VERSION 5.8 ;
BUSBITCHARS "[]" ;
DIVIDERCHAR "/" ;
UNITS
    DATABASE MICRONS 1000 ;
END UNITS

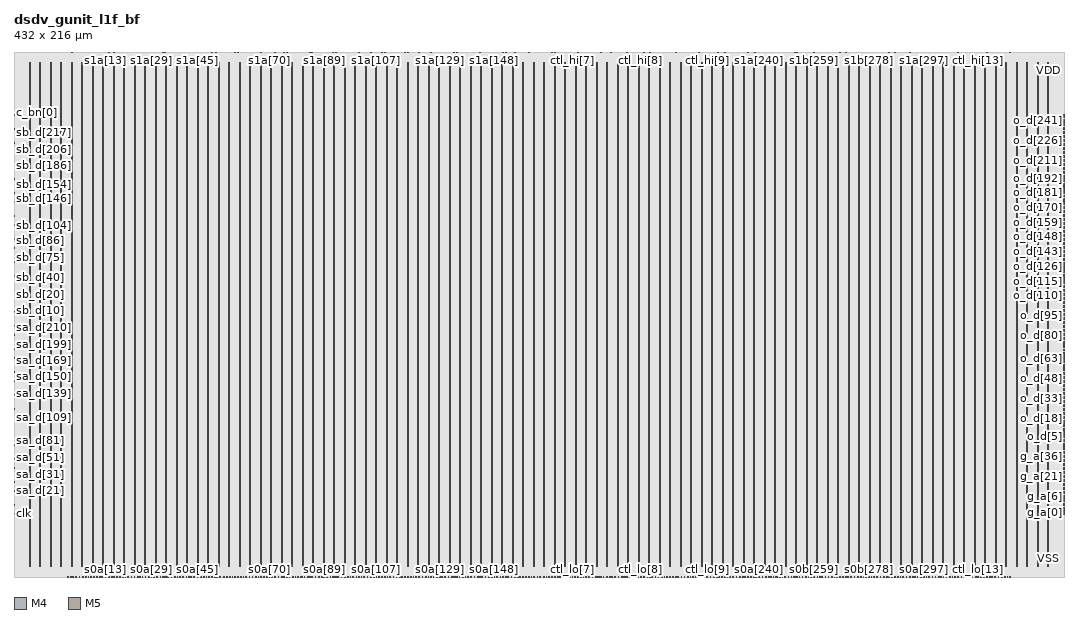
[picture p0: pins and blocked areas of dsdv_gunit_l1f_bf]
MACRO dsdv_gunit_l1f_bf
  FOREIGN dsdv_gunit_l1f_bf 0 0 ;
  CLASS BLOCK ;
  SIZE 432 BY 216 ;
  PIN c_bn[0]
    DIRECTION INPUT ;
    USE SIGNAL ;
    PORT
      LAYER M4 ;
        RECT  0 187.68 0.084 187.704 ;
    END
  END c_bn[0]
  PIN c_bn[1]
    DIRECTION INPUT ;
    USE SIGNAL ;
    PORT
      LAYER M4 ;
        RECT  0 188.064 0.084 188.088 ;
    END
  END c_bn[1]
  PIN c_bn[2]
    DIRECTION INPUT ;
    USE SIGNAL ;
    PORT
      LAYER M4 ;
        RECT  0 188.4 0.084 188.424 ;
    END
  END c_bn[2]
  PIN c_fw
    DIRECTION INPUT ;
    USE SIGNAL ;
    PORT
      LAYER M4 ;
        RECT  0 187.008 0.084 187.032 ;
    END
  END c_fw
  PIN c_go
    DIRECTION INPUT ;
    USE SIGNAL ;
    PORT
      LAYER M4 ;
        RECT  0 186.672 0.084 186.696 ;
    END
  END c_go
  PIN c_l
    DIRECTION INPUT ;
    USE SIGNAL ;
    PORT
      LAYER M4 ;
        RECT  0 187.344 0.084 187.368 ;
    END
  END c_l
  PIN c_lvn[0]
    DIRECTION INPUT ;
    USE SIGNAL ;
    PORT
      LAYER M4 ;
        RECT  0 188.736 0.084 188.76 ;
    END
  END c_lvn[0]
  PIN c_lvn[1]
    DIRECTION INPUT ;
    USE SIGNAL ;
    PORT
      LAYER M4 ;
        RECT  0 189.072 0.084 189.096 ;
    END
  END c_lvn[1]
  PIN c_lvn[2]
    DIRECTION INPUT ;
    USE SIGNAL ;
    PORT
      LAYER M4 ;
        RECT  0 189.408 0.084 189.432 ;
    END
  END c_lvn[2]
  PIN c_lvn[3]
    DIRECTION INPUT ;
    USE SIGNAL ;
    PORT
      LAYER M4 ;
        RECT  0 189.744 0.084 189.768 ;
    END
  END c_lvn[3]
  PIN c_lvn[4]
    DIRECTION INPUT ;
    USE SIGNAL ;
    PORT
      LAYER M4 ;
        RECT  0 190.08 0.084 190.104 ;
    END
  END c_lvn[4]
  PIN clk
    DIRECTION INPUT ;
    USE SIGNAL ;
    PORT
      LAYER M4 ;
        RECT  0 25.92 0.084 25.944 ;
    END
  END clk
  PIN ctl_hi[0]
    DIRECTION OUTPUT ;
    USE SIGNAL ;
    PORT
      LAYER M5 ;
        RECT  35.472 215.916 35.496 216 ;
    END
  END ctl_hi[0]
  PIN ctl_hi[10]
    DIRECTION OUTPUT ;
    USE SIGNAL ;
    PORT
      LAYER M5 ;
        RECT  313.2 215.916 313.224 216 ;
    END
  END ctl_hi[10]
  PIN ctl_hi[11]
    DIRECTION OUTPUT ;
    USE SIGNAL ;
    PORT
      LAYER M5 ;
        RECT  340.944 215.916 340.968 216 ;
    END
  END ctl_hi[11]
  PIN ctl_hi[12]
    DIRECTION OUTPUT ;
    USE SIGNAL ;
    PORT
      LAYER M5 ;
        RECT  368.736 215.916 368.76 216 ;
    END
  END ctl_hi[12]
  PIN ctl_hi[13]
    DIRECTION OUTPUT ;
    USE SIGNAL ;
    PORT
      LAYER M5 ;
        RECT  396.48 215.916 396.504 216 ;
    END
  END ctl_hi[13]
  PIN ctl_hi[1]
    DIRECTION OUTPUT ;
    USE SIGNAL ;
    PORT
      LAYER M5 ;
        RECT  63.264 215.916 63.288 216 ;
    END
  END ctl_hi[1]
  PIN ctl_hi[2]
    DIRECTION OUTPUT ;
    USE SIGNAL ;
    PORT
      LAYER M5 ;
        RECT  91.008 215.916 91.032 216 ;
    END
  END ctl_hi[2]
  PIN ctl_hi[3]
    DIRECTION OUTPUT ;
    USE SIGNAL ;
    PORT
      LAYER M5 ;
        RECT  118.8 215.916 118.824 216 ;
    END
  END ctl_hi[3]
  PIN ctl_hi[4]
    DIRECTION OUTPUT ;
    USE SIGNAL ;
    PORT
      LAYER M5 ;
        RECT  146.544 215.916 146.568 216 ;
    END
  END ctl_hi[4]
  PIN ctl_hi[5]
    DIRECTION OUTPUT ;
    USE SIGNAL ;
    PORT
      LAYER M5 ;
        RECT  174.336 215.916 174.36 216 ;
    END
  END ctl_hi[5]
  PIN ctl_hi[6]
    DIRECTION OUTPUT ;
    USE SIGNAL ;
    PORT
      LAYER M5 ;
        RECT  202.08 215.916 202.104 216 ;
    END
  END ctl_hi[6]
  PIN ctl_hi[7]
    DIRECTION OUTPUT ;
    USE SIGNAL ;
    PORT
      LAYER M5 ;
        RECT  229.872 215.916 229.896 216 ;
    END
  END ctl_hi[7]
  PIN ctl_hi[8]
    DIRECTION OUTPUT ;
    USE SIGNAL ;
    PORT
      LAYER M5 ;
        RECT  257.664 215.916 257.688 216 ;
    END
  END ctl_hi[8]
  PIN ctl_hi[9]
    DIRECTION OUTPUT ;
    USE SIGNAL ;
    PORT
      LAYER M5 ;
        RECT  285.408 215.916 285.432 216 ;
    END
  END ctl_hi[9]
  PIN ctl_lo[0]
    DIRECTION OUTPUT ;
    USE SIGNAL ;
    PORT
      LAYER M5 ;
        RECT  35.472 0 35.496 0.084 ;
    END
  END ctl_lo[0]
  PIN ctl_lo[10]
    DIRECTION OUTPUT ;
    USE SIGNAL ;
    PORT
      LAYER M5 ;
        RECT  313.2 0 313.224 0.084 ;
    END
  END ctl_lo[10]
  PIN ctl_lo[11]
    DIRECTION OUTPUT ;
    USE SIGNAL ;
    PORT
      LAYER M5 ;
        RECT  340.944 0 340.968 0.084 ;
    END
  END ctl_lo[11]
  PIN ctl_lo[12]
    DIRECTION OUTPUT ;
    USE SIGNAL ;
    PORT
      LAYER M5 ;
        RECT  368.736 0 368.76 0.084 ;
    END
  END ctl_lo[12]
  PIN ctl_lo[13]
    DIRECTION OUTPUT ;
    USE SIGNAL ;
    PORT
      LAYER M5 ;
        RECT  396.48 0 396.504 0.084 ;
    END
  END ctl_lo[13]
  PIN ctl_lo[1]
    DIRECTION OUTPUT ;
    USE SIGNAL ;
    PORT
      LAYER M5 ;
        RECT  63.264 0 63.288 0.084 ;
    END
  END ctl_lo[1]
  PIN ctl_lo[2]
    DIRECTION OUTPUT ;
    USE SIGNAL ;
    PORT
      LAYER M5 ;
        RECT  91.008 0 91.032 0.084 ;
    END
  END ctl_lo[2]
  PIN ctl_lo[3]
    DIRECTION OUTPUT ;
    USE SIGNAL ;
    PORT
      LAYER M5 ;
        RECT  118.8 0 118.824 0.084 ;
    END
  END ctl_lo[3]
  PIN ctl_lo[4]
    DIRECTION OUTPUT ;
    USE SIGNAL ;
    PORT
      LAYER M5 ;
        RECT  146.544 0 146.568 0.084 ;
    END
  END ctl_lo[4]
  PIN ctl_lo[5]
    DIRECTION OUTPUT ;
    USE SIGNAL ;
    PORT
      LAYER M5 ;
        RECT  174.336 0 174.36 0.084 ;
    END
  END ctl_lo[5]
  PIN ctl_lo[6]
    DIRECTION OUTPUT ;
    USE SIGNAL ;
    PORT
      LAYER M5 ;
        RECT  202.08 0 202.104 0.084 ;
    END
  END ctl_lo[6]
  PIN ctl_lo[7]
    DIRECTION OUTPUT ;
    USE SIGNAL ;
    PORT
      LAYER M5 ;
        RECT  229.872 0 229.896 0.084 ;
    END
  END ctl_lo[7]
  PIN ctl_lo[8]
    DIRECTION OUTPUT ;
    USE SIGNAL ;
    PORT
      LAYER M5 ;
        RECT  257.664 0 257.688 0.084 ;
    END
  END ctl_lo[8]
  PIN ctl_lo[9]
    DIRECTION OUTPUT ;
    USE SIGNAL ;
    PORT
      LAYER M5 ;
        RECT  285.408 0 285.432 0.084 ;
    END
  END ctl_lo[9]
  PIN g_a[0]
    DIRECTION INPUT ;
    USE SIGNAL ;
    PORT
      LAYER M4 ;
        RECT  431.916 29.76 432 29.784 ;
    END
  END g_a[0]
  PIN g_a[10]
    DIRECTION INPUT ;
    USE SIGNAL ;
    PORT
      LAYER M4 ;
        RECT  431.916 35.28 432 35.304 ;
    END
  END g_a[10]
  PIN g_a[11]
    DIRECTION INPUT ;
    USE SIGNAL ;
    PORT
      LAYER M4 ;
        RECT  431.916 35.808 432 35.832 ;
    END
  END g_a[11]
  PIN g_a[12]
    DIRECTION INPUT ;
    USE SIGNAL ;
    PORT
      LAYER M4 ;
        RECT  431.916 36.384 432 36.408 ;
    END
  END g_a[12]
  PIN g_a[13]
    DIRECTION INPUT ;
    USE SIGNAL ;
    PORT
      LAYER M4 ;
        RECT  431.916 36.912 432 36.936 ;
    END
  END g_a[13]
  PIN g_a[14]
    DIRECTION INPUT ;
    USE SIGNAL ;
    PORT
      LAYER M4 ;
        RECT  431.916 37.488 432 37.512 ;
    END
  END g_a[14]
  PIN g_a[15]
    DIRECTION INPUT ;
    USE SIGNAL ;
    PORT
      LAYER M4 ;
        RECT  431.916 38.016 432 38.04 ;
    END
  END g_a[15]
  PIN g_a[16]
    DIRECTION INPUT ;
    USE SIGNAL ;
    PORT
      LAYER M4 ;
        RECT  431.916 38.592 432 38.616 ;
    END
  END g_a[16]
  PIN g_a[17]
    DIRECTION INPUT ;
    USE SIGNAL ;
    PORT
      LAYER M4 ;
        RECT  431.916 39.12 432 39.144 ;
    END
  END g_a[17]
  PIN g_a[18]
    DIRECTION INPUT ;
    USE SIGNAL ;
    PORT
      LAYER M4 ;
        RECT  431.916 39.696 432 39.72 ;
    END
  END g_a[18]
  PIN g_a[19]
    DIRECTION INPUT ;
    USE SIGNAL ;
    PORT
      LAYER M4 ;
        RECT  431.916 40.224 432 40.248 ;
    END
  END g_a[19]
  PIN g_a[1]
    DIRECTION INPUT ;
    USE SIGNAL ;
    PORT
      LAYER M4 ;
        RECT  431.916 30.336 432 30.36 ;
    END
  END g_a[1]
  PIN g_a[20]
    DIRECTION INPUT ;
    USE SIGNAL ;
    PORT
      LAYER M4 ;
        RECT  431.916 40.8 432 40.824 ;
    END
  END g_a[20]
  PIN g_a[21]
    DIRECTION INPUT ;
    USE SIGNAL ;
    PORT
      LAYER M4 ;
        RECT  431.916 41.328 432 41.352 ;
    END
  END g_a[21]
  PIN g_a[22]
    DIRECTION INPUT ;
    USE SIGNAL ;
    PORT
      LAYER M4 ;
        RECT  431.916 41.904 432 41.928 ;
    END
  END g_a[22]
  PIN g_a[23]
    DIRECTION INPUT ;
    USE SIGNAL ;
    PORT
      LAYER M4 ;
        RECT  431.916 42.432 432 42.456 ;
    END
  END g_a[23]
  PIN g_a[24]
    DIRECTION INPUT ;
    USE SIGNAL ;
    PORT
      LAYER M4 ;
        RECT  431.916 43.008 432 43.032 ;
    END
  END g_a[24]
  PIN g_a[25]
    DIRECTION INPUT ;
    USE SIGNAL ;
    PORT
      LAYER M4 ;
        RECT  431.916 43.536 432 43.56 ;
    END
  END g_a[25]
  PIN g_a[26]
    DIRECTION INPUT ;
    USE SIGNAL ;
    PORT
      LAYER M4 ;
        RECT  431.916 44.064 432 44.088 ;
    END
  END g_a[26]
  PIN g_a[27]
    DIRECTION INPUT ;
    USE SIGNAL ;
    PORT
      LAYER M4 ;
        RECT  431.916 44.64 432 44.664 ;
    END
  END g_a[27]
  PIN g_a[28]
    DIRECTION INPUT ;
    USE SIGNAL ;
    PORT
      LAYER M4 ;
        RECT  431.916 45.168 432 45.192 ;
    END
  END g_a[28]
  PIN g_a[29]
    DIRECTION INPUT ;
    USE SIGNAL ;
    PORT
      LAYER M4 ;
        RECT  431.916 45.744 432 45.768 ;
    END
  END g_a[29]
  PIN g_a[2]
    DIRECTION INPUT ;
    USE SIGNAL ;
    PORT
      LAYER M4 ;
        RECT  431.916 30.864 432 30.888 ;
    END
  END g_a[2]
  PIN g_a[30]
    DIRECTION INPUT ;
    USE SIGNAL ;
    PORT
      LAYER M4 ;
        RECT  431.916 46.272 432 46.296 ;
    END
  END g_a[30]
  PIN g_a[31]
    DIRECTION INPUT ;
    USE SIGNAL ;
    PORT
      LAYER M4 ;
        RECT  431.916 46.848 432 46.872 ;
    END
  END g_a[31]
  PIN g_a[32]
    DIRECTION INPUT ;
    USE SIGNAL ;
    PORT
      LAYER M4 ;
        RECT  431.916 47.376 432 47.4 ;
    END
  END g_a[32]
  PIN g_a[33]
    DIRECTION INPUT ;
    USE SIGNAL ;
    PORT
      LAYER M4 ;
        RECT  431.916 47.952 432 47.976 ;
    END
  END g_a[33]
  PIN g_a[34]
    DIRECTION INPUT ;
    USE SIGNAL ;
    PORT
      LAYER M4 ;
        RECT  431.916 48.48 432 48.504 ;
    END
  END g_a[34]
  PIN g_a[35]
    DIRECTION INPUT ;
    USE SIGNAL ;
    PORT
      LAYER M4 ;
        RECT  431.916 49.056 432 49.08 ;
    END
  END g_a[35]
  PIN g_a[36]
    DIRECTION INPUT ;
    USE SIGNAL ;
    PORT
      LAYER M4 ;
        RECT  431.916 49.584 432 49.608 ;
    END
  END g_a[36]
  PIN g_a[37]
    DIRECTION INPUT ;
    USE SIGNAL ;
    PORT
      LAYER M4 ;
        RECT  431.916 50.16 432 50.184 ;
    END
  END g_a[37]
  PIN g_a[38]
    DIRECTION INPUT ;
    USE SIGNAL ;
    PORT
      LAYER M4 ;
        RECT  431.916 50.688 432 50.712 ;
    END
  END g_a[38]
  PIN g_a[39]
    DIRECTION INPUT ;
    USE SIGNAL ;
    PORT
      LAYER M4 ;
        RECT  431.916 51.264 432 51.288 ;
    END
  END g_a[39]
  PIN g_a[3]
    DIRECTION INPUT ;
    USE SIGNAL ;
    PORT
      LAYER M4 ;
        RECT  431.916 31.44 432 31.464 ;
    END
  END g_a[3]
  PIN g_a[40]
    DIRECTION INPUT ;
    USE SIGNAL ;
    PORT
      LAYER M4 ;
        RECT  431.916 51.792 432 51.816 ;
    END
  END g_a[40]
  PIN g_a[41]
    DIRECTION INPUT ;
    USE SIGNAL ;
    PORT
      LAYER M4 ;
        RECT  431.916 52.368 432 52.392 ;
    END
  END g_a[41]
  PIN g_a[4]
    DIRECTION INPUT ;
    USE SIGNAL ;
    PORT
      LAYER M4 ;
        RECT  431.916 31.968 432 31.992 ;
    END
  END g_a[4]
  PIN g_a[5]
    DIRECTION INPUT ;
    USE SIGNAL ;
    PORT
      LAYER M4 ;
        RECT  431.916 32.496 432 32.52 ;
    END
  END g_a[5]
  PIN g_a[6]
    DIRECTION INPUT ;
    USE SIGNAL ;
    PORT
      LAYER M4 ;
        RECT  431.916 33.072 432 33.096 ;
    END
  END g_a[6]
  PIN g_a[7]
    DIRECTION INPUT ;
    USE SIGNAL ;
    PORT
      LAYER M4 ;
        RECT  431.916 33.6 432 33.624 ;
    END
  END g_a[7]
  PIN g_a[8]
    DIRECTION INPUT ;
    USE SIGNAL ;
    PORT
      LAYER M4 ;
        RECT  431.916 34.176 432 34.2 ;
    END
  END g_a[8]
  PIN g_a[9]
    DIRECTION INPUT ;
    USE SIGNAL ;
    PORT
      LAYER M4 ;
        RECT  431.916 34.704 432 34.728 ;
    END
  END g_a[9]
  PIN g_go
    DIRECTION INPUT ;
    USE SIGNAL ;
    PORT
      LAYER M4 ;
        RECT  431.916 25.92 432 25.944 ;
    END
  END g_go
  PIN g_hit[0]
    DIRECTION INPUT ;
    USE SIGNAL ;
    PORT
      LAYER M4 ;
        RECT  431.916 26.448 432 26.472 ;
    END
  END g_hit[0]
  PIN g_hit[1]
    DIRECTION INPUT ;
    USE SIGNAL ;
    PORT
      LAYER M4 ;
        RECT  431.916 27.024 432 27.048 ;
    END
  END g_hit[1]
  PIN g_hit[2]
    DIRECTION INPUT ;
    USE SIGNAL ;
    PORT
      LAYER M4 ;
        RECT  431.916 27.552 432 27.576 ;
    END
  END g_hit[2]
  PIN g_hit[3]
    DIRECTION INPUT ;
    USE SIGNAL ;
    PORT
      LAYER M4 ;
        RECT  431.916 28.128 432 28.152 ;
    END
  END g_hit[3]
  PIN g_hit[4]
    DIRECTION INPUT ;
    USE SIGNAL ;
    PORT
      LAYER M4 ;
        RECT  431.916 28.656 432 28.68 ;
    END
  END g_hit[4]
  PIN g_hit[5]
    DIRECTION INPUT ;
    USE SIGNAL ;
    PORT
      LAYER M4 ;
        RECT  431.916 29.232 432 29.256 ;
    END
  END g_hit[5]
  PIN o_d[0]
    DIRECTION OUTPUT ;
    USE SIGNAL ;
    PORT
      LAYER M4 ;
        RECT  431.916 55.104 432 55.128 ;
    END
  END o_d[0]
  PIN o_d[100]
    DIRECTION OUTPUT ;
    USE SIGNAL ;
    PORT
      LAYER M4 ;
        RECT  431.916 110.208 432 110.232 ;
    END
  END o_d[100]
  PIN o_d[101]
    DIRECTION OUTPUT ;
    USE SIGNAL ;
    PORT
      LAYER M4 ;
        RECT  431.916 110.736 432 110.76 ;
    END
  END o_d[101]
  PIN o_d[102]
    DIRECTION OUTPUT ;
    USE SIGNAL ;
    PORT
      LAYER M4 ;
        RECT  431.916 111.312 432 111.336 ;
    END
  END o_d[102]
  PIN o_d[103]
    DIRECTION OUTPUT ;
    USE SIGNAL ;
    PORT
      LAYER M4 ;
        RECT  431.916 111.84 432 111.864 ;
    END
  END o_d[103]
  PIN o_d[104]
    DIRECTION OUTPUT ;
    USE SIGNAL ;
    PORT
      LAYER M4 ;
        RECT  431.916 112.416 432 112.44 ;
    END
  END o_d[104]
  PIN o_d[105]
    DIRECTION OUTPUT ;
    USE SIGNAL ;
    PORT
      LAYER M4 ;
        RECT  431.916 112.944 432 112.968 ;
    END
  END o_d[105]
  PIN o_d[106]
    DIRECTION OUTPUT ;
    USE SIGNAL ;
    PORT
      LAYER M4 ;
        RECT  431.916 113.52 432 113.544 ;
    END
  END o_d[106]
  PIN o_d[107]
    DIRECTION OUTPUT ;
    USE SIGNAL ;
    PORT
      LAYER M4 ;
        RECT  431.916 114.048 432 114.072 ;
    END
  END o_d[107]
  PIN o_d[108]
    DIRECTION OUTPUT ;
    USE SIGNAL ;
    PORT
      LAYER M4 ;
        RECT  431.916 114.576 432 114.6 ;
    END
  END o_d[108]
  PIN o_d[109]
    DIRECTION OUTPUT ;
    USE SIGNAL ;
    PORT
      LAYER M4 ;
        RECT  431.916 115.152 432 115.176 ;
    END
  END o_d[109]
  PIN o_d[10]
    DIRECTION OUTPUT ;
    USE SIGNAL ;
    PORT
      LAYER M4 ;
        RECT  431.916 60.624 432 60.648 ;
    END
  END o_d[10]
  PIN o_d[110]
    DIRECTION OUTPUT ;
    USE SIGNAL ;
    PORT
      LAYER M4 ;
        RECT  431.916 115.68 432 115.704 ;
    END
  END o_d[110]
  PIN o_d[111]
    DIRECTION OUTPUT ;
    USE SIGNAL ;
    PORT
      LAYER M4 ;
        RECT  431.916 116.256 432 116.28 ;
    END
  END o_d[111]
  PIN o_d[112]
    DIRECTION OUTPUT ;
    USE SIGNAL ;
    PORT
      LAYER M4 ;
        RECT  431.916 116.784 432 116.808 ;
    END
  END o_d[112]
  PIN o_d[113]
    DIRECTION OUTPUT ;
    USE SIGNAL ;
    PORT
      LAYER M4 ;
        RECT  431.916 117.36 432 117.384 ;
    END
  END o_d[113]
  PIN o_d[114]
    DIRECTION OUTPUT ;
    USE SIGNAL ;
    PORT
      LAYER M4 ;
        RECT  431.916 117.888 432 117.912 ;
    END
  END o_d[114]
  PIN o_d[115]
    DIRECTION OUTPUT ;
    USE SIGNAL ;
    PORT
      LAYER M4 ;
        RECT  431.916 118.464 432 118.488 ;
    END
  END o_d[115]
  PIN o_d[116]
    DIRECTION OUTPUT ;
    USE SIGNAL ;
    PORT
      LAYER M4 ;
        RECT  431.916 118.992 432 119.016 ;
    END
  END o_d[116]
  PIN o_d[117]
    DIRECTION OUTPUT ;
    USE SIGNAL ;
    PORT
      LAYER M4 ;
        RECT  431.916 119.568 432 119.592 ;
    END
  END o_d[117]
  PIN o_d[118]
    DIRECTION OUTPUT ;
    USE SIGNAL ;
    PORT
      LAYER M4 ;
        RECT  431.916 120.096 432 120.12 ;
    END
  END o_d[118]
  PIN o_d[119]
    DIRECTION OUTPUT ;
    USE SIGNAL ;
    PORT
      LAYER M4 ;
        RECT  431.916 120.672 432 120.696 ;
    END
  END o_d[119]
  PIN o_d[11]
    DIRECTION OUTPUT ;
    USE SIGNAL ;
    PORT
      LAYER M4 ;
        RECT  431.916 61.152 432 61.176 ;
    END
  END o_d[11]
  PIN o_d[120]
    DIRECTION OUTPUT ;
    USE SIGNAL ;
    PORT
      LAYER M4 ;
        RECT  431.916 121.2 432 121.224 ;
    END
  END o_d[120]
  PIN o_d[121]
    DIRECTION OUTPUT ;
    USE SIGNAL ;
    PORT
      LAYER M4 ;
        RECT  431.916 121.776 432 121.8 ;
    END
  END o_d[121]
  PIN o_d[122]
    DIRECTION OUTPUT ;
    USE SIGNAL ;
    PORT
      LAYER M4 ;
        RECT  431.916 122.304 432 122.328 ;
    END
  END o_d[122]
  PIN o_d[123]
    DIRECTION OUTPUT ;
    USE SIGNAL ;
    PORT
      LAYER M4 ;
        RECT  431.916 122.88 432 122.904 ;
    END
  END o_d[123]
  PIN o_d[124]
    DIRECTION OUTPUT ;
    USE SIGNAL ;
    PORT
      LAYER M4 ;
        RECT  431.916 123.408 432 123.432 ;
    END
  END o_d[124]
  PIN o_d[125]
    DIRECTION OUTPUT ;
    USE SIGNAL ;
    PORT
      LAYER M4 ;
        RECT  431.916 123.984 432 124.008 ;
    END
  END o_d[125]
  PIN o_d[126]
    DIRECTION OUTPUT ;
    USE SIGNAL ;
    PORT
      LAYER M4 ;
        RECT  431.916 124.512 432 124.536 ;
    END
  END o_d[126]
  PIN o_d[127]
    DIRECTION OUTPUT ;
    USE SIGNAL ;
    PORT
      LAYER M4 ;
        RECT  431.916 125.088 432 125.112 ;
    END
  END o_d[127]
  PIN o_d[128]
    DIRECTION OUTPUT ;
    USE SIGNAL ;
    PORT
      LAYER M4 ;
        RECT  431.916 125.616 432 125.64 ;
    END
  END o_d[128]
  PIN o_d[129]
    DIRECTION OUTPUT ;
    USE SIGNAL ;
    PORT
      LAYER M4 ;
        RECT  431.916 126.144 432 126.168 ;
    END
  END o_d[129]
  PIN o_d[12]
    DIRECTION OUTPUT ;
    USE SIGNAL ;
    PORT
      LAYER M4 ;
        RECT  431.916 61.728 432 61.752 ;
    END
  END o_d[12]
  PIN o_d[130]
    DIRECTION OUTPUT ;
    USE SIGNAL ;
    PORT
      LAYER M4 ;
        RECT  431.916 126.72 432 126.744 ;
    END
  END o_d[130]
  PIN o_d[131]
    DIRECTION OUTPUT ;
    USE SIGNAL ;
    PORT
      LAYER M4 ;
        RECT  431.916 127.248 432 127.272 ;
    END
  END o_d[131]
  PIN o_d[132]
    DIRECTION OUTPUT ;
    USE SIGNAL ;
    PORT
      LAYER M4 ;
        RECT  431.916 127.824 432 127.848 ;
    END
  END o_d[132]
  PIN o_d[133]
    DIRECTION OUTPUT ;
    USE SIGNAL ;
    PORT
      LAYER M4 ;
        RECT  431.916 128.352 432 128.376 ;
    END
  END o_d[133]
  PIN o_d[134]
    DIRECTION OUTPUT ;
    USE SIGNAL ;
    PORT
      LAYER M4 ;
        RECT  431.916 128.928 432 128.952 ;
    END
  END o_d[134]
  PIN o_d[135]
    DIRECTION OUTPUT ;
    USE SIGNAL ;
    PORT
      LAYER M4 ;
        RECT  431.916 129.456 432 129.48 ;
    END
  END o_d[135]
  PIN o_d[136]
    DIRECTION OUTPUT ;
    USE SIGNAL ;
    PORT
      LAYER M4 ;
        RECT  431.916 130.032 432 130.056 ;
    END
  END o_d[136]
  PIN o_d[137]
    DIRECTION OUTPUT ;
    USE SIGNAL ;
    PORT
      LAYER M4 ;
        RECT  431.916 130.56 432 130.584 ;
    END
  END o_d[137]
  PIN o_d[138]
    DIRECTION OUTPUT ;
    USE SIGNAL ;
    PORT
      LAYER M4 ;
        RECT  431.916 131.136 432 131.16 ;
    END
  END o_d[138]
  PIN o_d[139]
    DIRECTION OUTPUT ;
    USE SIGNAL ;
    PORT
      LAYER M4 ;
        RECT  431.916 131.664 432 131.688 ;
    END
  END o_d[139]
  PIN o_d[13]
    DIRECTION OUTPUT ;
    USE SIGNAL ;
    PORT
      LAYER M4 ;
        RECT  431.916 62.256 432 62.28 ;
    END
  END o_d[13]
  PIN o_d[140]
    DIRECTION OUTPUT ;
    USE SIGNAL ;
    PORT
      LAYER M4 ;
        RECT  431.916 132.24 432 132.264 ;
    END
  END o_d[140]
  PIN o_d[141]
    DIRECTION OUTPUT ;
    USE SIGNAL ;
    PORT
      LAYER M4 ;
        RECT  431.916 132.768 432 132.792 ;
    END
  END o_d[141]
  PIN o_d[142]
    DIRECTION OUTPUT ;
    USE SIGNAL ;
    PORT
      LAYER M4 ;
        RECT  431.916 133.344 432 133.368 ;
    END
  END o_d[142]
  PIN o_d[143]
    DIRECTION OUTPUT ;
    USE SIGNAL ;
    PORT
      LAYER M4 ;
        RECT  431.916 133.872 432 133.896 ;
    END
  END o_d[143]
  PIN o_d[144]
    DIRECTION OUTPUT ;
    USE SIGNAL ;
    PORT
      LAYER M4 ;
        RECT  431.916 134.448 432 134.472 ;
    END
  END o_d[144]
  PIN o_d[145]
    DIRECTION OUTPUT ;
    USE SIGNAL ;
    PORT
      LAYER M4 ;
        RECT  431.916 134.976 432 135 ;
    END
  END o_d[145]
  PIN o_d[146]
    DIRECTION OUTPUT ;
    USE SIGNAL ;
    PORT
      LAYER M4 ;
        RECT  431.916 135.552 432 135.576 ;
    END
  END o_d[146]
  PIN o_d[147]
    DIRECTION OUTPUT ;
    USE SIGNAL ;
    PORT
      LAYER M4 ;
        RECT  431.916 136.08 432 136.104 ;
    END
  END o_d[147]
  PIN o_d[148]
    DIRECTION OUTPUT ;
    USE SIGNAL ;
    PORT
      LAYER M4 ;
        RECT  431.916 136.656 432 136.68 ;
    END
  END o_d[148]
  PIN o_d[149]
    DIRECTION OUTPUT ;
    USE SIGNAL ;
    PORT
      LAYER M4 ;
        RECT  431.916 137.184 432 137.208 ;
    END
  END o_d[149]
  PIN o_d[14]
    DIRECTION OUTPUT ;
    USE SIGNAL ;
    PORT
      LAYER M4 ;
        RECT  431.916 62.832 432 62.856 ;
    END
  END o_d[14]
  PIN o_d[150]
    DIRECTION OUTPUT ;
    USE SIGNAL ;
    PORT
      LAYER M4 ;
        RECT  431.916 137.712 432 137.736 ;
    END
  END o_d[150]
  PIN o_d[151]
    DIRECTION OUTPUT ;
    USE SIGNAL ;
    PORT
      LAYER M4 ;
        RECT  431.916 138.288 432 138.312 ;
    END
  END o_d[151]
  PIN o_d[152]
    DIRECTION OUTPUT ;
    USE SIGNAL ;
    PORT
      LAYER M4 ;
        RECT  431.916 138.816 432 138.84 ;
    END
  END o_d[152]
  PIN o_d[153]
    DIRECTION OUTPUT ;
    USE SIGNAL ;
    PORT
      LAYER M4 ;
        RECT  431.916 139.392 432 139.416 ;
    END
  END o_d[153]
  PIN o_d[154]
    DIRECTION OUTPUT ;
    USE SIGNAL ;
    PORT
      LAYER M4 ;
        RECT  431.916 139.92 432 139.944 ;
    END
  END o_d[154]
  PIN o_d[155]
    DIRECTION OUTPUT ;
    USE SIGNAL ;
    PORT
      LAYER M4 ;
        RECT  431.916 140.496 432 140.52 ;
    END
  END o_d[155]
  PIN o_d[156]
    DIRECTION OUTPUT ;
    USE SIGNAL ;
    PORT
      LAYER M4 ;
        RECT  431.916 141.024 432 141.048 ;
    END
  END o_d[156]
  PIN o_d[157]
    DIRECTION OUTPUT ;
    USE SIGNAL ;
    PORT
      LAYER M4 ;
        RECT  431.916 141.6 432 141.624 ;
    END
  END o_d[157]
  PIN o_d[158]
    DIRECTION OUTPUT ;
    USE SIGNAL ;
    PORT
      LAYER M4 ;
        RECT  431.916 142.128 432 142.152 ;
    END
  END o_d[158]
  PIN o_d[159]
    DIRECTION OUTPUT ;
    USE SIGNAL ;
    PORT
      LAYER M4 ;
        RECT  431.916 142.704 432 142.728 ;
    END
  END o_d[159]
  PIN o_d[15]
    DIRECTION OUTPUT ;
    USE SIGNAL ;
    PORT
      LAYER M4 ;
        RECT  431.916 63.36 432 63.384 ;
    END
  END o_d[15]
  PIN o_d[160]
    DIRECTION OUTPUT ;
    USE SIGNAL ;
    PORT
      LAYER M4 ;
        RECT  431.916 143.232 432 143.256 ;
    END
  END o_d[160]
  PIN o_d[161]
    DIRECTION OUTPUT ;
    USE SIGNAL ;
    PORT
      LAYER M4 ;
        RECT  431.916 143.808 432 143.832 ;
    END
  END o_d[161]
  PIN o_d[162]
    DIRECTION OUTPUT ;
    USE SIGNAL ;
    PORT
      LAYER M4 ;
        RECT  431.916 144.336 432 144.36 ;
    END
  END o_d[162]
  PIN o_d[163]
    DIRECTION OUTPUT ;
    USE SIGNAL ;
    PORT
      LAYER M4 ;
        RECT  431.916 144.912 432 144.936 ;
    END
  END o_d[163]
  PIN o_d[164]
    DIRECTION OUTPUT ;
    USE SIGNAL ;
    PORT
      LAYER M4 ;
        RECT  431.916 145.44 432 145.464 ;
    END
  END o_d[164]
  PIN o_d[165]
    DIRECTION OUTPUT ;
    USE SIGNAL ;
    PORT
      LAYER M4 ;
        RECT  431.916 146.016 432 146.04 ;
    END
  END o_d[165]
  PIN o_d[166]
    DIRECTION OUTPUT ;
    USE SIGNAL ;
    PORT
      LAYER M4 ;
        RECT  431.916 146.544 432 146.568 ;
    END
  END o_d[166]
  PIN o_d[167]
    DIRECTION OUTPUT ;
    USE SIGNAL ;
    PORT
      LAYER M4 ;
        RECT  431.916 147.12 432 147.144 ;
    END
  END o_d[167]
  PIN o_d[168]
    DIRECTION OUTPUT ;
    USE SIGNAL ;
    PORT
      LAYER M4 ;
        RECT  431.916 147.648 432 147.672 ;
    END
  END o_d[168]
  PIN o_d[169]
    DIRECTION OUTPUT ;
    USE SIGNAL ;
    PORT
      LAYER M4 ;
        RECT  431.916 148.224 432 148.248 ;
    END
  END o_d[169]
  PIN o_d[16]
    DIRECTION OUTPUT ;
    USE SIGNAL ;
    PORT
      LAYER M4 ;
        RECT  431.916 63.936 432 63.96 ;
    END
  END o_d[16]
  PIN o_d[170]
    DIRECTION OUTPUT ;
    USE SIGNAL ;
    PORT
      LAYER M4 ;
        RECT  431.916 148.752 432 148.776 ;
    END
  END o_d[170]
  PIN o_d[171]
    DIRECTION OUTPUT ;
    USE SIGNAL ;
    PORT
      LAYER M4 ;
        RECT  431.916 149.28 432 149.304 ;
    END
  END o_d[171]
  PIN o_d[172]
    DIRECTION OUTPUT ;
    USE SIGNAL ;
    PORT
      LAYER M4 ;
        RECT  431.916 149.856 432 149.88 ;
    END
  END o_d[172]
  PIN o_d[173]
    DIRECTION OUTPUT ;
    USE SIGNAL ;
    PORT
      LAYER M4 ;
        RECT  431.916 150.384 432 150.408 ;
    END
  END o_d[173]
  PIN o_d[174]
    DIRECTION OUTPUT ;
    USE SIGNAL ;
    PORT
      LAYER M4 ;
        RECT  431.916 150.96 432 150.984 ;
    END
  END o_d[174]
  PIN o_d[175]
    DIRECTION OUTPUT ;
    USE SIGNAL ;
    PORT
      LAYER M4 ;
        RECT  431.916 151.488 432 151.512 ;
    END
  END o_d[175]
  PIN o_d[176]
    DIRECTION OUTPUT ;
    USE SIGNAL ;
    PORT
      LAYER M4 ;
        RECT  431.916 152.064 432 152.088 ;
    END
  END o_d[176]
  PIN o_d[177]
    DIRECTION OUTPUT ;
    USE SIGNAL ;
    PORT
      LAYER M4 ;
        RECT  431.916 152.592 432 152.616 ;
    END
  END o_d[177]
  PIN o_d[178]
    DIRECTION OUTPUT ;
    USE SIGNAL ;
    PORT
      LAYER M4 ;
        RECT  431.916 153.168 432 153.192 ;
    END
  END o_d[178]
  PIN o_d[179]
    DIRECTION OUTPUT ;
    USE SIGNAL ;
    PORT
      LAYER M4 ;
        RECT  431.916 153.696 432 153.72 ;
    END
  END o_d[179]
  PIN o_d[17]
    DIRECTION OUTPUT ;
    USE SIGNAL ;
    PORT
      LAYER M4 ;
        RECT  431.916 64.464 432 64.488 ;
    END
  END o_d[17]
  PIN o_d[180]
    DIRECTION OUTPUT ;
    USE SIGNAL ;
    PORT
      LAYER M4 ;
        RECT  431.916 154.272 432 154.296 ;
    END
  END o_d[180]
  PIN o_d[181]
    DIRECTION OUTPUT ;
    USE SIGNAL ;
    PORT
      LAYER M4 ;
        RECT  431.916 154.8 432 154.824 ;
    END
  END o_d[181]
  PIN o_d[182]
    DIRECTION OUTPUT ;
    USE SIGNAL ;
    PORT
      LAYER M4 ;
        RECT  431.916 155.376 432 155.4 ;
    END
  END o_d[182]
  PIN o_d[183]
    DIRECTION OUTPUT ;
    USE SIGNAL ;
    PORT
      LAYER M4 ;
        RECT  431.916 155.904 432 155.928 ;
    END
  END o_d[183]
  PIN o_d[184]
    DIRECTION OUTPUT ;
    USE SIGNAL ;
    PORT
      LAYER M4 ;
        RECT  431.916 156.48 432 156.504 ;
    END
  END o_d[184]
  PIN o_d[185]
    DIRECTION OUTPUT ;
    USE SIGNAL ;
    PORT
      LAYER M4 ;
        RECT  431.916 157.008 432 157.032 ;
    END
  END o_d[185]
  PIN o_d[186]
    DIRECTION OUTPUT ;
    USE SIGNAL ;
    PORT
      LAYER M4 ;
        RECT  431.916 157.584 432 157.608 ;
    END
  END o_d[186]
  PIN o_d[187]
    DIRECTION OUTPUT ;
    USE SIGNAL ;
    PORT
      LAYER M4 ;
        RECT  431.916 158.112 432 158.136 ;
    END
  END o_d[187]
  PIN o_d[188]
    DIRECTION OUTPUT ;
    USE SIGNAL ;
    PORT
      LAYER M4 ;
        RECT  431.916 158.688 432 158.712 ;
    END
  END o_d[188]
  PIN o_d[189]
    DIRECTION OUTPUT ;
    USE SIGNAL ;
    PORT
      LAYER M4 ;
        RECT  431.916 159.216 432 159.24 ;
    END
  END o_d[189]
  PIN o_d[18]
    DIRECTION OUTPUT ;
    USE SIGNAL ;
    PORT
      LAYER M4 ;
        RECT  431.916 65.04 432 65.064 ;
    END
  END o_d[18]
  PIN o_d[190]
    DIRECTION OUTPUT ;
    USE SIGNAL ;
    PORT
      LAYER M4 ;
        RECT  431.916 159.792 432 159.816 ;
    END
  END o_d[190]
  PIN o_d[191]
    DIRECTION OUTPUT ;
    USE SIGNAL ;
    PORT
      LAYER M4 ;
        RECT  431.916 160.32 432 160.344 ;
    END
  END o_d[191]
  PIN o_d[192]
    DIRECTION OUTPUT ;
    USE SIGNAL ;
    PORT
      LAYER M4 ;
        RECT  431.916 160.848 432 160.872 ;
    END
  END o_d[192]
  PIN o_d[193]
    DIRECTION OUTPUT ;
    USE SIGNAL ;
    PORT
      LAYER M4 ;
        RECT  431.916 161.424 432 161.448 ;
    END
  END o_d[193]
  PIN o_d[194]
    DIRECTION OUTPUT ;
    USE SIGNAL ;
    PORT
      LAYER M4 ;
        RECT  431.916 161.952 432 161.976 ;
    END
  END o_d[194]
  PIN o_d[195]
    DIRECTION OUTPUT ;
    USE SIGNAL ;
    PORT
      LAYER M4 ;
        RECT  431.916 162.528 432 162.552 ;
    END
  END o_d[195]
  PIN o_d[196]
    DIRECTION OUTPUT ;
    USE SIGNAL ;
    PORT
      LAYER M4 ;
        RECT  431.916 163.056 432 163.08 ;
    END
  END o_d[196]
  PIN o_d[197]
    DIRECTION OUTPUT ;
    USE SIGNAL ;
    PORT
      LAYER M4 ;
        RECT  431.916 163.632 432 163.656 ;
    END
  END o_d[197]
  PIN o_d[198]
    DIRECTION OUTPUT ;
    USE SIGNAL ;
    PORT
      LAYER M4 ;
        RECT  431.916 164.16 432 164.184 ;
    END
  END o_d[198]
  PIN o_d[199]
    DIRECTION OUTPUT ;
    USE SIGNAL ;
    PORT
      LAYER M4 ;
        RECT  431.916 164.736 432 164.76 ;
    END
  END o_d[199]
  PIN o_d[19]
    DIRECTION OUTPUT ;
    USE SIGNAL ;
    PORT
      LAYER M4 ;
        RECT  431.916 65.568 432 65.592 ;
    END
  END o_d[19]
  PIN o_d[1]
    DIRECTION OUTPUT ;
    USE SIGNAL ;
    PORT
      LAYER M4 ;
        RECT  431.916 55.632 432 55.656 ;
    END
  END o_d[1]
  PIN o_d[200]
    DIRECTION OUTPUT ;
    USE SIGNAL ;
    PORT
      LAYER M4 ;
        RECT  431.916 165.264 432 165.288 ;
    END
  END o_d[200]
  PIN o_d[201]
    DIRECTION OUTPUT ;
    USE SIGNAL ;
    PORT
      LAYER M4 ;
        RECT  431.916 165.84 432 165.864 ;
    END
  END o_d[201]
  PIN o_d[202]
    DIRECTION OUTPUT ;
    USE SIGNAL ;
    PORT
      LAYER M4 ;
        RECT  431.916 166.368 432 166.392 ;
    END
  END o_d[202]
  PIN o_d[203]
    DIRECTION OUTPUT ;
    USE SIGNAL ;
    PORT
      LAYER M4 ;
        RECT  431.916 166.944 432 166.968 ;
    END
  END o_d[203]
  PIN o_d[204]
    DIRECTION OUTPUT ;
    USE SIGNAL ;
    PORT
      LAYER M4 ;
        RECT  431.916 167.472 432 167.496 ;
    END
  END o_d[204]
  PIN o_d[205]
    DIRECTION OUTPUT ;
    USE SIGNAL ;
    PORT
      LAYER M4 ;
        RECT  431.916 168.048 432 168.072 ;
    END
  END o_d[205]
  PIN o_d[206]
    DIRECTION OUTPUT ;
    USE SIGNAL ;
    PORT
      LAYER M4 ;
        RECT  431.916 168.576 432 168.6 ;
    END
  END o_d[206]
  PIN o_d[207]
    DIRECTION OUTPUT ;
    USE SIGNAL ;
    PORT
      LAYER M4 ;
        RECT  431.916 169.152 432 169.176 ;
    END
  END o_d[207]
  PIN o_d[208]
    DIRECTION OUTPUT ;
    USE SIGNAL ;
    PORT
      LAYER M4 ;
        RECT  431.916 169.68 432 169.704 ;
    END
  END o_d[208]
  PIN o_d[209]
    DIRECTION OUTPUT ;
    USE SIGNAL ;
    PORT
      LAYER M4 ;
        RECT  431.916 170.256 432 170.28 ;
    END
  END o_d[209]
  PIN o_d[20]
    DIRECTION OUTPUT ;
    USE SIGNAL ;
    PORT
      LAYER M4 ;
        RECT  431.916 66.144 432 66.168 ;
    END
  END o_d[20]
  PIN o_d[210]
    DIRECTION OUTPUT ;
    USE SIGNAL ;
    PORT
      LAYER M4 ;
        RECT  431.916 170.784 432 170.808 ;
    END
  END o_d[210]
  PIN o_d[211]
    DIRECTION OUTPUT ;
    USE SIGNAL ;
    PORT
      LAYER M4 ;
        RECT  431.916 171.36 432 171.384 ;
    END
  END o_d[211]
  PIN o_d[212]
    DIRECTION OUTPUT ;
    USE SIGNAL ;
    PORT
      LAYER M4 ;
        RECT  431.916 171.888 432 171.912 ;
    END
  END o_d[212]
  PIN o_d[213]
    DIRECTION OUTPUT ;
    USE SIGNAL ;
    PORT
      LAYER M4 ;
        RECT  431.916 172.464 432 172.488 ;
    END
  END o_d[213]
  PIN o_d[214]
    DIRECTION OUTPUT ;
    USE SIGNAL ;
    PORT
      LAYER M4 ;
        RECT  431.916 172.992 432 173.016 ;
    END
  END o_d[214]
  PIN o_d[215]
    DIRECTION OUTPUT ;
    USE SIGNAL ;
    PORT
      LAYER M4 ;
        RECT  431.916 173.52 432 173.544 ;
    END
  END o_d[215]
  PIN o_d[216]
    DIRECTION OUTPUT ;
    USE SIGNAL ;
    PORT
      LAYER M4 ;
        RECT  431.916 174.096 432 174.12 ;
    END
  END o_d[216]
  PIN o_d[217]
    DIRECTION OUTPUT ;
    USE SIGNAL ;
    PORT
      LAYER M4 ;
        RECT  431.916 174.624 432 174.648 ;
    END
  END o_d[217]
  PIN o_d[218]
    DIRECTION OUTPUT ;
    USE SIGNAL ;
    PORT
      LAYER M4 ;
        RECT  431.916 175.2 432 175.224 ;
    END
  END o_d[218]
  PIN o_d[219]
    DIRECTION OUTPUT ;
    USE SIGNAL ;
    PORT
      LAYER M4 ;
        RECT  431.916 175.728 432 175.752 ;
    END
  END o_d[219]
  PIN o_d[21]
    DIRECTION OUTPUT ;
    USE SIGNAL ;
    PORT
      LAYER M4 ;
        RECT  431.916 66.672 432 66.696 ;
    END
  END o_d[21]
  PIN o_d[220]
    DIRECTION OUTPUT ;
    USE SIGNAL ;
    PORT
      LAYER M4 ;
        RECT  431.916 176.304 432 176.328 ;
    END
  END o_d[220]
  PIN o_d[221]
    DIRECTION OUTPUT ;
    USE SIGNAL ;
    PORT
      LAYER M4 ;
        RECT  431.916 176.832 432 176.856 ;
    END
  END o_d[221]
  PIN o_d[222]
    DIRECTION OUTPUT ;
    USE SIGNAL ;
    PORT
      LAYER M4 ;
        RECT  431.916 177.408 432 177.432 ;
    END
  END o_d[222]
  PIN o_d[223]
    DIRECTION OUTPUT ;
    USE SIGNAL ;
    PORT
      LAYER M4 ;
        RECT  431.916 177.936 432 177.96 ;
    END
  END o_d[223]
  PIN o_d[224]
    DIRECTION OUTPUT ;
    USE SIGNAL ;
    PORT
      LAYER M4 ;
        RECT  431.916 178.512 432 178.536 ;
    END
  END o_d[224]
  PIN o_d[225]
    DIRECTION OUTPUT ;
    USE SIGNAL ;
    PORT
      LAYER M4 ;
        RECT  431.916 179.04 432 179.064 ;
    END
  END o_d[225]
  PIN o_d[226]
    DIRECTION OUTPUT ;
    USE SIGNAL ;
    PORT
      LAYER M4 ;
        RECT  431.916 179.616 432 179.64 ;
    END
  END o_d[226]
  PIN o_d[227]
    DIRECTION OUTPUT ;
    USE SIGNAL ;
    PORT
      LAYER M4 ;
        RECT  431.916 180.144 432 180.168 ;
    END
  END o_d[227]
  PIN o_d[228]
    DIRECTION OUTPUT ;
    USE SIGNAL ;
    PORT
      LAYER M4 ;
        RECT  431.916 180.72 432 180.744 ;
    END
  END o_d[228]
  PIN o_d[229]
    DIRECTION OUTPUT ;
    USE SIGNAL ;
    PORT
      LAYER M4 ;
        RECT  431.916 181.248 432 181.272 ;
    END
  END o_d[229]
  PIN o_d[22]
    DIRECTION OUTPUT ;
    USE SIGNAL ;
    PORT
      LAYER M4 ;
        RECT  431.916 67.2 432 67.224 ;
    END
  END o_d[22]
  PIN o_d[230]
    DIRECTION OUTPUT ;
    USE SIGNAL ;
    PORT
      LAYER M4 ;
        RECT  431.916 181.824 432 181.848 ;
    END
  END o_d[230]
  PIN o_d[231]
    DIRECTION OUTPUT ;
    USE SIGNAL ;
    PORT
      LAYER M4 ;
        RECT  431.916 182.352 432 182.376 ;
    END
  END o_d[231]
  PIN o_d[232]
    DIRECTION OUTPUT ;
    USE SIGNAL ;
    PORT
      LAYER M4 ;
        RECT  431.916 182.928 432 182.952 ;
    END
  END o_d[232]
  PIN o_d[233]
    DIRECTION OUTPUT ;
    USE SIGNAL ;
    PORT
      LAYER M4 ;
        RECT  431.916 183.456 432 183.48 ;
    END
  END o_d[233]
  PIN o_d[234]
    DIRECTION OUTPUT ;
    USE SIGNAL ;
    PORT
      LAYER M4 ;
        RECT  431.916 184.032 432 184.056 ;
    END
  END o_d[234]
  PIN o_d[235]
    DIRECTION OUTPUT ;
    USE SIGNAL ;
    PORT
      LAYER M4 ;
        RECT  431.916 184.56 432 184.584 ;
    END
  END o_d[235]
  PIN o_d[236]
    DIRECTION OUTPUT ;
    USE SIGNAL ;
    PORT
      LAYER M4 ;
        RECT  431.916 185.088 432 185.112 ;
    END
  END o_d[236]
  PIN o_d[237]
    DIRECTION OUTPUT ;
    USE SIGNAL ;
    PORT
      LAYER M4 ;
        RECT  431.916 185.664 432 185.688 ;
    END
  END o_d[237]
  PIN o_d[238]
    DIRECTION OUTPUT ;
    USE SIGNAL ;
    PORT
      LAYER M4 ;
        RECT  431.916 186.192 432 186.216 ;
    END
  END o_d[238]
  PIN o_d[239]
    DIRECTION OUTPUT ;
    USE SIGNAL ;
    PORT
      LAYER M4 ;
        RECT  431.916 186.768 432 186.792 ;
    END
  END o_d[239]
  PIN o_d[23]
    DIRECTION OUTPUT ;
    USE SIGNAL ;
    PORT
      LAYER M4 ;
        RECT  431.916 67.776 432 67.8 ;
    END
  END o_d[23]
  PIN o_d[240]
    DIRECTION OUTPUT ;
    USE SIGNAL ;
    PORT
      LAYER M4 ;
        RECT  431.916 187.296 432 187.32 ;
    END
  END o_d[240]
  PIN o_d[241]
    DIRECTION OUTPUT ;
    USE SIGNAL ;
    PORT
      LAYER M4 ;
        RECT  431.916 187.872 432 187.896 ;
    END
  END o_d[241]
  PIN o_d[242]
    DIRECTION OUTPUT ;
    USE SIGNAL ;
    PORT
      LAYER M4 ;
        RECT  431.916 188.4 432 188.424 ;
    END
  END o_d[242]
  PIN o_d[243]
    DIRECTION OUTPUT ;
    USE SIGNAL ;
    PORT
      LAYER M4 ;
        RECT  431.916 188.976 432 189 ;
    END
  END o_d[243]
  PIN o_d[244]
    DIRECTION OUTPUT ;
    USE SIGNAL ;
    PORT
      LAYER M4 ;
        RECT  431.916 189.504 432 189.528 ;
    END
  END o_d[244]
  PIN o_d[24]
    DIRECTION OUTPUT ;
    USE SIGNAL ;
    PORT
      LAYER M4 ;
        RECT  431.916 68.304 432 68.328 ;
    END
  END o_d[24]
  PIN o_d[25]
    DIRECTION OUTPUT ;
    USE SIGNAL ;
    PORT
      LAYER M4 ;
        RECT  431.916 68.88 432 68.904 ;
    END
  END o_d[25]
  PIN o_d[26]
    DIRECTION OUTPUT ;
    USE SIGNAL ;
    PORT
      LAYER M4 ;
        RECT  431.916 69.408 432 69.432 ;
    END
  END o_d[26]
  PIN o_d[27]
    DIRECTION OUTPUT ;
    USE SIGNAL ;
    PORT
      LAYER M4 ;
        RECT  431.916 69.984 432 70.008 ;
    END
  END o_d[27]
  PIN o_d[28]
    DIRECTION OUTPUT ;
    USE SIGNAL ;
    PORT
      LAYER M4 ;
        RECT  431.916 70.512 432 70.536 ;
    END
  END o_d[28]
  PIN o_d[29]
    DIRECTION OUTPUT ;
    USE SIGNAL ;
    PORT
      LAYER M4 ;
        RECT  431.916 71.088 432 71.112 ;
    END
  END o_d[29]
  PIN o_d[2]
    DIRECTION OUTPUT ;
    USE SIGNAL ;
    PORT
      LAYER M4 ;
        RECT  431.916 56.208 432 56.232 ;
    END
  END o_d[2]
  PIN o_d[30]
    DIRECTION OUTPUT ;
    USE SIGNAL ;
    PORT
      LAYER M4 ;
        RECT  431.916 71.616 432 71.64 ;
    END
  END o_d[30]
  PIN o_d[31]
    DIRECTION OUTPUT ;
    USE SIGNAL ;
    PORT
      LAYER M4 ;
        RECT  431.916 72.192 432 72.216 ;
    END
  END o_d[31]
  PIN o_d[32]
    DIRECTION OUTPUT ;
    USE SIGNAL ;
    PORT
      LAYER M4 ;
        RECT  431.916 72.72 432 72.744 ;
    END
  END o_d[32]
  PIN o_d[33]
    DIRECTION OUTPUT ;
    USE SIGNAL ;
    PORT
      LAYER M4 ;
        RECT  431.916 73.296 432 73.32 ;
    END
  END o_d[33]
  PIN o_d[34]
    DIRECTION OUTPUT ;
    USE SIGNAL ;
    PORT
      LAYER M4 ;
        RECT  431.916 73.824 432 73.848 ;
    END
  END o_d[34]
  PIN o_d[35]
    DIRECTION OUTPUT ;
    USE SIGNAL ;
    PORT
      LAYER M4 ;
        RECT  431.916 74.4 432 74.424 ;
    END
  END o_d[35]
  PIN o_d[36]
    DIRECTION OUTPUT ;
    USE SIGNAL ;
    PORT
      LAYER M4 ;
        RECT  431.916 74.928 432 74.952 ;
    END
  END o_d[36]
  PIN o_d[37]
    DIRECTION OUTPUT ;
    USE SIGNAL ;
    PORT
      LAYER M4 ;
        RECT  431.916 75.504 432 75.528 ;
    END
  END o_d[37]
  PIN o_d[38]
    DIRECTION OUTPUT ;
    USE SIGNAL ;
    PORT
      LAYER M4 ;
        RECT  431.916 76.032 432 76.056 ;
    END
  END o_d[38]
  PIN o_d[39]
    DIRECTION OUTPUT ;
    USE SIGNAL ;
    PORT
      LAYER M4 ;
        RECT  431.916 76.608 432 76.632 ;
    END
  END o_d[39]
  PIN o_d[3]
    DIRECTION OUTPUT ;
    USE SIGNAL ;
    PORT
      LAYER M4 ;
        RECT  431.916 56.736 432 56.76 ;
    END
  END o_d[3]
  PIN o_d[40]
    DIRECTION OUTPUT ;
    USE SIGNAL ;
    PORT
      LAYER M4 ;
        RECT  431.916 77.136 432 77.16 ;
    END
  END o_d[40]
  PIN o_d[41]
    DIRECTION OUTPUT ;
    USE SIGNAL ;
    PORT
      LAYER M4 ;
        RECT  431.916 77.712 432 77.736 ;
    END
  END o_d[41]
  PIN o_d[42]
    DIRECTION OUTPUT ;
    USE SIGNAL ;
    PORT
      LAYER M4 ;
        RECT  431.916 78.24 432 78.264 ;
    END
  END o_d[42]
  PIN o_d[43]
    DIRECTION OUTPUT ;
    USE SIGNAL ;
    PORT
      LAYER M4 ;
        RECT  431.916 78.768 432 78.792 ;
    END
  END o_d[43]
  PIN o_d[44]
    DIRECTION OUTPUT ;
    USE SIGNAL ;
    PORT
      LAYER M4 ;
        RECT  431.916 79.344 432 79.368 ;
    END
  END o_d[44]
  PIN o_d[45]
    DIRECTION OUTPUT ;
    USE SIGNAL ;
    PORT
      LAYER M4 ;
        RECT  431.916 79.872 432 79.896 ;
    END
  END o_d[45]
  PIN o_d[46]
    DIRECTION OUTPUT ;
    USE SIGNAL ;
    PORT
      LAYER M4 ;
        RECT  431.916 80.448 432 80.472 ;
    END
  END o_d[46]
  PIN o_d[47]
    DIRECTION OUTPUT ;
    USE SIGNAL ;
    PORT
      LAYER M4 ;
        RECT  431.916 80.976 432 81 ;
    END
  END o_d[47]
  PIN o_d[48]
    DIRECTION OUTPUT ;
    USE SIGNAL ;
    PORT
      LAYER M4 ;
        RECT  431.916 81.552 432 81.576 ;
    END
  END o_d[48]
  PIN o_d[49]
    DIRECTION OUTPUT ;
    USE SIGNAL ;
    PORT
      LAYER M4 ;
        RECT  431.916 82.08 432 82.104 ;
    END
  END o_d[49]
  PIN o_d[4]
    DIRECTION OUTPUT ;
    USE SIGNAL ;
    PORT
      LAYER M4 ;
        RECT  431.916 57.312 432 57.336 ;
    END
  END o_d[4]
  PIN o_d[50]
    DIRECTION OUTPUT ;
    USE SIGNAL ;
    PORT
      LAYER M4 ;
        RECT  431.916 82.656 432 82.68 ;
    END
  END o_d[50]
  PIN o_d[51]
    DIRECTION OUTPUT ;
    USE SIGNAL ;
    PORT
      LAYER M4 ;
        RECT  431.916 83.184 432 83.208 ;
    END
  END o_d[51]
  PIN o_d[52]
    DIRECTION OUTPUT ;
    USE SIGNAL ;
    PORT
      LAYER M4 ;
        RECT  431.916 83.76 432 83.784 ;
    END
  END o_d[52]
  PIN o_d[53]
    DIRECTION OUTPUT ;
    USE SIGNAL ;
    PORT
      LAYER M4 ;
        RECT  431.916 84.288 432 84.312 ;
    END
  END o_d[53]
  PIN o_d[54]
    DIRECTION OUTPUT ;
    USE SIGNAL ;
    PORT
      LAYER M4 ;
        RECT  431.916 84.864 432 84.888 ;
    END
  END o_d[54]
  PIN o_d[55]
    DIRECTION OUTPUT ;
    USE SIGNAL ;
    PORT
      LAYER M4 ;
        RECT  431.916 85.392 432 85.416 ;
    END
  END o_d[55]
  PIN o_d[56]
    DIRECTION OUTPUT ;
    USE SIGNAL ;
    PORT
      LAYER M4 ;
        RECT  431.916 85.968 432 85.992 ;
    END
  END o_d[56]
  PIN o_d[57]
    DIRECTION OUTPUT ;
    USE SIGNAL ;
    PORT
      LAYER M4 ;
        RECT  431.916 86.496 432 86.52 ;
    END
  END o_d[57]
  PIN o_d[58]
    DIRECTION OUTPUT ;
    USE SIGNAL ;
    PORT
      LAYER M4 ;
        RECT  431.916 87.072 432 87.096 ;
    END
  END o_d[58]
  PIN o_d[59]
    DIRECTION OUTPUT ;
    USE SIGNAL ;
    PORT
      LAYER M4 ;
        RECT  431.916 87.6 432 87.624 ;
    END
  END o_d[59]
  PIN o_d[5]
    DIRECTION OUTPUT ;
    USE SIGNAL ;
    PORT
      LAYER M4 ;
        RECT  431.916 57.84 432 57.864 ;
    END
  END o_d[5]
  PIN o_d[60]
    DIRECTION OUTPUT ;
    USE SIGNAL ;
    PORT
      LAYER M4 ;
        RECT  431.916 88.176 432 88.2 ;
    END
  END o_d[60]
  PIN o_d[61]
    DIRECTION OUTPUT ;
    USE SIGNAL ;
    PORT
      LAYER M4 ;
        RECT  431.916 88.704 432 88.728 ;
    END
  END o_d[61]
  PIN o_d[62]
    DIRECTION OUTPUT ;
    USE SIGNAL ;
    PORT
      LAYER M4 ;
        RECT  431.916 89.28 432 89.304 ;
    END
  END o_d[62]
  PIN o_d[63]
    DIRECTION OUTPUT ;
    USE SIGNAL ;
    PORT
      LAYER M4 ;
        RECT  431.916 89.808 432 89.832 ;
    END
  END o_d[63]
  PIN o_d[64]
    DIRECTION OUTPUT ;
    USE SIGNAL ;
    PORT
      LAYER M4 ;
        RECT  431.916 90.384 432 90.408 ;
    END
  END o_d[64]
  PIN o_d[65]
    DIRECTION OUTPUT ;
    USE SIGNAL ;
    PORT
      LAYER M4 ;
        RECT  431.916 90.912 432 90.936 ;
    END
  END o_d[65]
  PIN o_d[66]
    DIRECTION OUTPUT ;
    USE SIGNAL ;
    PORT
      LAYER M4 ;
        RECT  431.916 91.44 432 91.464 ;
    END
  END o_d[66]
  PIN o_d[67]
    DIRECTION OUTPUT ;
    USE SIGNAL ;
    PORT
      LAYER M4 ;
        RECT  431.916 92.016 432 92.04 ;
    END
  END o_d[67]
  PIN o_d[68]
    DIRECTION OUTPUT ;
    USE SIGNAL ;
    PORT
      LAYER M4 ;
        RECT  431.916 92.544 432 92.568 ;
    END
  END o_d[68]
  PIN o_d[69]
    DIRECTION OUTPUT ;
    USE SIGNAL ;
    PORT
      LAYER M4 ;
        RECT  431.916 93.12 432 93.144 ;
    END
  END o_d[69]
  PIN o_d[6]
    DIRECTION OUTPUT ;
    USE SIGNAL ;
    PORT
      LAYER M4 ;
        RECT  431.916 58.416 432 58.44 ;
    END
  END o_d[6]
  PIN o_d[70]
    DIRECTION OUTPUT ;
    USE SIGNAL ;
    PORT
      LAYER M4 ;
        RECT  431.916 93.648 432 93.672 ;
    END
  END o_d[70]
  PIN o_d[71]
    DIRECTION OUTPUT ;
    USE SIGNAL ;
    PORT
      LAYER M4 ;
        RECT  431.916 94.224 432 94.248 ;
    END
  END o_d[71]
  PIN o_d[72]
    DIRECTION OUTPUT ;
    USE SIGNAL ;
    PORT
      LAYER M4 ;
        RECT  431.916 94.752 432 94.776 ;
    END
  END o_d[72]
  PIN o_d[73]
    DIRECTION OUTPUT ;
    USE SIGNAL ;
    PORT
      LAYER M4 ;
        RECT  431.916 95.328 432 95.352 ;
    END
  END o_d[73]
  PIN o_d[74]
    DIRECTION OUTPUT ;
    USE SIGNAL ;
    PORT
      LAYER M4 ;
        RECT  431.916 95.856 432 95.88 ;
    END
  END o_d[74]
  PIN o_d[75]
    DIRECTION OUTPUT ;
    USE SIGNAL ;
    PORT
      LAYER M4 ;
        RECT  431.916 96.432 432 96.456 ;
    END
  END o_d[75]
  PIN o_d[76]
    DIRECTION OUTPUT ;
    USE SIGNAL ;
    PORT
      LAYER M4 ;
        RECT  431.916 96.96 432 96.984 ;
    END
  END o_d[76]
  PIN o_d[77]
    DIRECTION OUTPUT ;
    USE SIGNAL ;
    PORT
      LAYER M4 ;
        RECT  431.916 97.536 432 97.56 ;
    END
  END o_d[77]
  PIN o_d[78]
    DIRECTION OUTPUT ;
    USE SIGNAL ;
    PORT
      LAYER M4 ;
        RECT  431.916 98.064 432 98.088 ;
    END
  END o_d[78]
  PIN o_d[79]
    DIRECTION OUTPUT ;
    USE SIGNAL ;
    PORT
      LAYER M4 ;
        RECT  431.916 98.64 432 98.664 ;
    END
  END o_d[79]
  PIN o_d[7]
    DIRECTION OUTPUT ;
    USE SIGNAL ;
    PORT
      LAYER M4 ;
        RECT  431.916 58.944 432 58.968 ;
    END
  END o_d[7]
  PIN o_d[80]
    DIRECTION OUTPUT ;
    USE SIGNAL ;
    PORT
      LAYER M4 ;
        RECT  431.916 99.168 432 99.192 ;
    END
  END o_d[80]
  PIN o_d[81]
    DIRECTION OUTPUT ;
    USE SIGNAL ;
    PORT
      LAYER M4 ;
        RECT  431.916 99.744 432 99.768 ;
    END
  END o_d[81]
  PIN o_d[82]
    DIRECTION OUTPUT ;
    USE SIGNAL ;
    PORT
      LAYER M4 ;
        RECT  431.916 100.272 432 100.296 ;
    END
  END o_d[82]
  PIN o_d[83]
    DIRECTION OUTPUT ;
    USE SIGNAL ;
    PORT
      LAYER M4 ;
        RECT  431.916 100.848 432 100.872 ;
    END
  END o_d[83]
  PIN o_d[84]
    DIRECTION OUTPUT ;
    USE SIGNAL ;
    PORT
      LAYER M4 ;
        RECT  431.916 101.376 432 101.4 ;
    END
  END o_d[84]
  PIN o_d[85]
    DIRECTION OUTPUT ;
    USE SIGNAL ;
    PORT
      LAYER M4 ;
        RECT  431.916 101.952 432 101.976 ;
    END
  END o_d[85]
  PIN o_d[86]
    DIRECTION OUTPUT ;
    USE SIGNAL ;
    PORT
      LAYER M4 ;
        RECT  431.916 102.48 432 102.504 ;
    END
  END o_d[86]
  PIN o_d[87]
    DIRECTION OUTPUT ;
    USE SIGNAL ;
    PORT
      LAYER M4 ;
        RECT  431.916 103.008 432 103.032 ;
    END
  END o_d[87]
  PIN o_d[88]
    DIRECTION OUTPUT ;
    USE SIGNAL ;
    PORT
      LAYER M4 ;
        RECT  431.916 103.584 432 103.608 ;
    END
  END o_d[88]
  PIN o_d[89]
    DIRECTION OUTPUT ;
    USE SIGNAL ;
    PORT
      LAYER M4 ;
        RECT  431.916 104.112 432 104.136 ;
    END
  END o_d[89]
  PIN o_d[8]
    DIRECTION OUTPUT ;
    USE SIGNAL ;
    PORT
      LAYER M4 ;
        RECT  431.916 59.52 432 59.544 ;
    END
  END o_d[8]
  PIN o_d[90]
    DIRECTION OUTPUT ;
    USE SIGNAL ;
    PORT
      LAYER M4 ;
        RECT  431.916 104.688 432 104.712 ;
    END
  END o_d[90]
  PIN o_d[91]
    DIRECTION OUTPUT ;
    USE SIGNAL ;
    PORT
      LAYER M4 ;
        RECT  431.916 105.216 432 105.24 ;
    END
  END o_d[91]
  PIN o_d[92]
    DIRECTION OUTPUT ;
    USE SIGNAL ;
    PORT
      LAYER M4 ;
        RECT  431.916 105.792 432 105.816 ;
    END
  END o_d[92]
  PIN o_d[93]
    DIRECTION OUTPUT ;
    USE SIGNAL ;
    PORT
      LAYER M4 ;
        RECT  431.916 106.32 432 106.344 ;
    END
  END o_d[93]
  PIN o_d[94]
    DIRECTION OUTPUT ;
    USE SIGNAL ;
    PORT
      LAYER M4 ;
        RECT  431.916 106.896 432 106.92 ;
    END
  END o_d[94]
  PIN o_d[95]
    DIRECTION OUTPUT ;
    USE SIGNAL ;
    PORT
      LAYER M4 ;
        RECT  431.916 107.424 432 107.448 ;
    END
  END o_d[95]
  PIN o_d[96]
    DIRECTION OUTPUT ;
    USE SIGNAL ;
    PORT
      LAYER M4 ;
        RECT  431.916 108 432 108.024 ;
    END
  END o_d[96]
  PIN o_d[97]
    DIRECTION OUTPUT ;
    USE SIGNAL ;
    PORT
      LAYER M4 ;
        RECT  431.916 108.528 432 108.552 ;
    END
  END o_d[97]
  PIN o_d[98]
    DIRECTION OUTPUT ;
    USE SIGNAL ;
    PORT
      LAYER M4 ;
        RECT  431.916 109.104 432 109.128 ;
    END
  END o_d[98]
  PIN o_d[99]
    DIRECTION OUTPUT ;
    USE SIGNAL ;
    PORT
      LAYER M4 ;
        RECT  431.916 109.632 432 109.656 ;
    END
  END o_d[99]
  PIN o_d[9]
    DIRECTION OUTPUT ;
    USE SIGNAL ;
    PORT
      LAYER M4 ;
        RECT  431.916 60.048 432 60.072 ;
    END
  END o_d[9]
  PIN o_f
    DIRECTION OUTPUT ;
    USE SIGNAL ;
    PORT
      LAYER M4 ;
        RECT  431.916 53.472 432 53.496 ;
    END
  END o_f
  PIN o_flt
    DIRECTION OUTPUT ;
    USE SIGNAL ;
    PORT
      LAYER M4 ;
        RECT  431.916 190.08 432 190.104 ;
    END
  END o_flt
  PIN o_g
    DIRECTION OUTPUT ;
    USE SIGNAL ;
    PORT
      LAYER M4 ;
        RECT  431.916 54.576 432 54.6 ;
    END
  END o_g
  PIN o_l
    DIRECTION OUTPUT ;
    USE SIGNAL ;
    PORT
      LAYER M4 ;
        RECT  431.916 54 432 54.024 ;
    END
  END o_l
  PIN o_v
    DIRECTION OUTPUT ;
    USE SIGNAL ;
    PORT
      LAYER M4 ;
        RECT  431.916 52.896 432 52.92 ;
    END
  END o_v
  PIN rst_n
    DIRECTION INPUT ;
    USE SIGNAL ;
    PORT
      LAYER M4 ;
        RECT  0 26.256 0.084 26.28 ;
    END
  END rst_n
  PIN s0a[0]
    DIRECTION INPUT ;
    USE SIGNAL ;
    PORT
      LAYER M5 ;
        RECT  22.176 0 22.2 0.084 ;
    END
  END s0a[0]
  PIN s0a[100]
    DIRECTION INPUT ;
    USE SIGNAL ;
    PORT
      LAYER M5 ;
        RECT  140.736 0 140.76 0.084 ;
    END
  END s0a[100]
  PIN s0a[101]
    DIRECTION INPUT ;
    USE SIGNAL ;
    PORT
      LAYER M5 ;
        RECT  141.888 0 141.912 0.084 ;
    END
  END s0a[101]
  PIN s0a[102]
    DIRECTION INPUT ;
    USE SIGNAL ;
    PORT
      LAYER M5 ;
        RECT  143.088 0 143.112 0.084 ;
    END
  END s0a[102]
  PIN s0a[103]
    DIRECTION INPUT ;
    USE SIGNAL ;
    PORT
      LAYER M5 ;
        RECT  144.288 0 144.312 0.084 ;
    END
  END s0a[103]
  PIN s0a[104]
    DIRECTION INPUT ;
    USE SIGNAL ;
    PORT
      LAYER M5 ;
        RECT  145.44 0 145.464 0.084 ;
    END
  END s0a[104]
  PIN s0a[105]
    DIRECTION INPUT ;
    USE SIGNAL ;
    PORT
      LAYER M5 ;
        RECT  146.64 0 146.664 0.084 ;
    END
  END s0a[105]
  PIN s0a[106]
    DIRECTION INPUT ;
    USE SIGNAL ;
    PORT
      LAYER M5 ;
        RECT  147.84 0 147.864 0.084 ;
    END
  END s0a[106]
  PIN s0a[107]
    DIRECTION INPUT ;
    USE SIGNAL ;
    PORT
      LAYER M5 ;
        RECT  148.992 0 149.016 0.084 ;
    END
  END s0a[107]
  PIN s0a[108]
    DIRECTION INPUT ;
    USE SIGNAL ;
    PORT
      LAYER M5 ;
        RECT  150.192 0 150.216 0.084 ;
    END
  END s0a[108]
  PIN s0a[109]
    DIRECTION INPUT ;
    USE SIGNAL ;
    PORT
      LAYER M5 ;
        RECT  151.392 0 151.416 0.084 ;
    END
  END s0a[109]
  PIN s0a[10]
    DIRECTION INPUT ;
    USE SIGNAL ;
    PORT
      LAYER M5 ;
        RECT  34.032 0 34.056 0.084 ;
    END
  END s0a[10]
  PIN s0a[110]
    DIRECTION INPUT ;
    USE SIGNAL ;
    PORT
      LAYER M5 ;
        RECT  152.592 0 152.616 0.084 ;
    END
  END s0a[110]
  PIN s0a[111]
    DIRECTION INPUT ;
    USE SIGNAL ;
    PORT
      LAYER M5 ;
        RECT  153.744 0 153.768 0.084 ;
    END
  END s0a[111]
  PIN s0a[112]
    DIRECTION INPUT ;
    USE SIGNAL ;
    PORT
      LAYER M5 ;
        RECT  154.944 0 154.968 0.084 ;
    END
  END s0a[112]
  PIN s0a[113]
    DIRECTION INPUT ;
    USE SIGNAL ;
    PORT
      LAYER M5 ;
        RECT  156.144 0 156.168 0.084 ;
    END
  END s0a[113]
  PIN s0a[114]
    DIRECTION INPUT ;
    USE SIGNAL ;
    PORT
      LAYER M5 ;
        RECT  157.296 0 157.32 0.084 ;
    END
  END s0a[114]
  PIN s0a[115]
    DIRECTION INPUT ;
    USE SIGNAL ;
    PORT
      LAYER M5 ;
        RECT  158.496 0 158.52 0.084 ;
    END
  END s0a[115]
  PIN s0a[116]
    DIRECTION INPUT ;
    USE SIGNAL ;
    PORT
      LAYER M5 ;
        RECT  159.696 0 159.72 0.084 ;
    END
  END s0a[116]
  PIN s0a[117]
    DIRECTION INPUT ;
    USE SIGNAL ;
    PORT
      LAYER M5 ;
        RECT  160.848 0 160.872 0.084 ;
    END
  END s0a[117]
  PIN s0a[118]
    DIRECTION INPUT ;
    USE SIGNAL ;
    PORT
      LAYER M5 ;
        RECT  162.048 0 162.072 0.084 ;
    END
  END s0a[118]
  PIN s0a[119]
    DIRECTION INPUT ;
    USE SIGNAL ;
    PORT
      LAYER M5 ;
        RECT  163.248 0 163.272 0.084 ;
    END
  END s0a[119]
  PIN s0a[11]
    DIRECTION INPUT ;
    USE SIGNAL ;
    PORT
      LAYER M5 ;
        RECT  35.232 0 35.256 0.084 ;
    END
  END s0a[11]
  PIN s0a[120]
    DIRECTION INPUT ;
    USE SIGNAL ;
    PORT
      LAYER M5 ;
        RECT  164.448 0 164.472 0.084 ;
    END
  END s0a[120]
  PIN s0a[121]
    DIRECTION INPUT ;
    USE SIGNAL ;
    PORT
      LAYER M5 ;
        RECT  165.6 0 165.624 0.084 ;
    END
  END s0a[121]
  PIN s0a[122]
    DIRECTION INPUT ;
    USE SIGNAL ;
    PORT
      LAYER M5 ;
        RECT  166.8 0 166.824 0.084 ;
    END
  END s0a[122]
  PIN s0a[123]
    DIRECTION INPUT ;
    USE SIGNAL ;
    PORT
      LAYER M5 ;
        RECT  168 0 168.024 0.084 ;
    END
  END s0a[123]
  PIN s0a[124]
    DIRECTION INPUT ;
    USE SIGNAL ;
    PORT
      LAYER M5 ;
        RECT  169.152 0 169.176 0.084 ;
    END
  END s0a[124]
  PIN s0a[125]
    DIRECTION INPUT ;
    USE SIGNAL ;
    PORT
      LAYER M5 ;
        RECT  170.352 0 170.376 0.084 ;
    END
  END s0a[125]
  PIN s0a[126]
    DIRECTION INPUT ;
    USE SIGNAL ;
    PORT
      LAYER M5 ;
        RECT  171.552 0 171.576 0.084 ;
    END
  END s0a[126]
  PIN s0a[127]
    DIRECTION INPUT ;
    USE SIGNAL ;
    PORT
      LAYER M5 ;
        RECT  172.752 0 172.776 0.084 ;
    END
  END s0a[127]
  PIN s0a[128]
    DIRECTION INPUT ;
    USE SIGNAL ;
    PORT
      LAYER M5 ;
        RECT  173.904 0 173.928 0.084 ;
    END
  END s0a[128]
  PIN s0a[129]
    DIRECTION INPUT ;
    USE SIGNAL ;
    PORT
      LAYER M5 ;
        RECT  175.104 0 175.128 0.084 ;
    END
  END s0a[129]
  PIN s0a[12]
    DIRECTION INPUT ;
    USE SIGNAL ;
    PORT
      LAYER M5 ;
        RECT  36.384 0 36.408 0.084 ;
    END
  END s0a[12]
  PIN s0a[130]
    DIRECTION INPUT ;
    USE SIGNAL ;
    PORT
      LAYER M5 ;
        RECT  176.256 0 176.28 0.084 ;
    END
  END s0a[130]
  PIN s0a[131]
    DIRECTION INPUT ;
    USE SIGNAL ;
    PORT
      LAYER M5 ;
        RECT  177.456 0 177.48 0.084 ;
    END
  END s0a[131]
  PIN s0a[132]
    DIRECTION INPUT ;
    USE SIGNAL ;
    PORT
      LAYER M5 ;
        RECT  178.656 0 178.68 0.084 ;
    END
  END s0a[132]
  PIN s0a[133]
    DIRECTION INPUT ;
    USE SIGNAL ;
    PORT
      LAYER M5 ;
        RECT  179.856 0 179.88 0.084 ;
    END
  END s0a[133]
  PIN s0a[134]
    DIRECTION INPUT ;
    USE SIGNAL ;
    PORT
      LAYER M5 ;
        RECT  181.008 0 181.032 0.084 ;
    END
  END s0a[134]
  PIN s0a[135]
    DIRECTION INPUT ;
    USE SIGNAL ;
    PORT
      LAYER M5 ;
        RECT  182.208 0 182.232 0.084 ;
    END
  END s0a[135]
  PIN s0a[136]
    DIRECTION INPUT ;
    USE SIGNAL ;
    PORT
      LAYER M5 ;
        RECT  183.408 0 183.432 0.084 ;
    END
  END s0a[136]
  PIN s0a[137]
    DIRECTION INPUT ;
    USE SIGNAL ;
    PORT
      LAYER M5 ;
        RECT  184.56 0 184.584 0.084 ;
    END
  END s0a[137]
  PIN s0a[138]
    DIRECTION INPUT ;
    USE SIGNAL ;
    PORT
      LAYER M5 ;
        RECT  185.76 0 185.784 0.084 ;
    END
  END s0a[138]
  PIN s0a[139]
    DIRECTION INPUT ;
    USE SIGNAL ;
    PORT
      LAYER M5 ;
        RECT  186.96 0 186.984 0.084 ;
    END
  END s0a[139]
  PIN s0a[13]
    DIRECTION INPUT ;
    USE SIGNAL ;
    PORT
      LAYER M5 ;
        RECT  37.584 0 37.608 0.084 ;
    END
  END s0a[13]
  PIN s0a[140]
    DIRECTION INPUT ;
    USE SIGNAL ;
    PORT
      LAYER M5 ;
        RECT  188.112 0 188.136 0.084 ;
    END
  END s0a[140]
  PIN s0a[141]
    DIRECTION INPUT ;
    USE SIGNAL ;
    PORT
      LAYER M5 ;
        RECT  189.312 0 189.336 0.084 ;
    END
  END s0a[141]
  PIN s0a[142]
    DIRECTION INPUT ;
    USE SIGNAL ;
    PORT
      LAYER M5 ;
        RECT  190.512 0 190.536 0.084 ;
    END
  END s0a[142]
  PIN s0a[143]
    DIRECTION INPUT ;
    USE SIGNAL ;
    PORT
      LAYER M5 ;
        RECT  191.712 0 191.736 0.084 ;
    END
  END s0a[143]
  PIN s0a[144]
    DIRECTION INPUT ;
    USE SIGNAL ;
    PORT
      LAYER M5 ;
        RECT  192.864 0 192.888 0.084 ;
    END
  END s0a[144]
  PIN s0a[145]
    DIRECTION INPUT ;
    USE SIGNAL ;
    PORT
      LAYER M5 ;
        RECT  194.064 0 194.088 0.084 ;
    END
  END s0a[145]
  PIN s0a[146]
    DIRECTION INPUT ;
    USE SIGNAL ;
    PORT
      LAYER M5 ;
        RECT  195.264 0 195.288 0.084 ;
    END
  END s0a[146]
  PIN s0a[147]
    DIRECTION INPUT ;
    USE SIGNAL ;
    PORT
      LAYER M5 ;
        RECT  196.416 0 196.44 0.084 ;
    END
  END s0a[147]
  PIN s0a[148]
    DIRECTION INPUT ;
    USE SIGNAL ;
    PORT
      LAYER M5 ;
        RECT  197.616 0 197.64 0.084 ;
    END
  END s0a[148]
  PIN s0a[149]
    DIRECTION INPUT ;
    USE SIGNAL ;
    PORT
      LAYER M5 ;
        RECT  198.816 0 198.84 0.084 ;
    END
  END s0a[149]
  PIN s0a[14]
    DIRECTION INPUT ;
    USE SIGNAL ;
    PORT
      LAYER M5 ;
        RECT  38.784 0 38.808 0.084 ;
    END
  END s0a[14]
  PIN s0a[150]
    DIRECTION INPUT ;
    USE SIGNAL ;
    PORT
      LAYER M5 ;
        RECT  199.968 0 199.992 0.084 ;
    END
  END s0a[150]
  PIN s0a[151]
    DIRECTION INPUT ;
    USE SIGNAL ;
    PORT
      LAYER M5 ;
        RECT  201.168 0 201.192 0.084 ;
    END
  END s0a[151]
  PIN s0a[152]
    DIRECTION INPUT ;
    USE SIGNAL ;
    PORT
      LAYER M5 ;
        RECT  202.368 0 202.392 0.084 ;
    END
  END s0a[152]
  PIN s0a[153]
    DIRECTION INPUT ;
    USE SIGNAL ;
    PORT
      LAYER M5 ;
        RECT  203.52 0 203.544 0.084 ;
    END
  END s0a[153]
  PIN s0a[154]
    DIRECTION INPUT ;
    USE SIGNAL ;
    PORT
      LAYER M5 ;
        RECT  204.72 0 204.744 0.084 ;
    END
  END s0a[154]
  PIN s0a[155]
    DIRECTION INPUT ;
    USE SIGNAL ;
    PORT
      LAYER M5 ;
        RECT  205.92 0 205.944 0.084 ;
    END
  END s0a[155]
  PIN s0a[156]
    DIRECTION INPUT ;
    USE SIGNAL ;
    PORT
      LAYER M5 ;
        RECT  207.12 0 207.144 0.084 ;
    END
  END s0a[156]
  PIN s0a[157]
    DIRECTION INPUT ;
    USE SIGNAL ;
    PORT
      LAYER M5 ;
        RECT  208.272 0 208.296 0.084 ;
    END
  END s0a[157]
  PIN s0a[158]
    DIRECTION INPUT ;
    USE SIGNAL ;
    PORT
      LAYER M5 ;
        RECT  209.472 0 209.496 0.084 ;
    END
  END s0a[158]
  PIN s0a[159]
    DIRECTION INPUT ;
    USE SIGNAL ;
    PORT
      LAYER M5 ;
        RECT  210.72 0 210.744 0.084 ;
    END
  END s0a[159]
  PIN s0a[15]
    DIRECTION INPUT ;
    USE SIGNAL ;
    PORT
      LAYER M5 ;
        RECT  39.984 0 40.008 0.084 ;
    END
  END s0a[15]
  PIN s0a[160]
    DIRECTION INPUT ;
    USE SIGNAL ;
    PORT
      LAYER M5 ;
        RECT  211.824 0 211.848 0.084 ;
    END
  END s0a[160]
  PIN s0a[161]
    DIRECTION INPUT ;
    USE SIGNAL ;
    PORT
      LAYER M5 ;
        RECT  213.024 0 213.048 0.084 ;
    END
  END s0a[161]
  PIN s0a[162]
    DIRECTION INPUT ;
    USE SIGNAL ;
    PORT
      LAYER M5 ;
        RECT  214.224 0 214.248 0.084 ;
    END
  END s0a[162]
  PIN s0a[163]
    DIRECTION INPUT ;
    USE SIGNAL ;
    PORT
      LAYER M5 ;
        RECT  215.376 0 215.4 0.084 ;
    END
  END s0a[163]
  PIN s0a[164]
    DIRECTION INPUT ;
    USE SIGNAL ;
    PORT
      LAYER M5 ;
        RECT  216.576 0 216.6 0.084 ;
    END
  END s0a[164]
  PIN s0a[165]
    DIRECTION INPUT ;
    USE SIGNAL ;
    PORT
      LAYER M5 ;
        RECT  217.776 0 217.8 0.084 ;
    END
  END s0a[165]
  PIN s0a[166]
    DIRECTION INPUT ;
    USE SIGNAL ;
    PORT
      LAYER M5 ;
        RECT  218.928 0 218.952 0.084 ;
    END
  END s0a[166]
  PIN s0a[167]
    DIRECTION INPUT ;
    USE SIGNAL ;
    PORT
      LAYER M5 ;
        RECT  220.128 0 220.152 0.084 ;
    END
  END s0a[167]
  PIN s0a[168]
    DIRECTION INPUT ;
    USE SIGNAL ;
    PORT
      LAYER M5 ;
        RECT  221.376 0 221.4 0.084 ;
    END
  END s0a[168]
  PIN s0a[169]
    DIRECTION INPUT ;
    USE SIGNAL ;
    PORT
      LAYER M5 ;
        RECT  222.528 0 222.552 0.084 ;
    END
  END s0a[169]
  PIN s0a[16]
    DIRECTION INPUT ;
    USE SIGNAL ;
    PORT
      LAYER M5 ;
        RECT  41.136 0 41.16 0.084 ;
    END
  END s0a[16]
  PIN s0a[170]
    DIRECTION INPUT ;
    USE SIGNAL ;
    PORT
      LAYER M5 ;
        RECT  223.68 0 223.704 0.084 ;
    END
  END s0a[170]
  PIN s0a[171]
    DIRECTION INPUT ;
    USE SIGNAL ;
    PORT
      LAYER M5 ;
        RECT  224.88 0 224.904 0.084 ;
    END
  END s0a[171]
  PIN s0a[172]
    DIRECTION INPUT ;
    USE SIGNAL ;
    PORT
      LAYER M5 ;
        RECT  226.08 0 226.104 0.084 ;
    END
  END s0a[172]
  PIN s0a[173]
    DIRECTION INPUT ;
    USE SIGNAL ;
    PORT
      LAYER M5 ;
        RECT  227.232 0 227.256 0.084 ;
    END
  END s0a[173]
  PIN s0a[174]
    DIRECTION INPUT ;
    USE SIGNAL ;
    PORT
      LAYER M5 ;
        RECT  228.432 0 228.456 0.084 ;
    END
  END s0a[174]
  PIN s0a[175]
    DIRECTION INPUT ;
    USE SIGNAL ;
    PORT
      LAYER M5 ;
        RECT  229.632 0 229.656 0.084 ;
    END
  END s0a[175]
  PIN s0a[176]
    DIRECTION INPUT ;
    USE SIGNAL ;
    PORT
      LAYER M5 ;
        RECT  230.784 0 230.808 0.084 ;
    END
  END s0a[176]
  PIN s0a[177]
    DIRECTION INPUT ;
    USE SIGNAL ;
    PORT
      LAYER M5 ;
        RECT  231.984 0 232.008 0.084 ;
    END
  END s0a[177]
  PIN s0a[178]
    DIRECTION INPUT ;
    USE SIGNAL ;
    PORT
      LAYER M5 ;
        RECT  233.184 0 233.208 0.084 ;
    END
  END s0a[178]
  PIN s0a[179]
    DIRECTION INPUT ;
    USE SIGNAL ;
    PORT
      LAYER M5 ;
        RECT  234.384 0 234.408 0.084 ;
    END
  END s0a[179]
  PIN s0a[17]
    DIRECTION INPUT ;
    USE SIGNAL ;
    PORT
      LAYER M5 ;
        RECT  42.336 0 42.36 0.084 ;
    END
  END s0a[17]
  PIN s0a[180]
    DIRECTION INPUT ;
    USE SIGNAL ;
    PORT
      LAYER M5 ;
        RECT  235.536 0 235.56 0.084 ;
    END
  END s0a[180]
  PIN s0a[181]
    DIRECTION INPUT ;
    USE SIGNAL ;
    PORT
      LAYER M5 ;
        RECT  236.736 0 236.76 0.084 ;
    END
  END s0a[181]
  PIN s0a[182]
    DIRECTION INPUT ;
    USE SIGNAL ;
    PORT
      LAYER M5 ;
        RECT  237.936 0 237.96 0.084 ;
    END
  END s0a[182]
  PIN s0a[183]
    DIRECTION INPUT ;
    USE SIGNAL ;
    PORT
      LAYER M5 ;
        RECT  239.088 0 239.112 0.084 ;
    END
  END s0a[183]
  PIN s0a[184]
    DIRECTION INPUT ;
    USE SIGNAL ;
    PORT
      LAYER M5 ;
        RECT  240.288 0 240.312 0.084 ;
    END
  END s0a[184]
  PIN s0a[185]
    DIRECTION INPUT ;
    USE SIGNAL ;
    PORT
      LAYER M5 ;
        RECT  241.488 0 241.512 0.084 ;
    END
  END s0a[185]
  PIN s0a[186]
    DIRECTION INPUT ;
    USE SIGNAL ;
    PORT
      LAYER M5 ;
        RECT  242.64 0 242.664 0.084 ;
    END
  END s0a[186]
  PIN s0a[187]
    DIRECTION INPUT ;
    USE SIGNAL ;
    PORT
      LAYER M5 ;
        RECT  243.84 0 243.864 0.084 ;
    END
  END s0a[187]
  PIN s0a[188]
    DIRECTION INPUT ;
    USE SIGNAL ;
    PORT
      LAYER M5 ;
        RECT  245.04 0 245.064 0.084 ;
    END
  END s0a[188]
  PIN s0a[189]
    DIRECTION INPUT ;
    USE SIGNAL ;
    PORT
      LAYER M5 ;
        RECT  246.192 0 246.216 0.084 ;
    END
  END s0a[189]
  PIN s0a[18]
    DIRECTION INPUT ;
    USE SIGNAL ;
    PORT
      LAYER M5 ;
        RECT  43.536 0 43.56 0.084 ;
    END
  END s0a[18]
  PIN s0a[190]
    DIRECTION INPUT ;
    USE SIGNAL ;
    PORT
      LAYER M5 ;
        RECT  247.392 0 247.416 0.084 ;
    END
  END s0a[190]
  PIN s0a[191]
    DIRECTION INPUT ;
    USE SIGNAL ;
    PORT
      LAYER M5 ;
        RECT  248.592 0 248.616 0.084 ;
    END
  END s0a[191]
  PIN s0a[192]
    DIRECTION INPUT ;
    USE SIGNAL ;
    PORT
      LAYER M5 ;
        RECT  249.792 0 249.816 0.084 ;
    END
  END s0a[192]
  PIN s0a[193]
    DIRECTION INPUT ;
    USE SIGNAL ;
    PORT
      LAYER M5 ;
        RECT  250.944 0 250.968 0.084 ;
    END
  END s0a[193]
  PIN s0a[194]
    DIRECTION INPUT ;
    USE SIGNAL ;
    PORT
      LAYER M5 ;
        RECT  252.144 0 252.168 0.084 ;
    END
  END s0a[194]
  PIN s0a[195]
    DIRECTION INPUT ;
    USE SIGNAL ;
    PORT
      LAYER M5 ;
        RECT  253.344 0 253.368 0.084 ;
    END
  END s0a[195]
  PIN s0a[196]
    DIRECTION INPUT ;
    USE SIGNAL ;
    PORT
      LAYER M5 ;
        RECT  254.496 0 254.52 0.084 ;
    END
  END s0a[196]
  PIN s0a[197]
    DIRECTION INPUT ;
    USE SIGNAL ;
    PORT
      LAYER M5 ;
        RECT  255.696 0 255.72 0.084 ;
    END
  END s0a[197]
  PIN s0a[198]
    DIRECTION INPUT ;
    USE SIGNAL ;
    PORT
      LAYER M5 ;
        RECT  256.896 0 256.92 0.084 ;
    END
  END s0a[198]
  PIN s0a[199]
    DIRECTION INPUT ;
    USE SIGNAL ;
    PORT
      LAYER M5 ;
        RECT  258.048 0 258.072 0.084 ;
    END
  END s0a[199]
  PIN s0a[19]
    DIRECTION INPUT ;
    USE SIGNAL ;
    PORT
      LAYER M5 ;
        RECT  44.688 0 44.712 0.084 ;
    END
  END s0a[19]
  PIN s0a[1]
    DIRECTION INPUT ;
    USE SIGNAL ;
    PORT
      LAYER M5 ;
        RECT  23.376 0 23.4 0.084 ;
    END
  END s0a[1]
  PIN s0a[200]
    DIRECTION INPUT ;
    USE SIGNAL ;
    PORT
      LAYER M5 ;
        RECT  259.248 0 259.272 0.084 ;
    END
  END s0a[200]
  PIN s0a[201]
    DIRECTION INPUT ;
    USE SIGNAL ;
    PORT
      LAYER M5 ;
        RECT  260.448 0 260.472 0.084 ;
    END
  END s0a[201]
  PIN s0a[202]
    DIRECTION INPUT ;
    USE SIGNAL ;
    PORT
      LAYER M5 ;
        RECT  261.648 0 261.672 0.084 ;
    END
  END s0a[202]
  PIN s0a[203]
    DIRECTION INPUT ;
    USE SIGNAL ;
    PORT
      LAYER M5 ;
        RECT  262.8 0 262.824 0.084 ;
    END
  END s0a[203]
  PIN s0a[204]
    DIRECTION INPUT ;
    USE SIGNAL ;
    PORT
      LAYER M5 ;
        RECT  264 0 264.024 0.084 ;
    END
  END s0a[204]
  PIN s0a[205]
    DIRECTION INPUT ;
    USE SIGNAL ;
    PORT
      LAYER M5 ;
        RECT  265.2 0 265.224 0.084 ;
    END
  END s0a[205]
  PIN s0a[206]
    DIRECTION INPUT ;
    USE SIGNAL ;
    PORT
      LAYER M5 ;
        RECT  266.352 0 266.376 0.084 ;
    END
  END s0a[206]
  PIN s0a[207]
    DIRECTION INPUT ;
    USE SIGNAL ;
    PORT
      LAYER M5 ;
        RECT  267.552 0 267.576 0.084 ;
    END
  END s0a[207]
  PIN s0a[208]
    DIRECTION INPUT ;
    USE SIGNAL ;
    PORT
      LAYER M5 ;
        RECT  268.752 0 268.776 0.084 ;
    END
  END s0a[208]
  PIN s0a[209]
    DIRECTION INPUT ;
    USE SIGNAL ;
    PORT
      LAYER M5 ;
        RECT  269.952 0 269.976 0.084 ;
    END
  END s0a[209]
  PIN s0a[20]
    DIRECTION INPUT ;
    USE SIGNAL ;
    PORT
      LAYER M5 ;
        RECT  45.888 0 45.912 0.084 ;
    END
  END s0a[20]
  PIN s0a[210]
    DIRECTION INPUT ;
    USE SIGNAL ;
    PORT
      LAYER M5 ;
        RECT  271.104 0 271.128 0.084 ;
    END
  END s0a[210]
  PIN s0a[211]
    DIRECTION INPUT ;
    USE SIGNAL ;
    PORT
      LAYER M5 ;
        RECT  272.304 0 272.328 0.084 ;
    END
  END s0a[211]
  PIN s0a[212]
    DIRECTION INPUT ;
    USE SIGNAL ;
    PORT
      LAYER M5 ;
        RECT  273.456 0 273.48 0.084 ;
    END
  END s0a[212]
  PIN s0a[213]
    DIRECTION INPUT ;
    USE SIGNAL ;
    PORT
      LAYER M5 ;
        RECT  274.656 0 274.68 0.084 ;
    END
  END s0a[213]
  PIN s0a[214]
    DIRECTION INPUT ;
    USE SIGNAL ;
    PORT
      LAYER M5 ;
        RECT  275.856 0 275.88 0.084 ;
    END
  END s0a[214]
  PIN s0a[215]
    DIRECTION INPUT ;
    USE SIGNAL ;
    PORT
      LAYER M5 ;
        RECT  277.056 0 277.08 0.084 ;
    END
  END s0a[215]
  PIN s0a[216]
    DIRECTION INPUT ;
    USE SIGNAL ;
    PORT
      LAYER M5 ;
        RECT  278.208 0 278.232 0.084 ;
    END
  END s0a[216]
  PIN s0a[217]
    DIRECTION INPUT ;
    USE SIGNAL ;
    PORT
      LAYER M5 ;
        RECT  279.408 0 279.432 0.084 ;
    END
  END s0a[217]
  PIN s0a[218]
    DIRECTION INPUT ;
    USE SIGNAL ;
    PORT
      LAYER M5 ;
        RECT  280.608 0 280.632 0.084 ;
    END
  END s0a[218]
  PIN s0a[219]
    DIRECTION INPUT ;
    USE SIGNAL ;
    PORT
      LAYER M5 ;
        RECT  281.76 0 281.784 0.084 ;
    END
  END s0a[219]
  PIN s0a[21]
    DIRECTION INPUT ;
    USE SIGNAL ;
    PORT
      LAYER M5 ;
        RECT  47.088 0 47.112 0.084 ;
    END
  END s0a[21]
  PIN s0a[220]
    DIRECTION INPUT ;
    USE SIGNAL ;
    PORT
      LAYER M5 ;
        RECT  282.96 0 282.984 0.084 ;
    END
  END s0a[220]
  PIN s0a[221]
    DIRECTION INPUT ;
    USE SIGNAL ;
    PORT
      LAYER M5 ;
        RECT  284.16 0 284.184 0.084 ;
    END
  END s0a[221]
  PIN s0a[222]
    DIRECTION INPUT ;
    USE SIGNAL ;
    PORT
      LAYER M5 ;
        RECT  285.312 0 285.336 0.084 ;
    END
  END s0a[222]
  PIN s0a[223]
    DIRECTION INPUT ;
    USE SIGNAL ;
    PORT
      LAYER M5 ;
        RECT  286.512 0 286.536 0.084 ;
    END
  END s0a[223]
  PIN s0a[224]
    DIRECTION INPUT ;
    USE SIGNAL ;
    PORT
      LAYER M5 ;
        RECT  287.712 0 287.736 0.084 ;
    END
  END s0a[224]
  PIN s0a[225]
    DIRECTION INPUT ;
    USE SIGNAL ;
    PORT
      LAYER M5 ;
        RECT  288.912 0 288.936 0.084 ;
    END
  END s0a[225]
  PIN s0a[226]
    DIRECTION INPUT ;
    USE SIGNAL ;
    PORT
      LAYER M5 ;
        RECT  290.064 0 290.088 0.084 ;
    END
  END s0a[226]
  PIN s0a[227]
    DIRECTION INPUT ;
    USE SIGNAL ;
    PORT
      LAYER M5 ;
        RECT  291.264 0 291.288 0.084 ;
    END
  END s0a[227]
  PIN s0a[228]
    DIRECTION INPUT ;
    USE SIGNAL ;
    PORT
      LAYER M5 ;
        RECT  292.464 0 292.488 0.084 ;
    END
  END s0a[228]
  PIN s0a[229]
    DIRECTION INPUT ;
    USE SIGNAL ;
    PORT
      LAYER M5 ;
        RECT  293.616 0 293.64 0.084 ;
    END
  END s0a[229]
  PIN s0a[22]
    DIRECTION INPUT ;
    USE SIGNAL ;
    PORT
      LAYER M5 ;
        RECT  48.24 0 48.264 0.084 ;
    END
  END s0a[22]
  PIN s0a[230]
    DIRECTION INPUT ;
    USE SIGNAL ;
    PORT
      LAYER M5 ;
        RECT  294.816 0 294.84 0.084 ;
    END
  END s0a[230]
  PIN s0a[231]
    DIRECTION INPUT ;
    USE SIGNAL ;
    PORT
      LAYER M5 ;
        RECT  296.016 0 296.04 0.084 ;
    END
  END s0a[231]
  PIN s0a[232]
    DIRECTION INPUT ;
    USE SIGNAL ;
    PORT
      LAYER M5 ;
        RECT  297.168 0 297.192 0.084 ;
    END
  END s0a[232]
  PIN s0a[233]
    DIRECTION INPUT ;
    USE SIGNAL ;
    PORT
      LAYER M5 ;
        RECT  298.368 0 298.392 0.084 ;
    END
  END s0a[233]
  PIN s0a[234]
    DIRECTION INPUT ;
    USE SIGNAL ;
    PORT
      LAYER M5 ;
        RECT  299.568 0 299.592 0.084 ;
    END
  END s0a[234]
  PIN s0a[235]
    DIRECTION INPUT ;
    USE SIGNAL ;
    PORT
      LAYER M5 ;
        RECT  300.72 0 300.744 0.084 ;
    END
  END s0a[235]
  PIN s0a[236]
    DIRECTION INPUT ;
    USE SIGNAL ;
    PORT
      LAYER M5 ;
        RECT  301.92 0 301.944 0.084 ;
    END
  END s0a[236]
  PIN s0a[237]
    DIRECTION INPUT ;
    USE SIGNAL ;
    PORT
      LAYER M5 ;
        RECT  303.12 0 303.144 0.084 ;
    END
  END s0a[237]
  PIN s0a[238]
    DIRECTION INPUT ;
    USE SIGNAL ;
    PORT
      LAYER M5 ;
        RECT  304.32 0 304.344 0.084 ;
    END
  END s0a[238]
  PIN s0a[239]
    DIRECTION INPUT ;
    USE SIGNAL ;
    PORT
      LAYER M5 ;
        RECT  305.472 0 305.496 0.084 ;
    END
  END s0a[239]
  PIN s0a[23]
    DIRECTION INPUT ;
    USE SIGNAL ;
    PORT
      LAYER M5 ;
        RECT  49.44 0 49.464 0.084 ;
    END
  END s0a[23]
  PIN s0a[240]
    DIRECTION INPUT ;
    USE SIGNAL ;
    PORT
      LAYER M5 ;
        RECT  306.672 0 306.696 0.084 ;
    END
  END s0a[240]
  PIN s0a[241]
    DIRECTION INPUT ;
    USE SIGNAL ;
    PORT
      LAYER M5 ;
        RECT  307.92 0 307.944 0.084 ;
    END
  END s0a[241]
  PIN s0a[242]
    DIRECTION INPUT ;
    USE SIGNAL ;
    PORT
      LAYER M5 ;
        RECT  309.024 0 309.048 0.084 ;
    END
  END s0a[242]
  PIN s0a[243]
    DIRECTION INPUT ;
    USE SIGNAL ;
    PORT
      LAYER M5 ;
        RECT  310.224 0 310.248 0.084 ;
    END
  END s0a[243]
  PIN s0a[244]
    DIRECTION INPUT ;
    USE SIGNAL ;
    PORT
      LAYER M5 ;
        RECT  311.424 0 311.448 0.084 ;
    END
  END s0a[244]
  PIN s0a[245]
    DIRECTION INPUT ;
    USE SIGNAL ;
    PORT
      LAYER M5 ;
        RECT  312.576 0 312.6 0.084 ;
    END
  END s0a[245]
  PIN s0a[246]
    DIRECTION INPUT ;
    USE SIGNAL ;
    PORT
      LAYER M5 ;
        RECT  313.776 0 313.8 0.084 ;
    END
  END s0a[246]
  PIN s0a[247]
    DIRECTION INPUT ;
    USE SIGNAL ;
    PORT
      LAYER M5 ;
        RECT  314.976 0 315 0.084 ;
    END
  END s0a[247]
  PIN s0a[248]
    DIRECTION INPUT ;
    USE SIGNAL ;
    PORT
      LAYER M5 ;
        RECT  316.128 0 316.152 0.084 ;
    END
  END s0a[248]
  PIN s0a[249]
    DIRECTION INPUT ;
    USE SIGNAL ;
    PORT
      LAYER M5 ;
        RECT  317.328 0 317.352 0.084 ;
    END
  END s0a[249]
  PIN s0a[24]
    DIRECTION INPUT ;
    USE SIGNAL ;
    PORT
      LAYER M5 ;
        RECT  50.64 0 50.664 0.084 ;
    END
  END s0a[24]
  PIN s0a[250]
    DIRECTION INPUT ;
    USE SIGNAL ;
    PORT
      LAYER M5 ;
        RECT  318.576 0 318.6 0.084 ;
    END
  END s0a[250]
  PIN s0a[251]
    DIRECTION INPUT ;
    USE SIGNAL ;
    PORT
      LAYER M5 ;
        RECT  319.728 0 319.752 0.084 ;
    END
  END s0a[251]
  PIN s0a[252]
    DIRECTION INPUT ;
    USE SIGNAL ;
    PORT
      LAYER M5 ;
        RECT  320.88 0 320.904 0.084 ;
    END
  END s0a[252]
  PIN s0a[253]
    DIRECTION INPUT ;
    USE SIGNAL ;
    PORT
      LAYER M5 ;
        RECT  322.08 0 322.104 0.084 ;
    END
  END s0a[253]
  PIN s0a[254]
    DIRECTION INPUT ;
    USE SIGNAL ;
    PORT
      LAYER M5 ;
        RECT  323.28 0 323.304 0.084 ;
    END
  END s0a[254]
  PIN s0a[255]
    DIRECTION INPUT ;
    USE SIGNAL ;
    PORT
      LAYER M5 ;
        RECT  324.432 0 324.456 0.084 ;
    END
  END s0a[255]
  PIN s0a[256]
    DIRECTION INPUT ;
    USE SIGNAL ;
    PORT
      LAYER M5 ;
        RECT  325.632 0 325.656 0.084 ;
    END
  END s0a[256]
  PIN s0a[257]
    DIRECTION INPUT ;
    USE SIGNAL ;
    PORT
      LAYER M5 ;
        RECT  326.832 0 326.856 0.084 ;
    END
  END s0a[257]
  PIN s0a[258]
    DIRECTION INPUT ;
    USE SIGNAL ;
    PORT
      LAYER M5 ;
        RECT  327.984 0 328.008 0.084 ;
    END
  END s0a[258]
  PIN s0a[259]
    DIRECTION INPUT ;
    USE SIGNAL ;
    PORT
      LAYER M5 ;
        RECT  329.184 0 329.208 0.084 ;
    END
  END s0a[259]
  PIN s0a[25]
    DIRECTION INPUT ;
    USE SIGNAL ;
    PORT
      LAYER M5 ;
        RECT  51.792 0 51.816 0.084 ;
    END
  END s0a[25]
  PIN s0a[260]
    DIRECTION INPUT ;
    USE SIGNAL ;
    PORT
      LAYER M5 ;
        RECT  330.384 0 330.408 0.084 ;
    END
  END s0a[260]
  PIN s0a[261]
    DIRECTION INPUT ;
    USE SIGNAL ;
    PORT
      LAYER M5 ;
        RECT  331.584 0 331.608 0.084 ;
    END
  END s0a[261]
  PIN s0a[262]
    DIRECTION INPUT ;
    USE SIGNAL ;
    PORT
      LAYER M5 ;
        RECT  332.736 0 332.76 0.084 ;
    END
  END s0a[262]
  PIN s0a[263]
    DIRECTION INPUT ;
    USE SIGNAL ;
    PORT
      LAYER M5 ;
        RECT  333.936 0 333.96 0.084 ;
    END
  END s0a[263]
  PIN s0a[264]
    DIRECTION INPUT ;
    USE SIGNAL ;
    PORT
      LAYER M5 ;
        RECT  335.136 0 335.16 0.084 ;
    END
  END s0a[264]
  PIN s0a[265]
    DIRECTION INPUT ;
    USE SIGNAL ;
    PORT
      LAYER M5 ;
        RECT  336.288 0 336.312 0.084 ;
    END
  END s0a[265]
  PIN s0a[266]
    DIRECTION INPUT ;
    USE SIGNAL ;
    PORT
      LAYER M5 ;
        RECT  337.488 0 337.512 0.084 ;
    END
  END s0a[266]
  PIN s0a[267]
    DIRECTION INPUT ;
    USE SIGNAL ;
    PORT
      LAYER M5 ;
        RECT  338.688 0 338.712 0.084 ;
    END
  END s0a[267]
  PIN s0a[268]
    DIRECTION INPUT ;
    USE SIGNAL ;
    PORT
      LAYER M5 ;
        RECT  339.84 0 339.864 0.084 ;
    END
  END s0a[268]
  PIN s0a[269]
    DIRECTION INPUT ;
    USE SIGNAL ;
    PORT
      LAYER M5 ;
        RECT  341.04 0 341.064 0.084 ;
    END
  END s0a[269]
  PIN s0a[26]
    DIRECTION INPUT ;
    USE SIGNAL ;
    PORT
      LAYER M5 ;
        RECT  52.992 0 53.016 0.084 ;
    END
  END s0a[26]
  PIN s0a[270]
    DIRECTION INPUT ;
    USE SIGNAL ;
    PORT
      LAYER M5 ;
        RECT  342.24 0 342.264 0.084 ;
    END
  END s0a[270]
  PIN s0a[271]
    DIRECTION INPUT ;
    USE SIGNAL ;
    PORT
      LAYER M5 ;
        RECT  343.392 0 343.416 0.084 ;
    END
  END s0a[271]
  PIN s0a[272]
    DIRECTION INPUT ;
    USE SIGNAL ;
    PORT
      LAYER M5 ;
        RECT  344.592 0 344.616 0.084 ;
    END
  END s0a[272]
  PIN s0a[273]
    DIRECTION INPUT ;
    USE SIGNAL ;
    PORT
      LAYER M5 ;
        RECT  345.792 0 345.816 0.084 ;
    END
  END s0a[273]
  PIN s0a[274]
    DIRECTION INPUT ;
    USE SIGNAL ;
    PORT
      LAYER M5 ;
        RECT  346.992 0 347.016 0.084 ;
    END
  END s0a[274]
  PIN s0a[275]
    DIRECTION INPUT ;
    USE SIGNAL ;
    PORT
      LAYER M5 ;
        RECT  348.144 0 348.168 0.084 ;
    END
  END s0a[275]
  PIN s0a[276]
    DIRECTION INPUT ;
    USE SIGNAL ;
    PORT
      LAYER M5 ;
        RECT  349.344 0 349.368 0.084 ;
    END
  END s0a[276]
  PIN s0a[277]
    DIRECTION INPUT ;
    USE SIGNAL ;
    PORT
      LAYER M5 ;
        RECT  350.544 0 350.568 0.084 ;
    END
  END s0a[277]
  PIN s0a[278]
    DIRECTION INPUT ;
    USE SIGNAL ;
    PORT
      LAYER M5 ;
        RECT  351.696 0 351.72 0.084 ;
    END
  END s0a[278]
  PIN s0a[279]
    DIRECTION INPUT ;
    USE SIGNAL ;
    PORT
      LAYER M5 ;
        RECT  352.896 0 352.92 0.084 ;
    END
  END s0a[279]
  PIN s0a[27]
    DIRECTION INPUT ;
    USE SIGNAL ;
    PORT
      LAYER M5 ;
        RECT  54.192 0 54.216 0.084 ;
    END
  END s0a[27]
  PIN s0a[280]
    DIRECTION INPUT ;
    USE SIGNAL ;
    PORT
      LAYER M5 ;
        RECT  354.096 0 354.12 0.084 ;
    END
  END s0a[280]
  PIN s0a[281]
    DIRECTION INPUT ;
    USE SIGNAL ;
    PORT
      LAYER M5 ;
        RECT  355.248 0 355.272 0.084 ;
    END
  END s0a[281]
  PIN s0a[282]
    DIRECTION INPUT ;
    USE SIGNAL ;
    PORT
      LAYER M5 ;
        RECT  356.448 0 356.472 0.084 ;
    END
  END s0a[282]
  PIN s0a[283]
    DIRECTION INPUT ;
    USE SIGNAL ;
    PORT
      LAYER M5 ;
        RECT  357.648 0 357.672 0.084 ;
    END
  END s0a[283]
  PIN s0a[284]
    DIRECTION INPUT ;
    USE SIGNAL ;
    PORT
      LAYER M5 ;
        RECT  358.848 0 358.872 0.084 ;
    END
  END s0a[284]
  PIN s0a[285]
    DIRECTION INPUT ;
    USE SIGNAL ;
    PORT
      LAYER M5 ;
        RECT  360 0 360.024 0.084 ;
    END
  END s0a[285]
  PIN s0a[286]
    DIRECTION INPUT ;
    USE SIGNAL ;
    PORT
      LAYER M5 ;
        RECT  361.2 0 361.224 0.084 ;
    END
  END s0a[286]
  PIN s0a[287]
    DIRECTION INPUT ;
    USE SIGNAL ;
    PORT
      LAYER M5 ;
        RECT  362.4 0 362.424 0.084 ;
    END
  END s0a[287]
  PIN s0a[288]
    DIRECTION INPUT ;
    USE SIGNAL ;
    PORT
      LAYER M5 ;
        RECT  363.552 0 363.576 0.084 ;
    END
  END s0a[288]
  PIN s0a[289]
    DIRECTION INPUT ;
    USE SIGNAL ;
    PORT
      LAYER M5 ;
        RECT  364.752 0 364.776 0.084 ;
    END
  END s0a[289]
  PIN s0a[28]
    DIRECTION INPUT ;
    USE SIGNAL ;
    PORT
      LAYER M5 ;
        RECT  55.392 0 55.416 0.084 ;
    END
  END s0a[28]
  PIN s0a[290]
    DIRECTION INPUT ;
    USE SIGNAL ;
    PORT
      LAYER M5 ;
        RECT  365.952 0 365.976 0.084 ;
    END
  END s0a[290]
  PIN s0a[291]
    DIRECTION INPUT ;
    USE SIGNAL ;
    PORT
      LAYER M5 ;
        RECT  367.152 0 367.176 0.084 ;
    END
  END s0a[291]
  PIN s0a[292]
    DIRECTION INPUT ;
    USE SIGNAL ;
    PORT
      LAYER M5 ;
        RECT  368.304 0 368.328 0.084 ;
    END
  END s0a[292]
  PIN s0a[293]
    DIRECTION INPUT ;
    USE SIGNAL ;
    PORT
      LAYER M5 ;
        RECT  369.504 0 369.528 0.084 ;
    END
  END s0a[293]
  PIN s0a[294]
    DIRECTION INPUT ;
    USE SIGNAL ;
    PORT
      LAYER M5 ;
        RECT  370.656 0 370.68 0.084 ;
    END
  END s0a[294]
  PIN s0a[295]
    DIRECTION INPUT ;
    USE SIGNAL ;
    PORT
      LAYER M5 ;
        RECT  371.856 0 371.88 0.084 ;
    END
  END s0a[295]
  PIN s0a[296]
    DIRECTION INPUT ;
    USE SIGNAL ;
    PORT
      LAYER M5 ;
        RECT  373.056 0 373.08 0.084 ;
    END
  END s0a[296]
  PIN s0a[297]
    DIRECTION INPUT ;
    USE SIGNAL ;
    PORT
      LAYER M5 ;
        RECT  374.256 0 374.28 0.084 ;
    END
  END s0a[297]
  PIN s0a[298]
    DIRECTION INPUT ;
    USE SIGNAL ;
    PORT
      LAYER M5 ;
        RECT  375.408 0 375.432 0.084 ;
    END
  END s0a[298]
  PIN s0a[299]
    DIRECTION INPUT ;
    USE SIGNAL ;
    PORT
      LAYER M5 ;
        RECT  376.608 0 376.632 0.084 ;
    END
  END s0a[299]
  PIN s0a[29]
    DIRECTION INPUT ;
    USE SIGNAL ;
    PORT
      LAYER M5 ;
        RECT  56.544 0 56.568 0.084 ;
    END
  END s0a[29]
  PIN s0a[2]
    DIRECTION INPUT ;
    USE SIGNAL ;
    PORT
      LAYER M5 ;
        RECT  24.528 0 24.552 0.084 ;
    END
  END s0a[2]
  PIN s0a[300]
    DIRECTION INPUT ;
    USE SIGNAL ;
    PORT
      LAYER M5 ;
        RECT  377.808 0 377.832 0.084 ;
    END
  END s0a[300]
  PIN s0a[301]
    DIRECTION INPUT ;
    USE SIGNAL ;
    PORT
      LAYER M5 ;
        RECT  378.96 0 378.984 0.084 ;
    END
  END s0a[301]
  PIN s0a[302]
    DIRECTION INPUT ;
    USE SIGNAL ;
    PORT
      LAYER M5 ;
        RECT  380.16 0 380.184 0.084 ;
    END
  END s0a[302]
  PIN s0a[303]
    DIRECTION INPUT ;
    USE SIGNAL ;
    PORT
      LAYER M5 ;
        RECT  381.36 0 381.384 0.084 ;
    END
  END s0a[303]
  PIN s0a[304]
    DIRECTION INPUT ;
    USE SIGNAL ;
    PORT
      LAYER M5 ;
        RECT  382.512 0 382.536 0.084 ;
    END
  END s0a[304]
  PIN s0a[305]
    DIRECTION INPUT ;
    USE SIGNAL ;
    PORT
      LAYER M5 ;
        RECT  383.712 0 383.736 0.084 ;
    END
  END s0a[305]
  PIN s0a[306]
    DIRECTION INPUT ;
    USE SIGNAL ;
    PORT
      LAYER M5 ;
        RECT  384.912 0 384.936 0.084 ;
    END
  END s0a[306]
  PIN s0a[307]
    DIRECTION INPUT ;
    USE SIGNAL ;
    PORT
      LAYER M5 ;
        RECT  386.112 0 386.136 0.084 ;
    END
  END s0a[307]
  PIN s0a[308]
    DIRECTION INPUT ;
    USE SIGNAL ;
    PORT
      LAYER M5 ;
        RECT  387.264 0 387.288 0.084 ;
    END
  END s0a[308]
  PIN s0a[309]
    DIRECTION INPUT ;
    USE SIGNAL ;
    PORT
      LAYER M5 ;
        RECT  388.464 0 388.488 0.084 ;
    END
  END s0a[309]
  PIN s0a[30]
    DIRECTION INPUT ;
    USE SIGNAL ;
    PORT
      LAYER M5 ;
        RECT  57.744 0 57.768 0.084 ;
    END
  END s0a[30]
  PIN s0a[310]
    DIRECTION INPUT ;
    USE SIGNAL ;
    PORT
      LAYER M5 ;
        RECT  389.664 0 389.688 0.084 ;
    END
  END s0a[310]
  PIN s0a[311]
    DIRECTION INPUT ;
    USE SIGNAL ;
    PORT
      LAYER M5 ;
        RECT  390.816 0 390.84 0.084 ;
    END
  END s0a[311]
  PIN s0a[312]
    DIRECTION INPUT ;
    USE SIGNAL ;
    PORT
      LAYER M5 ;
        RECT  392.016 0 392.04 0.084 ;
    END
  END s0a[312]
  PIN s0a[313]
    DIRECTION INPUT ;
    USE SIGNAL ;
    PORT
      LAYER M5 ;
        RECT  393.216 0 393.24 0.084 ;
    END
  END s0a[313]
  PIN s0a[314]
    DIRECTION INPUT ;
    USE SIGNAL ;
    PORT
      LAYER M5 ;
        RECT  394.368 0 394.392 0.084 ;
    END
  END s0a[314]
  PIN s0a[315]
    DIRECTION INPUT ;
    USE SIGNAL ;
    PORT
      LAYER M5 ;
        RECT  395.568 0 395.592 0.084 ;
    END
  END s0a[315]
  PIN s0a[316]
    DIRECTION INPUT ;
    USE SIGNAL ;
    PORT
      LAYER M5 ;
        RECT  396.768 0 396.792 0.084 ;
    END
  END s0a[316]
  PIN s0a[317]
    DIRECTION INPUT ;
    USE SIGNAL ;
    PORT
      LAYER M5 ;
        RECT  397.92 0 397.944 0.084 ;
    END
  END s0a[317]
  PIN s0a[318]
    DIRECTION INPUT ;
    USE SIGNAL ;
    PORT
      LAYER M5 ;
        RECT  399.12 0 399.144 0.084 ;
    END
  END s0a[318]
  PIN s0a[319]
    DIRECTION INPUT ;
    USE SIGNAL ;
    PORT
      LAYER M5 ;
        RECT  400.32 0 400.344 0.084 ;
    END
  END s0a[319]
  PIN s0a[31]
    DIRECTION INPUT ;
    USE SIGNAL ;
    PORT
      LAYER M5 ;
        RECT  58.944 0 58.968 0.084 ;
    END
  END s0a[31]
  PIN s0a[320]
    DIRECTION INPUT ;
    USE SIGNAL ;
    PORT
      LAYER M5 ;
        RECT  401.52 0 401.544 0.084 ;
    END
  END s0a[320]
  PIN s0a[321]
    DIRECTION INPUT ;
    USE SIGNAL ;
    PORT
      LAYER M5 ;
        RECT  402.672 0 402.696 0.084 ;
    END
  END s0a[321]
  PIN s0a[322]
    DIRECTION INPUT ;
    USE SIGNAL ;
    PORT
      LAYER M5 ;
        RECT  403.872 0 403.896 0.084 ;
    END
  END s0a[322]
  PIN s0a[323]
    DIRECTION INPUT ;
    USE SIGNAL ;
    PORT
      LAYER M5 ;
        RECT  405.12 0 405.144 0.084 ;
    END
  END s0a[323]
  PIN s0a[324]
    DIRECTION INPUT ;
    USE SIGNAL ;
    PORT
      LAYER M5 ;
        RECT  406.224 0 406.248 0.084 ;
    END
  END s0a[324]
  PIN s0a[325]
    DIRECTION INPUT ;
    USE SIGNAL ;
    PORT
      LAYER M5 ;
        RECT  407.424 0 407.448 0.084 ;
    END
  END s0a[325]
  PIN s0a[326]
    DIRECTION INPUT ;
    USE SIGNAL ;
    PORT
      LAYER M5 ;
        RECT  408.624 0 408.648 0.084 ;
    END
  END s0a[326]
  PIN s0a[327]
    DIRECTION INPUT ;
    USE SIGNAL ;
    PORT
      LAYER M5 ;
        RECT  409.776 0 409.8 0.084 ;
    END
  END s0a[327]
  PIN s0a[32]
    DIRECTION INPUT ;
    USE SIGNAL ;
    PORT
      LAYER M5 ;
        RECT  60.096 0 60.12 0.084 ;
    END
  END s0a[32]
  PIN s0a[33]
    DIRECTION INPUT ;
    USE SIGNAL ;
    PORT
      LAYER M5 ;
        RECT  61.296 0 61.32 0.084 ;
    END
  END s0a[33]
  PIN s0a[34]
    DIRECTION INPUT ;
    USE SIGNAL ;
    PORT
      LAYER M5 ;
        RECT  62.496 0 62.52 0.084 ;
    END
  END s0a[34]
  PIN s0a[35]
    DIRECTION INPUT ;
    USE SIGNAL ;
    PORT
      LAYER M5 ;
        RECT  63.648 0 63.672 0.084 ;
    END
  END s0a[35]
  PIN s0a[36]
    DIRECTION INPUT ;
    USE SIGNAL ;
    PORT
      LAYER M5 ;
        RECT  64.848 0 64.872 0.084 ;
    END
  END s0a[36]
  PIN s0a[37]
    DIRECTION INPUT ;
    USE SIGNAL ;
    PORT
      LAYER M5 ;
        RECT  66.048 0 66.072 0.084 ;
    END
  END s0a[37]
  PIN s0a[38]
    DIRECTION INPUT ;
    USE SIGNAL ;
    PORT
      LAYER M5 ;
        RECT  67.248 0 67.272 0.084 ;
    END
  END s0a[38]
  PIN s0a[39]
    DIRECTION INPUT ;
    USE SIGNAL ;
    PORT
      LAYER M5 ;
        RECT  68.4 0 68.424 0.084 ;
    END
  END s0a[39]
  PIN s0a[3]
    DIRECTION INPUT ;
    USE SIGNAL ;
    PORT
      LAYER M5 ;
        RECT  25.728 0 25.752 0.084 ;
    END
  END s0a[3]
  PIN s0a[40]
    DIRECTION INPUT ;
    USE SIGNAL ;
    PORT
      LAYER M5 ;
        RECT  69.6 0 69.624 0.084 ;
    END
  END s0a[40]
  PIN s0a[41]
    DIRECTION INPUT ;
    USE SIGNAL ;
    PORT
      LAYER M5 ;
        RECT  70.8 0 70.824 0.084 ;
    END
  END s0a[41]
  PIN s0a[42]
    DIRECTION INPUT ;
    USE SIGNAL ;
    PORT
      LAYER M5 ;
        RECT  71.952 0 71.976 0.084 ;
    END
  END s0a[42]
  PIN s0a[43]
    DIRECTION INPUT ;
    USE SIGNAL ;
    PORT
      LAYER M5 ;
        RECT  73.152 0 73.176 0.084 ;
    END
  END s0a[43]
  PIN s0a[44]
    DIRECTION INPUT ;
    USE SIGNAL ;
    PORT
      LAYER M5 ;
        RECT  74.352 0 74.376 0.084 ;
    END
  END s0a[44]
  PIN s0a[45]
    DIRECTION INPUT ;
    USE SIGNAL ;
    PORT
      LAYER M5 ;
        RECT  75.552 0 75.576 0.084 ;
    END
  END s0a[45]
  PIN s0a[46]
    DIRECTION INPUT ;
    USE SIGNAL ;
    PORT
      LAYER M5 ;
        RECT  76.704 0 76.728 0.084 ;
    END
  END s0a[46]
  PIN s0a[47]
    DIRECTION INPUT ;
    USE SIGNAL ;
    PORT
      LAYER M5 ;
        RECT  77.904 0 77.928 0.084 ;
    END
  END s0a[47]
  PIN s0a[48]
    DIRECTION INPUT ;
    USE SIGNAL ;
    PORT
      LAYER M5 ;
        RECT  79.056 0 79.08 0.084 ;
    END
  END s0a[48]
  PIN s0a[49]
    DIRECTION INPUT ;
    USE SIGNAL ;
    PORT
      LAYER M5 ;
        RECT  80.256 0 80.28 0.084 ;
    END
  END s0a[49]
  PIN s0a[4]
    DIRECTION INPUT ;
    USE SIGNAL ;
    PORT
      LAYER M5 ;
        RECT  26.976 0 27 0.084 ;
    END
  END s0a[4]
  PIN s0a[50]
    DIRECTION INPUT ;
    USE SIGNAL ;
    PORT
      LAYER M5 ;
        RECT  81.456 0 81.48 0.084 ;
    END
  END s0a[50]
  PIN s0a[51]
    DIRECTION INPUT ;
    USE SIGNAL ;
    PORT
      LAYER M5 ;
        RECT  82.656 0 82.68 0.084 ;
    END
  END s0a[51]
  PIN s0a[52]
    DIRECTION INPUT ;
    USE SIGNAL ;
    PORT
      LAYER M5 ;
        RECT  83.808 0 83.832 0.084 ;
    END
  END s0a[52]
  PIN s0a[53]
    DIRECTION INPUT ;
    USE SIGNAL ;
    PORT
      LAYER M5 ;
        RECT  85.008 0 85.032 0.084 ;
    END
  END s0a[53]
  PIN s0a[54]
    DIRECTION INPUT ;
    USE SIGNAL ;
    PORT
      LAYER M5 ;
        RECT  86.208 0 86.232 0.084 ;
    END
  END s0a[54]
  PIN s0a[55]
    DIRECTION INPUT ;
    USE SIGNAL ;
    PORT
      LAYER M5 ;
        RECT  87.36 0 87.384 0.084 ;
    END
  END s0a[55]
  PIN s0a[56]
    DIRECTION INPUT ;
    USE SIGNAL ;
    PORT
      LAYER M5 ;
        RECT  88.56 0 88.584 0.084 ;
    END
  END s0a[56]
  PIN s0a[57]
    DIRECTION INPUT ;
    USE SIGNAL ;
    PORT
      LAYER M5 ;
        RECT  89.76 0 89.784 0.084 ;
    END
  END s0a[57]
  PIN s0a[58]
    DIRECTION INPUT ;
    USE SIGNAL ;
    PORT
      LAYER M5 ;
        RECT  90.912 0 90.936 0.084 ;
    END
  END s0a[58]
  PIN s0a[59]
    DIRECTION INPUT ;
    USE SIGNAL ;
    PORT
      LAYER M5 ;
        RECT  92.112 0 92.136 0.084 ;
    END
  END s0a[59]
  PIN s0a[5]
    DIRECTION INPUT ;
    USE SIGNAL ;
    PORT
      LAYER M5 ;
        RECT  28.128 0 28.152 0.084 ;
    END
  END s0a[5]
  PIN s0a[60]
    DIRECTION INPUT ;
    USE SIGNAL ;
    PORT
      LAYER M5 ;
        RECT  93.312 0 93.336 0.084 ;
    END
  END s0a[60]
  PIN s0a[61]
    DIRECTION INPUT ;
    USE SIGNAL ;
    PORT
      LAYER M5 ;
        RECT  94.512 0 94.536 0.084 ;
    END
  END s0a[61]
  PIN s0a[62]
    DIRECTION INPUT ;
    USE SIGNAL ;
    PORT
      LAYER M5 ;
        RECT  95.664 0 95.688 0.084 ;
    END
  END s0a[62]
  PIN s0a[63]
    DIRECTION INPUT ;
    USE SIGNAL ;
    PORT
      LAYER M5 ;
        RECT  96.864 0 96.888 0.084 ;
    END
  END s0a[63]
  PIN s0a[64]
    DIRECTION INPUT ;
    USE SIGNAL ;
    PORT
      LAYER M5 ;
        RECT  98.064 0 98.088 0.084 ;
    END
  END s0a[64]
  PIN s0a[65]
    DIRECTION INPUT ;
    USE SIGNAL ;
    PORT
      LAYER M5 ;
        RECT  99.216 0 99.24 0.084 ;
    END
  END s0a[65]
  PIN s0a[66]
    DIRECTION INPUT ;
    USE SIGNAL ;
    PORT
      LAYER M5 ;
        RECT  100.416 0 100.44 0.084 ;
    END
  END s0a[66]
  PIN s0a[67]
    DIRECTION INPUT ;
    USE SIGNAL ;
    PORT
      LAYER M5 ;
        RECT  101.616 0 101.64 0.084 ;
    END
  END s0a[67]
  PIN s0a[68]
    DIRECTION INPUT ;
    USE SIGNAL ;
    PORT
      LAYER M5 ;
        RECT  102.768 0 102.792 0.084 ;
    END
  END s0a[68]
  PIN s0a[69]
    DIRECTION INPUT ;
    USE SIGNAL ;
    PORT
      LAYER M5 ;
        RECT  103.968 0 103.992 0.084 ;
    END
  END s0a[69]
  PIN s0a[6]
    DIRECTION INPUT ;
    USE SIGNAL ;
    PORT
      LAYER M5 ;
        RECT  29.28 0 29.304 0.084 ;
    END
  END s0a[6]
  PIN s0a[70]
    DIRECTION INPUT ;
    USE SIGNAL ;
    PORT
      LAYER M5 ;
        RECT  105.168 0 105.192 0.084 ;
    END
  END s0a[70]
  PIN s0a[71]
    DIRECTION INPUT ;
    USE SIGNAL ;
    PORT
      LAYER M5 ;
        RECT  106.32 0 106.344 0.084 ;
    END
  END s0a[71]
  PIN s0a[72]
    DIRECTION INPUT ;
    USE SIGNAL ;
    PORT
      LAYER M5 ;
        RECT  107.52 0 107.544 0.084 ;
    END
  END s0a[72]
  PIN s0a[73]
    DIRECTION INPUT ;
    USE SIGNAL ;
    PORT
      LAYER M5 ;
        RECT  108.72 0 108.744 0.084 ;
    END
  END s0a[73]
  PIN s0a[74]
    DIRECTION INPUT ;
    USE SIGNAL ;
    PORT
      LAYER M5 ;
        RECT  109.92 0 109.944 0.084 ;
    END
  END s0a[74]
  PIN s0a[75]
    DIRECTION INPUT ;
    USE SIGNAL ;
    PORT
      LAYER M5 ;
        RECT  111.072 0 111.096 0.084 ;
    END
  END s0a[75]
  PIN s0a[76]
    DIRECTION INPUT ;
    USE SIGNAL ;
    PORT
      LAYER M5 ;
        RECT  112.272 0 112.296 0.084 ;
    END
  END s0a[76]
  PIN s0a[77]
    DIRECTION INPUT ;
    USE SIGNAL ;
    PORT
      LAYER M5 ;
        RECT  113.52 0 113.544 0.084 ;
    END
  END s0a[77]
  PIN s0a[78]
    DIRECTION INPUT ;
    USE SIGNAL ;
    PORT
      LAYER M5 ;
        RECT  114.624 0 114.648 0.084 ;
    END
  END s0a[78]
  PIN s0a[79]
    DIRECTION INPUT ;
    USE SIGNAL ;
    PORT
      LAYER M5 ;
        RECT  115.824 0 115.848 0.084 ;
    END
  END s0a[79]
  PIN s0a[7]
    DIRECTION INPUT ;
    USE SIGNAL ;
    PORT
      LAYER M5 ;
        RECT  30.48 0 30.504 0.084 ;
    END
  END s0a[7]
  PIN s0a[80]
    DIRECTION INPUT ;
    USE SIGNAL ;
    PORT
      LAYER M5 ;
        RECT  117.024 0 117.048 0.084 ;
    END
  END s0a[80]
  PIN s0a[81]
    DIRECTION INPUT ;
    USE SIGNAL ;
    PORT
      LAYER M5 ;
        RECT  118.176 0 118.2 0.084 ;
    END
  END s0a[81]
  PIN s0a[82]
    DIRECTION INPUT ;
    USE SIGNAL ;
    PORT
      LAYER M5 ;
        RECT  119.376 0 119.4 0.084 ;
    END
  END s0a[82]
  PIN s0a[83]
    DIRECTION INPUT ;
    USE SIGNAL ;
    PORT
      LAYER M5 ;
        RECT  120.576 0 120.6 0.084 ;
    END
  END s0a[83]
  PIN s0a[84]
    DIRECTION INPUT ;
    USE SIGNAL ;
    PORT
      LAYER M5 ;
        RECT  121.728 0 121.752 0.084 ;
    END
  END s0a[84]
  PIN s0a[85]
    DIRECTION INPUT ;
    USE SIGNAL ;
    PORT
      LAYER M5 ;
        RECT  122.928 0 122.952 0.084 ;
    END
  END s0a[85]
  PIN s0a[86]
    DIRECTION INPUT ;
    USE SIGNAL ;
    PORT
      LAYER M5 ;
        RECT  124.176 0 124.2 0.084 ;
    END
  END s0a[86]
  PIN s0a[87]
    DIRECTION INPUT ;
    USE SIGNAL ;
    PORT
      LAYER M5 ;
        RECT  125.328 0 125.352 0.084 ;
    END
  END s0a[87]
  PIN s0a[88]
    DIRECTION INPUT ;
    USE SIGNAL ;
    PORT
      LAYER M5 ;
        RECT  126.48 0 126.504 0.084 ;
    END
  END s0a[88]
  PIN s0a[89]
    DIRECTION INPUT ;
    USE SIGNAL ;
    PORT
      LAYER M5 ;
        RECT  127.68 0 127.704 0.084 ;
    END
  END s0a[89]
  PIN s0a[8]
    DIRECTION INPUT ;
    USE SIGNAL ;
    PORT
      LAYER M5 ;
        RECT  31.68 0 31.704 0.084 ;
    END
  END s0a[8]
  PIN s0a[90]
    DIRECTION INPUT ;
    USE SIGNAL ;
    PORT
      LAYER M5 ;
        RECT  128.88 0 128.904 0.084 ;
    END
  END s0a[90]
  PIN s0a[91]
    DIRECTION INPUT ;
    USE SIGNAL ;
    PORT
      LAYER M5 ;
        RECT  130.032 0 130.056 0.084 ;
    END
  END s0a[91]
  PIN s0a[92]
    DIRECTION INPUT ;
    USE SIGNAL ;
    PORT
      LAYER M5 ;
        RECT  131.232 0 131.256 0.084 ;
    END
  END s0a[92]
  PIN s0a[93]
    DIRECTION INPUT ;
    USE SIGNAL ;
    PORT
      LAYER M5 ;
        RECT  132.432 0 132.456 0.084 ;
    END
  END s0a[93]
  PIN s0a[94]
    DIRECTION INPUT ;
    USE SIGNAL ;
    PORT
      LAYER M5 ;
        RECT  133.584 0 133.608 0.084 ;
    END
  END s0a[94]
  PIN s0a[95]
    DIRECTION INPUT ;
    USE SIGNAL ;
    PORT
      LAYER M5 ;
        RECT  134.784 0 134.808 0.084 ;
    END
  END s0a[95]
  PIN s0a[96]
    DIRECTION INPUT ;
    USE SIGNAL ;
    PORT
      LAYER M5 ;
        RECT  135.984 0 136.008 0.084 ;
    END
  END s0a[96]
  PIN s0a[97]
    DIRECTION INPUT ;
    USE SIGNAL ;
    PORT
      LAYER M5 ;
        RECT  137.184 0 137.208 0.084 ;
    END
  END s0a[97]
  PIN s0a[98]
    DIRECTION INPUT ;
    USE SIGNAL ;
    PORT
      LAYER M5 ;
        RECT  138.336 0 138.36 0.084 ;
    END
  END s0a[98]
  PIN s0a[99]
    DIRECTION INPUT ;
    USE SIGNAL ;
    PORT
      LAYER M5 ;
        RECT  139.536 0 139.56 0.084 ;
    END
  END s0a[99]
  PIN s0a[9]
    DIRECTION INPUT ;
    USE SIGNAL ;
    PORT
      LAYER M5 ;
        RECT  32.832 0 32.856 0.084 ;
    END
  END s0a[9]
  PIN s0b[0]
    DIRECTION INPUT ;
    USE SIGNAL ;
    PORT
      LAYER M5 ;
        RECT  22.224 0 22.248 0.084 ;
    END
  END s0b[0]
  PIN s0b[100]
    DIRECTION INPUT ;
    USE SIGNAL ;
    PORT
      LAYER M5 ;
        RECT  140.784 0 140.808 0.084 ;
    END
  END s0b[100]
  PIN s0b[101]
    DIRECTION INPUT ;
    USE SIGNAL ;
    PORT
      LAYER M5 ;
        RECT  141.936 0 141.96 0.084 ;
    END
  END s0b[101]
  PIN s0b[102]
    DIRECTION INPUT ;
    USE SIGNAL ;
    PORT
      LAYER M5 ;
        RECT  143.136 0 143.16 0.084 ;
    END
  END s0b[102]
  PIN s0b[103]
    DIRECTION INPUT ;
    USE SIGNAL ;
    PORT
      LAYER M5 ;
        RECT  144.336 0 144.36 0.084 ;
    END
  END s0b[103]
  PIN s0b[104]
    DIRECTION INPUT ;
    USE SIGNAL ;
    PORT
      LAYER M5 ;
        RECT  145.488 0 145.512 0.084 ;
    END
  END s0b[104]
  PIN s0b[105]
    DIRECTION INPUT ;
    USE SIGNAL ;
    PORT
      LAYER M5 ;
        RECT  146.688 0 146.712 0.084 ;
    END
  END s0b[105]
  PIN s0b[106]
    DIRECTION INPUT ;
    USE SIGNAL ;
    PORT
      LAYER M5 ;
        RECT  147.888 0 147.912 0.084 ;
    END
  END s0b[106]
  PIN s0b[107]
    DIRECTION INPUT ;
    USE SIGNAL ;
    PORT
      LAYER M5 ;
        RECT  149.04 0 149.064 0.084 ;
    END
  END s0b[107]
  PIN s0b[108]
    DIRECTION INPUT ;
    USE SIGNAL ;
    PORT
      LAYER M5 ;
        RECT  150.24 0 150.264 0.084 ;
    END
  END s0b[108]
  PIN s0b[109]
    DIRECTION INPUT ;
    USE SIGNAL ;
    PORT
      LAYER M5 ;
        RECT  151.344 0 151.368 0.084 ;
    END
  END s0b[109]
  PIN s0b[10]
    DIRECTION INPUT ;
    USE SIGNAL ;
    PORT
      LAYER M5 ;
        RECT  34.08 0 34.104 0.084 ;
    END
  END s0b[10]
  PIN s0b[110]
    DIRECTION INPUT ;
    USE SIGNAL ;
    PORT
      LAYER M5 ;
        RECT  152.64 0 152.664 0.084 ;
    END
  END s0b[110]
  PIN s0b[111]
    DIRECTION INPUT ;
    USE SIGNAL ;
    PORT
      LAYER M5 ;
        RECT  153.792 0 153.816 0.084 ;
    END
  END s0b[111]
  PIN s0b[112]
    DIRECTION INPUT ;
    USE SIGNAL ;
    PORT
      LAYER M5 ;
        RECT  154.992 0 155.016 0.084 ;
    END
  END s0b[112]
  PIN s0b[113]
    DIRECTION INPUT ;
    USE SIGNAL ;
    PORT
      LAYER M5 ;
        RECT  156.192 0 156.216 0.084 ;
    END
  END s0b[113]
  PIN s0b[114]
    DIRECTION INPUT ;
    USE SIGNAL ;
    PORT
      LAYER M5 ;
        RECT  157.344 0 157.368 0.084 ;
    END
  END s0b[114]
  PIN s0b[115]
    DIRECTION INPUT ;
    USE SIGNAL ;
    PORT
      LAYER M5 ;
        RECT  158.544 0 158.568 0.084 ;
    END
  END s0b[115]
  PIN s0b[116]
    DIRECTION INPUT ;
    USE SIGNAL ;
    PORT
      LAYER M5 ;
        RECT  159.744 0 159.768 0.084 ;
    END
  END s0b[116]
  PIN s0b[117]
    DIRECTION INPUT ;
    USE SIGNAL ;
    PORT
      LAYER M5 ;
        RECT  160.896 0 160.92 0.084 ;
    END
  END s0b[117]
  PIN s0b[118]
    DIRECTION INPUT ;
    USE SIGNAL ;
    PORT
      LAYER M5 ;
        RECT  162 0 162.024 0.084 ;
    END
  END s0b[118]
  PIN s0b[119]
    DIRECTION INPUT ;
    USE SIGNAL ;
    PORT
      LAYER M5 ;
        RECT  163.296 0 163.32 0.084 ;
    END
  END s0b[119]
  PIN s0b[11]
    DIRECTION INPUT ;
    USE SIGNAL ;
    PORT
      LAYER M5 ;
        RECT  35.28 0 35.304 0.084 ;
    END
  END s0b[11]
  PIN s0b[120]
    DIRECTION INPUT ;
    USE SIGNAL ;
    PORT
      LAYER M5 ;
        RECT  164.496 0 164.52 0.084 ;
    END
  END s0b[120]
  PIN s0b[121]
    DIRECTION INPUT ;
    USE SIGNAL ;
    PORT
      LAYER M5 ;
        RECT  165.648 0 165.672 0.084 ;
    END
  END s0b[121]
  PIN s0b[122]
    DIRECTION INPUT ;
    USE SIGNAL ;
    PORT
      LAYER M5 ;
        RECT  166.848 0 166.872 0.084 ;
    END
  END s0b[122]
  PIN s0b[123]
    DIRECTION INPUT ;
    USE SIGNAL ;
    PORT
      LAYER M5 ;
        RECT  168.048 0 168.072 0.084 ;
    END
  END s0b[123]
  PIN s0b[124]
    DIRECTION INPUT ;
    USE SIGNAL ;
    PORT
      LAYER M5 ;
        RECT  169.2 0 169.224 0.084 ;
    END
  END s0b[124]
  PIN s0b[125]
    DIRECTION INPUT ;
    USE SIGNAL ;
    PORT
      LAYER M5 ;
        RECT  170.4 0 170.424 0.084 ;
    END
  END s0b[125]
  PIN s0b[126]
    DIRECTION INPUT ;
    USE SIGNAL ;
    PORT
      LAYER M5 ;
        RECT  171.6 0 171.624 0.084 ;
    END
  END s0b[126]
  PIN s0b[127]
    DIRECTION INPUT ;
    USE SIGNAL ;
    PORT
      LAYER M5 ;
        RECT  172.656 0 172.68 0.084 ;
    END
  END s0b[127]
  PIN s0b[128]
    DIRECTION INPUT ;
    USE SIGNAL ;
    PORT
      LAYER M5 ;
        RECT  173.952 0 173.976 0.084 ;
    END
  END s0b[128]
  PIN s0b[129]
    DIRECTION INPUT ;
    USE SIGNAL ;
    PORT
      LAYER M5 ;
        RECT  175.152 0 175.176 0.084 ;
    END
  END s0b[129]
  PIN s0b[12]
    DIRECTION INPUT ;
    USE SIGNAL ;
    PORT
      LAYER M5 ;
        RECT  36.432 0 36.456 0.084 ;
    END
  END s0b[12]
  PIN s0b[130]
    DIRECTION INPUT ;
    USE SIGNAL ;
    PORT
      LAYER M5 ;
        RECT  176.304 0 176.328 0.084 ;
    END
  END s0b[130]
  PIN s0b[131]
    DIRECTION INPUT ;
    USE SIGNAL ;
    PORT
      LAYER M5 ;
        RECT  177.504 0 177.528 0.084 ;
    END
  END s0b[131]
  PIN s0b[132]
    DIRECTION INPUT ;
    USE SIGNAL ;
    PORT
      LAYER M5 ;
        RECT  178.704 0 178.728 0.084 ;
    END
  END s0b[132]
  PIN s0b[133]
    DIRECTION INPUT ;
    USE SIGNAL ;
    PORT
      LAYER M5 ;
        RECT  179.904 0 179.928 0.084 ;
    END
  END s0b[133]
  PIN s0b[134]
    DIRECTION INPUT ;
    USE SIGNAL ;
    PORT
      LAYER M5 ;
        RECT  181.056 0 181.08 0.084 ;
    END
  END s0b[134]
  PIN s0b[135]
    DIRECTION INPUT ;
    USE SIGNAL ;
    PORT
      LAYER M5 ;
        RECT  182.256 0 182.28 0.084 ;
    END
  END s0b[135]
  PIN s0b[136]
    DIRECTION INPUT ;
    USE SIGNAL ;
    PORT
      LAYER M5 ;
        RECT  183.456 0 183.48 0.084 ;
    END
  END s0b[136]
  PIN s0b[137]
    DIRECTION INPUT ;
    USE SIGNAL ;
    PORT
      LAYER M5 ;
        RECT  184.608 0 184.632 0.084 ;
    END
  END s0b[137]
  PIN s0b[138]
    DIRECTION INPUT ;
    USE SIGNAL ;
    PORT
      LAYER M5 ;
        RECT  185.808 0 185.832 0.084 ;
    END
  END s0b[138]
  PIN s0b[139]
    DIRECTION INPUT ;
    USE SIGNAL ;
    PORT
      LAYER M5 ;
        RECT  187.008 0 187.032 0.084 ;
    END
  END s0b[139]
  PIN s0b[13]
    DIRECTION INPUT ;
    USE SIGNAL ;
    PORT
      LAYER M5 ;
        RECT  37.632 0 37.656 0.084 ;
    END
  END s0b[13]
  PIN s0b[140]
    DIRECTION INPUT ;
    USE SIGNAL ;
    PORT
      LAYER M5 ;
        RECT  188.16 0 188.184 0.084 ;
    END
  END s0b[140]
  PIN s0b[141]
    DIRECTION INPUT ;
    USE SIGNAL ;
    PORT
      LAYER M5 ;
        RECT  189.36 0 189.384 0.084 ;
    END
  END s0b[141]
  PIN s0b[142]
    DIRECTION INPUT ;
    USE SIGNAL ;
    PORT
      LAYER M5 ;
        RECT  190.56 0 190.584 0.084 ;
    END
  END s0b[142]
  PIN s0b[143]
    DIRECTION INPUT ;
    USE SIGNAL ;
    PORT
      LAYER M5 ;
        RECT  191.76 0 191.784 0.084 ;
    END
  END s0b[143]
  PIN s0b[144]
    DIRECTION INPUT ;
    USE SIGNAL ;
    PORT
      LAYER M5 ;
        RECT  192.912 0 192.936 0.084 ;
    END
  END s0b[144]
  PIN s0b[145]
    DIRECTION INPUT ;
    USE SIGNAL ;
    PORT
      LAYER M5 ;
        RECT  194.112 0 194.136 0.084 ;
    END
  END s0b[145]
  PIN s0b[146]
    DIRECTION INPUT ;
    USE SIGNAL ;
    PORT
      LAYER M5 ;
        RECT  195.312 0 195.336 0.084 ;
    END
  END s0b[146]
  PIN s0b[147]
    DIRECTION INPUT ;
    USE SIGNAL ;
    PORT
      LAYER M5 ;
        RECT  196.464 0 196.488 0.084 ;
    END
  END s0b[147]
  PIN s0b[148]
    DIRECTION INPUT ;
    USE SIGNAL ;
    PORT
      LAYER M5 ;
        RECT  197.664 0 197.688 0.084 ;
    END
  END s0b[148]
  PIN s0b[149]
    DIRECTION INPUT ;
    USE SIGNAL ;
    PORT
      LAYER M5 ;
        RECT  198.864 0 198.888 0.084 ;
    END
  END s0b[149]
  PIN s0b[14]
    DIRECTION INPUT ;
    USE SIGNAL ;
    PORT
      LAYER M5 ;
        RECT  38.832 0 38.856 0.084 ;
    END
  END s0b[14]
  PIN s0b[150]
    DIRECTION INPUT ;
    USE SIGNAL ;
    PORT
      LAYER M5 ;
        RECT  200.016 0 200.04 0.084 ;
    END
  END s0b[150]
  PIN s0b[151]
    DIRECTION INPUT ;
    USE SIGNAL ;
    PORT
      LAYER M5 ;
        RECT  201.216 0 201.24 0.084 ;
    END
  END s0b[151]
  PIN s0b[152]
    DIRECTION INPUT ;
    USE SIGNAL ;
    PORT
      LAYER M5 ;
        RECT  202.416 0 202.44 0.084 ;
    END
  END s0b[152]
  PIN s0b[153]
    DIRECTION INPUT ;
    USE SIGNAL ;
    PORT
      LAYER M5 ;
        RECT  203.568 0 203.592 0.084 ;
    END
  END s0b[153]
  PIN s0b[154]
    DIRECTION INPUT ;
    USE SIGNAL ;
    PORT
      LAYER M5 ;
        RECT  204.768 0 204.792 0.084 ;
    END
  END s0b[154]
  PIN s0b[155]
    DIRECTION INPUT ;
    USE SIGNAL ;
    PORT
      LAYER M5 ;
        RECT  205.968 0 205.992 0.084 ;
    END
  END s0b[155]
  PIN s0b[156]
    DIRECTION INPUT ;
    USE SIGNAL ;
    PORT
      LAYER M5 ;
        RECT  207.168 0 207.192 0.084 ;
    END
  END s0b[156]
  PIN s0b[157]
    DIRECTION INPUT ;
    USE SIGNAL ;
    PORT
      LAYER M5 ;
        RECT  208.32 0 208.344 0.084 ;
    END
  END s0b[157]
  PIN s0b[158]
    DIRECTION INPUT ;
    USE SIGNAL ;
    PORT
      LAYER M5 ;
        RECT  209.52 0 209.544 0.084 ;
    END
  END s0b[158]
  PIN s0b[159]
    DIRECTION INPUT ;
    USE SIGNAL ;
    PORT
      LAYER M5 ;
        RECT  210.624 0 210.648 0.084 ;
    END
  END s0b[159]
  PIN s0b[15]
    DIRECTION INPUT ;
    USE SIGNAL ;
    PORT
      LAYER M5 ;
        RECT  40.032 0 40.056 0.084 ;
    END
  END s0b[15]
  PIN s0b[160]
    DIRECTION INPUT ;
    USE SIGNAL ;
    PORT
      LAYER M5 ;
        RECT  211.872 0 211.896 0.084 ;
    END
  END s0b[160]
  PIN s0b[161]
    DIRECTION INPUT ;
    USE SIGNAL ;
    PORT
      LAYER M5 ;
        RECT  213.072 0 213.096 0.084 ;
    END
  END s0b[161]
  PIN s0b[162]
    DIRECTION INPUT ;
    USE SIGNAL ;
    PORT
      LAYER M5 ;
        RECT  214.272 0 214.296 0.084 ;
    END
  END s0b[162]
  PIN s0b[163]
    DIRECTION INPUT ;
    USE SIGNAL ;
    PORT
      LAYER M5 ;
        RECT  215.424 0 215.448 0.084 ;
    END
  END s0b[163]
  PIN s0b[164]
    DIRECTION INPUT ;
    USE SIGNAL ;
    PORT
      LAYER M5 ;
        RECT  216.624 0 216.648 0.084 ;
    END
  END s0b[164]
  PIN s0b[165]
    DIRECTION INPUT ;
    USE SIGNAL ;
    PORT
      LAYER M5 ;
        RECT  217.824 0 217.848 0.084 ;
    END
  END s0b[165]
  PIN s0b[166]
    DIRECTION INPUT ;
    USE SIGNAL ;
    PORT
      LAYER M5 ;
        RECT  218.976 0 219 0.084 ;
    END
  END s0b[166]
  PIN s0b[167]
    DIRECTION INPUT ;
    USE SIGNAL ;
    PORT
      LAYER M5 ;
        RECT  220.176 0 220.2 0.084 ;
    END
  END s0b[167]
  PIN s0b[168]
    DIRECTION INPUT ;
    USE SIGNAL ;
    PORT
      LAYER M5 ;
        RECT  221.28 0 221.304 0.084 ;
    END
  END s0b[168]
  PIN s0b[169]
    DIRECTION INPUT ;
    USE SIGNAL ;
    PORT
      LAYER M5 ;
        RECT  222.576 0 222.6 0.084 ;
    END
  END s0b[169]
  PIN s0b[16]
    DIRECTION INPUT ;
    USE SIGNAL ;
    PORT
      LAYER M5 ;
        RECT  41.184 0 41.208 0.084 ;
    END
  END s0b[16]
  PIN s0b[170]
    DIRECTION INPUT ;
    USE SIGNAL ;
    PORT
      LAYER M5 ;
        RECT  223.728 0 223.752 0.084 ;
    END
  END s0b[170]
  PIN s0b[171]
    DIRECTION INPUT ;
    USE SIGNAL ;
    PORT
      LAYER M5 ;
        RECT  224.928 0 224.952 0.084 ;
    END
  END s0b[171]
  PIN s0b[172]
    DIRECTION INPUT ;
    USE SIGNAL ;
    PORT
      LAYER M5 ;
        RECT  226.128 0 226.152 0.084 ;
    END
  END s0b[172]
  PIN s0b[173]
    DIRECTION INPUT ;
    USE SIGNAL ;
    PORT
      LAYER M5 ;
        RECT  227.28 0 227.304 0.084 ;
    END
  END s0b[173]
  PIN s0b[174]
    DIRECTION INPUT ;
    USE SIGNAL ;
    PORT
      LAYER M5 ;
        RECT  228.48 0 228.504 0.084 ;
    END
  END s0b[174]
  PIN s0b[175]
    DIRECTION INPUT ;
    USE SIGNAL ;
    PORT
      LAYER M5 ;
        RECT  229.68 0 229.704 0.084 ;
    END
  END s0b[175]
  PIN s0b[176]
    DIRECTION INPUT ;
    USE SIGNAL ;
    PORT
      LAYER M5 ;
        RECT  230.832 0 230.856 0.084 ;
    END
  END s0b[176]
  PIN s0b[177]
    DIRECTION INPUT ;
    USE SIGNAL ;
    PORT
      LAYER M5 ;
        RECT  232.032 0 232.056 0.084 ;
    END
  END s0b[177]
  PIN s0b[178]
    DIRECTION INPUT ;
    USE SIGNAL ;
    PORT
      LAYER M5 ;
        RECT  233.232 0 233.256 0.084 ;
    END
  END s0b[178]
  PIN s0b[179]
    DIRECTION INPUT ;
    USE SIGNAL ;
    PORT
      LAYER M5 ;
        RECT  234.432 0 234.456 0.084 ;
    END
  END s0b[179]
  PIN s0b[17]
    DIRECTION INPUT ;
    USE SIGNAL ;
    PORT
      LAYER M5 ;
        RECT  42.384 0 42.408 0.084 ;
    END
  END s0b[17]
  PIN s0b[180]
    DIRECTION INPUT ;
    USE SIGNAL ;
    PORT
      LAYER M5 ;
        RECT  235.584 0 235.608 0.084 ;
    END
  END s0b[180]
  PIN s0b[181]
    DIRECTION INPUT ;
    USE SIGNAL ;
    PORT
      LAYER M5 ;
        RECT  236.784 0 236.808 0.084 ;
    END
  END s0b[181]
  PIN s0b[182]
    DIRECTION INPUT ;
    USE SIGNAL ;
    PORT
      LAYER M5 ;
        RECT  237.984 0 238.008 0.084 ;
    END
  END s0b[182]
  PIN s0b[183]
    DIRECTION INPUT ;
    USE SIGNAL ;
    PORT
      LAYER M5 ;
        RECT  239.136 0 239.16 0.084 ;
    END
  END s0b[183]
  PIN s0b[184]
    DIRECTION INPUT ;
    USE SIGNAL ;
    PORT
      LAYER M5 ;
        RECT  240.336 0 240.36 0.084 ;
    END
  END s0b[184]
  PIN s0b[185]
    DIRECTION INPUT ;
    USE SIGNAL ;
    PORT
      LAYER M5 ;
        RECT  241.536 0 241.56 0.084 ;
    END
  END s0b[185]
  PIN s0b[186]
    DIRECTION INPUT ;
    USE SIGNAL ;
    PORT
      LAYER M5 ;
        RECT  242.688 0 242.712 0.084 ;
    END
  END s0b[186]
  PIN s0b[187]
    DIRECTION INPUT ;
    USE SIGNAL ;
    PORT
      LAYER M5 ;
        RECT  243.888 0 243.912 0.084 ;
    END
  END s0b[187]
  PIN s0b[188]
    DIRECTION INPUT ;
    USE SIGNAL ;
    PORT
      LAYER M5 ;
        RECT  245.088 0 245.112 0.084 ;
    END
  END s0b[188]
  PIN s0b[189]
    DIRECTION INPUT ;
    USE SIGNAL ;
    PORT
      LAYER M5 ;
        RECT  246.24 0 246.264 0.084 ;
    END
  END s0b[189]
  PIN s0b[18]
    DIRECTION INPUT ;
    USE SIGNAL ;
    PORT
      LAYER M5 ;
        RECT  43.584 0 43.608 0.084 ;
    END
  END s0b[18]
  PIN s0b[190]
    DIRECTION INPUT ;
    USE SIGNAL ;
    PORT
      LAYER M5 ;
        RECT  247.44 0 247.464 0.084 ;
    END
  END s0b[190]
  PIN s0b[191]
    DIRECTION INPUT ;
    USE SIGNAL ;
    PORT
      LAYER M5 ;
        RECT  248.544 0 248.568 0.084 ;
    END
  END s0b[191]
  PIN s0b[192]
    DIRECTION INPUT ;
    USE SIGNAL ;
    PORT
      LAYER M5 ;
        RECT  249.84 0 249.864 0.084 ;
    END
  END s0b[192]
  PIN s0b[193]
    DIRECTION INPUT ;
    USE SIGNAL ;
    PORT
      LAYER M5 ;
        RECT  250.992 0 251.016 0.084 ;
    END
  END s0b[193]
  PIN s0b[194]
    DIRECTION INPUT ;
    USE SIGNAL ;
    PORT
      LAYER M5 ;
        RECT  252.192 0 252.216 0.084 ;
    END
  END s0b[194]
  PIN s0b[195]
    DIRECTION INPUT ;
    USE SIGNAL ;
    PORT
      LAYER M5 ;
        RECT  253.392 0 253.416 0.084 ;
    END
  END s0b[195]
  PIN s0b[196]
    DIRECTION INPUT ;
    USE SIGNAL ;
    PORT
      LAYER M5 ;
        RECT  254.544 0 254.568 0.084 ;
    END
  END s0b[196]
  PIN s0b[197]
    DIRECTION INPUT ;
    USE SIGNAL ;
    PORT
      LAYER M5 ;
        RECT  255.744 0 255.768 0.084 ;
    END
  END s0b[197]
  PIN s0b[198]
    DIRECTION INPUT ;
    USE SIGNAL ;
    PORT
      LAYER M5 ;
        RECT  256.944 0 256.968 0.084 ;
    END
  END s0b[198]
  PIN s0b[199]
    DIRECTION INPUT ;
    USE SIGNAL ;
    PORT
      LAYER M5 ;
        RECT  258.096 0 258.12 0.084 ;
    END
  END s0b[199]
  PIN s0b[19]
    DIRECTION INPUT ;
    USE SIGNAL ;
    PORT
      LAYER M5 ;
        RECT  44.736 0 44.76 0.084 ;
    END
  END s0b[19]
  PIN s0b[1]
    DIRECTION INPUT ;
    USE SIGNAL ;
    PORT
      LAYER M5 ;
        RECT  23.424 0 23.448 0.084 ;
    END
  END s0b[1]
  PIN s0b[200]
    DIRECTION INPUT ;
    USE SIGNAL ;
    PORT
      LAYER M5 ;
        RECT  259.2 0 259.224 0.084 ;
    END
  END s0b[200]
  PIN s0b[201]
    DIRECTION INPUT ;
    USE SIGNAL ;
    PORT
      LAYER M5 ;
        RECT  260.496 0 260.52 0.084 ;
    END
  END s0b[201]
  PIN s0b[202]
    DIRECTION INPUT ;
    USE SIGNAL ;
    PORT
      LAYER M5 ;
        RECT  261.696 0 261.72 0.084 ;
    END
  END s0b[202]
  PIN s0b[203]
    DIRECTION INPUT ;
    USE SIGNAL ;
    PORT
      LAYER M5 ;
        RECT  262.848 0 262.872 0.084 ;
    END
  END s0b[203]
  PIN s0b[204]
    DIRECTION INPUT ;
    USE SIGNAL ;
    PORT
      LAYER M5 ;
        RECT  264.048 0 264.072 0.084 ;
    END
  END s0b[204]
  PIN s0b[205]
    DIRECTION INPUT ;
    USE SIGNAL ;
    PORT
      LAYER M5 ;
        RECT  265.248 0 265.272 0.084 ;
    END
  END s0b[205]
  PIN s0b[206]
    DIRECTION INPUT ;
    USE SIGNAL ;
    PORT
      LAYER M5 ;
        RECT  266.4 0 266.424 0.084 ;
    END
  END s0b[206]
  PIN s0b[207]
    DIRECTION INPUT ;
    USE SIGNAL ;
    PORT
      LAYER M5 ;
        RECT  267.6 0 267.624 0.084 ;
    END
  END s0b[207]
  PIN s0b[208]
    DIRECTION INPUT ;
    USE SIGNAL ;
    PORT
      LAYER M5 ;
        RECT  268.8 0 268.824 0.084 ;
    END
  END s0b[208]
  PIN s0b[209]
    DIRECTION INPUT ;
    USE SIGNAL ;
    PORT
      LAYER M5 ;
        RECT  269.856 0 269.88 0.084 ;
    END
  END s0b[209]
  PIN s0b[20]
    DIRECTION INPUT ;
    USE SIGNAL ;
    PORT
      LAYER M5 ;
        RECT  45.936 0 45.96 0.084 ;
    END
  END s0b[20]
  PIN s0b[210]
    DIRECTION INPUT ;
    USE SIGNAL ;
    PORT
      LAYER M5 ;
        RECT  271.152 0 271.176 0.084 ;
    END
  END s0b[210]
  PIN s0b[211]
    DIRECTION INPUT ;
    USE SIGNAL ;
    PORT
      LAYER M5 ;
        RECT  272.352 0 272.376 0.084 ;
    END
  END s0b[211]
  PIN s0b[212]
    DIRECTION INPUT ;
    USE SIGNAL ;
    PORT
      LAYER M5 ;
        RECT  273.504 0 273.528 0.084 ;
    END
  END s0b[212]
  PIN s0b[213]
    DIRECTION INPUT ;
    USE SIGNAL ;
    PORT
      LAYER M5 ;
        RECT  274.704 0 274.728 0.084 ;
    END
  END s0b[213]
  PIN s0b[214]
    DIRECTION INPUT ;
    USE SIGNAL ;
    PORT
      LAYER M5 ;
        RECT  275.904 0 275.928 0.084 ;
    END
  END s0b[214]
  PIN s0b[215]
    DIRECTION INPUT ;
    USE SIGNAL ;
    PORT
      LAYER M5 ;
        RECT  277.104 0 277.128 0.084 ;
    END
  END s0b[215]
  PIN s0b[216]
    DIRECTION INPUT ;
    USE SIGNAL ;
    PORT
      LAYER M5 ;
        RECT  278.256 0 278.28 0.084 ;
    END
  END s0b[216]
  PIN s0b[217]
    DIRECTION INPUT ;
    USE SIGNAL ;
    PORT
      LAYER M5 ;
        RECT  279.456 0 279.48 0.084 ;
    END
  END s0b[217]
  PIN s0b[218]
    DIRECTION INPUT ;
    USE SIGNAL ;
    PORT
      LAYER M5 ;
        RECT  280.656 0 280.68 0.084 ;
    END
  END s0b[218]
  PIN s0b[219]
    DIRECTION INPUT ;
    USE SIGNAL ;
    PORT
      LAYER M5 ;
        RECT  281.808 0 281.832 0.084 ;
    END
  END s0b[219]
  PIN s0b[21]
    DIRECTION INPUT ;
    USE SIGNAL ;
    PORT
      LAYER M5 ;
        RECT  47.136 0 47.16 0.084 ;
    END
  END s0b[21]
  PIN s0b[220]
    DIRECTION INPUT ;
    USE SIGNAL ;
    PORT
      LAYER M5 ;
        RECT  283.008 0 283.032 0.084 ;
    END
  END s0b[220]
  PIN s0b[221]
    DIRECTION INPUT ;
    USE SIGNAL ;
    PORT
      LAYER M5 ;
        RECT  284.208 0 284.232 0.084 ;
    END
  END s0b[221]
  PIN s0b[222]
    DIRECTION INPUT ;
    USE SIGNAL ;
    PORT
      LAYER M5 ;
        RECT  285.36 0 285.384 0.084 ;
    END
  END s0b[222]
  PIN s0b[223]
    DIRECTION INPUT ;
    USE SIGNAL ;
    PORT
      LAYER M5 ;
        RECT  286.56 0 286.584 0.084 ;
    END
  END s0b[223]
  PIN s0b[224]
    DIRECTION INPUT ;
    USE SIGNAL ;
    PORT
      LAYER M5 ;
        RECT  287.76 0 287.784 0.084 ;
    END
  END s0b[224]
  PIN s0b[225]
    DIRECTION INPUT ;
    USE SIGNAL ;
    PORT
      LAYER M5 ;
        RECT  288.96 0 288.984 0.084 ;
    END
  END s0b[225]
  PIN s0b[226]
    DIRECTION INPUT ;
    USE SIGNAL ;
    PORT
      LAYER M5 ;
        RECT  290.112 0 290.136 0.084 ;
    END
  END s0b[226]
  PIN s0b[227]
    DIRECTION INPUT ;
    USE SIGNAL ;
    PORT
      LAYER M5 ;
        RECT  291.312 0 291.336 0.084 ;
    END
  END s0b[227]
  PIN s0b[228]
    DIRECTION INPUT ;
    USE SIGNAL ;
    PORT
      LAYER M5 ;
        RECT  292.512 0 292.536 0.084 ;
    END
  END s0b[228]
  PIN s0b[229]
    DIRECTION INPUT ;
    USE SIGNAL ;
    PORT
      LAYER M5 ;
        RECT  293.664 0 293.688 0.084 ;
    END
  END s0b[229]
  PIN s0b[22]
    DIRECTION INPUT ;
    USE SIGNAL ;
    PORT
      LAYER M5 ;
        RECT  48.288 0 48.312 0.084 ;
    END
  END s0b[22]
  PIN s0b[230]
    DIRECTION INPUT ;
    USE SIGNAL ;
    PORT
      LAYER M5 ;
        RECT  294.864 0 294.888 0.084 ;
    END
  END s0b[230]
  PIN s0b[231]
    DIRECTION INPUT ;
    USE SIGNAL ;
    PORT
      LAYER M5 ;
        RECT  296.064 0 296.088 0.084 ;
    END
  END s0b[231]
  PIN s0b[232]
    DIRECTION INPUT ;
    USE SIGNAL ;
    PORT
      LAYER M5 ;
        RECT  297.216 0 297.24 0.084 ;
    END
  END s0b[232]
  PIN s0b[233]
    DIRECTION INPUT ;
    USE SIGNAL ;
    PORT
      LAYER M5 ;
        RECT  298.416 0 298.44 0.084 ;
    END
  END s0b[233]
  PIN s0b[234]
    DIRECTION INPUT ;
    USE SIGNAL ;
    PORT
      LAYER M5 ;
        RECT  299.616 0 299.64 0.084 ;
    END
  END s0b[234]
  PIN s0b[235]
    DIRECTION INPUT ;
    USE SIGNAL ;
    PORT
      LAYER M5 ;
        RECT  300.768 0 300.792 0.084 ;
    END
  END s0b[235]
  PIN s0b[236]
    DIRECTION INPUT ;
    USE SIGNAL ;
    PORT
      LAYER M5 ;
        RECT  301.968 0 301.992 0.084 ;
    END
  END s0b[236]
  PIN s0b[237]
    DIRECTION INPUT ;
    USE SIGNAL ;
    PORT
      LAYER M5 ;
        RECT  303.168 0 303.192 0.084 ;
    END
  END s0b[237]
  PIN s0b[238]
    DIRECTION INPUT ;
    USE SIGNAL ;
    PORT
      LAYER M5 ;
        RECT  304.368 0 304.392 0.084 ;
    END
  END s0b[238]
  PIN s0b[239]
    DIRECTION INPUT ;
    USE SIGNAL ;
    PORT
      LAYER M5 ;
        RECT  305.52 0 305.544 0.084 ;
    END
  END s0b[239]
  PIN s0b[23]
    DIRECTION INPUT ;
    USE SIGNAL ;
    PORT
      LAYER M5 ;
        RECT  49.488 0 49.512 0.084 ;
    END
  END s0b[23]
  PIN s0b[240]
    DIRECTION INPUT ;
    USE SIGNAL ;
    PORT
      LAYER M5 ;
        RECT  306.72 0 306.744 0.084 ;
    END
  END s0b[240]
  PIN s0b[241]
    DIRECTION INPUT ;
    USE SIGNAL ;
    PORT
      LAYER M5 ;
        RECT  307.824 0 307.848 0.084 ;
    END
  END s0b[241]
  PIN s0b[242]
    DIRECTION INPUT ;
    USE SIGNAL ;
    PORT
      LAYER M5 ;
        RECT  309.072 0 309.096 0.084 ;
    END
  END s0b[242]
  PIN s0b[243]
    DIRECTION INPUT ;
    USE SIGNAL ;
    PORT
      LAYER M5 ;
        RECT  310.272 0 310.296 0.084 ;
    END
  END s0b[243]
  PIN s0b[244]
    DIRECTION INPUT ;
    USE SIGNAL ;
    PORT
      LAYER M5 ;
        RECT  311.472 0 311.496 0.084 ;
    END
  END s0b[244]
  PIN s0b[245]
    DIRECTION INPUT ;
    USE SIGNAL ;
    PORT
      LAYER M5 ;
        RECT  312.624 0 312.648 0.084 ;
    END
  END s0b[245]
  PIN s0b[246]
    DIRECTION INPUT ;
    USE SIGNAL ;
    PORT
      LAYER M5 ;
        RECT  313.824 0 313.848 0.084 ;
    END
  END s0b[246]
  PIN s0b[247]
    DIRECTION INPUT ;
    USE SIGNAL ;
    PORT
      LAYER M5 ;
        RECT  315.024 0 315.048 0.084 ;
    END
  END s0b[247]
  PIN s0b[248]
    DIRECTION INPUT ;
    USE SIGNAL ;
    PORT
      LAYER M5 ;
        RECT  316.176 0 316.2 0.084 ;
    END
  END s0b[248]
  PIN s0b[249]
    DIRECTION INPUT ;
    USE SIGNAL ;
    PORT
      LAYER M5 ;
        RECT  317.376 0 317.4 0.084 ;
    END
  END s0b[249]
  PIN s0b[24]
    DIRECTION INPUT ;
    USE SIGNAL ;
    PORT
      LAYER M5 ;
        RECT  50.688 0 50.712 0.084 ;
    END
  END s0b[24]
  PIN s0b[250]
    DIRECTION INPUT ;
    USE SIGNAL ;
    PORT
      LAYER M5 ;
        RECT  318.48 0 318.504 0.084 ;
    END
  END s0b[250]
  PIN s0b[251]
    DIRECTION INPUT ;
    USE SIGNAL ;
    PORT
      LAYER M5 ;
        RECT  319.776 0 319.8 0.084 ;
    END
  END s0b[251]
  PIN s0b[252]
    DIRECTION INPUT ;
    USE SIGNAL ;
    PORT
      LAYER M5 ;
        RECT  320.928 0 320.952 0.084 ;
    END
  END s0b[252]
  PIN s0b[253]
    DIRECTION INPUT ;
    USE SIGNAL ;
    PORT
      LAYER M5 ;
        RECT  322.128 0 322.152 0.084 ;
    END
  END s0b[253]
  PIN s0b[254]
    DIRECTION INPUT ;
    USE SIGNAL ;
    PORT
      LAYER M5 ;
        RECT  323.328 0 323.352 0.084 ;
    END
  END s0b[254]
  PIN s0b[255]
    DIRECTION INPUT ;
    USE SIGNAL ;
    PORT
      LAYER M5 ;
        RECT  324.48 0 324.504 0.084 ;
    END
  END s0b[255]
  PIN s0b[256]
    DIRECTION INPUT ;
    USE SIGNAL ;
    PORT
      LAYER M5 ;
        RECT  325.68 0 325.704 0.084 ;
    END
  END s0b[256]
  PIN s0b[257]
    DIRECTION INPUT ;
    USE SIGNAL ;
    PORT
      LAYER M5 ;
        RECT  326.88 0 326.904 0.084 ;
    END
  END s0b[257]
  PIN s0b[258]
    DIRECTION INPUT ;
    USE SIGNAL ;
    PORT
      LAYER M5 ;
        RECT  328.032 0 328.056 0.084 ;
    END
  END s0b[258]
  PIN s0b[259]
    DIRECTION INPUT ;
    USE SIGNAL ;
    PORT
      LAYER M5 ;
        RECT  329.232 0 329.256 0.084 ;
    END
  END s0b[259]
  PIN s0b[25]
    DIRECTION INPUT ;
    USE SIGNAL ;
    PORT
      LAYER M5 ;
        RECT  51.84 0 51.864 0.084 ;
    END
  END s0b[25]
  PIN s0b[260]
    DIRECTION INPUT ;
    USE SIGNAL ;
    PORT
      LAYER M5 ;
        RECT  330.432 0 330.456 0.084 ;
    END
  END s0b[260]
  PIN s0b[261]
    DIRECTION INPUT ;
    USE SIGNAL ;
    PORT
      LAYER M5 ;
        RECT  331.632 0 331.656 0.084 ;
    END
  END s0b[261]
  PIN s0b[262]
    DIRECTION INPUT ;
    USE SIGNAL ;
    PORT
      LAYER M5 ;
        RECT  332.784 0 332.808 0.084 ;
    END
  END s0b[262]
  PIN s0b[263]
    DIRECTION INPUT ;
    USE SIGNAL ;
    PORT
      LAYER M5 ;
        RECT  333.984 0 334.008 0.084 ;
    END
  END s0b[263]
  PIN s0b[264]
    DIRECTION INPUT ;
    USE SIGNAL ;
    PORT
      LAYER M5 ;
        RECT  335.184 0 335.208 0.084 ;
    END
  END s0b[264]
  PIN s0b[265]
    DIRECTION INPUT ;
    USE SIGNAL ;
    PORT
      LAYER M5 ;
        RECT  336.336 0 336.36 0.084 ;
    END
  END s0b[265]
  PIN s0b[266]
    DIRECTION INPUT ;
    USE SIGNAL ;
    PORT
      LAYER M5 ;
        RECT  337.536 0 337.56 0.084 ;
    END
  END s0b[266]
  PIN s0b[267]
    DIRECTION INPUT ;
    USE SIGNAL ;
    PORT
      LAYER M5 ;
        RECT  338.736 0 338.76 0.084 ;
    END
  END s0b[267]
  PIN s0b[268]
    DIRECTION INPUT ;
    USE SIGNAL ;
    PORT
      LAYER M5 ;
        RECT  339.888 0 339.912 0.084 ;
    END
  END s0b[268]
  PIN s0b[269]
    DIRECTION INPUT ;
    USE SIGNAL ;
    PORT
      LAYER M5 ;
        RECT  341.088 0 341.112 0.084 ;
    END
  END s0b[269]
  PIN s0b[26]
    DIRECTION INPUT ;
    USE SIGNAL ;
    PORT
      LAYER M5 ;
        RECT  53.04 0 53.064 0.084 ;
    END
  END s0b[26]
  PIN s0b[270]
    DIRECTION INPUT ;
    USE SIGNAL ;
    PORT
      LAYER M5 ;
        RECT  342.288 0 342.312 0.084 ;
    END
  END s0b[270]
  PIN s0b[271]
    DIRECTION INPUT ;
    USE SIGNAL ;
    PORT
      LAYER M5 ;
        RECT  343.44 0 343.464 0.084 ;
    END
  END s0b[271]
  PIN s0b[272]
    DIRECTION INPUT ;
    USE SIGNAL ;
    PORT
      LAYER M5 ;
        RECT  344.64 0 344.664 0.084 ;
    END
  END s0b[272]
  PIN s0b[273]
    DIRECTION INPUT ;
    USE SIGNAL ;
    PORT
      LAYER M5 ;
        RECT  345.744 0 345.768 0.084 ;
    END
  END s0b[273]
  PIN s0b[274]
    DIRECTION INPUT ;
    USE SIGNAL ;
    PORT
      LAYER M5 ;
        RECT  347.04 0 347.064 0.084 ;
    END
  END s0b[274]
  PIN s0b[275]
    DIRECTION INPUT ;
    USE SIGNAL ;
    PORT
      LAYER M5 ;
        RECT  348.192 0 348.216 0.084 ;
    END
  END s0b[275]
  PIN s0b[276]
    DIRECTION INPUT ;
    USE SIGNAL ;
    PORT
      LAYER M5 ;
        RECT  349.392 0 349.416 0.084 ;
    END
  END s0b[276]
  PIN s0b[277]
    DIRECTION INPUT ;
    USE SIGNAL ;
    PORT
      LAYER M5 ;
        RECT  350.592 0 350.616 0.084 ;
    END
  END s0b[277]
  PIN s0b[278]
    DIRECTION INPUT ;
    USE SIGNAL ;
    PORT
      LAYER M5 ;
        RECT  351.744 0 351.768 0.084 ;
    END
  END s0b[278]
  PIN s0b[279]
    DIRECTION INPUT ;
    USE SIGNAL ;
    PORT
      LAYER M5 ;
        RECT  352.944 0 352.968 0.084 ;
    END
  END s0b[279]
  PIN s0b[27]
    DIRECTION INPUT ;
    USE SIGNAL ;
    PORT
      LAYER M5 ;
        RECT  54.144 0 54.168 0.084 ;
    END
  END s0b[27]
  PIN s0b[280]
    DIRECTION INPUT ;
    USE SIGNAL ;
    PORT
      LAYER M5 ;
        RECT  354.144 0 354.168 0.084 ;
    END
  END s0b[280]
  PIN s0b[281]
    DIRECTION INPUT ;
    USE SIGNAL ;
    PORT
      LAYER M5 ;
        RECT  355.296 0 355.32 0.084 ;
    END
  END s0b[281]
  PIN s0b[282]
    DIRECTION INPUT ;
    USE SIGNAL ;
    PORT
      LAYER M5 ;
        RECT  356.4 0 356.424 0.084 ;
    END
  END s0b[282]
  PIN s0b[283]
    DIRECTION INPUT ;
    USE SIGNAL ;
    PORT
      LAYER M5 ;
        RECT  357.696 0 357.72 0.084 ;
    END
  END s0b[283]
  PIN s0b[284]
    DIRECTION INPUT ;
    USE SIGNAL ;
    PORT
      LAYER M5 ;
        RECT  358.896 0 358.92 0.084 ;
    END
  END s0b[284]
  PIN s0b[285]
    DIRECTION INPUT ;
    USE SIGNAL ;
    PORT
      LAYER M5 ;
        RECT  360.048 0 360.072 0.084 ;
    END
  END s0b[285]
  PIN s0b[286]
    DIRECTION INPUT ;
    USE SIGNAL ;
    PORT
      LAYER M5 ;
        RECT  361.248 0 361.272 0.084 ;
    END
  END s0b[286]
  PIN s0b[287]
    DIRECTION INPUT ;
    USE SIGNAL ;
    PORT
      LAYER M5 ;
        RECT  362.448 0 362.472 0.084 ;
    END
  END s0b[287]
  PIN s0b[288]
    DIRECTION INPUT ;
    USE SIGNAL ;
    PORT
      LAYER M5 ;
        RECT  363.6 0 363.624 0.084 ;
    END
  END s0b[288]
  PIN s0b[289]
    DIRECTION INPUT ;
    USE SIGNAL ;
    PORT
      LAYER M5 ;
        RECT  364.8 0 364.824 0.084 ;
    END
  END s0b[289]
  PIN s0b[28]
    DIRECTION INPUT ;
    USE SIGNAL ;
    PORT
      LAYER M5 ;
        RECT  55.44 0 55.464 0.084 ;
    END
  END s0b[28]
  PIN s0b[290]
    DIRECTION INPUT ;
    USE SIGNAL ;
    PORT
      LAYER M5 ;
        RECT  366 0 366.024 0.084 ;
    END
  END s0b[290]
  PIN s0b[291]
    DIRECTION INPUT ;
    USE SIGNAL ;
    PORT
      LAYER M5 ;
        RECT  367.056 0 367.08 0.084 ;
    END
  END s0b[291]
  PIN s0b[292]
    DIRECTION INPUT ;
    USE SIGNAL ;
    PORT
      LAYER M5 ;
        RECT  368.352 0 368.376 0.084 ;
    END
  END s0b[292]
  PIN s0b[293]
    DIRECTION INPUT ;
    USE SIGNAL ;
    PORT
      LAYER M5 ;
        RECT  369.552 0 369.576 0.084 ;
    END
  END s0b[293]
  PIN s0b[294]
    DIRECTION INPUT ;
    USE SIGNAL ;
    PORT
      LAYER M5 ;
        RECT  370.704 0 370.728 0.084 ;
    END
  END s0b[294]
  PIN s0b[295]
    DIRECTION INPUT ;
    USE SIGNAL ;
    PORT
      LAYER M5 ;
        RECT  371.904 0 371.928 0.084 ;
    END
  END s0b[295]
  PIN s0b[296]
    DIRECTION INPUT ;
    USE SIGNAL ;
    PORT
      LAYER M5 ;
        RECT  373.104 0 373.128 0.084 ;
    END
  END s0b[296]
  PIN s0b[297]
    DIRECTION INPUT ;
    USE SIGNAL ;
    PORT
      LAYER M5 ;
        RECT  374.304 0 374.328 0.084 ;
    END
  END s0b[297]
  PIN s0b[298]
    DIRECTION INPUT ;
    USE SIGNAL ;
    PORT
      LAYER M5 ;
        RECT  375.456 0 375.48 0.084 ;
    END
  END s0b[298]
  PIN s0b[299]
    DIRECTION INPUT ;
    USE SIGNAL ;
    PORT
      LAYER M5 ;
        RECT  376.656 0 376.68 0.084 ;
    END
  END s0b[299]
  PIN s0b[29]
    DIRECTION INPUT ;
    USE SIGNAL ;
    PORT
      LAYER M5 ;
        RECT  56.592 0 56.616 0.084 ;
    END
  END s0b[29]
  PIN s0b[2]
    DIRECTION INPUT ;
    USE SIGNAL ;
    PORT
      LAYER M5 ;
        RECT  24.576 0 24.6 0.084 ;
    END
  END s0b[2]
  PIN s0b[300]
    DIRECTION INPUT ;
    USE SIGNAL ;
    PORT
      LAYER M5 ;
        RECT  377.856 0 377.88 0.084 ;
    END
  END s0b[300]
  PIN s0b[301]
    DIRECTION INPUT ;
    USE SIGNAL ;
    PORT
      LAYER M5 ;
        RECT  379.008 0 379.032 0.084 ;
    END
  END s0b[301]
  PIN s0b[302]
    DIRECTION INPUT ;
    USE SIGNAL ;
    PORT
      LAYER M5 ;
        RECT  380.208 0 380.232 0.084 ;
    END
  END s0b[302]
  PIN s0b[303]
    DIRECTION INPUT ;
    USE SIGNAL ;
    PORT
      LAYER M5 ;
        RECT  381.408 0 381.432 0.084 ;
    END
  END s0b[303]
  PIN s0b[304]
    DIRECTION INPUT ;
    USE SIGNAL ;
    PORT
      LAYER M5 ;
        RECT  382.56 0 382.584 0.084 ;
    END
  END s0b[304]
  PIN s0b[305]
    DIRECTION INPUT ;
    USE SIGNAL ;
    PORT
      LAYER M5 ;
        RECT  383.76 0 383.784 0.084 ;
    END
  END s0b[305]
  PIN s0b[306]
    DIRECTION INPUT ;
    USE SIGNAL ;
    PORT
      LAYER M5 ;
        RECT  384.96 0 384.984 0.084 ;
    END
  END s0b[306]
  PIN s0b[307]
    DIRECTION INPUT ;
    USE SIGNAL ;
    PORT
      LAYER M5 ;
        RECT  386.16 0 386.184 0.084 ;
    END
  END s0b[307]
  PIN s0b[308]
    DIRECTION INPUT ;
    USE SIGNAL ;
    PORT
      LAYER M5 ;
        RECT  387.312 0 387.336 0.084 ;
    END
  END s0b[308]
  PIN s0b[309]
    DIRECTION INPUT ;
    USE SIGNAL ;
    PORT
      LAYER M5 ;
        RECT  388.512 0 388.536 0.084 ;
    END
  END s0b[309]
  PIN s0b[30]
    DIRECTION INPUT ;
    USE SIGNAL ;
    PORT
      LAYER M5 ;
        RECT  57.792 0 57.816 0.084 ;
    END
  END s0b[30]
  PIN s0b[310]
    DIRECTION INPUT ;
    USE SIGNAL ;
    PORT
      LAYER M5 ;
        RECT  389.712 0 389.736 0.084 ;
    END
  END s0b[310]
  PIN s0b[311]
    DIRECTION INPUT ;
    USE SIGNAL ;
    PORT
      LAYER M5 ;
        RECT  390.864 0 390.888 0.084 ;
    END
  END s0b[311]
  PIN s0b[312]
    DIRECTION INPUT ;
    USE SIGNAL ;
    PORT
      LAYER M5 ;
        RECT  392.064 0 392.088 0.084 ;
    END
  END s0b[312]
  PIN s0b[313]
    DIRECTION INPUT ;
    USE SIGNAL ;
    PORT
      LAYER M5 ;
        RECT  393.264 0 393.288 0.084 ;
    END
  END s0b[313]
  PIN s0b[314]
    DIRECTION INPUT ;
    USE SIGNAL ;
    PORT
      LAYER M5 ;
        RECT  394.416 0 394.44 0.084 ;
    END
  END s0b[314]
  PIN s0b[315]
    DIRECTION INPUT ;
    USE SIGNAL ;
    PORT
      LAYER M5 ;
        RECT  395.616 0 395.64 0.084 ;
    END
  END s0b[315]
  PIN s0b[316]
    DIRECTION INPUT ;
    USE SIGNAL ;
    PORT
      LAYER M5 ;
        RECT  396.816 0 396.84 0.084 ;
    END
  END s0b[316]
  PIN s0b[317]
    DIRECTION INPUT ;
    USE SIGNAL ;
    PORT
      LAYER M5 ;
        RECT  397.968 0 397.992 0.084 ;
    END
  END s0b[317]
  PIN s0b[318]
    DIRECTION INPUT ;
    USE SIGNAL ;
    PORT
      LAYER M5 ;
        RECT  399.168 0 399.192 0.084 ;
    END
  END s0b[318]
  PIN s0b[319]
    DIRECTION INPUT ;
    USE SIGNAL ;
    PORT
      LAYER M5 ;
        RECT  400.368 0 400.392 0.084 ;
    END
  END s0b[319]
  PIN s0b[31]
    DIRECTION INPUT ;
    USE SIGNAL ;
    PORT
      LAYER M5 ;
        RECT  58.992 0 59.016 0.084 ;
    END
  END s0b[31]
  PIN s0b[320]
    DIRECTION INPUT ;
    USE SIGNAL ;
    PORT
      LAYER M5 ;
        RECT  401.568 0 401.592 0.084 ;
    END
  END s0b[320]
  PIN s0b[321]
    DIRECTION INPUT ;
    USE SIGNAL ;
    PORT
      LAYER M5 ;
        RECT  402.72 0 402.744 0.084 ;
    END
  END s0b[321]
  PIN s0b[322]
    DIRECTION INPUT ;
    USE SIGNAL ;
    PORT
      LAYER M5 ;
        RECT  403.92 0 403.944 0.084 ;
    END
  END s0b[322]
  PIN s0b[323]
    DIRECTION INPUT ;
    USE SIGNAL ;
    PORT
      LAYER M5 ;
        RECT  405.024 0 405.048 0.084 ;
    END
  END s0b[323]
  PIN s0b[324]
    DIRECTION INPUT ;
    USE SIGNAL ;
    PORT
      LAYER M5 ;
        RECT  406.272 0 406.296 0.084 ;
    END
  END s0b[324]
  PIN s0b[325]
    DIRECTION INPUT ;
    USE SIGNAL ;
    PORT
      LAYER M5 ;
        RECT  407.472 0 407.496 0.084 ;
    END
  END s0b[325]
  PIN s0b[326]
    DIRECTION INPUT ;
    USE SIGNAL ;
    PORT
      LAYER M5 ;
        RECT  408.672 0 408.696 0.084 ;
    END
  END s0b[326]
  PIN s0b[327]
    DIRECTION INPUT ;
    USE SIGNAL ;
    PORT
      LAYER M5 ;
        RECT  409.824 0 409.848 0.084 ;
    END
  END s0b[327]
  PIN s0b[32]
    DIRECTION INPUT ;
    USE SIGNAL ;
    PORT
      LAYER M5 ;
        RECT  60.144 0 60.168 0.084 ;
    END
  END s0b[32]
  PIN s0b[33]
    DIRECTION INPUT ;
    USE SIGNAL ;
    PORT
      LAYER M5 ;
        RECT  61.344 0 61.368 0.084 ;
    END
  END s0b[33]
  PIN s0b[34]
    DIRECTION INPUT ;
    USE SIGNAL ;
    PORT
      LAYER M5 ;
        RECT  62.544 0 62.568 0.084 ;
    END
  END s0b[34]
  PIN s0b[35]
    DIRECTION INPUT ;
    USE SIGNAL ;
    PORT
      LAYER M5 ;
        RECT  63.696 0 63.72 0.084 ;
    END
  END s0b[35]
  PIN s0b[36]
    DIRECTION INPUT ;
    USE SIGNAL ;
    PORT
      LAYER M5 ;
        RECT  64.8 0 64.824 0.084 ;
    END
  END s0b[36]
  PIN s0b[37]
    DIRECTION INPUT ;
    USE SIGNAL ;
    PORT
      LAYER M5 ;
        RECT  66.096 0 66.12 0.084 ;
    END
  END s0b[37]
  PIN s0b[38]
    DIRECTION INPUT ;
    USE SIGNAL ;
    PORT
      LAYER M5 ;
        RECT  67.296 0 67.32 0.084 ;
    END
  END s0b[38]
  PIN s0b[39]
    DIRECTION INPUT ;
    USE SIGNAL ;
    PORT
      LAYER M5 ;
        RECT  68.448 0 68.472 0.084 ;
    END
  END s0b[39]
  PIN s0b[3]
    DIRECTION INPUT ;
    USE SIGNAL ;
    PORT
      LAYER M5 ;
        RECT  25.776 0 25.8 0.084 ;
    END
  END s0b[3]
  PIN s0b[40]
    DIRECTION INPUT ;
    USE SIGNAL ;
    PORT
      LAYER M5 ;
        RECT  69.648 0 69.672 0.084 ;
    END
  END s0b[40]
  PIN s0b[41]
    DIRECTION INPUT ;
    USE SIGNAL ;
    PORT
      LAYER M5 ;
        RECT  70.848 0 70.872 0.084 ;
    END
  END s0b[41]
  PIN s0b[42]
    DIRECTION INPUT ;
    USE SIGNAL ;
    PORT
      LAYER M5 ;
        RECT  72 0 72.024 0.084 ;
    END
  END s0b[42]
  PIN s0b[43]
    DIRECTION INPUT ;
    USE SIGNAL ;
    PORT
      LAYER M5 ;
        RECT  73.2 0 73.224 0.084 ;
    END
  END s0b[43]
  PIN s0b[44]
    DIRECTION INPUT ;
    USE SIGNAL ;
    PORT
      LAYER M5 ;
        RECT  74.4 0 74.424 0.084 ;
    END
  END s0b[44]
  PIN s0b[45]
    DIRECTION INPUT ;
    USE SIGNAL ;
    PORT
      LAYER M5 ;
        RECT  75.456 0 75.48 0.084 ;
    END
  END s0b[45]
  PIN s0b[46]
    DIRECTION INPUT ;
    USE SIGNAL ;
    PORT
      LAYER M5 ;
        RECT  76.752 0 76.776 0.084 ;
    END
  END s0b[46]
  PIN s0b[47]
    DIRECTION INPUT ;
    USE SIGNAL ;
    PORT
      LAYER M5 ;
        RECT  77.952 0 77.976 0.084 ;
    END
  END s0b[47]
  PIN s0b[48]
    DIRECTION INPUT ;
    USE SIGNAL ;
    PORT
      LAYER M5 ;
        RECT  79.104 0 79.128 0.084 ;
    END
  END s0b[48]
  PIN s0b[49]
    DIRECTION INPUT ;
    USE SIGNAL ;
    PORT
      LAYER M5 ;
        RECT  80.304 0 80.328 0.084 ;
    END
  END s0b[49]
  PIN s0b[4]
    DIRECTION INPUT ;
    USE SIGNAL ;
    PORT
      LAYER M5 ;
        RECT  26.88 0 26.904 0.084 ;
    END
  END s0b[4]
  PIN s0b[50]
    DIRECTION INPUT ;
    USE SIGNAL ;
    PORT
      LAYER M5 ;
        RECT  81.504 0 81.528 0.084 ;
    END
  END s0b[50]
  PIN s0b[51]
    DIRECTION INPUT ;
    USE SIGNAL ;
    PORT
      LAYER M5 ;
        RECT  82.704 0 82.728 0.084 ;
    END
  END s0b[51]
  PIN s0b[52]
    DIRECTION INPUT ;
    USE SIGNAL ;
    PORT
      LAYER M5 ;
        RECT  83.856 0 83.88 0.084 ;
    END
  END s0b[52]
  PIN s0b[53]
    DIRECTION INPUT ;
    USE SIGNAL ;
    PORT
      LAYER M5 ;
        RECT  85.056 0 85.08 0.084 ;
    END
  END s0b[53]
  PIN s0b[54]
    DIRECTION INPUT ;
    USE SIGNAL ;
    PORT
      LAYER M5 ;
        RECT  86.256 0 86.28 0.084 ;
    END
  END s0b[54]
  PIN s0b[55]
    DIRECTION INPUT ;
    USE SIGNAL ;
    PORT
      LAYER M5 ;
        RECT  87.408 0 87.432 0.084 ;
    END
  END s0b[55]
  PIN s0b[56]
    DIRECTION INPUT ;
    USE SIGNAL ;
    PORT
      LAYER M5 ;
        RECT  88.608 0 88.632 0.084 ;
    END
  END s0b[56]
  PIN s0b[57]
    DIRECTION INPUT ;
    USE SIGNAL ;
    PORT
      LAYER M5 ;
        RECT  89.808 0 89.832 0.084 ;
    END
  END s0b[57]
  PIN s0b[58]
    DIRECTION INPUT ;
    USE SIGNAL ;
    PORT
      LAYER M5 ;
        RECT  90.96 0 90.984 0.084 ;
    END
  END s0b[58]
  PIN s0b[59]
    DIRECTION INPUT ;
    USE SIGNAL ;
    PORT
      LAYER M5 ;
        RECT  92.16 0 92.184 0.084 ;
    END
  END s0b[59]
  PIN s0b[5]
    DIRECTION INPUT ;
    USE SIGNAL ;
    PORT
      LAYER M5 ;
        RECT  28.176 0 28.2 0.084 ;
    END
  END s0b[5]
  PIN s0b[60]
    DIRECTION INPUT ;
    USE SIGNAL ;
    PORT
      LAYER M5 ;
        RECT  93.36 0 93.384 0.084 ;
    END
  END s0b[60]
  PIN s0b[61]
    DIRECTION INPUT ;
    USE SIGNAL ;
    PORT
      LAYER M5 ;
        RECT  94.56 0 94.584 0.084 ;
    END
  END s0b[61]
  PIN s0b[62]
    DIRECTION INPUT ;
    USE SIGNAL ;
    PORT
      LAYER M5 ;
        RECT  95.712 0 95.736 0.084 ;
    END
  END s0b[62]
  PIN s0b[63]
    DIRECTION INPUT ;
    USE SIGNAL ;
    PORT
      LAYER M5 ;
        RECT  96.912 0 96.936 0.084 ;
    END
  END s0b[63]
  PIN s0b[64]
    DIRECTION INPUT ;
    USE SIGNAL ;
    PORT
      LAYER M5 ;
        RECT  98.112 0 98.136 0.084 ;
    END
  END s0b[64]
  PIN s0b[65]
    DIRECTION INPUT ;
    USE SIGNAL ;
    PORT
      LAYER M5 ;
        RECT  99.264 0 99.288 0.084 ;
    END
  END s0b[65]
  PIN s0b[66]
    DIRECTION INPUT ;
    USE SIGNAL ;
    PORT
      LAYER M5 ;
        RECT  100.464 0 100.488 0.084 ;
    END
  END s0b[66]
  PIN s0b[67]
    DIRECTION INPUT ;
    USE SIGNAL ;
    PORT
      LAYER M5 ;
        RECT  101.664 0 101.688 0.084 ;
    END
  END s0b[67]
  PIN s0b[68]
    DIRECTION INPUT ;
    USE SIGNAL ;
    PORT
      LAYER M5 ;
        RECT  102.816 0 102.84 0.084 ;
    END
  END s0b[68]
  PIN s0b[69]
    DIRECTION INPUT ;
    USE SIGNAL ;
    PORT
      LAYER M5 ;
        RECT  104.016 0 104.04 0.084 ;
    END
  END s0b[69]
  PIN s0b[6]
    DIRECTION INPUT ;
    USE SIGNAL ;
    PORT
      LAYER M5 ;
        RECT  29.328 0 29.352 0.084 ;
    END
  END s0b[6]
  PIN s0b[70]
    DIRECTION INPUT ;
    USE SIGNAL ;
    PORT
      LAYER M5 ;
        RECT  105.216 0 105.24 0.084 ;
    END
  END s0b[70]
  PIN s0b[71]
    DIRECTION INPUT ;
    USE SIGNAL ;
    PORT
      LAYER M5 ;
        RECT  106.368 0 106.392 0.084 ;
    END
  END s0b[71]
  PIN s0b[72]
    DIRECTION INPUT ;
    USE SIGNAL ;
    PORT
      LAYER M5 ;
        RECT  107.568 0 107.592 0.084 ;
    END
  END s0b[72]
  PIN s0b[73]
    DIRECTION INPUT ;
    USE SIGNAL ;
    PORT
      LAYER M5 ;
        RECT  108.768 0 108.792 0.084 ;
    END
  END s0b[73]
  PIN s0b[74]
    DIRECTION INPUT ;
    USE SIGNAL ;
    PORT
      LAYER M5 ;
        RECT  109.968 0 109.992 0.084 ;
    END
  END s0b[74]
  PIN s0b[75]
    DIRECTION INPUT ;
    USE SIGNAL ;
    PORT
      LAYER M5 ;
        RECT  111.12 0 111.144 0.084 ;
    END
  END s0b[75]
  PIN s0b[76]
    DIRECTION INPUT ;
    USE SIGNAL ;
    PORT
      LAYER M5 ;
        RECT  112.32 0 112.344 0.084 ;
    END
  END s0b[76]
  PIN s0b[77]
    DIRECTION INPUT ;
    USE SIGNAL ;
    PORT
      LAYER M5 ;
        RECT  113.424 0 113.448 0.084 ;
    END
  END s0b[77]
  PIN s0b[78]
    DIRECTION INPUT ;
    USE SIGNAL ;
    PORT
      LAYER M5 ;
        RECT  114.672 0 114.696 0.084 ;
    END
  END s0b[78]
  PIN s0b[79]
    DIRECTION INPUT ;
    USE SIGNAL ;
    PORT
      LAYER M5 ;
        RECT  115.872 0 115.896 0.084 ;
    END
  END s0b[79]
  PIN s0b[7]
    DIRECTION INPUT ;
    USE SIGNAL ;
    PORT
      LAYER M5 ;
        RECT  30.528 0 30.552 0.084 ;
    END
  END s0b[7]
  PIN s0b[80]
    DIRECTION INPUT ;
    USE SIGNAL ;
    PORT
      LAYER M5 ;
        RECT  117.072 0 117.096 0.084 ;
    END
  END s0b[80]
  PIN s0b[81]
    DIRECTION INPUT ;
    USE SIGNAL ;
    PORT
      LAYER M5 ;
        RECT  118.224 0 118.248 0.084 ;
    END
  END s0b[81]
  PIN s0b[82]
    DIRECTION INPUT ;
    USE SIGNAL ;
    PORT
      LAYER M5 ;
        RECT  119.424 0 119.448 0.084 ;
    END
  END s0b[82]
  PIN s0b[83]
    DIRECTION INPUT ;
    USE SIGNAL ;
    PORT
      LAYER M5 ;
        RECT  120.624 0 120.648 0.084 ;
    END
  END s0b[83]
  PIN s0b[84]
    DIRECTION INPUT ;
    USE SIGNAL ;
    PORT
      LAYER M5 ;
        RECT  121.776 0 121.8 0.084 ;
    END
  END s0b[84]
  PIN s0b[85]
    DIRECTION INPUT ;
    USE SIGNAL ;
    PORT
      LAYER M5 ;
        RECT  122.976 0 123 0.084 ;
    END
  END s0b[85]
  PIN s0b[86]
    DIRECTION INPUT ;
    USE SIGNAL ;
    PORT
      LAYER M5 ;
        RECT  124.08 0 124.104 0.084 ;
    END
  END s0b[86]
  PIN s0b[87]
    DIRECTION INPUT ;
    USE SIGNAL ;
    PORT
      LAYER M5 ;
        RECT  125.376 0 125.4 0.084 ;
    END
  END s0b[87]
  PIN s0b[88]
    DIRECTION INPUT ;
    USE SIGNAL ;
    PORT
      LAYER M5 ;
        RECT  126.528 0 126.552 0.084 ;
    END
  END s0b[88]
  PIN s0b[89]
    DIRECTION INPUT ;
    USE SIGNAL ;
    PORT
      LAYER M5 ;
        RECT  127.728 0 127.752 0.084 ;
    END
  END s0b[89]
  PIN s0b[8]
    DIRECTION INPUT ;
    USE SIGNAL ;
    PORT
      LAYER M5 ;
        RECT  31.728 0 31.752 0.084 ;
    END
  END s0b[8]
  PIN s0b[90]
    DIRECTION INPUT ;
    USE SIGNAL ;
    PORT
      LAYER M5 ;
        RECT  128.928 0 128.952 0.084 ;
    END
  END s0b[90]
  PIN s0b[91]
    DIRECTION INPUT ;
    USE SIGNAL ;
    PORT
      LAYER M5 ;
        RECT  130.08 0 130.104 0.084 ;
    END
  END s0b[91]
  PIN s0b[92]
    DIRECTION INPUT ;
    USE SIGNAL ;
    PORT
      LAYER M5 ;
        RECT  131.28 0 131.304 0.084 ;
    END
  END s0b[92]
  PIN s0b[93]
    DIRECTION INPUT ;
    USE SIGNAL ;
    PORT
      LAYER M5 ;
        RECT  132.48 0 132.504 0.084 ;
    END
  END s0b[93]
  PIN s0b[94]
    DIRECTION INPUT ;
    USE SIGNAL ;
    PORT
      LAYER M5 ;
        RECT  133.632 0 133.656 0.084 ;
    END
  END s0b[94]
  PIN s0b[95]
    DIRECTION INPUT ;
    USE SIGNAL ;
    PORT
      LAYER M5 ;
        RECT  134.832 0 134.856 0.084 ;
    END
  END s0b[95]
  PIN s0b[96]
    DIRECTION INPUT ;
    USE SIGNAL ;
    PORT
      LAYER M5 ;
        RECT  136.032 0 136.056 0.084 ;
    END
  END s0b[96]
  PIN s0b[97]
    DIRECTION INPUT ;
    USE SIGNAL ;
    PORT
      LAYER M5 ;
        RECT  137.232 0 137.256 0.084 ;
    END
  END s0b[97]
  PIN s0b[98]
    DIRECTION INPUT ;
    USE SIGNAL ;
    PORT
      LAYER M5 ;
        RECT  138.384 0 138.408 0.084 ;
    END
  END s0b[98]
  PIN s0b[99]
    DIRECTION INPUT ;
    USE SIGNAL ;
    PORT
      LAYER M5 ;
        RECT  139.584 0 139.608 0.084 ;
    END
  END s0b[99]
  PIN s0b[9]
    DIRECTION INPUT ;
    USE SIGNAL ;
    PORT
      LAYER M5 ;
        RECT  32.88 0 32.904 0.084 ;
    END
  END s0b[9]
  PIN s1a[0]
    DIRECTION INPUT ;
    USE SIGNAL ;
    PORT
      LAYER M5 ;
        RECT  22.176 215.916 22.2 216 ;
    END
  END s1a[0]
  PIN s1a[100]
    DIRECTION INPUT ;
    USE SIGNAL ;
    PORT
      LAYER M5 ;
        RECT  140.736 215.916 140.76 216 ;
    END
  END s1a[100]
  PIN s1a[101]
    DIRECTION INPUT ;
    USE SIGNAL ;
    PORT
      LAYER M5 ;
        RECT  141.888 215.916 141.912 216 ;
    END
  END s1a[101]
  PIN s1a[102]
    DIRECTION INPUT ;
    USE SIGNAL ;
    PORT
      LAYER M5 ;
        RECT  143.088 215.916 143.112 216 ;
    END
  END s1a[102]
  PIN s1a[103]
    DIRECTION INPUT ;
    USE SIGNAL ;
    PORT
      LAYER M5 ;
        RECT  144.288 215.916 144.312 216 ;
    END
  END s1a[103]
  PIN s1a[104]
    DIRECTION INPUT ;
    USE SIGNAL ;
    PORT
      LAYER M5 ;
        RECT  145.44 215.916 145.464 216 ;
    END
  END s1a[104]
  PIN s1a[105]
    DIRECTION INPUT ;
    USE SIGNAL ;
    PORT
      LAYER M5 ;
        RECT  146.64 215.916 146.664 216 ;
    END
  END s1a[105]
  PIN s1a[106]
    DIRECTION INPUT ;
    USE SIGNAL ;
    PORT
      LAYER M5 ;
        RECT  147.84 215.916 147.864 216 ;
    END
  END s1a[106]
  PIN s1a[107]
    DIRECTION INPUT ;
    USE SIGNAL ;
    PORT
      LAYER M5 ;
        RECT  148.992 215.916 149.016 216 ;
    END
  END s1a[107]
  PIN s1a[108]
    DIRECTION INPUT ;
    USE SIGNAL ;
    PORT
      LAYER M5 ;
        RECT  150.192 215.916 150.216 216 ;
    END
  END s1a[108]
  PIN s1a[109]
    DIRECTION INPUT ;
    USE SIGNAL ;
    PORT
      LAYER M5 ;
        RECT  151.392 215.916 151.416 216 ;
    END
  END s1a[109]
  PIN s1a[10]
    DIRECTION INPUT ;
    USE SIGNAL ;
    PORT
      LAYER M5 ;
        RECT  34.032 215.916 34.056 216 ;
    END
  END s1a[10]
  PIN s1a[110]
    DIRECTION INPUT ;
    USE SIGNAL ;
    PORT
      LAYER M5 ;
        RECT  152.592 215.916 152.616 216 ;
    END
  END s1a[110]
  PIN s1a[111]
    DIRECTION INPUT ;
    USE SIGNAL ;
    PORT
      LAYER M5 ;
        RECT  153.744 215.916 153.768 216 ;
    END
  END s1a[111]
  PIN s1a[112]
    DIRECTION INPUT ;
    USE SIGNAL ;
    PORT
      LAYER M5 ;
        RECT  154.944 215.916 154.968 216 ;
    END
  END s1a[112]
  PIN s1a[113]
    DIRECTION INPUT ;
    USE SIGNAL ;
    PORT
      LAYER M5 ;
        RECT  156.144 215.916 156.168 216 ;
    END
  END s1a[113]
  PIN s1a[114]
    DIRECTION INPUT ;
    USE SIGNAL ;
    PORT
      LAYER M5 ;
        RECT  157.296 215.916 157.32 216 ;
    END
  END s1a[114]
  PIN s1a[115]
    DIRECTION INPUT ;
    USE SIGNAL ;
    PORT
      LAYER M5 ;
        RECT  158.496 215.916 158.52 216 ;
    END
  END s1a[115]
  PIN s1a[116]
    DIRECTION INPUT ;
    USE SIGNAL ;
    PORT
      LAYER M5 ;
        RECT  159.696 215.916 159.72 216 ;
    END
  END s1a[116]
  PIN s1a[117]
    DIRECTION INPUT ;
    USE SIGNAL ;
    PORT
      LAYER M5 ;
        RECT  160.848 215.916 160.872 216 ;
    END
  END s1a[117]
  PIN s1a[118]
    DIRECTION INPUT ;
    USE SIGNAL ;
    PORT
      LAYER M5 ;
        RECT  162.048 215.916 162.072 216 ;
    END
  END s1a[118]
  PIN s1a[119]
    DIRECTION INPUT ;
    USE SIGNAL ;
    PORT
      LAYER M5 ;
        RECT  163.248 215.916 163.272 216 ;
    END
  END s1a[119]
  PIN s1a[11]
    DIRECTION INPUT ;
    USE SIGNAL ;
    PORT
      LAYER M5 ;
        RECT  35.232 215.916 35.256 216 ;
    END
  END s1a[11]
  PIN s1a[120]
    DIRECTION INPUT ;
    USE SIGNAL ;
    PORT
      LAYER M5 ;
        RECT  164.448 215.916 164.472 216 ;
    END
  END s1a[120]
  PIN s1a[121]
    DIRECTION INPUT ;
    USE SIGNAL ;
    PORT
      LAYER M5 ;
        RECT  165.6 215.916 165.624 216 ;
    END
  END s1a[121]
  PIN s1a[122]
    DIRECTION INPUT ;
    USE SIGNAL ;
    PORT
      LAYER M5 ;
        RECT  166.8 215.916 166.824 216 ;
    END
  END s1a[122]
  PIN s1a[123]
    DIRECTION INPUT ;
    USE SIGNAL ;
    PORT
      LAYER M5 ;
        RECT  168 215.916 168.024 216 ;
    END
  END s1a[123]
  PIN s1a[124]
    DIRECTION INPUT ;
    USE SIGNAL ;
    PORT
      LAYER M5 ;
        RECT  169.152 215.916 169.176 216 ;
    END
  END s1a[124]
  PIN s1a[125]
    DIRECTION INPUT ;
    USE SIGNAL ;
    PORT
      LAYER M5 ;
        RECT  170.352 215.916 170.376 216 ;
    END
  END s1a[125]
  PIN s1a[126]
    DIRECTION INPUT ;
    USE SIGNAL ;
    PORT
      LAYER M5 ;
        RECT  171.552 215.916 171.576 216 ;
    END
  END s1a[126]
  PIN s1a[127]
    DIRECTION INPUT ;
    USE SIGNAL ;
    PORT
      LAYER M5 ;
        RECT  172.752 215.916 172.776 216 ;
    END
  END s1a[127]
  PIN s1a[128]
    DIRECTION INPUT ;
    USE SIGNAL ;
    PORT
      LAYER M5 ;
        RECT  173.904 215.916 173.928 216 ;
    END
  END s1a[128]
  PIN s1a[129]
    DIRECTION INPUT ;
    USE SIGNAL ;
    PORT
      LAYER M5 ;
        RECT  175.104 215.916 175.128 216 ;
    END
  END s1a[129]
  PIN s1a[12]
    DIRECTION INPUT ;
    USE SIGNAL ;
    PORT
      LAYER M5 ;
        RECT  36.384 215.916 36.408 216 ;
    END
  END s1a[12]
  PIN s1a[130]
    DIRECTION INPUT ;
    USE SIGNAL ;
    PORT
      LAYER M5 ;
        RECT  176.256 215.916 176.28 216 ;
    END
  END s1a[130]
  PIN s1a[131]
    DIRECTION INPUT ;
    USE SIGNAL ;
    PORT
      LAYER M5 ;
        RECT  177.456 215.916 177.48 216 ;
    END
  END s1a[131]
  PIN s1a[132]
    DIRECTION INPUT ;
    USE SIGNAL ;
    PORT
      LAYER M5 ;
        RECT  178.656 215.916 178.68 216 ;
    END
  END s1a[132]
  PIN s1a[133]
    DIRECTION INPUT ;
    USE SIGNAL ;
    PORT
      LAYER M5 ;
        RECT  179.856 215.916 179.88 216 ;
    END
  END s1a[133]
  PIN s1a[134]
    DIRECTION INPUT ;
    USE SIGNAL ;
    PORT
      LAYER M5 ;
        RECT  181.008 215.916 181.032 216 ;
    END
  END s1a[134]
  PIN s1a[135]
    DIRECTION INPUT ;
    USE SIGNAL ;
    PORT
      LAYER M5 ;
        RECT  182.208 215.916 182.232 216 ;
    END
  END s1a[135]
  PIN s1a[136]
    DIRECTION INPUT ;
    USE SIGNAL ;
    PORT
      LAYER M5 ;
        RECT  183.408 215.916 183.432 216 ;
    END
  END s1a[136]
  PIN s1a[137]
    DIRECTION INPUT ;
    USE SIGNAL ;
    PORT
      LAYER M5 ;
        RECT  184.56 215.916 184.584 216 ;
    END
  END s1a[137]
  PIN s1a[138]
    DIRECTION INPUT ;
    USE SIGNAL ;
    PORT
      LAYER M5 ;
        RECT  185.76 215.916 185.784 216 ;
    END
  END s1a[138]
  PIN s1a[139]
    DIRECTION INPUT ;
    USE SIGNAL ;
    PORT
      LAYER M5 ;
        RECT  186.96 215.916 186.984 216 ;
    END
  END s1a[139]
  PIN s1a[13]
    DIRECTION INPUT ;
    USE SIGNAL ;
    PORT
      LAYER M5 ;
        RECT  37.584 215.916 37.608 216 ;
    END
  END s1a[13]
  PIN s1a[140]
    DIRECTION INPUT ;
    USE SIGNAL ;
    PORT
      LAYER M5 ;
        RECT  188.112 215.916 188.136 216 ;
    END
  END s1a[140]
  PIN s1a[141]
    DIRECTION INPUT ;
    USE SIGNAL ;
    PORT
      LAYER M5 ;
        RECT  189.312 215.916 189.336 216 ;
    END
  END s1a[141]
  PIN s1a[142]
    DIRECTION INPUT ;
    USE SIGNAL ;
    PORT
      LAYER M5 ;
        RECT  190.512 215.916 190.536 216 ;
    END
  END s1a[142]
  PIN s1a[143]
    DIRECTION INPUT ;
    USE SIGNAL ;
    PORT
      LAYER M5 ;
        RECT  191.712 215.916 191.736 216 ;
    END
  END s1a[143]
  PIN s1a[144]
    DIRECTION INPUT ;
    USE SIGNAL ;
    PORT
      LAYER M5 ;
        RECT  192.864 215.916 192.888 216 ;
    END
  END s1a[144]
  PIN s1a[145]
    DIRECTION INPUT ;
    USE SIGNAL ;
    PORT
      LAYER M5 ;
        RECT  194.064 215.916 194.088 216 ;
    END
  END s1a[145]
  PIN s1a[146]
    DIRECTION INPUT ;
    USE SIGNAL ;
    PORT
      LAYER M5 ;
        RECT  195.264 215.916 195.288 216 ;
    END
  END s1a[146]
  PIN s1a[147]
    DIRECTION INPUT ;
    USE SIGNAL ;
    PORT
      LAYER M5 ;
        RECT  196.416 215.916 196.44 216 ;
    END
  END s1a[147]
  PIN s1a[148]
    DIRECTION INPUT ;
    USE SIGNAL ;
    PORT
      LAYER M5 ;
        RECT  197.616 215.916 197.64 216 ;
    END
  END s1a[148]
  PIN s1a[149]
    DIRECTION INPUT ;
    USE SIGNAL ;
    PORT
      LAYER M5 ;
        RECT  198.816 215.916 198.84 216 ;
    END
  END s1a[149]
  PIN s1a[14]
    DIRECTION INPUT ;
    USE SIGNAL ;
    PORT
      LAYER M5 ;
        RECT  38.784 215.916 38.808 216 ;
    END
  END s1a[14]
  PIN s1a[150]
    DIRECTION INPUT ;
    USE SIGNAL ;
    PORT
      LAYER M5 ;
        RECT  199.968 215.916 199.992 216 ;
    END
  END s1a[150]
  PIN s1a[151]
    DIRECTION INPUT ;
    USE SIGNAL ;
    PORT
      LAYER M5 ;
        RECT  201.168 215.916 201.192 216 ;
    END
  END s1a[151]
  PIN s1a[152]
    DIRECTION INPUT ;
    USE SIGNAL ;
    PORT
      LAYER M5 ;
        RECT  202.368 215.916 202.392 216 ;
    END
  END s1a[152]
  PIN s1a[153]
    DIRECTION INPUT ;
    USE SIGNAL ;
    PORT
      LAYER M5 ;
        RECT  203.52 215.916 203.544 216 ;
    END
  END s1a[153]
  PIN s1a[154]
    DIRECTION INPUT ;
    USE SIGNAL ;
    PORT
      LAYER M5 ;
        RECT  204.72 215.916 204.744 216 ;
    END
  END s1a[154]
  PIN s1a[155]
    DIRECTION INPUT ;
    USE SIGNAL ;
    PORT
      LAYER M5 ;
        RECT  205.92 215.916 205.944 216 ;
    END
  END s1a[155]
  PIN s1a[156]
    DIRECTION INPUT ;
    USE SIGNAL ;
    PORT
      LAYER M5 ;
        RECT  207.12 215.916 207.144 216 ;
    END
  END s1a[156]
  PIN s1a[157]
    DIRECTION INPUT ;
    USE SIGNAL ;
    PORT
      LAYER M5 ;
        RECT  208.272 215.916 208.296 216 ;
    END
  END s1a[157]
  PIN s1a[158]
    DIRECTION INPUT ;
    USE SIGNAL ;
    PORT
      LAYER M5 ;
        RECT  209.472 215.916 209.496 216 ;
    END
  END s1a[158]
  PIN s1a[159]
    DIRECTION INPUT ;
    USE SIGNAL ;
    PORT
      LAYER M5 ;
        RECT  210.72 215.916 210.744 216 ;
    END
  END s1a[159]
  PIN s1a[15]
    DIRECTION INPUT ;
    USE SIGNAL ;
    PORT
      LAYER M5 ;
        RECT  39.984 215.916 40.008 216 ;
    END
  END s1a[15]
  PIN s1a[160]
    DIRECTION INPUT ;
    USE SIGNAL ;
    PORT
      LAYER M5 ;
        RECT  211.824 215.916 211.848 216 ;
    END
  END s1a[160]
  PIN s1a[161]
    DIRECTION INPUT ;
    USE SIGNAL ;
    PORT
      LAYER M5 ;
        RECT  213.024 215.916 213.048 216 ;
    END
  END s1a[161]
  PIN s1a[162]
    DIRECTION INPUT ;
    USE SIGNAL ;
    PORT
      LAYER M5 ;
        RECT  214.224 215.916 214.248 216 ;
    END
  END s1a[162]
  PIN s1a[163]
    DIRECTION INPUT ;
    USE SIGNAL ;
    PORT
      LAYER M5 ;
        RECT  215.376 215.916 215.4 216 ;
    END
  END s1a[163]
  PIN s1a[164]
    DIRECTION INPUT ;
    USE SIGNAL ;
    PORT
      LAYER M5 ;
        RECT  216.576 215.916 216.6 216 ;
    END
  END s1a[164]
  PIN s1a[165]
    DIRECTION INPUT ;
    USE SIGNAL ;
    PORT
      LAYER M5 ;
        RECT  217.776 215.916 217.8 216 ;
    END
  END s1a[165]
  PIN s1a[166]
    DIRECTION INPUT ;
    USE SIGNAL ;
    PORT
      LAYER M5 ;
        RECT  218.928 215.916 218.952 216 ;
    END
  END s1a[166]
  PIN s1a[167]
    DIRECTION INPUT ;
    USE SIGNAL ;
    PORT
      LAYER M5 ;
        RECT  220.128 215.916 220.152 216 ;
    END
  END s1a[167]
  PIN s1a[168]
    DIRECTION INPUT ;
    USE SIGNAL ;
    PORT
      LAYER M5 ;
        RECT  221.376 215.916 221.4 216 ;
    END
  END s1a[168]
  PIN s1a[169]
    DIRECTION INPUT ;
    USE SIGNAL ;
    PORT
      LAYER M5 ;
        RECT  222.528 215.916 222.552 216 ;
    END
  END s1a[169]
  PIN s1a[16]
    DIRECTION INPUT ;
    USE SIGNAL ;
    PORT
      LAYER M5 ;
        RECT  41.136 215.916 41.16 216 ;
    END
  END s1a[16]
  PIN s1a[170]
    DIRECTION INPUT ;
    USE SIGNAL ;
    PORT
      LAYER M5 ;
        RECT  223.68 215.916 223.704 216 ;
    END
  END s1a[170]
  PIN s1a[171]
    DIRECTION INPUT ;
    USE SIGNAL ;
    PORT
      LAYER M5 ;
        RECT  224.88 215.916 224.904 216 ;
    END
  END s1a[171]
  PIN s1a[172]
    DIRECTION INPUT ;
    USE SIGNAL ;
    PORT
      LAYER M5 ;
        RECT  226.08 215.916 226.104 216 ;
    END
  END s1a[172]
  PIN s1a[173]
    DIRECTION INPUT ;
    USE SIGNAL ;
    PORT
      LAYER M5 ;
        RECT  227.232 215.916 227.256 216 ;
    END
  END s1a[173]
  PIN s1a[174]
    DIRECTION INPUT ;
    USE SIGNAL ;
    PORT
      LAYER M5 ;
        RECT  228.432 215.916 228.456 216 ;
    END
  END s1a[174]
  PIN s1a[175]
    DIRECTION INPUT ;
    USE SIGNAL ;
    PORT
      LAYER M5 ;
        RECT  229.632 215.916 229.656 216 ;
    END
  END s1a[175]
  PIN s1a[176]
    DIRECTION INPUT ;
    USE SIGNAL ;
    PORT
      LAYER M5 ;
        RECT  230.784 215.916 230.808 216 ;
    END
  END s1a[176]
  PIN s1a[177]
    DIRECTION INPUT ;
    USE SIGNAL ;
    PORT
      LAYER M5 ;
        RECT  231.984 215.916 232.008 216 ;
    END
  END s1a[177]
  PIN s1a[178]
    DIRECTION INPUT ;
    USE SIGNAL ;
    PORT
      LAYER M5 ;
        RECT  233.184 215.916 233.208 216 ;
    END
  END s1a[178]
  PIN s1a[179]
    DIRECTION INPUT ;
    USE SIGNAL ;
    PORT
      LAYER M5 ;
        RECT  234.384 215.916 234.408 216 ;
    END
  END s1a[179]
  PIN s1a[17]
    DIRECTION INPUT ;
    USE SIGNAL ;
    PORT
      LAYER M5 ;
        RECT  42.336 215.916 42.36 216 ;
    END
  END s1a[17]
  PIN s1a[180]
    DIRECTION INPUT ;
    USE SIGNAL ;
    PORT
      LAYER M5 ;
        RECT  235.536 215.916 235.56 216 ;
    END
  END s1a[180]
  PIN s1a[181]
    DIRECTION INPUT ;
    USE SIGNAL ;
    PORT
      LAYER M5 ;
        RECT  236.736 215.916 236.76 216 ;
    END
  END s1a[181]
  PIN s1a[182]
    DIRECTION INPUT ;
    USE SIGNAL ;
    PORT
      LAYER M5 ;
        RECT  237.936 215.916 237.96 216 ;
    END
  END s1a[182]
  PIN s1a[183]
    DIRECTION INPUT ;
    USE SIGNAL ;
    PORT
      LAYER M5 ;
        RECT  239.088 215.916 239.112 216 ;
    END
  END s1a[183]
  PIN s1a[184]
    DIRECTION INPUT ;
    USE SIGNAL ;
    PORT
      LAYER M5 ;
        RECT  240.288 215.916 240.312 216 ;
    END
  END s1a[184]
  PIN s1a[185]
    DIRECTION INPUT ;
    USE SIGNAL ;
    PORT
      LAYER M5 ;
        RECT  241.488 215.916 241.512 216 ;
    END
  END s1a[185]
  PIN s1a[186]
    DIRECTION INPUT ;
    USE SIGNAL ;
    PORT
      LAYER M5 ;
        RECT  242.64 215.916 242.664 216 ;
    END
  END s1a[186]
  PIN s1a[187]
    DIRECTION INPUT ;
    USE SIGNAL ;
    PORT
      LAYER M5 ;
        RECT  243.84 215.916 243.864 216 ;
    END
  END s1a[187]
  PIN s1a[188]
    DIRECTION INPUT ;
    USE SIGNAL ;
    PORT
      LAYER M5 ;
        RECT  245.04 215.916 245.064 216 ;
    END
  END s1a[188]
  PIN s1a[189]
    DIRECTION INPUT ;
    USE SIGNAL ;
    PORT
      LAYER M5 ;
        RECT  246.192 215.916 246.216 216 ;
    END
  END s1a[189]
  PIN s1a[18]
    DIRECTION INPUT ;
    USE SIGNAL ;
    PORT
      LAYER M5 ;
        RECT  43.536 215.916 43.56 216 ;
    END
  END s1a[18]
  PIN s1a[190]
    DIRECTION INPUT ;
    USE SIGNAL ;
    PORT
      LAYER M5 ;
        RECT  247.392 215.916 247.416 216 ;
    END
  END s1a[190]
  PIN s1a[191]
    DIRECTION INPUT ;
    USE SIGNAL ;
    PORT
      LAYER M5 ;
        RECT  248.592 215.916 248.616 216 ;
    END
  END s1a[191]
  PIN s1a[192]
    DIRECTION INPUT ;
    USE SIGNAL ;
    PORT
      LAYER M5 ;
        RECT  249.792 215.916 249.816 216 ;
    END
  END s1a[192]
  PIN s1a[193]
    DIRECTION INPUT ;
    USE SIGNAL ;
    PORT
      LAYER M5 ;
        RECT  250.944 215.916 250.968 216 ;
    END
  END s1a[193]
  PIN s1a[194]
    DIRECTION INPUT ;
    USE SIGNAL ;
    PORT
      LAYER M5 ;
        RECT  252.144 215.916 252.168 216 ;
    END
  END s1a[194]
  PIN s1a[195]
    DIRECTION INPUT ;
    USE SIGNAL ;
    PORT
      LAYER M5 ;
        RECT  253.344 215.916 253.368 216 ;
    END
  END s1a[195]
  PIN s1a[196]
    DIRECTION INPUT ;
    USE SIGNAL ;
    PORT
      LAYER M5 ;
        RECT  254.496 215.916 254.52 216 ;
    END
  END s1a[196]
  PIN s1a[197]
    DIRECTION INPUT ;
    USE SIGNAL ;
    PORT
      LAYER M5 ;
        RECT  255.696 215.916 255.72 216 ;
    END
  END s1a[197]
  PIN s1a[198]
    DIRECTION INPUT ;
    USE SIGNAL ;
    PORT
      LAYER M5 ;
        RECT  256.896 215.916 256.92 216 ;
    END
  END s1a[198]
  PIN s1a[199]
    DIRECTION INPUT ;
    USE SIGNAL ;
    PORT
      LAYER M5 ;
        RECT  258.048 215.916 258.072 216 ;
    END
  END s1a[199]
  PIN s1a[19]
    DIRECTION INPUT ;
    USE SIGNAL ;
    PORT
      LAYER M5 ;
        RECT  44.688 215.916 44.712 216 ;
    END
  END s1a[19]
  PIN s1a[1]
    DIRECTION INPUT ;
    USE SIGNAL ;
    PORT
      LAYER M5 ;
        RECT  23.376 215.916 23.4 216 ;
    END
  END s1a[1]
  PIN s1a[200]
    DIRECTION INPUT ;
    USE SIGNAL ;
    PORT
      LAYER M5 ;
        RECT  259.248 215.916 259.272 216 ;
    END
  END s1a[200]
  PIN s1a[201]
    DIRECTION INPUT ;
    USE SIGNAL ;
    PORT
      LAYER M5 ;
        RECT  260.448 215.916 260.472 216 ;
    END
  END s1a[201]
  PIN s1a[202]
    DIRECTION INPUT ;
    USE SIGNAL ;
    PORT
      LAYER M5 ;
        RECT  261.648 215.916 261.672 216 ;
    END
  END s1a[202]
  PIN s1a[203]
    DIRECTION INPUT ;
    USE SIGNAL ;
    PORT
      LAYER M5 ;
        RECT  262.8 215.916 262.824 216 ;
    END
  END s1a[203]
  PIN s1a[204]
    DIRECTION INPUT ;
    USE SIGNAL ;
    PORT
      LAYER M5 ;
        RECT  264 215.916 264.024 216 ;
    END
  END s1a[204]
  PIN s1a[205]
    DIRECTION INPUT ;
    USE SIGNAL ;
    PORT
      LAYER M5 ;
        RECT  265.2 215.916 265.224 216 ;
    END
  END s1a[205]
  PIN s1a[206]
    DIRECTION INPUT ;
    USE SIGNAL ;
    PORT
      LAYER M5 ;
        RECT  266.352 215.916 266.376 216 ;
    END
  END s1a[206]
  PIN s1a[207]
    DIRECTION INPUT ;
    USE SIGNAL ;
    PORT
      LAYER M5 ;
        RECT  267.552 215.916 267.576 216 ;
    END
  END s1a[207]
  PIN s1a[208]
    DIRECTION INPUT ;
    USE SIGNAL ;
    PORT
      LAYER M5 ;
        RECT  268.752 215.916 268.776 216 ;
    END
  END s1a[208]
  PIN s1a[209]
    DIRECTION INPUT ;
    USE SIGNAL ;
    PORT
      LAYER M5 ;
        RECT  269.952 215.916 269.976 216 ;
    END
  END s1a[209]
  PIN s1a[20]
    DIRECTION INPUT ;
    USE SIGNAL ;
    PORT
      LAYER M5 ;
        RECT  45.888 215.916 45.912 216 ;
    END
  END s1a[20]
  PIN s1a[210]
    DIRECTION INPUT ;
    USE SIGNAL ;
    PORT
      LAYER M5 ;
        RECT  271.104 215.916 271.128 216 ;
    END
  END s1a[210]
  PIN s1a[211]
    DIRECTION INPUT ;
    USE SIGNAL ;
    PORT
      LAYER M5 ;
        RECT  272.304 215.916 272.328 216 ;
    END
  END s1a[211]
  PIN s1a[212]
    DIRECTION INPUT ;
    USE SIGNAL ;
    PORT
      LAYER M5 ;
        RECT  273.456 215.916 273.48 216 ;
    END
  END s1a[212]
  PIN s1a[213]
    DIRECTION INPUT ;
    USE SIGNAL ;
    PORT
      LAYER M5 ;
        RECT  274.656 215.916 274.68 216 ;
    END
  END s1a[213]
  PIN s1a[214]
    DIRECTION INPUT ;
    USE SIGNAL ;
    PORT
      LAYER M5 ;
        RECT  275.856 215.916 275.88 216 ;
    END
  END s1a[214]
  PIN s1a[215]
    DIRECTION INPUT ;
    USE SIGNAL ;
    PORT
      LAYER M5 ;
        RECT  277.056 215.916 277.08 216 ;
    END
  END s1a[215]
  PIN s1a[216]
    DIRECTION INPUT ;
    USE SIGNAL ;
    PORT
      LAYER M5 ;
        RECT  278.208 215.916 278.232 216 ;
    END
  END s1a[216]
  PIN s1a[217]
    DIRECTION INPUT ;
    USE SIGNAL ;
    PORT
      LAYER M5 ;
        RECT  279.408 215.916 279.432 216 ;
    END
  END s1a[217]
  PIN s1a[218]
    DIRECTION INPUT ;
    USE SIGNAL ;
    PORT
      LAYER M5 ;
        RECT  280.608 215.916 280.632 216 ;
    END
  END s1a[218]
  PIN s1a[219]
    DIRECTION INPUT ;
    USE SIGNAL ;
    PORT
      LAYER M5 ;
        RECT  281.76 215.916 281.784 216 ;
    END
  END s1a[219]
  PIN s1a[21]
    DIRECTION INPUT ;
    USE SIGNAL ;
    PORT
      LAYER M5 ;
        RECT  47.088 215.916 47.112 216 ;
    END
  END s1a[21]
  PIN s1a[220]
    DIRECTION INPUT ;
    USE SIGNAL ;
    PORT
      LAYER M5 ;
        RECT  282.96 215.916 282.984 216 ;
    END
  END s1a[220]
  PIN s1a[221]
    DIRECTION INPUT ;
    USE SIGNAL ;
    PORT
      LAYER M5 ;
        RECT  284.16 215.916 284.184 216 ;
    END
  END s1a[221]
  PIN s1a[222]
    DIRECTION INPUT ;
    USE SIGNAL ;
    PORT
      LAYER M5 ;
        RECT  285.312 215.916 285.336 216 ;
    END
  END s1a[222]
  PIN s1a[223]
    DIRECTION INPUT ;
    USE SIGNAL ;
    PORT
      LAYER M5 ;
        RECT  286.512 215.916 286.536 216 ;
    END
  END s1a[223]
  PIN s1a[224]
    DIRECTION INPUT ;
    USE SIGNAL ;
    PORT
      LAYER M5 ;
        RECT  287.712 215.916 287.736 216 ;
    END
  END s1a[224]
  PIN s1a[225]
    DIRECTION INPUT ;
    USE SIGNAL ;
    PORT
      LAYER M5 ;
        RECT  288.912 215.916 288.936 216 ;
    END
  END s1a[225]
  PIN s1a[226]
    DIRECTION INPUT ;
    USE SIGNAL ;
    PORT
      LAYER M5 ;
        RECT  290.064 215.916 290.088 216 ;
    END
  END s1a[226]
  PIN s1a[227]
    DIRECTION INPUT ;
    USE SIGNAL ;
    PORT
      LAYER M5 ;
        RECT  291.264 215.916 291.288 216 ;
    END
  END s1a[227]
  PIN s1a[228]
    DIRECTION INPUT ;
    USE SIGNAL ;
    PORT
      LAYER M5 ;
        RECT  292.464 215.916 292.488 216 ;
    END
  END s1a[228]
  PIN s1a[229]
    DIRECTION INPUT ;
    USE SIGNAL ;
    PORT
      LAYER M5 ;
        RECT  293.616 215.916 293.64 216 ;
    END
  END s1a[229]
  PIN s1a[22]
    DIRECTION INPUT ;
    USE SIGNAL ;
    PORT
      LAYER M5 ;
        RECT  48.24 215.916 48.264 216 ;
    END
  END s1a[22]
  PIN s1a[230]
    DIRECTION INPUT ;
    USE SIGNAL ;
    PORT
      LAYER M5 ;
        RECT  294.816 215.916 294.84 216 ;
    END
  END s1a[230]
  PIN s1a[231]
    DIRECTION INPUT ;
    USE SIGNAL ;
    PORT
      LAYER M5 ;
        RECT  296.016 215.916 296.04 216 ;
    END
  END s1a[231]
  PIN s1a[232]
    DIRECTION INPUT ;
    USE SIGNAL ;
    PORT
      LAYER M5 ;
        RECT  297.168 215.916 297.192 216 ;
    END
  END s1a[232]
  PIN s1a[233]
    DIRECTION INPUT ;
    USE SIGNAL ;
    PORT
      LAYER M5 ;
        RECT  298.368 215.916 298.392 216 ;
    END
  END s1a[233]
  PIN s1a[234]
    DIRECTION INPUT ;
    USE SIGNAL ;
    PORT
      LAYER M5 ;
        RECT  299.568 215.916 299.592 216 ;
    END
  END s1a[234]
  PIN s1a[235]
    DIRECTION INPUT ;
    USE SIGNAL ;
    PORT
      LAYER M5 ;
        RECT  300.72 215.916 300.744 216 ;
    END
  END s1a[235]
  PIN s1a[236]
    DIRECTION INPUT ;
    USE SIGNAL ;
    PORT
      LAYER M5 ;
        RECT  301.92 215.916 301.944 216 ;
    END
  END s1a[236]
  PIN s1a[237]
    DIRECTION INPUT ;
    USE SIGNAL ;
    PORT
      LAYER M5 ;
        RECT  303.12 215.916 303.144 216 ;
    END
  END s1a[237]
  PIN s1a[238]
    DIRECTION INPUT ;
    USE SIGNAL ;
    PORT
      LAYER M5 ;
        RECT  304.32 215.916 304.344 216 ;
    END
  END s1a[238]
  PIN s1a[239]
    DIRECTION INPUT ;
    USE SIGNAL ;
    PORT
      LAYER M5 ;
        RECT  305.472 215.916 305.496 216 ;
    END
  END s1a[239]
  PIN s1a[23]
    DIRECTION INPUT ;
    USE SIGNAL ;
    PORT
      LAYER M5 ;
        RECT  49.44 215.916 49.464 216 ;
    END
  END s1a[23]
  PIN s1a[240]
    DIRECTION INPUT ;
    USE SIGNAL ;
    PORT
      LAYER M5 ;
        RECT  306.672 215.916 306.696 216 ;
    END
  END s1a[240]
  PIN s1a[241]
    DIRECTION INPUT ;
    USE SIGNAL ;
    PORT
      LAYER M5 ;
        RECT  307.92 215.916 307.944 216 ;
    END
  END s1a[241]
  PIN s1a[242]
    DIRECTION INPUT ;
    USE SIGNAL ;
    PORT
      LAYER M5 ;
        RECT  309.024 215.916 309.048 216 ;
    END
  END s1a[242]
  PIN s1a[243]
    DIRECTION INPUT ;
    USE SIGNAL ;
    PORT
      LAYER M5 ;
        RECT  310.224 215.916 310.248 216 ;
    END
  END s1a[243]
  PIN s1a[244]
    DIRECTION INPUT ;
    USE SIGNAL ;
    PORT
      LAYER M5 ;
        RECT  311.424 215.916 311.448 216 ;
    END
  END s1a[244]
  PIN s1a[245]
    DIRECTION INPUT ;
    USE SIGNAL ;
    PORT
      LAYER M5 ;
        RECT  312.576 215.916 312.6 216 ;
    END
  END s1a[245]
  PIN s1a[246]
    DIRECTION INPUT ;
    USE SIGNAL ;
    PORT
      LAYER M5 ;
        RECT  313.776 215.916 313.8 216 ;
    END
  END s1a[246]
  PIN s1a[247]
    DIRECTION INPUT ;
    USE SIGNAL ;
    PORT
      LAYER M5 ;
        RECT  314.976 215.916 315 216 ;
    END
  END s1a[247]
  PIN s1a[248]
    DIRECTION INPUT ;
    USE SIGNAL ;
    PORT
      LAYER M5 ;
        RECT  316.128 215.916 316.152 216 ;
    END
  END s1a[248]
  PIN s1a[249]
    DIRECTION INPUT ;
    USE SIGNAL ;
    PORT
      LAYER M5 ;
        RECT  317.328 215.916 317.352 216 ;
    END
  END s1a[249]
  PIN s1a[24]
    DIRECTION INPUT ;
    USE SIGNAL ;
    PORT
      LAYER M5 ;
        RECT  50.64 215.916 50.664 216 ;
    END
  END s1a[24]
  PIN s1a[250]
    DIRECTION INPUT ;
    USE SIGNAL ;
    PORT
      LAYER M5 ;
        RECT  318.576 215.916 318.6 216 ;
    END
  END s1a[250]
  PIN s1a[251]
    DIRECTION INPUT ;
    USE SIGNAL ;
    PORT
      LAYER M5 ;
        RECT  319.728 215.916 319.752 216 ;
    END
  END s1a[251]
  PIN s1a[252]
    DIRECTION INPUT ;
    USE SIGNAL ;
    PORT
      LAYER M5 ;
        RECT  320.88 215.916 320.904 216 ;
    END
  END s1a[252]
  PIN s1a[253]
    DIRECTION INPUT ;
    USE SIGNAL ;
    PORT
      LAYER M5 ;
        RECT  322.08 215.916 322.104 216 ;
    END
  END s1a[253]
  PIN s1a[254]
    DIRECTION INPUT ;
    USE SIGNAL ;
    PORT
      LAYER M5 ;
        RECT  323.28 215.916 323.304 216 ;
    END
  END s1a[254]
  PIN s1a[255]
    DIRECTION INPUT ;
    USE SIGNAL ;
    PORT
      LAYER M5 ;
        RECT  324.432 215.916 324.456 216 ;
    END
  END s1a[255]
  PIN s1a[256]
    DIRECTION INPUT ;
    USE SIGNAL ;
    PORT
      LAYER M5 ;
        RECT  325.632 215.916 325.656 216 ;
    END
  END s1a[256]
  PIN s1a[257]
    DIRECTION INPUT ;
    USE SIGNAL ;
    PORT
      LAYER M5 ;
        RECT  326.832 215.916 326.856 216 ;
    END
  END s1a[257]
  PIN s1a[258]
    DIRECTION INPUT ;
    USE SIGNAL ;
    PORT
      LAYER M5 ;
        RECT  327.984 215.916 328.008 216 ;
    END
  END s1a[258]
  PIN s1a[259]
    DIRECTION INPUT ;
    USE SIGNAL ;
    PORT
      LAYER M5 ;
        RECT  329.184 215.916 329.208 216 ;
    END
  END s1a[259]
  PIN s1a[25]
    DIRECTION INPUT ;
    USE SIGNAL ;
    PORT
      LAYER M5 ;
        RECT  51.792 215.916 51.816 216 ;
    END
  END s1a[25]
  PIN s1a[260]
    DIRECTION INPUT ;
    USE SIGNAL ;
    PORT
      LAYER M5 ;
        RECT  330.384 215.916 330.408 216 ;
    END
  END s1a[260]
  PIN s1a[261]
    DIRECTION INPUT ;
    USE SIGNAL ;
    PORT
      LAYER M5 ;
        RECT  331.584 215.916 331.608 216 ;
    END
  END s1a[261]
  PIN s1a[262]
    DIRECTION INPUT ;
    USE SIGNAL ;
    PORT
      LAYER M5 ;
        RECT  332.736 215.916 332.76 216 ;
    END
  END s1a[262]
  PIN s1a[263]
    DIRECTION INPUT ;
    USE SIGNAL ;
    PORT
      LAYER M5 ;
        RECT  333.936 215.916 333.96 216 ;
    END
  END s1a[263]
  PIN s1a[264]
    DIRECTION INPUT ;
    USE SIGNAL ;
    PORT
      LAYER M5 ;
        RECT  335.136 215.916 335.16 216 ;
    END
  END s1a[264]
  PIN s1a[265]
    DIRECTION INPUT ;
    USE SIGNAL ;
    PORT
      LAYER M5 ;
        RECT  336.288 215.916 336.312 216 ;
    END
  END s1a[265]
  PIN s1a[266]
    DIRECTION INPUT ;
    USE SIGNAL ;
    PORT
      LAYER M5 ;
        RECT  337.488 215.916 337.512 216 ;
    END
  END s1a[266]
  PIN s1a[267]
    DIRECTION INPUT ;
    USE SIGNAL ;
    PORT
      LAYER M5 ;
        RECT  338.688 215.916 338.712 216 ;
    END
  END s1a[267]
  PIN s1a[268]
    DIRECTION INPUT ;
    USE SIGNAL ;
    PORT
      LAYER M5 ;
        RECT  339.84 215.916 339.864 216 ;
    END
  END s1a[268]
  PIN s1a[269]
    DIRECTION INPUT ;
    USE SIGNAL ;
    PORT
      LAYER M5 ;
        RECT  341.04 215.916 341.064 216 ;
    END
  END s1a[269]
  PIN s1a[26]
    DIRECTION INPUT ;
    USE SIGNAL ;
    PORT
      LAYER M5 ;
        RECT  52.992 215.916 53.016 216 ;
    END
  END s1a[26]
  PIN s1a[270]
    DIRECTION INPUT ;
    USE SIGNAL ;
    PORT
      LAYER M5 ;
        RECT  342.24 215.916 342.264 216 ;
    END
  END s1a[270]
  PIN s1a[271]
    DIRECTION INPUT ;
    USE SIGNAL ;
    PORT
      LAYER M5 ;
        RECT  343.392 215.916 343.416 216 ;
    END
  END s1a[271]
  PIN s1a[272]
    DIRECTION INPUT ;
    USE SIGNAL ;
    PORT
      LAYER M5 ;
        RECT  344.592 215.916 344.616 216 ;
    END
  END s1a[272]
  PIN s1a[273]
    DIRECTION INPUT ;
    USE SIGNAL ;
    PORT
      LAYER M5 ;
        RECT  345.792 215.916 345.816 216 ;
    END
  END s1a[273]
  PIN s1a[274]
    DIRECTION INPUT ;
    USE SIGNAL ;
    PORT
      LAYER M5 ;
        RECT  346.992 215.916 347.016 216 ;
    END
  END s1a[274]
  PIN s1a[275]
    DIRECTION INPUT ;
    USE SIGNAL ;
    PORT
      LAYER M5 ;
        RECT  348.144 215.916 348.168 216 ;
    END
  END s1a[275]
  PIN s1a[276]
    DIRECTION INPUT ;
    USE SIGNAL ;
    PORT
      LAYER M5 ;
        RECT  349.344 215.916 349.368 216 ;
    END
  END s1a[276]
  PIN s1a[277]
    DIRECTION INPUT ;
    USE SIGNAL ;
    PORT
      LAYER M5 ;
        RECT  350.544 215.916 350.568 216 ;
    END
  END s1a[277]
  PIN s1a[278]
    DIRECTION INPUT ;
    USE SIGNAL ;
    PORT
      LAYER M5 ;
        RECT  351.696 215.916 351.72 216 ;
    END
  END s1a[278]
  PIN s1a[279]
    DIRECTION INPUT ;
    USE SIGNAL ;
    PORT
      LAYER M5 ;
        RECT  352.896 215.916 352.92 216 ;
    END
  END s1a[279]
  PIN s1a[27]
    DIRECTION INPUT ;
    USE SIGNAL ;
    PORT
      LAYER M5 ;
        RECT  54.192 215.916 54.216 216 ;
    END
  END s1a[27]
  PIN s1a[280]
    DIRECTION INPUT ;
    USE SIGNAL ;
    PORT
      LAYER M5 ;
        RECT  354.096 215.916 354.12 216 ;
    END
  END s1a[280]
  PIN s1a[281]
    DIRECTION INPUT ;
    USE SIGNAL ;
    PORT
      LAYER M5 ;
        RECT  355.248 215.916 355.272 216 ;
    END
  END s1a[281]
  PIN s1a[282]
    DIRECTION INPUT ;
    USE SIGNAL ;
    PORT
      LAYER M5 ;
        RECT  356.448 215.916 356.472 216 ;
    END
  END s1a[282]
  PIN s1a[283]
    DIRECTION INPUT ;
    USE SIGNAL ;
    PORT
      LAYER M5 ;
        RECT  357.648 215.916 357.672 216 ;
    END
  END s1a[283]
  PIN s1a[284]
    DIRECTION INPUT ;
    USE SIGNAL ;
    PORT
      LAYER M5 ;
        RECT  358.848 215.916 358.872 216 ;
    END
  END s1a[284]
  PIN s1a[285]
    DIRECTION INPUT ;
    USE SIGNAL ;
    PORT
      LAYER M5 ;
        RECT  360 215.916 360.024 216 ;
    END
  END s1a[285]
  PIN s1a[286]
    DIRECTION INPUT ;
    USE SIGNAL ;
    PORT
      LAYER M5 ;
        RECT  361.2 215.916 361.224 216 ;
    END
  END s1a[286]
  PIN s1a[287]
    DIRECTION INPUT ;
    USE SIGNAL ;
    PORT
      LAYER M5 ;
        RECT  362.4 215.916 362.424 216 ;
    END
  END s1a[287]
  PIN s1a[288]
    DIRECTION INPUT ;
    USE SIGNAL ;
    PORT
      LAYER M5 ;
        RECT  363.552 215.916 363.576 216 ;
    END
  END s1a[288]
  PIN s1a[289]
    DIRECTION INPUT ;
    USE SIGNAL ;
    PORT
      LAYER M5 ;
        RECT  364.752 215.916 364.776 216 ;
    END
  END s1a[289]
  PIN s1a[28]
    DIRECTION INPUT ;
    USE SIGNAL ;
    PORT
      LAYER M5 ;
        RECT  55.392 215.916 55.416 216 ;
    END
  END s1a[28]
  PIN s1a[290]
    DIRECTION INPUT ;
    USE SIGNAL ;
    PORT
      LAYER M5 ;
        RECT  365.952 215.916 365.976 216 ;
    END
  END s1a[290]
  PIN s1a[291]
    DIRECTION INPUT ;
    USE SIGNAL ;
    PORT
      LAYER M5 ;
        RECT  367.152 215.916 367.176 216 ;
    END
  END s1a[291]
  PIN s1a[292]
    DIRECTION INPUT ;
    USE SIGNAL ;
    PORT
      LAYER M5 ;
        RECT  368.304 215.916 368.328 216 ;
    END
  END s1a[292]
  PIN s1a[293]
    DIRECTION INPUT ;
    USE SIGNAL ;
    PORT
      LAYER M5 ;
        RECT  369.504 215.916 369.528 216 ;
    END
  END s1a[293]
  PIN s1a[294]
    DIRECTION INPUT ;
    USE SIGNAL ;
    PORT
      LAYER M5 ;
        RECT  370.656 215.916 370.68 216 ;
    END
  END s1a[294]
  PIN s1a[295]
    DIRECTION INPUT ;
    USE SIGNAL ;
    PORT
      LAYER M5 ;
        RECT  371.856 215.916 371.88 216 ;
    END
  END s1a[295]
  PIN s1a[296]
    DIRECTION INPUT ;
    USE SIGNAL ;
    PORT
      LAYER M5 ;
        RECT  373.056 215.916 373.08 216 ;
    END
  END s1a[296]
  PIN s1a[297]
    DIRECTION INPUT ;
    USE SIGNAL ;
    PORT
      LAYER M5 ;
        RECT  374.256 215.916 374.28 216 ;
    END
  END s1a[297]
  PIN s1a[298]
    DIRECTION INPUT ;
    USE SIGNAL ;
    PORT
      LAYER M5 ;
        RECT  375.408 215.916 375.432 216 ;
    END
  END s1a[298]
  PIN s1a[299]
    DIRECTION INPUT ;
    USE SIGNAL ;
    PORT
      LAYER M5 ;
        RECT  376.608 215.916 376.632 216 ;
    END
  END s1a[299]
  PIN s1a[29]
    DIRECTION INPUT ;
    USE SIGNAL ;
    PORT
      LAYER M5 ;
        RECT  56.544 215.916 56.568 216 ;
    END
  END s1a[29]
  PIN s1a[2]
    DIRECTION INPUT ;
    USE SIGNAL ;
    PORT
      LAYER M5 ;
        RECT  24.528 215.916 24.552 216 ;
    END
  END s1a[2]
  PIN s1a[300]
    DIRECTION INPUT ;
    USE SIGNAL ;
    PORT
      LAYER M5 ;
        RECT  377.808 215.916 377.832 216 ;
    END
  END s1a[300]
  PIN s1a[301]
    DIRECTION INPUT ;
    USE SIGNAL ;
    PORT
      LAYER M5 ;
        RECT  378.96 215.916 378.984 216 ;
    END
  END s1a[301]
  PIN s1a[302]
    DIRECTION INPUT ;
    USE SIGNAL ;
    PORT
      LAYER M5 ;
        RECT  380.16 215.916 380.184 216 ;
    END
  END s1a[302]
  PIN s1a[303]
    DIRECTION INPUT ;
    USE SIGNAL ;
    PORT
      LAYER M5 ;
        RECT  381.36 215.916 381.384 216 ;
    END
  END s1a[303]
  PIN s1a[304]
    DIRECTION INPUT ;
    USE SIGNAL ;
    PORT
      LAYER M5 ;
        RECT  382.512 215.916 382.536 216 ;
    END
  END s1a[304]
  PIN s1a[305]
    DIRECTION INPUT ;
    USE SIGNAL ;
    PORT
      LAYER M5 ;
        RECT  383.712 215.916 383.736 216 ;
    END
  END s1a[305]
  PIN s1a[306]
    DIRECTION INPUT ;
    USE SIGNAL ;
    PORT
      LAYER M5 ;
        RECT  384.912 215.916 384.936 216 ;
    END
  END s1a[306]
  PIN s1a[307]
    DIRECTION INPUT ;
    USE SIGNAL ;
    PORT
      LAYER M5 ;
        RECT  386.112 215.916 386.136 216 ;
    END
  END s1a[307]
  PIN s1a[308]
    DIRECTION INPUT ;
    USE SIGNAL ;
    PORT
      LAYER M5 ;
        RECT  387.264 215.916 387.288 216 ;
    END
  END s1a[308]
  PIN s1a[309]
    DIRECTION INPUT ;
    USE SIGNAL ;
    PORT
      LAYER M5 ;
        RECT  388.464 215.916 388.488 216 ;
    END
  END s1a[309]
  PIN s1a[30]
    DIRECTION INPUT ;
    USE SIGNAL ;
    PORT
      LAYER M5 ;
        RECT  57.744 215.916 57.768 216 ;
    END
  END s1a[30]
  PIN s1a[310]
    DIRECTION INPUT ;
    USE SIGNAL ;
    PORT
      LAYER M5 ;
        RECT  389.664 215.916 389.688 216 ;
    END
  END s1a[310]
  PIN s1a[311]
    DIRECTION INPUT ;
    USE SIGNAL ;
    PORT
      LAYER M5 ;
        RECT  390.816 215.916 390.84 216 ;
    END
  END s1a[311]
  PIN s1a[312]
    DIRECTION INPUT ;
    USE SIGNAL ;
    PORT
      LAYER M5 ;
        RECT  392.016 215.916 392.04 216 ;
    END
  END s1a[312]
  PIN s1a[313]
    DIRECTION INPUT ;
    USE SIGNAL ;
    PORT
      LAYER M5 ;
        RECT  393.216 215.916 393.24 216 ;
    END
  END s1a[313]
  PIN s1a[314]
    DIRECTION INPUT ;
    USE SIGNAL ;
    PORT
      LAYER M5 ;
        RECT  394.368 215.916 394.392 216 ;
    END
  END s1a[314]
  PIN s1a[315]
    DIRECTION INPUT ;
    USE SIGNAL ;
    PORT
      LAYER M5 ;
        RECT  395.568 215.916 395.592 216 ;
    END
  END s1a[315]
  PIN s1a[316]
    DIRECTION INPUT ;
    USE SIGNAL ;
    PORT
      LAYER M5 ;
        RECT  396.768 215.916 396.792 216 ;
    END
  END s1a[316]
  PIN s1a[317]
    DIRECTION INPUT ;
    USE SIGNAL ;
    PORT
      LAYER M5 ;
        RECT  397.92 215.916 397.944 216 ;
    END
  END s1a[317]
  PIN s1a[318]
    DIRECTION INPUT ;
    USE SIGNAL ;
    PORT
      LAYER M5 ;
        RECT  399.12 215.916 399.144 216 ;
    END
  END s1a[318]
  PIN s1a[319]
    DIRECTION INPUT ;
    USE SIGNAL ;
    PORT
      LAYER M5 ;
        RECT  400.32 215.916 400.344 216 ;
    END
  END s1a[319]
  PIN s1a[31]
    DIRECTION INPUT ;
    USE SIGNAL ;
    PORT
      LAYER M5 ;
        RECT  58.944 215.916 58.968 216 ;
    END
  END s1a[31]
  PIN s1a[320]
    DIRECTION INPUT ;
    USE SIGNAL ;
    PORT
      LAYER M5 ;
        RECT  401.52 215.916 401.544 216 ;
    END
  END s1a[320]
  PIN s1a[321]
    DIRECTION INPUT ;
    USE SIGNAL ;
    PORT
      LAYER M5 ;
        RECT  402.672 215.916 402.696 216 ;
    END
  END s1a[321]
  PIN s1a[322]
    DIRECTION INPUT ;
    USE SIGNAL ;
    PORT
      LAYER M5 ;
        RECT  403.872 215.916 403.896 216 ;
    END
  END s1a[322]
  PIN s1a[323]
    DIRECTION INPUT ;
    USE SIGNAL ;
    PORT
      LAYER M5 ;
        RECT  405.12 215.916 405.144 216 ;
    END
  END s1a[323]
  PIN s1a[324]
    DIRECTION INPUT ;
    USE SIGNAL ;
    PORT
      LAYER M5 ;
        RECT  406.224 215.916 406.248 216 ;
    END
  END s1a[324]
  PIN s1a[325]
    DIRECTION INPUT ;
    USE SIGNAL ;
    PORT
      LAYER M5 ;
        RECT  407.424 215.916 407.448 216 ;
    END
  END s1a[325]
  PIN s1a[326]
    DIRECTION INPUT ;
    USE SIGNAL ;
    PORT
      LAYER M5 ;
        RECT  408.624 215.916 408.648 216 ;
    END
  END s1a[326]
  PIN s1a[327]
    DIRECTION INPUT ;
    USE SIGNAL ;
    PORT
      LAYER M5 ;
        RECT  409.776 215.916 409.8 216 ;
    END
  END s1a[327]
  PIN s1a[32]
    DIRECTION INPUT ;
    USE SIGNAL ;
    PORT
      LAYER M5 ;
        RECT  60.096 215.916 60.12 216 ;
    END
  END s1a[32]
  PIN s1a[33]
    DIRECTION INPUT ;
    USE SIGNAL ;
    PORT
      LAYER M5 ;
        RECT  61.296 215.916 61.32 216 ;
    END
  END s1a[33]
  PIN s1a[34]
    DIRECTION INPUT ;
    USE SIGNAL ;
    PORT
      LAYER M5 ;
        RECT  62.496 215.916 62.52 216 ;
    END
  END s1a[34]
  PIN s1a[35]
    DIRECTION INPUT ;
    USE SIGNAL ;
    PORT
      LAYER M5 ;
        RECT  63.648 215.916 63.672 216 ;
    END
  END s1a[35]
  PIN s1a[36]
    DIRECTION INPUT ;
    USE SIGNAL ;
    PORT
      LAYER M5 ;
        RECT  64.848 215.916 64.872 216 ;
    END
  END s1a[36]
  PIN s1a[37]
    DIRECTION INPUT ;
    USE SIGNAL ;
    PORT
      LAYER M5 ;
        RECT  66.048 215.916 66.072 216 ;
    END
  END s1a[37]
  PIN s1a[38]
    DIRECTION INPUT ;
    USE SIGNAL ;
    PORT
      LAYER M5 ;
        RECT  67.248 215.916 67.272 216 ;
    END
  END s1a[38]
  PIN s1a[39]
    DIRECTION INPUT ;
    USE SIGNAL ;
    PORT
      LAYER M5 ;
        RECT  68.4 215.916 68.424 216 ;
    END
  END s1a[39]
  PIN s1a[3]
    DIRECTION INPUT ;
    USE SIGNAL ;
    PORT
      LAYER M5 ;
        RECT  25.728 215.916 25.752 216 ;
    END
  END s1a[3]
  PIN s1a[40]
    DIRECTION INPUT ;
    USE SIGNAL ;
    PORT
      LAYER M5 ;
        RECT  69.6 215.916 69.624 216 ;
    END
  END s1a[40]
  PIN s1a[41]
    DIRECTION INPUT ;
    USE SIGNAL ;
    PORT
      LAYER M5 ;
        RECT  70.8 215.916 70.824 216 ;
    END
  END s1a[41]
  PIN s1a[42]
    DIRECTION INPUT ;
    USE SIGNAL ;
    PORT
      LAYER M5 ;
        RECT  71.952 215.916 71.976 216 ;
    END
  END s1a[42]
  PIN s1a[43]
    DIRECTION INPUT ;
    USE SIGNAL ;
    PORT
      LAYER M5 ;
        RECT  73.152 215.916 73.176 216 ;
    END
  END s1a[43]
  PIN s1a[44]
    DIRECTION INPUT ;
    USE SIGNAL ;
    PORT
      LAYER M5 ;
        RECT  74.352 215.916 74.376 216 ;
    END
  END s1a[44]
  PIN s1a[45]
    DIRECTION INPUT ;
    USE SIGNAL ;
    PORT
      LAYER M5 ;
        RECT  75.552 215.916 75.576 216 ;
    END
  END s1a[45]
  PIN s1a[46]
    DIRECTION INPUT ;
    USE SIGNAL ;
    PORT
      LAYER M5 ;
        RECT  76.704 215.916 76.728 216 ;
    END
  END s1a[46]
  PIN s1a[47]
    DIRECTION INPUT ;
    USE SIGNAL ;
    PORT
      LAYER M5 ;
        RECT  77.904 215.916 77.928 216 ;
    END
  END s1a[47]
  PIN s1a[48]
    DIRECTION INPUT ;
    USE SIGNAL ;
    PORT
      LAYER M5 ;
        RECT  79.056 215.916 79.08 216 ;
    END
  END s1a[48]
  PIN s1a[49]
    DIRECTION INPUT ;
    USE SIGNAL ;
    PORT
      LAYER M5 ;
        RECT  80.256 215.916 80.28 216 ;
    END
  END s1a[49]
  PIN s1a[4]
    DIRECTION INPUT ;
    USE SIGNAL ;
    PORT
      LAYER M5 ;
        RECT  26.976 215.916 27 216 ;
    END
  END s1a[4]
  PIN s1a[50]
    DIRECTION INPUT ;
    USE SIGNAL ;
    PORT
      LAYER M5 ;
        RECT  81.456 215.916 81.48 216 ;
    END
  END s1a[50]
  PIN s1a[51]
    DIRECTION INPUT ;
    USE SIGNAL ;
    PORT
      LAYER M5 ;
        RECT  82.656 215.916 82.68 216 ;
    END
  END s1a[51]
  PIN s1a[52]
    DIRECTION INPUT ;
    USE SIGNAL ;
    PORT
      LAYER M5 ;
        RECT  83.808 215.916 83.832 216 ;
    END
  END s1a[52]
  PIN s1a[53]
    DIRECTION INPUT ;
    USE SIGNAL ;
    PORT
      LAYER M5 ;
        RECT  85.008 215.916 85.032 216 ;
    END
  END s1a[53]
  PIN s1a[54]
    DIRECTION INPUT ;
    USE SIGNAL ;
    PORT
      LAYER M5 ;
        RECT  86.208 215.916 86.232 216 ;
    END
  END s1a[54]
  PIN s1a[55]
    DIRECTION INPUT ;
    USE SIGNAL ;
    PORT
      LAYER M5 ;
        RECT  87.36 215.916 87.384 216 ;
    END
  END s1a[55]
  PIN s1a[56]
    DIRECTION INPUT ;
    USE SIGNAL ;
    PORT
      LAYER M5 ;
        RECT  88.56 215.916 88.584 216 ;
    END
  END s1a[56]
  PIN s1a[57]
    DIRECTION INPUT ;
    USE SIGNAL ;
    PORT
      LAYER M5 ;
        RECT  89.76 215.916 89.784 216 ;
    END
  END s1a[57]
  PIN s1a[58]
    DIRECTION INPUT ;
    USE SIGNAL ;
    PORT
      LAYER M5 ;
        RECT  90.912 215.916 90.936 216 ;
    END
  END s1a[58]
  PIN s1a[59]
    DIRECTION INPUT ;
    USE SIGNAL ;
    PORT
      LAYER M5 ;
        RECT  92.112 215.916 92.136 216 ;
    END
  END s1a[59]
  PIN s1a[5]
    DIRECTION INPUT ;
    USE SIGNAL ;
    PORT
      LAYER M5 ;
        RECT  28.128 215.916 28.152 216 ;
    END
  END s1a[5]
  PIN s1a[60]
    DIRECTION INPUT ;
    USE SIGNAL ;
    PORT
      LAYER M5 ;
        RECT  93.312 215.916 93.336 216 ;
    END
  END s1a[60]
  PIN s1a[61]
    DIRECTION INPUT ;
    USE SIGNAL ;
    PORT
      LAYER M5 ;
        RECT  94.512 215.916 94.536 216 ;
    END
  END s1a[61]
  PIN s1a[62]
    DIRECTION INPUT ;
    USE SIGNAL ;
    PORT
      LAYER M5 ;
        RECT  95.664 215.916 95.688 216 ;
    END
  END s1a[62]
  PIN s1a[63]
    DIRECTION INPUT ;
    USE SIGNAL ;
    PORT
      LAYER M5 ;
        RECT  96.864 215.916 96.888 216 ;
    END
  END s1a[63]
  PIN s1a[64]
    DIRECTION INPUT ;
    USE SIGNAL ;
    PORT
      LAYER M5 ;
        RECT  98.064 215.916 98.088 216 ;
    END
  END s1a[64]
  PIN s1a[65]
    DIRECTION INPUT ;
    USE SIGNAL ;
    PORT
      LAYER M5 ;
        RECT  99.216 215.916 99.24 216 ;
    END
  END s1a[65]
  PIN s1a[66]
    DIRECTION INPUT ;
    USE SIGNAL ;
    PORT
      LAYER M5 ;
        RECT  100.416 215.916 100.44 216 ;
    END
  END s1a[66]
  PIN s1a[67]
    DIRECTION INPUT ;
    USE SIGNAL ;
    PORT
      LAYER M5 ;
        RECT  101.616 215.916 101.64 216 ;
    END
  END s1a[67]
  PIN s1a[68]
    DIRECTION INPUT ;
    USE SIGNAL ;
    PORT
      LAYER M5 ;
        RECT  102.768 215.916 102.792 216 ;
    END
  END s1a[68]
  PIN s1a[69]
    DIRECTION INPUT ;
    USE SIGNAL ;
    PORT
      LAYER M5 ;
        RECT  103.968 215.916 103.992 216 ;
    END
  END s1a[69]
  PIN s1a[6]
    DIRECTION INPUT ;
    USE SIGNAL ;
    PORT
      LAYER M5 ;
        RECT  29.28 215.916 29.304 216 ;
    END
  END s1a[6]
  PIN s1a[70]
    DIRECTION INPUT ;
    USE SIGNAL ;
    PORT
      LAYER M5 ;
        RECT  105.168 215.916 105.192 216 ;
    END
  END s1a[70]
  PIN s1a[71]
    DIRECTION INPUT ;
    USE SIGNAL ;
    PORT
      LAYER M5 ;
        RECT  106.32 215.916 106.344 216 ;
    END
  END s1a[71]
  PIN s1a[72]
    DIRECTION INPUT ;
    USE SIGNAL ;
    PORT
      LAYER M5 ;
        RECT  107.52 215.916 107.544 216 ;
    END
  END s1a[72]
  PIN s1a[73]
    DIRECTION INPUT ;
    USE SIGNAL ;
    PORT
      LAYER M5 ;
        RECT  108.72 215.916 108.744 216 ;
    END
  END s1a[73]
  PIN s1a[74]
    DIRECTION INPUT ;
    USE SIGNAL ;
    PORT
      LAYER M5 ;
        RECT  109.92 215.916 109.944 216 ;
    END
  END s1a[74]
  PIN s1a[75]
    DIRECTION INPUT ;
    USE SIGNAL ;
    PORT
      LAYER M5 ;
        RECT  111.072 215.916 111.096 216 ;
    END
  END s1a[75]
  PIN s1a[76]
    DIRECTION INPUT ;
    USE SIGNAL ;
    PORT
      LAYER M5 ;
        RECT  112.272 215.916 112.296 216 ;
    END
  END s1a[76]
  PIN s1a[77]
    DIRECTION INPUT ;
    USE SIGNAL ;
    PORT
      LAYER M5 ;
        RECT  113.52 215.916 113.544 216 ;
    END
  END s1a[77]
  PIN s1a[78]
    DIRECTION INPUT ;
    USE SIGNAL ;
    PORT
      LAYER M5 ;
        RECT  114.624 215.916 114.648 216 ;
    END
  END s1a[78]
  PIN s1a[79]
    DIRECTION INPUT ;
    USE SIGNAL ;
    PORT
      LAYER M5 ;
        RECT  115.824 215.916 115.848 216 ;
    END
  END s1a[79]
  PIN s1a[7]
    DIRECTION INPUT ;
    USE SIGNAL ;
    PORT
      LAYER M5 ;
        RECT  30.48 215.916 30.504 216 ;
    END
  END s1a[7]
  PIN s1a[80]
    DIRECTION INPUT ;
    USE SIGNAL ;
    PORT
      LAYER M5 ;
        RECT  117.024 215.916 117.048 216 ;
    END
  END s1a[80]
  PIN s1a[81]
    DIRECTION INPUT ;
    USE SIGNAL ;
    PORT
      LAYER M5 ;
        RECT  118.176 215.916 118.2 216 ;
    END
  END s1a[81]
  PIN s1a[82]
    DIRECTION INPUT ;
    USE SIGNAL ;
    PORT
      LAYER M5 ;
        RECT  119.376 215.916 119.4 216 ;
    END
  END s1a[82]
  PIN s1a[83]
    DIRECTION INPUT ;
    USE SIGNAL ;
    PORT
      LAYER M5 ;
        RECT  120.576 215.916 120.6 216 ;
    END
  END s1a[83]
  PIN s1a[84]
    DIRECTION INPUT ;
    USE SIGNAL ;
    PORT
      LAYER M5 ;
        RECT  121.728 215.916 121.752 216 ;
    END
  END s1a[84]
  PIN s1a[85]
    DIRECTION INPUT ;
    USE SIGNAL ;
    PORT
      LAYER M5 ;
        RECT  122.928 215.916 122.952 216 ;
    END
  END s1a[85]
  PIN s1a[86]
    DIRECTION INPUT ;
    USE SIGNAL ;
    PORT
      LAYER M5 ;
        RECT  124.176 215.916 124.2 216 ;
    END
  END s1a[86]
  PIN s1a[87]
    DIRECTION INPUT ;
    USE SIGNAL ;
    PORT
      LAYER M5 ;
        RECT  125.328 215.916 125.352 216 ;
    END
  END s1a[87]
  PIN s1a[88]
    DIRECTION INPUT ;
    USE SIGNAL ;
    PORT
      LAYER M5 ;
        RECT  126.48 215.916 126.504 216 ;
    END
  END s1a[88]
  PIN s1a[89]
    DIRECTION INPUT ;
    USE SIGNAL ;
    PORT
      LAYER M5 ;
        RECT  127.68 215.916 127.704 216 ;
    END
  END s1a[89]
  PIN s1a[8]
    DIRECTION INPUT ;
    USE SIGNAL ;
    PORT
      LAYER M5 ;
        RECT  31.68 215.916 31.704 216 ;
    END
  END s1a[8]
  PIN s1a[90]
    DIRECTION INPUT ;
    USE SIGNAL ;
    PORT
      LAYER M5 ;
        RECT  128.88 215.916 128.904 216 ;
    END
  END s1a[90]
  PIN s1a[91]
    DIRECTION INPUT ;
    USE SIGNAL ;
    PORT
      LAYER M5 ;
        RECT  130.032 215.916 130.056 216 ;
    END
  END s1a[91]
  PIN s1a[92]
    DIRECTION INPUT ;
    USE SIGNAL ;
    PORT
      LAYER M5 ;
        RECT  131.232 215.916 131.256 216 ;
    END
  END s1a[92]
  PIN s1a[93]
    DIRECTION INPUT ;
    USE SIGNAL ;
    PORT
      LAYER M5 ;
        RECT  132.432 215.916 132.456 216 ;
    END
  END s1a[93]
  PIN s1a[94]
    DIRECTION INPUT ;
    USE SIGNAL ;
    PORT
      LAYER M5 ;
        RECT  133.584 215.916 133.608 216 ;
    END
  END s1a[94]
  PIN s1a[95]
    DIRECTION INPUT ;
    USE SIGNAL ;
    PORT
      LAYER M5 ;
        RECT  134.784 215.916 134.808 216 ;
    END
  END s1a[95]
  PIN s1a[96]
    DIRECTION INPUT ;
    USE SIGNAL ;
    PORT
      LAYER M5 ;
        RECT  135.984 215.916 136.008 216 ;
    END
  END s1a[96]
  PIN s1a[97]
    DIRECTION INPUT ;
    USE SIGNAL ;
    PORT
      LAYER M5 ;
        RECT  137.184 215.916 137.208 216 ;
    END
  END s1a[97]
  PIN s1a[98]
    DIRECTION INPUT ;
    USE SIGNAL ;
    PORT
      LAYER M5 ;
        RECT  138.336 215.916 138.36 216 ;
    END
  END s1a[98]
  PIN s1a[99]
    DIRECTION INPUT ;
    USE SIGNAL ;
    PORT
      LAYER M5 ;
        RECT  139.536 215.916 139.56 216 ;
    END
  END s1a[99]
  PIN s1a[9]
    DIRECTION INPUT ;
    USE SIGNAL ;
    PORT
      LAYER M5 ;
        RECT  32.832 215.916 32.856 216 ;
    END
  END s1a[9]
  PIN s1b[0]
    DIRECTION INPUT ;
    USE SIGNAL ;
    PORT
      LAYER M5 ;
        RECT  22.224 215.916 22.248 216 ;
    END
  END s1b[0]
  PIN s1b[100]
    DIRECTION INPUT ;
    USE SIGNAL ;
    PORT
      LAYER M5 ;
        RECT  140.784 215.916 140.808 216 ;
    END
  END s1b[100]
  PIN s1b[101]
    DIRECTION INPUT ;
    USE SIGNAL ;
    PORT
      LAYER M5 ;
        RECT  141.936 215.916 141.96 216 ;
    END
  END s1b[101]
  PIN s1b[102]
    DIRECTION INPUT ;
    USE SIGNAL ;
    PORT
      LAYER M5 ;
        RECT  143.136 215.916 143.16 216 ;
    END
  END s1b[102]
  PIN s1b[103]
    DIRECTION INPUT ;
    USE SIGNAL ;
    PORT
      LAYER M5 ;
        RECT  144.336 215.916 144.36 216 ;
    END
  END s1b[103]
  PIN s1b[104]
    DIRECTION INPUT ;
    USE SIGNAL ;
    PORT
      LAYER M5 ;
        RECT  145.488 215.916 145.512 216 ;
    END
  END s1b[104]
  PIN s1b[105]
    DIRECTION INPUT ;
    USE SIGNAL ;
    PORT
      LAYER M5 ;
        RECT  146.688 215.916 146.712 216 ;
    END
  END s1b[105]
  PIN s1b[106]
    DIRECTION INPUT ;
    USE SIGNAL ;
    PORT
      LAYER M5 ;
        RECT  147.888 215.916 147.912 216 ;
    END
  END s1b[106]
  PIN s1b[107]
    DIRECTION INPUT ;
    USE SIGNAL ;
    PORT
      LAYER M5 ;
        RECT  149.04 215.916 149.064 216 ;
    END
  END s1b[107]
  PIN s1b[108]
    DIRECTION INPUT ;
    USE SIGNAL ;
    PORT
      LAYER M5 ;
        RECT  150.24 215.916 150.264 216 ;
    END
  END s1b[108]
  PIN s1b[109]
    DIRECTION INPUT ;
    USE SIGNAL ;
    PORT
      LAYER M5 ;
        RECT  151.344 215.916 151.368 216 ;
    END
  END s1b[109]
  PIN s1b[10]
    DIRECTION INPUT ;
    USE SIGNAL ;
    PORT
      LAYER M5 ;
        RECT  34.08 215.916 34.104 216 ;
    END
  END s1b[10]
  PIN s1b[110]
    DIRECTION INPUT ;
    USE SIGNAL ;
    PORT
      LAYER M5 ;
        RECT  152.64 215.916 152.664 216 ;
    END
  END s1b[110]
  PIN s1b[111]
    DIRECTION INPUT ;
    USE SIGNAL ;
    PORT
      LAYER M5 ;
        RECT  153.792 215.916 153.816 216 ;
    END
  END s1b[111]
  PIN s1b[112]
    DIRECTION INPUT ;
    USE SIGNAL ;
    PORT
      LAYER M5 ;
        RECT  154.992 215.916 155.016 216 ;
    END
  END s1b[112]
  PIN s1b[113]
    DIRECTION INPUT ;
    USE SIGNAL ;
    PORT
      LAYER M5 ;
        RECT  156.192 215.916 156.216 216 ;
    END
  END s1b[113]
  PIN s1b[114]
    DIRECTION INPUT ;
    USE SIGNAL ;
    PORT
      LAYER M5 ;
        RECT  157.344 215.916 157.368 216 ;
    END
  END s1b[114]
  PIN s1b[115]
    DIRECTION INPUT ;
    USE SIGNAL ;
    PORT
      LAYER M5 ;
        RECT  158.544 215.916 158.568 216 ;
    END
  END s1b[115]
  PIN s1b[116]
    DIRECTION INPUT ;
    USE SIGNAL ;
    PORT
      LAYER M5 ;
        RECT  159.744 215.916 159.768 216 ;
    END
  END s1b[116]
  PIN s1b[117]
    DIRECTION INPUT ;
    USE SIGNAL ;
    PORT
      LAYER M5 ;
        RECT  160.896 215.916 160.92 216 ;
    END
  END s1b[117]
  PIN s1b[118]
    DIRECTION INPUT ;
    USE SIGNAL ;
    PORT
      LAYER M5 ;
        RECT  162 215.916 162.024 216 ;
    END
  END s1b[118]
  PIN s1b[119]
    DIRECTION INPUT ;
    USE SIGNAL ;
    PORT
      LAYER M5 ;
        RECT  163.296 215.916 163.32 216 ;
    END
  END s1b[119]
  PIN s1b[11]
    DIRECTION INPUT ;
    USE SIGNAL ;
    PORT
      LAYER M5 ;
        RECT  35.28 215.916 35.304 216 ;
    END
  END s1b[11]
  PIN s1b[120]
    DIRECTION INPUT ;
    USE SIGNAL ;
    PORT
      LAYER M5 ;
        RECT  164.496 215.916 164.52 216 ;
    END
  END s1b[120]
  PIN s1b[121]
    DIRECTION INPUT ;
    USE SIGNAL ;
    PORT
      LAYER M5 ;
        RECT  165.648 215.916 165.672 216 ;
    END
  END s1b[121]
  PIN s1b[122]
    DIRECTION INPUT ;
    USE SIGNAL ;
    PORT
      LAYER M5 ;
        RECT  166.848 215.916 166.872 216 ;
    END
  END s1b[122]
  PIN s1b[123]
    DIRECTION INPUT ;
    USE SIGNAL ;
    PORT
      LAYER M5 ;
        RECT  168.048 215.916 168.072 216 ;
    END
  END s1b[123]
  PIN s1b[124]
    DIRECTION INPUT ;
    USE SIGNAL ;
    PORT
      LAYER M5 ;
        RECT  169.2 215.916 169.224 216 ;
    END
  END s1b[124]
  PIN s1b[125]
    DIRECTION INPUT ;
    USE SIGNAL ;
    PORT
      LAYER M5 ;
        RECT  170.4 215.916 170.424 216 ;
    END
  END s1b[125]
  PIN s1b[126]
    DIRECTION INPUT ;
    USE SIGNAL ;
    PORT
      LAYER M5 ;
        RECT  171.6 215.916 171.624 216 ;
    END
  END s1b[126]
  PIN s1b[127]
    DIRECTION INPUT ;
    USE SIGNAL ;
    PORT
      LAYER M5 ;
        RECT  172.656 215.916 172.68 216 ;
    END
  END s1b[127]
  PIN s1b[128]
    DIRECTION INPUT ;
    USE SIGNAL ;
    PORT
      LAYER M5 ;
        RECT  173.952 215.916 173.976 216 ;
    END
  END s1b[128]
  PIN s1b[129]
    DIRECTION INPUT ;
    USE SIGNAL ;
    PORT
      LAYER M5 ;
        RECT  175.152 215.916 175.176 216 ;
    END
  END s1b[129]
  PIN s1b[12]
    DIRECTION INPUT ;
    USE SIGNAL ;
    PORT
      LAYER M5 ;
        RECT  36.432 215.916 36.456 216 ;
    END
  END s1b[12]
  PIN s1b[130]
    DIRECTION INPUT ;
    USE SIGNAL ;
    PORT
      LAYER M5 ;
        RECT  176.304 215.916 176.328 216 ;
    END
  END s1b[130]
  PIN s1b[131]
    DIRECTION INPUT ;
    USE SIGNAL ;
    PORT
      LAYER M5 ;
        RECT  177.504 215.916 177.528 216 ;
    END
  END s1b[131]
  PIN s1b[132]
    DIRECTION INPUT ;
    USE SIGNAL ;
    PORT
      LAYER M5 ;
        RECT  178.704 215.916 178.728 216 ;
    END
  END s1b[132]
  PIN s1b[133]
    DIRECTION INPUT ;
    USE SIGNAL ;
    PORT
      LAYER M5 ;
        RECT  179.904 215.916 179.928 216 ;
    END
  END s1b[133]
  PIN s1b[134]
    DIRECTION INPUT ;
    USE SIGNAL ;
    PORT
      LAYER M5 ;
        RECT  181.056 215.916 181.08 216 ;
    END
  END s1b[134]
  PIN s1b[135]
    DIRECTION INPUT ;
    USE SIGNAL ;
    PORT
      LAYER M5 ;
        RECT  182.256 215.916 182.28 216 ;
    END
  END s1b[135]
  PIN s1b[136]
    DIRECTION INPUT ;
    USE SIGNAL ;
    PORT
      LAYER M5 ;
        RECT  183.456 215.916 183.48 216 ;
    END
  END s1b[136]
  PIN s1b[137]
    DIRECTION INPUT ;
    USE SIGNAL ;
    PORT
      LAYER M5 ;
        RECT  184.608 215.916 184.632 216 ;
    END
  END s1b[137]
  PIN s1b[138]
    DIRECTION INPUT ;
    USE SIGNAL ;
    PORT
      LAYER M5 ;
        RECT  185.808 215.916 185.832 216 ;
    END
  END s1b[138]
  PIN s1b[139]
    DIRECTION INPUT ;
    USE SIGNAL ;
    PORT
      LAYER M5 ;
        RECT  187.008 215.916 187.032 216 ;
    END
  END s1b[139]
  PIN s1b[13]
    DIRECTION INPUT ;
    USE SIGNAL ;
    PORT
      LAYER M5 ;
        RECT  37.632 215.916 37.656 216 ;
    END
  END s1b[13]
  PIN s1b[140]
    DIRECTION INPUT ;
    USE SIGNAL ;
    PORT
      LAYER M5 ;
        RECT  188.16 215.916 188.184 216 ;
    END
  END s1b[140]
  PIN s1b[141]
    DIRECTION INPUT ;
    USE SIGNAL ;
    PORT
      LAYER M5 ;
        RECT  189.36 215.916 189.384 216 ;
    END
  END s1b[141]
  PIN s1b[142]
    DIRECTION INPUT ;
    USE SIGNAL ;
    PORT
      LAYER M5 ;
        RECT  190.56 215.916 190.584 216 ;
    END
  END s1b[142]
  PIN s1b[143]
    DIRECTION INPUT ;
    USE SIGNAL ;
    PORT
      LAYER M5 ;
        RECT  191.76 215.916 191.784 216 ;
    END
  END s1b[143]
  PIN s1b[144]
    DIRECTION INPUT ;
    USE SIGNAL ;
    PORT
      LAYER M5 ;
        RECT  192.912 215.916 192.936 216 ;
    END
  END s1b[144]
  PIN s1b[145]
    DIRECTION INPUT ;
    USE SIGNAL ;
    PORT
      LAYER M5 ;
        RECT  194.112 215.916 194.136 216 ;
    END
  END s1b[145]
  PIN s1b[146]
    DIRECTION INPUT ;
    USE SIGNAL ;
    PORT
      LAYER M5 ;
        RECT  195.312 215.916 195.336 216 ;
    END
  END s1b[146]
  PIN s1b[147]
    DIRECTION INPUT ;
    USE SIGNAL ;
    PORT
      LAYER M5 ;
        RECT  196.464 215.916 196.488 216 ;
    END
  END s1b[147]
  PIN s1b[148]
    DIRECTION INPUT ;
    USE SIGNAL ;
    PORT
      LAYER M5 ;
        RECT  197.664 215.916 197.688 216 ;
    END
  END s1b[148]
  PIN s1b[149]
    DIRECTION INPUT ;
    USE SIGNAL ;
    PORT
      LAYER M5 ;
        RECT  198.864 215.916 198.888 216 ;
    END
  END s1b[149]
  PIN s1b[14]
    DIRECTION INPUT ;
    USE SIGNAL ;
    PORT
      LAYER M5 ;
        RECT  38.832 215.916 38.856 216 ;
    END
  END s1b[14]
  PIN s1b[150]
    DIRECTION INPUT ;
    USE SIGNAL ;
    PORT
      LAYER M5 ;
        RECT  200.016 215.916 200.04 216 ;
    END
  END s1b[150]
  PIN s1b[151]
    DIRECTION INPUT ;
    USE SIGNAL ;
    PORT
      LAYER M5 ;
        RECT  201.216 215.916 201.24 216 ;
    END
  END s1b[151]
  PIN s1b[152]
    DIRECTION INPUT ;
    USE SIGNAL ;
    PORT
      LAYER M5 ;
        RECT  202.416 215.916 202.44 216 ;
    END
  END s1b[152]
  PIN s1b[153]
    DIRECTION INPUT ;
    USE SIGNAL ;
    PORT
      LAYER M5 ;
        RECT  203.568 215.916 203.592 216 ;
    END
  END s1b[153]
  PIN s1b[154]
    DIRECTION INPUT ;
    USE SIGNAL ;
    PORT
      LAYER M5 ;
        RECT  204.768 215.916 204.792 216 ;
    END
  END s1b[154]
  PIN s1b[155]
    DIRECTION INPUT ;
    USE SIGNAL ;
    PORT
      LAYER M5 ;
        RECT  205.968 215.916 205.992 216 ;
    END
  END s1b[155]
  PIN s1b[156]
    DIRECTION INPUT ;
    USE SIGNAL ;
    PORT
      LAYER M5 ;
        RECT  207.168 215.916 207.192 216 ;
    END
  END s1b[156]
  PIN s1b[157]
    DIRECTION INPUT ;
    USE SIGNAL ;
    PORT
      LAYER M5 ;
        RECT  208.32 215.916 208.344 216 ;
    END
  END s1b[157]
  PIN s1b[158]
    DIRECTION INPUT ;
    USE SIGNAL ;
    PORT
      LAYER M5 ;
        RECT  209.52 215.916 209.544 216 ;
    END
  END s1b[158]
  PIN s1b[159]
    DIRECTION INPUT ;
    USE SIGNAL ;
    PORT
      LAYER M5 ;
        RECT  210.624 215.916 210.648 216 ;
    END
  END s1b[159]
  PIN s1b[15]
    DIRECTION INPUT ;
    USE SIGNAL ;
    PORT
      LAYER M5 ;
        RECT  40.032 215.916 40.056 216 ;
    END
  END s1b[15]
  PIN s1b[160]
    DIRECTION INPUT ;
    USE SIGNAL ;
    PORT
      LAYER M5 ;
        RECT  211.872 215.916 211.896 216 ;
    END
  END s1b[160]
  PIN s1b[161]
    DIRECTION INPUT ;
    USE SIGNAL ;
    PORT
      LAYER M5 ;
        RECT  213.072 215.916 213.096 216 ;
    END
  END s1b[161]
  PIN s1b[162]
    DIRECTION INPUT ;
    USE SIGNAL ;
    PORT
      LAYER M5 ;
        RECT  214.272 215.916 214.296 216 ;
    END
  END s1b[162]
  PIN s1b[163]
    DIRECTION INPUT ;
    USE SIGNAL ;
    PORT
      LAYER M5 ;
        RECT  215.424 215.916 215.448 216 ;
    END
  END s1b[163]
  PIN s1b[164]
    DIRECTION INPUT ;
    USE SIGNAL ;
    PORT
      LAYER M5 ;
        RECT  216.624 215.916 216.648 216 ;
    END
  END s1b[164]
  PIN s1b[165]
    DIRECTION INPUT ;
    USE SIGNAL ;
    PORT
      LAYER M5 ;
        RECT  217.824 215.916 217.848 216 ;
    END
  END s1b[165]
  PIN s1b[166]
    DIRECTION INPUT ;
    USE SIGNAL ;
    PORT
      LAYER M5 ;
        RECT  218.976 215.916 219 216 ;
    END
  END s1b[166]
  PIN s1b[167]
    DIRECTION INPUT ;
    USE SIGNAL ;
    PORT
      LAYER M5 ;
        RECT  220.176 215.916 220.2 216 ;
    END
  END s1b[167]
  PIN s1b[168]
    DIRECTION INPUT ;
    USE SIGNAL ;
    PORT
      LAYER M5 ;
        RECT  221.28 215.916 221.304 216 ;
    END
  END s1b[168]
  PIN s1b[169]
    DIRECTION INPUT ;
    USE SIGNAL ;
    PORT
      LAYER M5 ;
        RECT  222.576 215.916 222.6 216 ;
    END
  END s1b[169]
  PIN s1b[16]
    DIRECTION INPUT ;
    USE SIGNAL ;
    PORT
      LAYER M5 ;
        RECT  41.184 215.916 41.208 216 ;
    END
  END s1b[16]
  PIN s1b[170]
    DIRECTION INPUT ;
    USE SIGNAL ;
    PORT
      LAYER M5 ;
        RECT  223.728 215.916 223.752 216 ;
    END
  END s1b[170]
  PIN s1b[171]
    DIRECTION INPUT ;
    USE SIGNAL ;
    PORT
      LAYER M5 ;
        RECT  224.928 215.916 224.952 216 ;
    END
  END s1b[171]
  PIN s1b[172]
    DIRECTION INPUT ;
    USE SIGNAL ;
    PORT
      LAYER M5 ;
        RECT  226.128 215.916 226.152 216 ;
    END
  END s1b[172]
  PIN s1b[173]
    DIRECTION INPUT ;
    USE SIGNAL ;
    PORT
      LAYER M5 ;
        RECT  227.28 215.916 227.304 216 ;
    END
  END s1b[173]
  PIN s1b[174]
    DIRECTION INPUT ;
    USE SIGNAL ;
    PORT
      LAYER M5 ;
        RECT  228.48 215.916 228.504 216 ;
    END
  END s1b[174]
  PIN s1b[175]
    DIRECTION INPUT ;
    USE SIGNAL ;
    PORT
      LAYER M5 ;
        RECT  229.68 215.916 229.704 216 ;
    END
  END s1b[175]
  PIN s1b[176]
    DIRECTION INPUT ;
    USE SIGNAL ;
    PORT
      LAYER M5 ;
        RECT  230.832 215.916 230.856 216 ;
    END
  END s1b[176]
  PIN s1b[177]
    DIRECTION INPUT ;
    USE SIGNAL ;
    PORT
      LAYER M5 ;
        RECT  232.032 215.916 232.056 216 ;
    END
  END s1b[177]
  PIN s1b[178]
    DIRECTION INPUT ;
    USE SIGNAL ;
    PORT
      LAYER M5 ;
        RECT  233.232 215.916 233.256 216 ;
    END
  END s1b[178]
  PIN s1b[179]
    DIRECTION INPUT ;
    USE SIGNAL ;
    PORT
      LAYER M5 ;
        RECT  234.432 215.916 234.456 216 ;
    END
  END s1b[179]
  PIN s1b[17]
    DIRECTION INPUT ;
    USE SIGNAL ;
    PORT
      LAYER M5 ;
        RECT  42.384 215.916 42.408 216 ;
    END
  END s1b[17]
  PIN s1b[180]
    DIRECTION INPUT ;
    USE SIGNAL ;
    PORT
      LAYER M5 ;
        RECT  235.584 215.916 235.608 216 ;
    END
  END s1b[180]
  PIN s1b[181]
    DIRECTION INPUT ;
    USE SIGNAL ;
    PORT
      LAYER M5 ;
        RECT  236.784 215.916 236.808 216 ;
    END
  END s1b[181]
  PIN s1b[182]
    DIRECTION INPUT ;
    USE SIGNAL ;
    PORT
      LAYER M5 ;
        RECT  237.984 215.916 238.008 216 ;
    END
  END s1b[182]
  PIN s1b[183]
    DIRECTION INPUT ;
    USE SIGNAL ;
    PORT
      LAYER M5 ;
        RECT  239.136 215.916 239.16 216 ;
    END
  END s1b[183]
  PIN s1b[184]
    DIRECTION INPUT ;
    USE SIGNAL ;
    PORT
      LAYER M5 ;
        RECT  240.336 215.916 240.36 216 ;
    END
  END s1b[184]
  PIN s1b[185]
    DIRECTION INPUT ;
    USE SIGNAL ;
    PORT
      LAYER M5 ;
        RECT  241.536 215.916 241.56 216 ;
    END
  END s1b[185]
  PIN s1b[186]
    DIRECTION INPUT ;
    USE SIGNAL ;
    PORT
      LAYER M5 ;
        RECT  242.688 215.916 242.712 216 ;
    END
  END s1b[186]
  PIN s1b[187]
    DIRECTION INPUT ;
    USE SIGNAL ;
    PORT
      LAYER M5 ;
        RECT  243.888 215.916 243.912 216 ;
    END
  END s1b[187]
  PIN s1b[188]
    DIRECTION INPUT ;
    USE SIGNAL ;
    PORT
      LAYER M5 ;
        RECT  245.088 215.916 245.112 216 ;
    END
  END s1b[188]
  PIN s1b[189]
    DIRECTION INPUT ;
    USE SIGNAL ;
    PORT
      LAYER M5 ;
        RECT  246.24 215.916 246.264 216 ;
    END
  END s1b[189]
  PIN s1b[18]
    DIRECTION INPUT ;
    USE SIGNAL ;
    PORT
      LAYER M5 ;
        RECT  43.584 215.916 43.608 216 ;
    END
  END s1b[18]
  PIN s1b[190]
    DIRECTION INPUT ;
    USE SIGNAL ;
    PORT
      LAYER M5 ;
        RECT  247.44 215.916 247.464 216 ;
    END
  END s1b[190]
  PIN s1b[191]
    DIRECTION INPUT ;
    USE SIGNAL ;
    PORT
      LAYER M5 ;
        RECT  248.544 215.916 248.568 216 ;
    END
  END s1b[191]
  PIN s1b[192]
    DIRECTION INPUT ;
    USE SIGNAL ;
    PORT
      LAYER M5 ;
        RECT  249.84 215.916 249.864 216 ;
    END
  END s1b[192]
  PIN s1b[193]
    DIRECTION INPUT ;
    USE SIGNAL ;
    PORT
      LAYER M5 ;
        RECT  250.992 215.916 251.016 216 ;
    END
  END s1b[193]
  PIN s1b[194]
    DIRECTION INPUT ;
    USE SIGNAL ;
    PORT
      LAYER M5 ;
        RECT  252.192 215.916 252.216 216 ;
    END
  END s1b[194]
  PIN s1b[195]
    DIRECTION INPUT ;
    USE SIGNAL ;
    PORT
      LAYER M5 ;
        RECT  253.392 215.916 253.416 216 ;
    END
  END s1b[195]
  PIN s1b[196]
    DIRECTION INPUT ;
    USE SIGNAL ;
    PORT
      LAYER M5 ;
        RECT  254.544 215.916 254.568 216 ;
    END
  END s1b[196]
  PIN s1b[197]
    DIRECTION INPUT ;
    USE SIGNAL ;
    PORT
      LAYER M5 ;
        RECT  255.744 215.916 255.768 216 ;
    END
  END s1b[197]
  PIN s1b[198]
    DIRECTION INPUT ;
    USE SIGNAL ;
    PORT
      LAYER M5 ;
        RECT  256.944 215.916 256.968 216 ;
    END
  END s1b[198]
  PIN s1b[199]
    DIRECTION INPUT ;
    USE SIGNAL ;
    PORT
      LAYER M5 ;
        RECT  258.096 215.916 258.12 216 ;
    END
  END s1b[199]
  PIN s1b[19]
    DIRECTION INPUT ;
    USE SIGNAL ;
    PORT
      LAYER M5 ;
        RECT  44.736 215.916 44.76 216 ;
    END
  END s1b[19]
  PIN s1b[1]
    DIRECTION INPUT ;
    USE SIGNAL ;
    PORT
      LAYER M5 ;
        RECT  23.424 215.916 23.448 216 ;
    END
  END s1b[1]
  PIN s1b[200]
    DIRECTION INPUT ;
    USE SIGNAL ;
    PORT
      LAYER M5 ;
        RECT  259.2 215.916 259.224 216 ;
    END
  END s1b[200]
  PIN s1b[201]
    DIRECTION INPUT ;
    USE SIGNAL ;
    PORT
      LAYER M5 ;
        RECT  260.496 215.916 260.52 216 ;
    END
  END s1b[201]
  PIN s1b[202]
    DIRECTION INPUT ;
    USE SIGNAL ;
    PORT
      LAYER M5 ;
        RECT  261.696 215.916 261.72 216 ;
    END
  END s1b[202]
  PIN s1b[203]
    DIRECTION INPUT ;
    USE SIGNAL ;
    PORT
      LAYER M5 ;
        RECT  262.848 215.916 262.872 216 ;
    END
  END s1b[203]
  PIN s1b[204]
    DIRECTION INPUT ;
    USE SIGNAL ;
    PORT
      LAYER M5 ;
        RECT  264.048 215.916 264.072 216 ;
    END
  END s1b[204]
  PIN s1b[205]
    DIRECTION INPUT ;
    USE SIGNAL ;
    PORT
      LAYER M5 ;
        RECT  265.248 215.916 265.272 216 ;
    END
  END s1b[205]
  PIN s1b[206]
    DIRECTION INPUT ;
    USE SIGNAL ;
    PORT
      LAYER M5 ;
        RECT  266.4 215.916 266.424 216 ;
    END
  END s1b[206]
  PIN s1b[207]
    DIRECTION INPUT ;
    USE SIGNAL ;
    PORT
      LAYER M5 ;
        RECT  267.6 215.916 267.624 216 ;
    END
  END s1b[207]
  PIN s1b[208]
    DIRECTION INPUT ;
    USE SIGNAL ;
    PORT
      LAYER M5 ;
        RECT  268.8 215.916 268.824 216 ;
    END
  END s1b[208]
  PIN s1b[209]
    DIRECTION INPUT ;
    USE SIGNAL ;
    PORT
      LAYER M5 ;
        RECT  269.856 215.916 269.88 216 ;
    END
  END s1b[209]
  PIN s1b[20]
    DIRECTION INPUT ;
    USE SIGNAL ;
    PORT
      LAYER M5 ;
        RECT  45.936 215.916 45.96 216 ;
    END
  END s1b[20]
  PIN s1b[210]
    DIRECTION INPUT ;
    USE SIGNAL ;
    PORT
      LAYER M5 ;
        RECT  271.152 215.916 271.176 216 ;
    END
  END s1b[210]
  PIN s1b[211]
    DIRECTION INPUT ;
    USE SIGNAL ;
    PORT
      LAYER M5 ;
        RECT  272.352 215.916 272.376 216 ;
    END
  END s1b[211]
  PIN s1b[212]
    DIRECTION INPUT ;
    USE SIGNAL ;
    PORT
      LAYER M5 ;
        RECT  273.504 215.916 273.528 216 ;
    END
  END s1b[212]
  PIN s1b[213]
    DIRECTION INPUT ;
    USE SIGNAL ;
    PORT
      LAYER M5 ;
        RECT  274.704 215.916 274.728 216 ;
    END
  END s1b[213]
  PIN s1b[214]
    DIRECTION INPUT ;
    USE SIGNAL ;
    PORT
      LAYER M5 ;
        RECT  275.904 215.916 275.928 216 ;
    END
  END s1b[214]
  PIN s1b[215]
    DIRECTION INPUT ;
    USE SIGNAL ;
    PORT
      LAYER M5 ;
        RECT  277.104 215.916 277.128 216 ;
    END
  END s1b[215]
  PIN s1b[216]
    DIRECTION INPUT ;
    USE SIGNAL ;
    PORT
      LAYER M5 ;
        RECT  278.256 215.916 278.28 216 ;
    END
  END s1b[216]
  PIN s1b[217]
    DIRECTION INPUT ;
    USE SIGNAL ;
    PORT
      LAYER M5 ;
        RECT  279.456 215.916 279.48 216 ;
    END
  END s1b[217]
  PIN s1b[218]
    DIRECTION INPUT ;
    USE SIGNAL ;
    PORT
      LAYER M5 ;
        RECT  280.656 215.916 280.68 216 ;
    END
  END s1b[218]
  PIN s1b[219]
    DIRECTION INPUT ;
    USE SIGNAL ;
    PORT
      LAYER M5 ;
        RECT  281.808 215.916 281.832 216 ;
    END
  END s1b[219]
  PIN s1b[21]
    DIRECTION INPUT ;
    USE SIGNAL ;
    PORT
      LAYER M5 ;
        RECT  47.136 215.916 47.16 216 ;
    END
  END s1b[21]
  PIN s1b[220]
    DIRECTION INPUT ;
    USE SIGNAL ;
    PORT
      LAYER M5 ;
        RECT  283.008 215.916 283.032 216 ;
    END
  END s1b[220]
  PIN s1b[221]
    DIRECTION INPUT ;
    USE SIGNAL ;
    PORT
      LAYER M5 ;
        RECT  284.208 215.916 284.232 216 ;
    END
  END s1b[221]
  PIN s1b[222]
    DIRECTION INPUT ;
    USE SIGNAL ;
    PORT
      LAYER M5 ;
        RECT  285.36 215.916 285.384 216 ;
    END
  END s1b[222]
  PIN s1b[223]
    DIRECTION INPUT ;
    USE SIGNAL ;
    PORT
      LAYER M5 ;
        RECT  286.56 215.916 286.584 216 ;
    END
  END s1b[223]
  PIN s1b[224]
    DIRECTION INPUT ;
    USE SIGNAL ;
    PORT
      LAYER M5 ;
        RECT  287.76 215.916 287.784 216 ;
    END
  END s1b[224]
  PIN s1b[225]
    DIRECTION INPUT ;
    USE SIGNAL ;
    PORT
      LAYER M5 ;
        RECT  288.96 215.916 288.984 216 ;
    END
  END s1b[225]
  PIN s1b[226]
    DIRECTION INPUT ;
    USE SIGNAL ;
    PORT
      LAYER M5 ;
        RECT  290.112 215.916 290.136 216 ;
    END
  END s1b[226]
  PIN s1b[227]
    DIRECTION INPUT ;
    USE SIGNAL ;
    PORT
      LAYER M5 ;
        RECT  291.312 215.916 291.336 216 ;
    END
  END s1b[227]
  PIN s1b[228]
    DIRECTION INPUT ;
    USE SIGNAL ;
    PORT
      LAYER M5 ;
        RECT  292.512 215.916 292.536 216 ;
    END
  END s1b[228]
  PIN s1b[229]
    DIRECTION INPUT ;
    USE SIGNAL ;
    PORT
      LAYER M5 ;
        RECT  293.664 215.916 293.688 216 ;
    END
  END s1b[229]
  PIN s1b[22]
    DIRECTION INPUT ;
    USE SIGNAL ;
    PORT
      LAYER M5 ;
        RECT  48.288 215.916 48.312 216 ;
    END
  END s1b[22]
  PIN s1b[230]
    DIRECTION INPUT ;
    USE SIGNAL ;
    PORT
      LAYER M5 ;
        RECT  294.864 215.916 294.888 216 ;
    END
  END s1b[230]
  PIN s1b[231]
    DIRECTION INPUT ;
    USE SIGNAL ;
    PORT
      LAYER M5 ;
        RECT  296.064 215.916 296.088 216 ;
    END
  END s1b[231]
  PIN s1b[232]
    DIRECTION INPUT ;
    USE SIGNAL ;
    PORT
      LAYER M5 ;
        RECT  297.216 215.916 297.24 216 ;
    END
  END s1b[232]
  PIN s1b[233]
    DIRECTION INPUT ;
    USE SIGNAL ;
    PORT
      LAYER M5 ;
        RECT  298.416 215.916 298.44 216 ;
    END
  END s1b[233]
  PIN s1b[234]
    DIRECTION INPUT ;
    USE SIGNAL ;
    PORT
      LAYER M5 ;
        RECT  299.616 215.916 299.64 216 ;
    END
  END s1b[234]
  PIN s1b[235]
    DIRECTION INPUT ;
    USE SIGNAL ;
    PORT
      LAYER M5 ;
        RECT  300.768 215.916 300.792 216 ;
    END
  END s1b[235]
  PIN s1b[236]
    DIRECTION INPUT ;
    USE SIGNAL ;
    PORT
      LAYER M5 ;
        RECT  301.968 215.916 301.992 216 ;
    END
  END s1b[236]
  PIN s1b[237]
    DIRECTION INPUT ;
    USE SIGNAL ;
    PORT
      LAYER M5 ;
        RECT  303.168 215.916 303.192 216 ;
    END
  END s1b[237]
  PIN s1b[238]
    DIRECTION INPUT ;
    USE SIGNAL ;
    PORT
      LAYER M5 ;
        RECT  304.368 215.916 304.392 216 ;
    END
  END s1b[238]
  PIN s1b[239]
    DIRECTION INPUT ;
    USE SIGNAL ;
    PORT
      LAYER M5 ;
        RECT  305.52 215.916 305.544 216 ;
    END
  END s1b[239]
  PIN s1b[23]
    DIRECTION INPUT ;
    USE SIGNAL ;
    PORT
      LAYER M5 ;
        RECT  49.488 215.916 49.512 216 ;
    END
  END s1b[23]
  PIN s1b[240]
    DIRECTION INPUT ;
    USE SIGNAL ;
    PORT
      LAYER M5 ;
        RECT  306.72 215.916 306.744 216 ;
    END
  END s1b[240]
  PIN s1b[241]
    DIRECTION INPUT ;
    USE SIGNAL ;
    PORT
      LAYER M5 ;
        RECT  307.824 215.916 307.848 216 ;
    END
  END s1b[241]
  PIN s1b[242]
    DIRECTION INPUT ;
    USE SIGNAL ;
    PORT
      LAYER M5 ;
        RECT  309.072 215.916 309.096 216 ;
    END
  END s1b[242]
  PIN s1b[243]
    DIRECTION INPUT ;
    USE SIGNAL ;
    PORT
      LAYER M5 ;
        RECT  310.272 215.916 310.296 216 ;
    END
  END s1b[243]
  PIN s1b[244]
    DIRECTION INPUT ;
    USE SIGNAL ;
    PORT
      LAYER M5 ;
        RECT  311.472 215.916 311.496 216 ;
    END
  END s1b[244]
  PIN s1b[245]
    DIRECTION INPUT ;
    USE SIGNAL ;
    PORT
      LAYER M5 ;
        RECT  312.624 215.916 312.648 216 ;
    END
  END s1b[245]
  PIN s1b[246]
    DIRECTION INPUT ;
    USE SIGNAL ;
    PORT
      LAYER M5 ;
        RECT  313.824 215.916 313.848 216 ;
    END
  END s1b[246]
  PIN s1b[247]
    DIRECTION INPUT ;
    USE SIGNAL ;
    PORT
      LAYER M5 ;
        RECT  315.024 215.916 315.048 216 ;
    END
  END s1b[247]
  PIN s1b[248]
    DIRECTION INPUT ;
    USE SIGNAL ;
    PORT
      LAYER M5 ;
        RECT  316.176 215.916 316.2 216 ;
    END
  END s1b[248]
  PIN s1b[249]
    DIRECTION INPUT ;
    USE SIGNAL ;
    PORT
      LAYER M5 ;
        RECT  317.376 215.916 317.4 216 ;
    END
  END s1b[249]
  PIN s1b[24]
    DIRECTION INPUT ;
    USE SIGNAL ;
    PORT
      LAYER M5 ;
        RECT  50.688 215.916 50.712 216 ;
    END
  END s1b[24]
  PIN s1b[250]
    DIRECTION INPUT ;
    USE SIGNAL ;
    PORT
      LAYER M5 ;
        RECT  318.48 215.916 318.504 216 ;
    END
  END s1b[250]
  PIN s1b[251]
    DIRECTION INPUT ;
    USE SIGNAL ;
    PORT
      LAYER M5 ;
        RECT  319.776 215.916 319.8 216 ;
    END
  END s1b[251]
  PIN s1b[252]
    DIRECTION INPUT ;
    USE SIGNAL ;
    PORT
      LAYER M5 ;
        RECT  320.928 215.916 320.952 216 ;
    END
  END s1b[252]
  PIN s1b[253]
    DIRECTION INPUT ;
    USE SIGNAL ;
    PORT
      LAYER M5 ;
        RECT  322.128 215.916 322.152 216 ;
    END
  END s1b[253]
  PIN s1b[254]
    DIRECTION INPUT ;
    USE SIGNAL ;
    PORT
      LAYER M5 ;
        RECT  323.328 215.916 323.352 216 ;
    END
  END s1b[254]
  PIN s1b[255]
    DIRECTION INPUT ;
    USE SIGNAL ;
    PORT
      LAYER M5 ;
        RECT  324.48 215.916 324.504 216 ;
    END
  END s1b[255]
  PIN s1b[256]
    DIRECTION INPUT ;
    USE SIGNAL ;
    PORT
      LAYER M5 ;
        RECT  325.68 215.916 325.704 216 ;
    END
  END s1b[256]
  PIN s1b[257]
    DIRECTION INPUT ;
    USE SIGNAL ;
    PORT
      LAYER M5 ;
        RECT  326.88 215.916 326.904 216 ;
    END
  END s1b[257]
  PIN s1b[258]
    DIRECTION INPUT ;
    USE SIGNAL ;
    PORT
      LAYER M5 ;
        RECT  328.032 215.916 328.056 216 ;
    END
  END s1b[258]
  PIN s1b[259]
    DIRECTION INPUT ;
    USE SIGNAL ;
    PORT
      LAYER M5 ;
        RECT  329.232 215.916 329.256 216 ;
    END
  END s1b[259]
  PIN s1b[25]
    DIRECTION INPUT ;
    USE SIGNAL ;
    PORT
      LAYER M5 ;
        RECT  51.84 215.916 51.864 216 ;
    END
  END s1b[25]
  PIN s1b[260]
    DIRECTION INPUT ;
    USE SIGNAL ;
    PORT
      LAYER M5 ;
        RECT  330.432 215.916 330.456 216 ;
    END
  END s1b[260]
  PIN s1b[261]
    DIRECTION INPUT ;
    USE SIGNAL ;
    PORT
      LAYER M5 ;
        RECT  331.632 215.916 331.656 216 ;
    END
  END s1b[261]
  PIN s1b[262]
    DIRECTION INPUT ;
    USE SIGNAL ;
    PORT
      LAYER M5 ;
        RECT  332.784 215.916 332.808 216 ;
    END
  END s1b[262]
  PIN s1b[263]
    DIRECTION INPUT ;
    USE SIGNAL ;
    PORT
      LAYER M5 ;
        RECT  333.984 215.916 334.008 216 ;
    END
  END s1b[263]
  PIN s1b[264]
    DIRECTION INPUT ;
    USE SIGNAL ;
    PORT
      LAYER M5 ;
        RECT  335.184 215.916 335.208 216 ;
    END
  END s1b[264]
  PIN s1b[265]
    DIRECTION INPUT ;
    USE SIGNAL ;
    PORT
      LAYER M5 ;
        RECT  336.336 215.916 336.36 216 ;
    END
  END s1b[265]
  PIN s1b[266]
    DIRECTION INPUT ;
    USE SIGNAL ;
    PORT
      LAYER M5 ;
        RECT  337.536 215.916 337.56 216 ;
    END
  END s1b[266]
  PIN s1b[267]
    DIRECTION INPUT ;
    USE SIGNAL ;
    PORT
      LAYER M5 ;
        RECT  338.736 215.916 338.76 216 ;
    END
  END s1b[267]
  PIN s1b[268]
    DIRECTION INPUT ;
    USE SIGNAL ;
    PORT
      LAYER M5 ;
        RECT  339.888 215.916 339.912 216 ;
    END
  END s1b[268]
  PIN s1b[269]
    DIRECTION INPUT ;
    USE SIGNAL ;
    PORT
      LAYER M5 ;
        RECT  341.088 215.916 341.112 216 ;
    END
  END s1b[269]
  PIN s1b[26]
    DIRECTION INPUT ;
    USE SIGNAL ;
    PORT
      LAYER M5 ;
        RECT  53.04 215.916 53.064 216 ;
    END
  END s1b[26]
  PIN s1b[270]
    DIRECTION INPUT ;
    USE SIGNAL ;
    PORT
      LAYER M5 ;
        RECT  342.288 215.916 342.312 216 ;
    END
  END s1b[270]
  PIN s1b[271]
    DIRECTION INPUT ;
    USE SIGNAL ;
    PORT
      LAYER M5 ;
        RECT  343.44 215.916 343.464 216 ;
    END
  END s1b[271]
  PIN s1b[272]
    DIRECTION INPUT ;
    USE SIGNAL ;
    PORT
      LAYER M5 ;
        RECT  344.64 215.916 344.664 216 ;
    END
  END s1b[272]
  PIN s1b[273]
    DIRECTION INPUT ;
    USE SIGNAL ;
    PORT
      LAYER M5 ;
        RECT  345.744 215.916 345.768 216 ;
    END
  END s1b[273]
  PIN s1b[274]
    DIRECTION INPUT ;
    USE SIGNAL ;
    PORT
      LAYER M5 ;
        RECT  347.04 215.916 347.064 216 ;
    END
  END s1b[274]
  PIN s1b[275]
    DIRECTION INPUT ;
    USE SIGNAL ;
    PORT
      LAYER M5 ;
        RECT  348.192 215.916 348.216 216 ;
    END
  END s1b[275]
  PIN s1b[276]
    DIRECTION INPUT ;
    USE SIGNAL ;
    PORT
      LAYER M5 ;
        RECT  349.392 215.916 349.416 216 ;
    END
  END s1b[276]
  PIN s1b[277]
    DIRECTION INPUT ;
    USE SIGNAL ;
    PORT
      LAYER M5 ;
        RECT  350.592 215.916 350.616 216 ;
    END
  END s1b[277]
  PIN s1b[278]
    DIRECTION INPUT ;
    USE SIGNAL ;
    PORT
      LAYER M5 ;
        RECT  351.744 215.916 351.768 216 ;
    END
  END s1b[278]
  PIN s1b[279]
    DIRECTION INPUT ;
    USE SIGNAL ;
    PORT
      LAYER M5 ;
        RECT  352.944 215.916 352.968 216 ;
    END
  END s1b[279]
  PIN s1b[27]
    DIRECTION INPUT ;
    USE SIGNAL ;
    PORT
      LAYER M5 ;
        RECT  54.144 215.916 54.168 216 ;
    END
  END s1b[27]
  PIN s1b[280]
    DIRECTION INPUT ;
    USE SIGNAL ;
    PORT
      LAYER M5 ;
        RECT  354.144 215.916 354.168 216 ;
    END
  END s1b[280]
  PIN s1b[281]
    DIRECTION INPUT ;
    USE SIGNAL ;
    PORT
      LAYER M5 ;
        RECT  355.296 215.916 355.32 216 ;
    END
  END s1b[281]
  PIN s1b[282]
    DIRECTION INPUT ;
    USE SIGNAL ;
    PORT
      LAYER M5 ;
        RECT  356.4 215.916 356.424 216 ;
    END
  END s1b[282]
  PIN s1b[283]
    DIRECTION INPUT ;
    USE SIGNAL ;
    PORT
      LAYER M5 ;
        RECT  357.696 215.916 357.72 216 ;
    END
  END s1b[283]
  PIN s1b[284]
    DIRECTION INPUT ;
    USE SIGNAL ;
    PORT
      LAYER M5 ;
        RECT  358.896 215.916 358.92 216 ;
    END
  END s1b[284]
  PIN s1b[285]
    DIRECTION INPUT ;
    USE SIGNAL ;
    PORT
      LAYER M5 ;
        RECT  360.048 215.916 360.072 216 ;
    END
  END s1b[285]
  PIN s1b[286]
    DIRECTION INPUT ;
    USE SIGNAL ;
    PORT
      LAYER M5 ;
        RECT  361.248 215.916 361.272 216 ;
    END
  END s1b[286]
  PIN s1b[287]
    DIRECTION INPUT ;
    USE SIGNAL ;
    PORT
      LAYER M5 ;
        RECT  362.448 215.916 362.472 216 ;
    END
  END s1b[287]
  PIN s1b[288]
    DIRECTION INPUT ;
    USE SIGNAL ;
    PORT
      LAYER M5 ;
        RECT  363.6 215.916 363.624 216 ;
    END
  END s1b[288]
  PIN s1b[289]
    DIRECTION INPUT ;
    USE SIGNAL ;
    PORT
      LAYER M5 ;
        RECT  364.8 215.916 364.824 216 ;
    END
  END s1b[289]
  PIN s1b[28]
    DIRECTION INPUT ;
    USE SIGNAL ;
    PORT
      LAYER M5 ;
        RECT  55.44 215.916 55.464 216 ;
    END
  END s1b[28]
  PIN s1b[290]
    DIRECTION INPUT ;
    USE SIGNAL ;
    PORT
      LAYER M5 ;
        RECT  366 215.916 366.024 216 ;
    END
  END s1b[290]
  PIN s1b[291]
    DIRECTION INPUT ;
    USE SIGNAL ;
    PORT
      LAYER M5 ;
        RECT  367.056 215.916 367.08 216 ;
    END
  END s1b[291]
  PIN s1b[292]
    DIRECTION INPUT ;
    USE SIGNAL ;
    PORT
      LAYER M5 ;
        RECT  368.352 215.916 368.376 216 ;
    END
  END s1b[292]
  PIN s1b[293]
    DIRECTION INPUT ;
    USE SIGNAL ;
    PORT
      LAYER M5 ;
        RECT  369.552 215.916 369.576 216 ;
    END
  END s1b[293]
  PIN s1b[294]
    DIRECTION INPUT ;
    USE SIGNAL ;
    PORT
      LAYER M5 ;
        RECT  370.704 215.916 370.728 216 ;
    END
  END s1b[294]
  PIN s1b[295]
    DIRECTION INPUT ;
    USE SIGNAL ;
    PORT
      LAYER M5 ;
        RECT  371.904 215.916 371.928 216 ;
    END
  END s1b[295]
  PIN s1b[296]
    DIRECTION INPUT ;
    USE SIGNAL ;
    PORT
      LAYER M5 ;
        RECT  373.104 215.916 373.128 216 ;
    END
  END s1b[296]
  PIN s1b[297]
    DIRECTION INPUT ;
    USE SIGNAL ;
    PORT
      LAYER M5 ;
        RECT  374.304 215.916 374.328 216 ;
    END
  END s1b[297]
  PIN s1b[298]
    DIRECTION INPUT ;
    USE SIGNAL ;
    PORT
      LAYER M5 ;
        RECT  375.456 215.916 375.48 216 ;
    END
  END s1b[298]
  PIN s1b[299]
    DIRECTION INPUT ;
    USE SIGNAL ;
    PORT
      LAYER M5 ;
        RECT  376.656 215.916 376.68 216 ;
    END
  END s1b[299]
  PIN s1b[29]
    DIRECTION INPUT ;
    USE SIGNAL ;
    PORT
      LAYER M5 ;
        RECT  56.592 215.916 56.616 216 ;
    END
  END s1b[29]
  PIN s1b[2]
    DIRECTION INPUT ;
    USE SIGNAL ;
    PORT
      LAYER M5 ;
        RECT  24.576 215.916 24.6 216 ;
    END
  END s1b[2]
  PIN s1b[300]
    DIRECTION INPUT ;
    USE SIGNAL ;
    PORT
      LAYER M5 ;
        RECT  377.856 215.916 377.88 216 ;
    END
  END s1b[300]
  PIN s1b[301]
    DIRECTION INPUT ;
    USE SIGNAL ;
    PORT
      LAYER M5 ;
        RECT  379.008 215.916 379.032 216 ;
    END
  END s1b[301]
  PIN s1b[302]
    DIRECTION INPUT ;
    USE SIGNAL ;
    PORT
      LAYER M5 ;
        RECT  380.208 215.916 380.232 216 ;
    END
  END s1b[302]
  PIN s1b[303]
    DIRECTION INPUT ;
    USE SIGNAL ;
    PORT
      LAYER M5 ;
        RECT  381.408 215.916 381.432 216 ;
    END
  END s1b[303]
  PIN s1b[304]
    DIRECTION INPUT ;
    USE SIGNAL ;
    PORT
      LAYER M5 ;
        RECT  382.56 215.916 382.584 216 ;
    END
  END s1b[304]
  PIN s1b[305]
    DIRECTION INPUT ;
    USE SIGNAL ;
    PORT
      LAYER M5 ;
        RECT  383.76 215.916 383.784 216 ;
    END
  END s1b[305]
  PIN s1b[306]
    DIRECTION INPUT ;
    USE SIGNAL ;
    PORT
      LAYER M5 ;
        RECT  384.96 215.916 384.984 216 ;
    END
  END s1b[306]
  PIN s1b[307]
    DIRECTION INPUT ;
    USE SIGNAL ;
    PORT
      LAYER M5 ;
        RECT  386.16 215.916 386.184 216 ;
    END
  END s1b[307]
  PIN s1b[308]
    DIRECTION INPUT ;
    USE SIGNAL ;
    PORT
      LAYER M5 ;
        RECT  387.312 215.916 387.336 216 ;
    END
  END s1b[308]
  PIN s1b[309]
    DIRECTION INPUT ;
    USE SIGNAL ;
    PORT
      LAYER M5 ;
        RECT  388.512 215.916 388.536 216 ;
    END
  END s1b[309]
  PIN s1b[30]
    DIRECTION INPUT ;
    USE SIGNAL ;
    PORT
      LAYER M5 ;
        RECT  57.792 215.916 57.816 216 ;
    END
  END s1b[30]
  PIN s1b[310]
    DIRECTION INPUT ;
    USE SIGNAL ;
    PORT
      LAYER M5 ;
        RECT  389.712 215.916 389.736 216 ;
    END
  END s1b[310]
  PIN s1b[311]
    DIRECTION INPUT ;
    USE SIGNAL ;
    PORT
      LAYER M5 ;
        RECT  390.864 215.916 390.888 216 ;
    END
  END s1b[311]
  PIN s1b[312]
    DIRECTION INPUT ;
    USE SIGNAL ;
    PORT
      LAYER M5 ;
        RECT  392.064 215.916 392.088 216 ;
    END
  END s1b[312]
  PIN s1b[313]
    DIRECTION INPUT ;
    USE SIGNAL ;
    PORT
      LAYER M5 ;
        RECT  393.264 215.916 393.288 216 ;
    END
  END s1b[313]
  PIN s1b[314]
    DIRECTION INPUT ;
    USE SIGNAL ;
    PORT
      LAYER M5 ;
        RECT  394.416 215.916 394.44 216 ;
    END
  END s1b[314]
  PIN s1b[315]
    DIRECTION INPUT ;
    USE SIGNAL ;
    PORT
      LAYER M5 ;
        RECT  395.616 215.916 395.64 216 ;
    END
  END s1b[315]
  PIN s1b[316]
    DIRECTION INPUT ;
    USE SIGNAL ;
    PORT
      LAYER M5 ;
        RECT  396.816 215.916 396.84 216 ;
    END
  END s1b[316]
  PIN s1b[317]
    DIRECTION INPUT ;
    USE SIGNAL ;
    PORT
      LAYER M5 ;
        RECT  397.968 215.916 397.992 216 ;
    END
  END s1b[317]
  PIN s1b[318]
    DIRECTION INPUT ;
    USE SIGNAL ;
    PORT
      LAYER M5 ;
        RECT  399.168 215.916 399.192 216 ;
    END
  END s1b[318]
  PIN s1b[319]
    DIRECTION INPUT ;
    USE SIGNAL ;
    PORT
      LAYER M5 ;
        RECT  400.368 215.916 400.392 216 ;
    END
  END s1b[319]
  PIN s1b[31]
    DIRECTION INPUT ;
    USE SIGNAL ;
    PORT
      LAYER M5 ;
        RECT  58.992 215.916 59.016 216 ;
    END
  END s1b[31]
  PIN s1b[320]
    DIRECTION INPUT ;
    USE SIGNAL ;
    PORT
      LAYER M5 ;
        RECT  401.568 215.916 401.592 216 ;
    END
  END s1b[320]
  PIN s1b[321]
    DIRECTION INPUT ;
    USE SIGNAL ;
    PORT
      LAYER M5 ;
        RECT  402.72 215.916 402.744 216 ;
    END
  END s1b[321]
  PIN s1b[322]
    DIRECTION INPUT ;
    USE SIGNAL ;
    PORT
      LAYER M5 ;
        RECT  403.92 215.916 403.944 216 ;
    END
  END s1b[322]
  PIN s1b[323]
    DIRECTION INPUT ;
    USE SIGNAL ;
    PORT
      LAYER M5 ;
        RECT  405.024 215.916 405.048 216 ;
    END
  END s1b[323]
  PIN s1b[324]
    DIRECTION INPUT ;
    USE SIGNAL ;
    PORT
      LAYER M5 ;
        RECT  406.272 215.916 406.296 216 ;
    END
  END s1b[324]
  PIN s1b[325]
    DIRECTION INPUT ;
    USE SIGNAL ;
    PORT
      LAYER M5 ;
        RECT  407.472 215.916 407.496 216 ;
    END
  END s1b[325]
  PIN s1b[326]
    DIRECTION INPUT ;
    USE SIGNAL ;
    PORT
      LAYER M5 ;
        RECT  408.672 215.916 408.696 216 ;
    END
  END s1b[326]
  PIN s1b[327]
    DIRECTION INPUT ;
    USE SIGNAL ;
    PORT
      LAYER M5 ;
        RECT  409.824 215.916 409.848 216 ;
    END
  END s1b[327]
  PIN s1b[32]
    DIRECTION INPUT ;
    USE SIGNAL ;
    PORT
      LAYER M5 ;
        RECT  60.144 215.916 60.168 216 ;
    END
  END s1b[32]
  PIN s1b[33]
    DIRECTION INPUT ;
    USE SIGNAL ;
    PORT
      LAYER M5 ;
        RECT  61.344 215.916 61.368 216 ;
    END
  END s1b[33]
  PIN s1b[34]
    DIRECTION INPUT ;
    USE SIGNAL ;
    PORT
      LAYER M5 ;
        RECT  62.544 215.916 62.568 216 ;
    END
  END s1b[34]
  PIN s1b[35]
    DIRECTION INPUT ;
    USE SIGNAL ;
    PORT
      LAYER M5 ;
        RECT  63.696 215.916 63.72 216 ;
    END
  END s1b[35]
  PIN s1b[36]
    DIRECTION INPUT ;
    USE SIGNAL ;
    PORT
      LAYER M5 ;
        RECT  64.8 215.916 64.824 216 ;
    END
  END s1b[36]
  PIN s1b[37]
    DIRECTION INPUT ;
    USE SIGNAL ;
    PORT
      LAYER M5 ;
        RECT  66.096 215.916 66.12 216 ;
    END
  END s1b[37]
  PIN s1b[38]
    DIRECTION INPUT ;
    USE SIGNAL ;
    PORT
      LAYER M5 ;
        RECT  67.296 215.916 67.32 216 ;
    END
  END s1b[38]
  PIN s1b[39]
    DIRECTION INPUT ;
    USE SIGNAL ;
    PORT
      LAYER M5 ;
        RECT  68.448 215.916 68.472 216 ;
    END
  END s1b[39]
  PIN s1b[3]
    DIRECTION INPUT ;
    USE SIGNAL ;
    PORT
      LAYER M5 ;
        RECT  25.776 215.916 25.8 216 ;
    END
  END s1b[3]
  PIN s1b[40]
    DIRECTION INPUT ;
    USE SIGNAL ;
    PORT
      LAYER M5 ;
        RECT  69.648 215.916 69.672 216 ;
    END
  END s1b[40]
  PIN s1b[41]
    DIRECTION INPUT ;
    USE SIGNAL ;
    PORT
      LAYER M5 ;
        RECT  70.848 215.916 70.872 216 ;
    END
  END s1b[41]
  PIN s1b[42]
    DIRECTION INPUT ;
    USE SIGNAL ;
    PORT
      LAYER M5 ;
        RECT  72 215.916 72.024 216 ;
    END
  END s1b[42]
  PIN s1b[43]
    DIRECTION INPUT ;
    USE SIGNAL ;
    PORT
      LAYER M5 ;
        RECT  73.2 215.916 73.224 216 ;
    END
  END s1b[43]
  PIN s1b[44]
    DIRECTION INPUT ;
    USE SIGNAL ;
    PORT
      LAYER M5 ;
        RECT  74.4 215.916 74.424 216 ;
    END
  END s1b[44]
  PIN s1b[45]
    DIRECTION INPUT ;
    USE SIGNAL ;
    PORT
      LAYER M5 ;
        RECT  75.456 215.916 75.48 216 ;
    END
  END s1b[45]
  PIN s1b[46]
    DIRECTION INPUT ;
    USE SIGNAL ;
    PORT
      LAYER M5 ;
        RECT  76.752 215.916 76.776 216 ;
    END
  END s1b[46]
  PIN s1b[47]
    DIRECTION INPUT ;
    USE SIGNAL ;
    PORT
      LAYER M5 ;
        RECT  77.952 215.916 77.976 216 ;
    END
  END s1b[47]
  PIN s1b[48]
    DIRECTION INPUT ;
    USE SIGNAL ;
    PORT
      LAYER M5 ;
        RECT  79.104 215.916 79.128 216 ;
    END
  END s1b[48]
  PIN s1b[49]
    DIRECTION INPUT ;
    USE SIGNAL ;
    PORT
      LAYER M5 ;
        RECT  80.304 215.916 80.328 216 ;
    END
  END s1b[49]
  PIN s1b[4]
    DIRECTION INPUT ;
    USE SIGNAL ;
    PORT
      LAYER M5 ;
        RECT  26.88 215.916 26.904 216 ;
    END
  END s1b[4]
  PIN s1b[50]
    DIRECTION INPUT ;
    USE SIGNAL ;
    PORT
      LAYER M5 ;
        RECT  81.504 215.916 81.528 216 ;
    END
  END s1b[50]
  PIN s1b[51]
    DIRECTION INPUT ;
    USE SIGNAL ;
    PORT
      LAYER M5 ;
        RECT  82.704 215.916 82.728 216 ;
    END
  END s1b[51]
  PIN s1b[52]
    DIRECTION INPUT ;
    USE SIGNAL ;
    PORT
      LAYER M5 ;
        RECT  83.856 215.916 83.88 216 ;
    END
  END s1b[52]
  PIN s1b[53]
    DIRECTION INPUT ;
    USE SIGNAL ;
    PORT
      LAYER M5 ;
        RECT  85.056 215.916 85.08 216 ;
    END
  END s1b[53]
  PIN s1b[54]
    DIRECTION INPUT ;
    USE SIGNAL ;
    PORT
      LAYER M5 ;
        RECT  86.256 215.916 86.28 216 ;
    END
  END s1b[54]
  PIN s1b[55]
    DIRECTION INPUT ;
    USE SIGNAL ;
    PORT
      LAYER M5 ;
        RECT  87.408 215.916 87.432 216 ;
    END
  END s1b[55]
  PIN s1b[56]
    DIRECTION INPUT ;
    USE SIGNAL ;
    PORT
      LAYER M5 ;
        RECT  88.608 215.916 88.632 216 ;
    END
  END s1b[56]
  PIN s1b[57]
    DIRECTION INPUT ;
    USE SIGNAL ;
    PORT
      LAYER M5 ;
        RECT  89.808 215.916 89.832 216 ;
    END
  END s1b[57]
  PIN s1b[58]
    DIRECTION INPUT ;
    USE SIGNAL ;
    PORT
      LAYER M5 ;
        RECT  90.96 215.916 90.984 216 ;
    END
  END s1b[58]
  PIN s1b[59]
    DIRECTION INPUT ;
    USE SIGNAL ;
    PORT
      LAYER M5 ;
        RECT  92.16 215.916 92.184 216 ;
    END
  END s1b[59]
  PIN s1b[5]
    DIRECTION INPUT ;
    USE SIGNAL ;
    PORT
      LAYER M5 ;
        RECT  28.176 215.916 28.2 216 ;
    END
  END s1b[5]
  PIN s1b[60]
    DIRECTION INPUT ;
    USE SIGNAL ;
    PORT
      LAYER M5 ;
        RECT  93.36 215.916 93.384 216 ;
    END
  END s1b[60]
  PIN s1b[61]
    DIRECTION INPUT ;
    USE SIGNAL ;
    PORT
      LAYER M5 ;
        RECT  94.56 215.916 94.584 216 ;
    END
  END s1b[61]
  PIN s1b[62]
    DIRECTION INPUT ;
    USE SIGNAL ;
    PORT
      LAYER M5 ;
        RECT  95.712 215.916 95.736 216 ;
    END
  END s1b[62]
  PIN s1b[63]
    DIRECTION INPUT ;
    USE SIGNAL ;
    PORT
      LAYER M5 ;
        RECT  96.912 215.916 96.936 216 ;
    END
  END s1b[63]
  PIN s1b[64]
    DIRECTION INPUT ;
    USE SIGNAL ;
    PORT
      LAYER M5 ;
        RECT  98.112 215.916 98.136 216 ;
    END
  END s1b[64]
  PIN s1b[65]
    DIRECTION INPUT ;
    USE SIGNAL ;
    PORT
      LAYER M5 ;
        RECT  99.264 215.916 99.288 216 ;
    END
  END s1b[65]
  PIN s1b[66]
    DIRECTION INPUT ;
    USE SIGNAL ;
    PORT
      LAYER M5 ;
        RECT  100.464 215.916 100.488 216 ;
    END
  END s1b[66]
  PIN s1b[67]
    DIRECTION INPUT ;
    USE SIGNAL ;
    PORT
      LAYER M5 ;
        RECT  101.664 215.916 101.688 216 ;
    END
  END s1b[67]
  PIN s1b[68]
    DIRECTION INPUT ;
    USE SIGNAL ;
    PORT
      LAYER M5 ;
        RECT  102.816 215.916 102.84 216 ;
    END
  END s1b[68]
  PIN s1b[69]
    DIRECTION INPUT ;
    USE SIGNAL ;
    PORT
      LAYER M5 ;
        RECT  104.016 215.916 104.04 216 ;
    END
  END s1b[69]
  PIN s1b[6]
    DIRECTION INPUT ;
    USE SIGNAL ;
    PORT
      LAYER M5 ;
        RECT  29.328 215.916 29.352 216 ;
    END
  END s1b[6]
  PIN s1b[70]
    DIRECTION INPUT ;
    USE SIGNAL ;
    PORT
      LAYER M5 ;
        RECT  105.216 215.916 105.24 216 ;
    END
  END s1b[70]
  PIN s1b[71]
    DIRECTION INPUT ;
    USE SIGNAL ;
    PORT
      LAYER M5 ;
        RECT  106.368 215.916 106.392 216 ;
    END
  END s1b[71]
  PIN s1b[72]
    DIRECTION INPUT ;
    USE SIGNAL ;
    PORT
      LAYER M5 ;
        RECT  107.568 215.916 107.592 216 ;
    END
  END s1b[72]
  PIN s1b[73]
    DIRECTION INPUT ;
    USE SIGNAL ;
    PORT
      LAYER M5 ;
        RECT  108.768 215.916 108.792 216 ;
    END
  END s1b[73]
  PIN s1b[74]
    DIRECTION INPUT ;
    USE SIGNAL ;
    PORT
      LAYER M5 ;
        RECT  109.968 215.916 109.992 216 ;
    END
  END s1b[74]
  PIN s1b[75]
    DIRECTION INPUT ;
    USE SIGNAL ;
    PORT
      LAYER M5 ;
        RECT  111.12 215.916 111.144 216 ;
    END
  END s1b[75]
  PIN s1b[76]
    DIRECTION INPUT ;
    USE SIGNAL ;
    PORT
      LAYER M5 ;
        RECT  112.32 215.916 112.344 216 ;
    END
  END s1b[76]
  PIN s1b[77]
    DIRECTION INPUT ;
    USE SIGNAL ;
    PORT
      LAYER M5 ;
        RECT  113.424 215.916 113.448 216 ;
    END
  END s1b[77]
  PIN s1b[78]
    DIRECTION INPUT ;
    USE SIGNAL ;
    PORT
      LAYER M5 ;
        RECT  114.672 215.916 114.696 216 ;
    END
  END s1b[78]
  PIN s1b[79]
    DIRECTION INPUT ;
    USE SIGNAL ;
    PORT
      LAYER M5 ;
        RECT  115.872 215.916 115.896 216 ;
    END
  END s1b[79]
  PIN s1b[7]
    DIRECTION INPUT ;
    USE SIGNAL ;
    PORT
      LAYER M5 ;
        RECT  30.528 215.916 30.552 216 ;
    END
  END s1b[7]
  PIN s1b[80]
    DIRECTION INPUT ;
    USE SIGNAL ;
    PORT
      LAYER M5 ;
        RECT  117.072 215.916 117.096 216 ;
    END
  END s1b[80]
  PIN s1b[81]
    DIRECTION INPUT ;
    USE SIGNAL ;
    PORT
      LAYER M5 ;
        RECT  118.224 215.916 118.248 216 ;
    END
  END s1b[81]
  PIN s1b[82]
    DIRECTION INPUT ;
    USE SIGNAL ;
    PORT
      LAYER M5 ;
        RECT  119.424 215.916 119.448 216 ;
    END
  END s1b[82]
  PIN s1b[83]
    DIRECTION INPUT ;
    USE SIGNAL ;
    PORT
      LAYER M5 ;
        RECT  120.624 215.916 120.648 216 ;
    END
  END s1b[83]
  PIN s1b[84]
    DIRECTION INPUT ;
    USE SIGNAL ;
    PORT
      LAYER M5 ;
        RECT  121.776 215.916 121.8 216 ;
    END
  END s1b[84]
  PIN s1b[85]
    DIRECTION INPUT ;
    USE SIGNAL ;
    PORT
      LAYER M5 ;
        RECT  122.976 215.916 123 216 ;
    END
  END s1b[85]
  PIN s1b[86]
    DIRECTION INPUT ;
    USE SIGNAL ;
    PORT
      LAYER M5 ;
        RECT  124.08 215.916 124.104 216 ;
    END
  END s1b[86]
  PIN s1b[87]
    DIRECTION INPUT ;
    USE SIGNAL ;
    PORT
      LAYER M5 ;
        RECT  125.376 215.916 125.4 216 ;
    END
  END s1b[87]
  PIN s1b[88]
    DIRECTION INPUT ;
    USE SIGNAL ;
    PORT
      LAYER M5 ;
        RECT  126.528 215.916 126.552 216 ;
    END
  END s1b[88]
  PIN s1b[89]
    DIRECTION INPUT ;
    USE SIGNAL ;
    PORT
      LAYER M5 ;
        RECT  127.728 215.916 127.752 216 ;
    END
  END s1b[89]
  PIN s1b[8]
    DIRECTION INPUT ;
    USE SIGNAL ;
    PORT
      LAYER M5 ;
        RECT  31.728 215.916 31.752 216 ;
    END
  END s1b[8]
  PIN s1b[90]
    DIRECTION INPUT ;
    USE SIGNAL ;
    PORT
      LAYER M5 ;
        RECT  128.928 215.916 128.952 216 ;
    END
  END s1b[90]
  PIN s1b[91]
    DIRECTION INPUT ;
    USE SIGNAL ;
    PORT
      LAYER M5 ;
        RECT  130.08 215.916 130.104 216 ;
    END
  END s1b[91]
  PIN s1b[92]
    DIRECTION INPUT ;
    USE SIGNAL ;
    PORT
      LAYER M5 ;
        RECT  131.28 215.916 131.304 216 ;
    END
  END s1b[92]
  PIN s1b[93]
    DIRECTION INPUT ;
    USE SIGNAL ;
    PORT
      LAYER M5 ;
        RECT  132.48 215.916 132.504 216 ;
    END
  END s1b[93]
  PIN s1b[94]
    DIRECTION INPUT ;
    USE SIGNAL ;
    PORT
      LAYER M5 ;
        RECT  133.632 215.916 133.656 216 ;
    END
  END s1b[94]
  PIN s1b[95]
    DIRECTION INPUT ;
    USE SIGNAL ;
    PORT
      LAYER M5 ;
        RECT  134.832 215.916 134.856 216 ;
    END
  END s1b[95]
  PIN s1b[96]
    DIRECTION INPUT ;
    USE SIGNAL ;
    PORT
      LAYER M5 ;
        RECT  136.032 215.916 136.056 216 ;
    END
  END s1b[96]
  PIN s1b[97]
    DIRECTION INPUT ;
    USE SIGNAL ;
    PORT
      LAYER M5 ;
        RECT  137.232 215.916 137.256 216 ;
    END
  END s1b[97]
  PIN s1b[98]
    DIRECTION INPUT ;
    USE SIGNAL ;
    PORT
      LAYER M5 ;
        RECT  138.384 215.916 138.408 216 ;
    END
  END s1b[98]
  PIN s1b[99]
    DIRECTION INPUT ;
    USE SIGNAL ;
    PORT
      LAYER M5 ;
        RECT  139.584 215.916 139.608 216 ;
    END
  END s1b[99]
  PIN s1b[9]
    DIRECTION INPUT ;
    USE SIGNAL ;
    PORT
      LAYER M5 ;
        RECT  32.88 215.916 32.904 216 ;
    END
  END s1b[9]
  PIN sa_d[0]
    DIRECTION INPUT ;
    USE SIGNAL ;
    PORT
      LAYER M4 ;
        RECT  0 28.608 0.084 28.632 ;
    END
  END sa_d[0]
  PIN sa_d[100]
    DIRECTION INPUT ;
    USE SIGNAL ;
    PORT
      LAYER M4 ;
        RECT  0 62.4 0.084 62.424 ;
    END
  END sa_d[100]
  PIN sa_d[101]
    DIRECTION INPUT ;
    USE SIGNAL ;
    PORT
      LAYER M4 ;
        RECT  0 62.736 0.084 62.76 ;
    END
  END sa_d[101]
  PIN sa_d[102]
    DIRECTION INPUT ;
    USE SIGNAL ;
    PORT
      LAYER M4 ;
        RECT  0 63.072 0.084 63.096 ;
    END
  END sa_d[102]
  PIN sa_d[103]
    DIRECTION INPUT ;
    USE SIGNAL ;
    PORT
      LAYER M4 ;
        RECT  0 63.408 0.084 63.432 ;
    END
  END sa_d[103]
  PIN sa_d[104]
    DIRECTION INPUT ;
    USE SIGNAL ;
    PORT
      LAYER M4 ;
        RECT  0 63.744 0.084 63.768 ;
    END
  END sa_d[104]
  PIN sa_d[105]
    DIRECTION INPUT ;
    USE SIGNAL ;
    PORT
      LAYER M4 ;
        RECT  0 64.08 0.084 64.104 ;
    END
  END sa_d[105]
  PIN sa_d[106]
    DIRECTION INPUT ;
    USE SIGNAL ;
    PORT
      LAYER M4 ;
        RECT  0 64.416 0.084 64.44 ;
    END
  END sa_d[106]
  PIN sa_d[107]
    DIRECTION INPUT ;
    USE SIGNAL ;
    PORT
      LAYER M4 ;
        RECT  0 64.752 0.084 64.776 ;
    END
  END sa_d[107]
  PIN sa_d[108]
    DIRECTION INPUT ;
    USE SIGNAL ;
    PORT
      LAYER M4 ;
        RECT  0 65.088 0.084 65.112 ;
    END
  END sa_d[108]
  PIN sa_d[109]
    DIRECTION INPUT ;
    USE SIGNAL ;
    PORT
      LAYER M4 ;
        RECT  0 65.424 0.084 65.448 ;
    END
  END sa_d[109]
  PIN sa_d[10]
    DIRECTION INPUT ;
    USE SIGNAL ;
    PORT
      LAYER M4 ;
        RECT  0 31.968 0.084 31.992 ;
    END
  END sa_d[10]
  PIN sa_d[110]
    DIRECTION INPUT ;
    USE SIGNAL ;
    PORT
      LAYER M4 ;
        RECT  0 65.76 0.084 65.784 ;
    END
  END sa_d[110]
  PIN sa_d[111]
    DIRECTION INPUT ;
    USE SIGNAL ;
    PORT
      LAYER M4 ;
        RECT  0 66.096 0.084 66.12 ;
    END
  END sa_d[111]
  PIN sa_d[112]
    DIRECTION INPUT ;
    USE SIGNAL ;
    PORT
      LAYER M4 ;
        RECT  0 66.432 0.084 66.456 ;
    END
  END sa_d[112]
  PIN sa_d[113]
    DIRECTION INPUT ;
    USE SIGNAL ;
    PORT
      LAYER M4 ;
        RECT  0 66.768 0.084 66.792 ;
    END
  END sa_d[113]
  PIN sa_d[114]
    DIRECTION INPUT ;
    USE SIGNAL ;
    PORT
      LAYER M4 ;
        RECT  0 67.104 0.084 67.128 ;
    END
  END sa_d[114]
  PIN sa_d[115]
    DIRECTION INPUT ;
    USE SIGNAL ;
    PORT
      LAYER M4 ;
        RECT  0 67.44 0.084 67.464 ;
    END
  END sa_d[115]
  PIN sa_d[116]
    DIRECTION INPUT ;
    USE SIGNAL ;
    PORT
      LAYER M4 ;
        RECT  0 67.776 0.084 67.8 ;
    END
  END sa_d[116]
  PIN sa_d[117]
    DIRECTION INPUT ;
    USE SIGNAL ;
    PORT
      LAYER M4 ;
        RECT  0 68.112 0.084 68.136 ;
    END
  END sa_d[117]
  PIN sa_d[118]
    DIRECTION INPUT ;
    USE SIGNAL ;
    PORT
      LAYER M4 ;
        RECT  0 68.448 0.084 68.472 ;
    END
  END sa_d[118]
  PIN sa_d[119]
    DIRECTION INPUT ;
    USE SIGNAL ;
    PORT
      LAYER M4 ;
        RECT  0 68.784 0.084 68.808 ;
    END
  END sa_d[119]
  PIN sa_d[11]
    DIRECTION INPUT ;
    USE SIGNAL ;
    PORT
      LAYER M4 ;
        RECT  0 32.304 0.084 32.328 ;
    END
  END sa_d[11]
  PIN sa_d[120]
    DIRECTION INPUT ;
    USE SIGNAL ;
    PORT
      LAYER M4 ;
        RECT  0 69.12 0.084 69.144 ;
    END
  END sa_d[120]
  PIN sa_d[121]
    DIRECTION INPUT ;
    USE SIGNAL ;
    PORT
      LAYER M4 ;
        RECT  0 69.504 0.084 69.528 ;
    END
  END sa_d[121]
  PIN sa_d[122]
    DIRECTION INPUT ;
    USE SIGNAL ;
    PORT
      LAYER M4 ;
        RECT  0 69.84 0.084 69.864 ;
    END
  END sa_d[122]
  PIN sa_d[123]
    DIRECTION INPUT ;
    USE SIGNAL ;
    PORT
      LAYER M4 ;
        RECT  0 70.176 0.084 70.2 ;
    END
  END sa_d[123]
  PIN sa_d[124]
    DIRECTION INPUT ;
    USE SIGNAL ;
    PORT
      LAYER M4 ;
        RECT  0 70.512 0.084 70.536 ;
    END
  END sa_d[124]
  PIN sa_d[125]
    DIRECTION INPUT ;
    USE SIGNAL ;
    PORT
      LAYER M4 ;
        RECT  0 70.848 0.084 70.872 ;
    END
  END sa_d[125]
  PIN sa_d[126]
    DIRECTION INPUT ;
    USE SIGNAL ;
    PORT
      LAYER M4 ;
        RECT  0 71.184 0.084 71.208 ;
    END
  END sa_d[126]
  PIN sa_d[127]
    DIRECTION INPUT ;
    USE SIGNAL ;
    PORT
      LAYER M4 ;
        RECT  0 71.52 0.084 71.544 ;
    END
  END sa_d[127]
  PIN sa_d[128]
    DIRECTION INPUT ;
    USE SIGNAL ;
    PORT
      LAYER M4 ;
        RECT  0 71.856 0.084 71.88 ;
    END
  END sa_d[128]
  PIN sa_d[129]
    DIRECTION INPUT ;
    USE SIGNAL ;
    PORT
      LAYER M4 ;
        RECT  0 72.192 0.084 72.216 ;
    END
  END sa_d[129]
  PIN sa_d[12]
    DIRECTION INPUT ;
    USE SIGNAL ;
    PORT
      LAYER M4 ;
        RECT  0 32.64 0.084 32.664 ;
    END
  END sa_d[12]
  PIN sa_d[130]
    DIRECTION INPUT ;
    USE SIGNAL ;
    PORT
      LAYER M4 ;
        RECT  0 72.528 0.084 72.552 ;
    END
  END sa_d[130]
  PIN sa_d[131]
    DIRECTION INPUT ;
    USE SIGNAL ;
    PORT
      LAYER M4 ;
        RECT  0 72.864 0.084 72.888 ;
    END
  END sa_d[131]
  PIN sa_d[132]
    DIRECTION INPUT ;
    USE SIGNAL ;
    PORT
      LAYER M4 ;
        RECT  0 73.2 0.084 73.224 ;
    END
  END sa_d[132]
  PIN sa_d[133]
    DIRECTION INPUT ;
    USE SIGNAL ;
    PORT
      LAYER M4 ;
        RECT  0 73.536 0.084 73.56 ;
    END
  END sa_d[133]
  PIN sa_d[134]
    DIRECTION INPUT ;
    USE SIGNAL ;
    PORT
      LAYER M4 ;
        RECT  0 73.872 0.084 73.896 ;
    END
  END sa_d[134]
  PIN sa_d[135]
    DIRECTION INPUT ;
    USE SIGNAL ;
    PORT
      LAYER M4 ;
        RECT  0 74.208 0.084 74.232 ;
    END
  END sa_d[135]
  PIN sa_d[136]
    DIRECTION INPUT ;
    USE SIGNAL ;
    PORT
      LAYER M4 ;
        RECT  0 74.544 0.084 74.568 ;
    END
  END sa_d[136]
  PIN sa_d[137]
    DIRECTION INPUT ;
    USE SIGNAL ;
    PORT
      LAYER M4 ;
        RECT  0 74.88 0.084 74.904 ;
    END
  END sa_d[137]
  PIN sa_d[138]
    DIRECTION INPUT ;
    USE SIGNAL ;
    PORT
      LAYER M4 ;
        RECT  0 75.216 0.084 75.24 ;
    END
  END sa_d[138]
  PIN sa_d[139]
    DIRECTION INPUT ;
    USE SIGNAL ;
    PORT
      LAYER M4 ;
        RECT  0 75.552 0.084 75.576 ;
    END
  END sa_d[139]
  PIN sa_d[13]
    DIRECTION INPUT ;
    USE SIGNAL ;
    PORT
      LAYER M4 ;
        RECT  0 33.024 0.084 33.048 ;
    END
  END sa_d[13]
  PIN sa_d[140]
    DIRECTION INPUT ;
    USE SIGNAL ;
    PORT
      LAYER M4 ;
        RECT  0 75.888 0.084 75.912 ;
    END
  END sa_d[140]
  PIN sa_d[141]
    DIRECTION INPUT ;
    USE SIGNAL ;
    PORT
      LAYER M4 ;
        RECT  0 76.224 0.084 76.248 ;
    END
  END sa_d[141]
  PIN sa_d[142]
    DIRECTION INPUT ;
    USE SIGNAL ;
    PORT
      LAYER M4 ;
        RECT  0 76.56 0.084 76.584 ;
    END
  END sa_d[142]
  PIN sa_d[143]
    DIRECTION INPUT ;
    USE SIGNAL ;
    PORT
      LAYER M4 ;
        RECT  0 76.896 0.084 76.92 ;
    END
  END sa_d[143]
  PIN sa_d[144]
    DIRECTION INPUT ;
    USE SIGNAL ;
    PORT
      LAYER M4 ;
        RECT  0 77.232 0.084 77.256 ;
    END
  END sa_d[144]
  PIN sa_d[145]
    DIRECTION INPUT ;
    USE SIGNAL ;
    PORT
      LAYER M4 ;
        RECT  0 77.568 0.084 77.592 ;
    END
  END sa_d[145]
  PIN sa_d[146]
    DIRECTION INPUT ;
    USE SIGNAL ;
    PORT
      LAYER M4 ;
        RECT  0 77.904 0.084 77.928 ;
    END
  END sa_d[146]
  PIN sa_d[147]
    DIRECTION INPUT ;
    USE SIGNAL ;
    PORT
      LAYER M4 ;
        RECT  0 78.24 0.084 78.264 ;
    END
  END sa_d[147]
  PIN sa_d[148]
    DIRECTION INPUT ;
    USE SIGNAL ;
    PORT
      LAYER M4 ;
        RECT  0 78.624 0.084 78.648 ;
    END
  END sa_d[148]
  PIN sa_d[149]
    DIRECTION INPUT ;
    USE SIGNAL ;
    PORT
      LAYER M4 ;
        RECT  0 78.96 0.084 78.984 ;
    END
  END sa_d[149]
  PIN sa_d[14]
    DIRECTION INPUT ;
    USE SIGNAL ;
    PORT
      LAYER M4 ;
        RECT  0 33.36 0.084 33.384 ;
    END
  END sa_d[14]
  PIN sa_d[150]
    DIRECTION INPUT ;
    USE SIGNAL ;
    PORT
      LAYER M4 ;
        RECT  0 79.296 0.084 79.32 ;
    END
  END sa_d[150]
  PIN sa_d[151]
    DIRECTION INPUT ;
    USE SIGNAL ;
    PORT
      LAYER M4 ;
        RECT  0 79.632 0.084 79.656 ;
    END
  END sa_d[151]
  PIN sa_d[152]
    DIRECTION INPUT ;
    USE SIGNAL ;
    PORT
      LAYER M4 ;
        RECT  0 79.968 0.084 79.992 ;
    END
  END sa_d[152]
  PIN sa_d[153]
    DIRECTION INPUT ;
    USE SIGNAL ;
    PORT
      LAYER M4 ;
        RECT  0 80.304 0.084 80.328 ;
    END
  END sa_d[153]
  PIN sa_d[154]
    DIRECTION INPUT ;
    USE SIGNAL ;
    PORT
      LAYER M4 ;
        RECT  0 80.64 0.084 80.664 ;
    END
  END sa_d[154]
  PIN sa_d[155]
    DIRECTION INPUT ;
    USE SIGNAL ;
    PORT
      LAYER M4 ;
        RECT  0 80.976 0.084 81 ;
    END
  END sa_d[155]
  PIN sa_d[156]
    DIRECTION INPUT ;
    USE SIGNAL ;
    PORT
      LAYER M4 ;
        RECT  0 81.312 0.084 81.336 ;
    END
  END sa_d[156]
  PIN sa_d[157]
    DIRECTION INPUT ;
    USE SIGNAL ;
    PORT
      LAYER M4 ;
        RECT  0 81.648 0.084 81.672 ;
    END
  END sa_d[157]
  PIN sa_d[158]
    DIRECTION INPUT ;
    USE SIGNAL ;
    PORT
      LAYER M4 ;
        RECT  0 81.984 0.084 82.008 ;
    END
  END sa_d[158]
  PIN sa_d[159]
    DIRECTION INPUT ;
    USE SIGNAL ;
    PORT
      LAYER M4 ;
        RECT  0 82.32 0.084 82.344 ;
    END
  END sa_d[159]
  PIN sa_d[15]
    DIRECTION INPUT ;
    USE SIGNAL ;
    PORT
      LAYER M4 ;
        RECT  0 33.696 0.084 33.72 ;
    END
  END sa_d[15]
  PIN sa_d[160]
    DIRECTION INPUT ;
    USE SIGNAL ;
    PORT
      LAYER M4 ;
        RECT  0 82.656 0.084 82.68 ;
    END
  END sa_d[160]
  PIN sa_d[161]
    DIRECTION INPUT ;
    USE SIGNAL ;
    PORT
      LAYER M4 ;
        RECT  0 82.992 0.084 83.016 ;
    END
  END sa_d[161]
  PIN sa_d[162]
    DIRECTION INPUT ;
    USE SIGNAL ;
    PORT
      LAYER M4 ;
        RECT  0 83.328 0.084 83.352 ;
    END
  END sa_d[162]
  PIN sa_d[163]
    DIRECTION INPUT ;
    USE SIGNAL ;
    PORT
      LAYER M4 ;
        RECT  0 83.664 0.084 83.688 ;
    END
  END sa_d[163]
  PIN sa_d[164]
    DIRECTION INPUT ;
    USE SIGNAL ;
    PORT
      LAYER M4 ;
        RECT  0 84 0.084 84.024 ;
    END
  END sa_d[164]
  PIN sa_d[165]
    DIRECTION INPUT ;
    USE SIGNAL ;
    PORT
      LAYER M4 ;
        RECT  0 84.336 0.084 84.36 ;
    END
  END sa_d[165]
  PIN sa_d[166]
    DIRECTION INPUT ;
    USE SIGNAL ;
    PORT
      LAYER M4 ;
        RECT  0 84.672 0.084 84.696 ;
    END
  END sa_d[166]
  PIN sa_d[167]
    DIRECTION INPUT ;
    USE SIGNAL ;
    PORT
      LAYER M4 ;
        RECT  0 85.008 0.084 85.032 ;
    END
  END sa_d[167]
  PIN sa_d[168]
    DIRECTION INPUT ;
    USE SIGNAL ;
    PORT
      LAYER M4 ;
        RECT  0 85.344 0.084 85.368 ;
    END
  END sa_d[168]
  PIN sa_d[169]
    DIRECTION INPUT ;
    USE SIGNAL ;
    PORT
      LAYER M4 ;
        RECT  0 85.68 0.084 85.704 ;
    END
  END sa_d[169]
  PIN sa_d[16]
    DIRECTION INPUT ;
    USE SIGNAL ;
    PORT
      LAYER M4 ;
        RECT  0 34.032 0.084 34.056 ;
    END
  END sa_d[16]
  PIN sa_d[170]
    DIRECTION INPUT ;
    USE SIGNAL ;
    PORT
      LAYER M4 ;
        RECT  0 86.016 0.084 86.04 ;
    END
  END sa_d[170]
  PIN sa_d[171]
    DIRECTION INPUT ;
    USE SIGNAL ;
    PORT
      LAYER M4 ;
        RECT  0 86.352 0.084 86.376 ;
    END
  END sa_d[171]
  PIN sa_d[172]
    DIRECTION INPUT ;
    USE SIGNAL ;
    PORT
      LAYER M4 ;
        RECT  0 86.688 0.084 86.712 ;
    END
  END sa_d[172]
  PIN sa_d[173]
    DIRECTION INPUT ;
    USE SIGNAL ;
    PORT
      LAYER M4 ;
        RECT  0 87.024 0.084 87.048 ;
    END
  END sa_d[173]
  PIN sa_d[174]
    DIRECTION INPUT ;
    USE SIGNAL ;
    PORT
      LAYER M4 ;
        RECT  0 87.36 0.084 87.384 ;
    END
  END sa_d[174]
  PIN sa_d[175]
    DIRECTION INPUT ;
    USE SIGNAL ;
    PORT
      LAYER M4 ;
        RECT  0 87.744 0.084 87.768 ;
    END
  END sa_d[175]
  PIN sa_d[176]
    DIRECTION INPUT ;
    USE SIGNAL ;
    PORT
      LAYER M4 ;
        RECT  0 88.08 0.084 88.104 ;
    END
  END sa_d[176]
  PIN sa_d[177]
    DIRECTION INPUT ;
    USE SIGNAL ;
    PORT
      LAYER M4 ;
        RECT  0 88.416 0.084 88.44 ;
    END
  END sa_d[177]
  PIN sa_d[178]
    DIRECTION INPUT ;
    USE SIGNAL ;
    PORT
      LAYER M4 ;
        RECT  0 88.752 0.084 88.776 ;
    END
  END sa_d[178]
  PIN sa_d[179]
    DIRECTION INPUT ;
    USE SIGNAL ;
    PORT
      LAYER M4 ;
        RECT  0 89.088 0.084 89.112 ;
    END
  END sa_d[179]
  PIN sa_d[17]
    DIRECTION INPUT ;
    USE SIGNAL ;
    PORT
      LAYER M4 ;
        RECT  0 34.368 0.084 34.392 ;
    END
  END sa_d[17]
  PIN sa_d[180]
    DIRECTION INPUT ;
    USE SIGNAL ;
    PORT
      LAYER M4 ;
        RECT  0 89.424 0.084 89.448 ;
    END
  END sa_d[180]
  PIN sa_d[181]
    DIRECTION INPUT ;
    USE SIGNAL ;
    PORT
      LAYER M4 ;
        RECT  0 89.76 0.084 89.784 ;
    END
  END sa_d[181]
  PIN sa_d[182]
    DIRECTION INPUT ;
    USE SIGNAL ;
    PORT
      LAYER M4 ;
        RECT  0 90.096 0.084 90.12 ;
    END
  END sa_d[182]
  PIN sa_d[183]
    DIRECTION INPUT ;
    USE SIGNAL ;
    PORT
      LAYER M4 ;
        RECT  0 90.432 0.084 90.456 ;
    END
  END sa_d[183]
  PIN sa_d[184]
    DIRECTION INPUT ;
    USE SIGNAL ;
    PORT
      LAYER M4 ;
        RECT  0 90.768 0.084 90.792 ;
    END
  END sa_d[184]
  PIN sa_d[185]
    DIRECTION INPUT ;
    USE SIGNAL ;
    PORT
      LAYER M4 ;
        RECT  0 91.104 0.084 91.128 ;
    END
  END sa_d[185]
  PIN sa_d[186]
    DIRECTION INPUT ;
    USE SIGNAL ;
    PORT
      LAYER M4 ;
        RECT  0 91.44 0.084 91.464 ;
    END
  END sa_d[186]
  PIN sa_d[187]
    DIRECTION INPUT ;
    USE SIGNAL ;
    PORT
      LAYER M4 ;
        RECT  0 91.776 0.084 91.8 ;
    END
  END sa_d[187]
  PIN sa_d[188]
    DIRECTION INPUT ;
    USE SIGNAL ;
    PORT
      LAYER M4 ;
        RECT  0 92.112 0.084 92.136 ;
    END
  END sa_d[188]
  PIN sa_d[189]
    DIRECTION INPUT ;
    USE SIGNAL ;
    PORT
      LAYER M4 ;
        RECT  0 92.448 0.084 92.472 ;
    END
  END sa_d[189]
  PIN sa_d[18]
    DIRECTION INPUT ;
    USE SIGNAL ;
    PORT
      LAYER M4 ;
        RECT  0 34.704 0.084 34.728 ;
    END
  END sa_d[18]
  PIN sa_d[190]
    DIRECTION INPUT ;
    USE SIGNAL ;
    PORT
      LAYER M4 ;
        RECT  0 92.784 0.084 92.808 ;
    END
  END sa_d[190]
  PIN sa_d[191]
    DIRECTION INPUT ;
    USE SIGNAL ;
    PORT
      LAYER M4 ;
        RECT  0 93.12 0.084 93.144 ;
    END
  END sa_d[191]
  PIN sa_d[192]
    DIRECTION INPUT ;
    USE SIGNAL ;
    PORT
      LAYER M4 ;
        RECT  0 93.456 0.084 93.48 ;
    END
  END sa_d[192]
  PIN sa_d[193]
    DIRECTION INPUT ;
    USE SIGNAL ;
    PORT
      LAYER M4 ;
        RECT  0 93.792 0.084 93.816 ;
    END
  END sa_d[193]
  PIN sa_d[194]
    DIRECTION INPUT ;
    USE SIGNAL ;
    PORT
      LAYER M4 ;
        RECT  0 94.128 0.084 94.152 ;
    END
  END sa_d[194]
  PIN sa_d[195]
    DIRECTION INPUT ;
    USE SIGNAL ;
    PORT
      LAYER M4 ;
        RECT  0 94.464 0.084 94.488 ;
    END
  END sa_d[195]
  PIN sa_d[196]
    DIRECTION INPUT ;
    USE SIGNAL ;
    PORT
      LAYER M4 ;
        RECT  0 94.8 0.084 94.824 ;
    END
  END sa_d[196]
  PIN sa_d[197]
    DIRECTION INPUT ;
    USE SIGNAL ;
    PORT
      LAYER M4 ;
        RECT  0 95.136 0.084 95.16 ;
    END
  END sa_d[197]
  PIN sa_d[198]
    DIRECTION INPUT ;
    USE SIGNAL ;
    PORT
      LAYER M4 ;
        RECT  0 95.472 0.084 95.496 ;
    END
  END sa_d[198]
  PIN sa_d[199]
    DIRECTION INPUT ;
    USE SIGNAL ;
    PORT
      LAYER M4 ;
        RECT  0 95.808 0.084 95.832 ;
    END
  END sa_d[199]
  PIN sa_d[19]
    DIRECTION INPUT ;
    USE SIGNAL ;
    PORT
      LAYER M4 ;
        RECT  0 35.04 0.084 35.064 ;
    END
  END sa_d[19]
  PIN sa_d[1]
    DIRECTION INPUT ;
    USE SIGNAL ;
    PORT
      LAYER M4 ;
        RECT  0 28.944 0.084 28.968 ;
    END
  END sa_d[1]
  PIN sa_d[200]
    DIRECTION INPUT ;
    USE SIGNAL ;
    PORT
      LAYER M4 ;
        RECT  0 96.144 0.084 96.168 ;
    END
  END sa_d[200]
  PIN sa_d[201]
    DIRECTION INPUT ;
    USE SIGNAL ;
    PORT
      LAYER M4 ;
        RECT  0 96.48 0.084 96.504 ;
    END
  END sa_d[201]
  PIN sa_d[202]
    DIRECTION INPUT ;
    USE SIGNAL ;
    PORT
      LAYER M4 ;
        RECT  0 96.864 0.084 96.888 ;
    END
  END sa_d[202]
  PIN sa_d[203]
    DIRECTION INPUT ;
    USE SIGNAL ;
    PORT
      LAYER M4 ;
        RECT  0 97.2 0.084 97.224 ;
    END
  END sa_d[203]
  PIN sa_d[204]
    DIRECTION INPUT ;
    USE SIGNAL ;
    PORT
      LAYER M4 ;
        RECT  0 97.536 0.084 97.56 ;
    END
  END sa_d[204]
  PIN sa_d[205]
    DIRECTION INPUT ;
    USE SIGNAL ;
    PORT
      LAYER M4 ;
        RECT  0 97.872 0.084 97.896 ;
    END
  END sa_d[205]
  PIN sa_d[206]
    DIRECTION INPUT ;
    USE SIGNAL ;
    PORT
      LAYER M4 ;
        RECT  0 98.208 0.084 98.232 ;
    END
  END sa_d[206]
  PIN sa_d[207]
    DIRECTION INPUT ;
    USE SIGNAL ;
    PORT
      LAYER M4 ;
        RECT  0 98.544 0.084 98.568 ;
    END
  END sa_d[207]
  PIN sa_d[208]
    DIRECTION INPUT ;
    USE SIGNAL ;
    PORT
      LAYER M4 ;
        RECT  0 98.88 0.084 98.904 ;
    END
  END sa_d[208]
  PIN sa_d[209]
    DIRECTION INPUT ;
    USE SIGNAL ;
    PORT
      LAYER M4 ;
        RECT  0 99.216 0.084 99.24 ;
    END
  END sa_d[209]
  PIN sa_d[20]
    DIRECTION INPUT ;
    USE SIGNAL ;
    PORT
      LAYER M4 ;
        RECT  0 35.376 0.084 35.4 ;
    END
  END sa_d[20]
  PIN sa_d[210]
    DIRECTION INPUT ;
    USE SIGNAL ;
    PORT
      LAYER M4 ;
        RECT  0 99.552 0.084 99.576 ;
    END
  END sa_d[210]
  PIN sa_d[211]
    DIRECTION INPUT ;
    USE SIGNAL ;
    PORT
      LAYER M4 ;
        RECT  0 99.888 0.084 99.912 ;
    END
  END sa_d[211]
  PIN sa_d[212]
    DIRECTION INPUT ;
    USE SIGNAL ;
    PORT
      LAYER M4 ;
        RECT  0 100.224 0.084 100.248 ;
    END
  END sa_d[212]
  PIN sa_d[213]
    DIRECTION INPUT ;
    USE SIGNAL ;
    PORT
      LAYER M4 ;
        RECT  0 100.56 0.084 100.584 ;
    END
  END sa_d[213]
  PIN sa_d[214]
    DIRECTION INPUT ;
    USE SIGNAL ;
    PORT
      LAYER M4 ;
        RECT  0 100.896 0.084 100.92 ;
    END
  END sa_d[214]
  PIN sa_d[215]
    DIRECTION INPUT ;
    USE SIGNAL ;
    PORT
      LAYER M4 ;
        RECT  0 101.232 0.084 101.256 ;
    END
  END sa_d[215]
  PIN sa_d[216]
    DIRECTION INPUT ;
    USE SIGNAL ;
    PORT
      LAYER M4 ;
        RECT  0 101.568 0.084 101.592 ;
    END
  END sa_d[216]
  PIN sa_d[217]
    DIRECTION INPUT ;
    USE SIGNAL ;
    PORT
      LAYER M4 ;
        RECT  0 101.904 0.084 101.928 ;
    END
  END sa_d[217]
  PIN sa_d[218]
    DIRECTION INPUT ;
    USE SIGNAL ;
    PORT
      LAYER M4 ;
        RECT  0 102.24 0.084 102.264 ;
    END
  END sa_d[218]
  PIN sa_d[219]
    DIRECTION INPUT ;
    USE SIGNAL ;
    PORT
      LAYER M4 ;
        RECT  0 102.576 0.084 102.6 ;
    END
  END sa_d[219]
  PIN sa_d[21]
    DIRECTION INPUT ;
    USE SIGNAL ;
    PORT
      LAYER M4 ;
        RECT  0 35.712 0.084 35.736 ;
    END
  END sa_d[21]
  PIN sa_d[220]
    DIRECTION INPUT ;
    USE SIGNAL ;
    PORT
      LAYER M4 ;
        RECT  0 102.912 0.084 102.936 ;
    END
  END sa_d[220]
  PIN sa_d[221]
    DIRECTION INPUT ;
    USE SIGNAL ;
    PORT
      LAYER M4 ;
        RECT  0 103.248 0.084 103.272 ;
    END
  END sa_d[221]
  PIN sa_d[222]
    DIRECTION INPUT ;
    USE SIGNAL ;
    PORT
      LAYER M4 ;
        RECT  0 103.584 0.084 103.608 ;
    END
  END sa_d[222]
  PIN sa_d[223]
    DIRECTION INPUT ;
    USE SIGNAL ;
    PORT
      LAYER M4 ;
        RECT  0 103.92 0.084 103.944 ;
    END
  END sa_d[223]
  PIN sa_d[22]
    DIRECTION INPUT ;
    USE SIGNAL ;
    PORT
      LAYER M4 ;
        RECT  0 36.048 0.084 36.072 ;
    END
  END sa_d[22]
  PIN sa_d[23]
    DIRECTION INPUT ;
    USE SIGNAL ;
    PORT
      LAYER M4 ;
        RECT  0 36.384 0.084 36.408 ;
    END
  END sa_d[23]
  PIN sa_d[24]
    DIRECTION INPUT ;
    USE SIGNAL ;
    PORT
      LAYER M4 ;
        RECT  0 36.72 0.084 36.744 ;
    END
  END sa_d[24]
  PIN sa_d[25]
    DIRECTION INPUT ;
    USE SIGNAL ;
    PORT
      LAYER M4 ;
        RECT  0 37.056 0.084 37.08 ;
    END
  END sa_d[25]
  PIN sa_d[26]
    DIRECTION INPUT ;
    USE SIGNAL ;
    PORT
      LAYER M4 ;
        RECT  0 37.392 0.084 37.416 ;
    END
  END sa_d[26]
  PIN sa_d[27]
    DIRECTION INPUT ;
    USE SIGNAL ;
    PORT
      LAYER M4 ;
        RECT  0 37.728 0.084 37.752 ;
    END
  END sa_d[27]
  PIN sa_d[28]
    DIRECTION INPUT ;
    USE SIGNAL ;
    PORT
      LAYER M4 ;
        RECT  0 38.064 0.084 38.088 ;
    END
  END sa_d[28]
  PIN sa_d[29]
    DIRECTION INPUT ;
    USE SIGNAL ;
    PORT
      LAYER M4 ;
        RECT  0 38.4 0.084 38.424 ;
    END
  END sa_d[29]
  PIN sa_d[2]
    DIRECTION INPUT ;
    USE SIGNAL ;
    PORT
      LAYER M4 ;
        RECT  0 29.28 0.084 29.304 ;
    END
  END sa_d[2]
  PIN sa_d[30]
    DIRECTION INPUT ;
    USE SIGNAL ;
    PORT
      LAYER M4 ;
        RECT  0 38.736 0.084 38.76 ;
    END
  END sa_d[30]
  PIN sa_d[31]
    DIRECTION INPUT ;
    USE SIGNAL ;
    PORT
      LAYER M4 ;
        RECT  0 39.072 0.084 39.096 ;
    END
  END sa_d[31]
  PIN sa_d[32]
    DIRECTION INPUT ;
    USE SIGNAL ;
    PORT
      LAYER M4 ;
        RECT  0 39.408 0.084 39.432 ;
    END
  END sa_d[32]
  PIN sa_d[33]
    DIRECTION INPUT ;
    USE SIGNAL ;
    PORT
      LAYER M4 ;
        RECT  0 39.744 0.084 39.768 ;
    END
  END sa_d[33]
  PIN sa_d[34]
    DIRECTION INPUT ;
    USE SIGNAL ;
    PORT
      LAYER M4 ;
        RECT  0 40.08 0.084 40.104 ;
    END
  END sa_d[34]
  PIN sa_d[35]
    DIRECTION INPUT ;
    USE SIGNAL ;
    PORT
      LAYER M4 ;
        RECT  0 40.416 0.084 40.44 ;
    END
  END sa_d[35]
  PIN sa_d[36]
    DIRECTION INPUT ;
    USE SIGNAL ;
    PORT
      LAYER M4 ;
        RECT  0 40.752 0.084 40.776 ;
    END
  END sa_d[36]
  PIN sa_d[37]
    DIRECTION INPUT ;
    USE SIGNAL ;
    PORT
      LAYER M4 ;
        RECT  0 41.088 0.084 41.112 ;
    END
  END sa_d[37]
  PIN sa_d[38]
    DIRECTION INPUT ;
    USE SIGNAL ;
    PORT
      LAYER M4 ;
        RECT  0 41.424 0.084 41.448 ;
    END
  END sa_d[38]
  PIN sa_d[39]
    DIRECTION INPUT ;
    USE SIGNAL ;
    PORT
      LAYER M4 ;
        RECT  0 41.76 0.084 41.784 ;
    END
  END sa_d[39]
  PIN sa_d[3]
    DIRECTION INPUT ;
    USE SIGNAL ;
    PORT
      LAYER M4 ;
        RECT  0 29.616 0.084 29.64 ;
    END
  END sa_d[3]
  PIN sa_d[40]
    DIRECTION INPUT ;
    USE SIGNAL ;
    PORT
      LAYER M4 ;
        RECT  0 42.144 0.084 42.168 ;
    END
  END sa_d[40]
  PIN sa_d[41]
    DIRECTION INPUT ;
    USE SIGNAL ;
    PORT
      LAYER M4 ;
        RECT  0 42.48 0.084 42.504 ;
    END
  END sa_d[41]
  PIN sa_d[42]
    DIRECTION INPUT ;
    USE SIGNAL ;
    PORT
      LAYER M4 ;
        RECT  0 42.816 0.084 42.84 ;
    END
  END sa_d[42]
  PIN sa_d[43]
    DIRECTION INPUT ;
    USE SIGNAL ;
    PORT
      LAYER M4 ;
        RECT  0 43.152 0.084 43.176 ;
    END
  END sa_d[43]
  PIN sa_d[44]
    DIRECTION INPUT ;
    USE SIGNAL ;
    PORT
      LAYER M4 ;
        RECT  0 43.488 0.084 43.512 ;
    END
  END sa_d[44]
  PIN sa_d[45]
    DIRECTION INPUT ;
    USE SIGNAL ;
    PORT
      LAYER M4 ;
        RECT  0 43.824 0.084 43.848 ;
    END
  END sa_d[45]
  PIN sa_d[46]
    DIRECTION INPUT ;
    USE SIGNAL ;
    PORT
      LAYER M4 ;
        RECT  0 44.16 0.084 44.184 ;
    END
  END sa_d[46]
  PIN sa_d[47]
    DIRECTION INPUT ;
    USE SIGNAL ;
    PORT
      LAYER M4 ;
        RECT  0 44.496 0.084 44.52 ;
    END
  END sa_d[47]
  PIN sa_d[48]
    DIRECTION INPUT ;
    USE SIGNAL ;
    PORT
      LAYER M4 ;
        RECT  0 44.832 0.084 44.856 ;
    END
  END sa_d[48]
  PIN sa_d[49]
    DIRECTION INPUT ;
    USE SIGNAL ;
    PORT
      LAYER M4 ;
        RECT  0 45.168 0.084 45.192 ;
    END
  END sa_d[49]
  PIN sa_d[4]
    DIRECTION INPUT ;
    USE SIGNAL ;
    PORT
      LAYER M4 ;
        RECT  0 29.952 0.084 29.976 ;
    END
  END sa_d[4]
  PIN sa_d[50]
    DIRECTION INPUT ;
    USE SIGNAL ;
    PORT
      LAYER M4 ;
        RECT  0 45.504 0.084 45.528 ;
    END
  END sa_d[50]
  PIN sa_d[51]
    DIRECTION INPUT ;
    USE SIGNAL ;
    PORT
      LAYER M4 ;
        RECT  0 45.84 0.084 45.864 ;
    END
  END sa_d[51]
  PIN sa_d[52]
    DIRECTION INPUT ;
    USE SIGNAL ;
    PORT
      LAYER M4 ;
        RECT  0 46.176 0.084 46.2 ;
    END
  END sa_d[52]
  PIN sa_d[53]
    DIRECTION INPUT ;
    USE SIGNAL ;
    PORT
      LAYER M4 ;
        RECT  0 46.512 0.084 46.536 ;
    END
  END sa_d[53]
  PIN sa_d[54]
    DIRECTION INPUT ;
    USE SIGNAL ;
    PORT
      LAYER M4 ;
        RECT  0 46.848 0.084 46.872 ;
    END
  END sa_d[54]
  PIN sa_d[55]
    DIRECTION INPUT ;
    USE SIGNAL ;
    PORT
      LAYER M4 ;
        RECT  0 47.184 0.084 47.208 ;
    END
  END sa_d[55]
  PIN sa_d[56]
    DIRECTION INPUT ;
    USE SIGNAL ;
    PORT
      LAYER M4 ;
        RECT  0 47.52 0.084 47.544 ;
    END
  END sa_d[56]
  PIN sa_d[57]
    DIRECTION INPUT ;
    USE SIGNAL ;
    PORT
      LAYER M4 ;
        RECT  0 47.856 0.084 47.88 ;
    END
  END sa_d[57]
  PIN sa_d[58]
    DIRECTION INPUT ;
    USE SIGNAL ;
    PORT
      LAYER M4 ;
        RECT  0 48.192 0.084 48.216 ;
    END
  END sa_d[58]
  PIN sa_d[59]
    DIRECTION INPUT ;
    USE SIGNAL ;
    PORT
      LAYER M4 ;
        RECT  0 48.528 0.084 48.552 ;
    END
  END sa_d[59]
  PIN sa_d[5]
    DIRECTION INPUT ;
    USE SIGNAL ;
    PORT
      LAYER M4 ;
        RECT  0 30.288 0.084 30.312 ;
    END
  END sa_d[5]
  PIN sa_d[60]
    DIRECTION INPUT ;
    USE SIGNAL ;
    PORT
      LAYER M4 ;
        RECT  0 48.864 0.084 48.888 ;
    END
  END sa_d[60]
  PIN sa_d[61]
    DIRECTION INPUT ;
    USE SIGNAL ;
    PORT
      LAYER M4 ;
        RECT  0 49.2 0.084 49.224 ;
    END
  END sa_d[61]
  PIN sa_d[62]
    DIRECTION INPUT ;
    USE SIGNAL ;
    PORT
      LAYER M4 ;
        RECT  0 49.536 0.084 49.56 ;
    END
  END sa_d[62]
  PIN sa_d[63]
    DIRECTION INPUT ;
    USE SIGNAL ;
    PORT
      LAYER M4 ;
        RECT  0 49.872 0.084 49.896 ;
    END
  END sa_d[63]
  PIN sa_d[64]
    DIRECTION INPUT ;
    USE SIGNAL ;
    PORT
      LAYER M4 ;
        RECT  0 50.208 0.084 50.232 ;
    END
  END sa_d[64]
  PIN sa_d[65]
    DIRECTION INPUT ;
    USE SIGNAL ;
    PORT
      LAYER M4 ;
        RECT  0 50.544 0.084 50.568 ;
    END
  END sa_d[65]
  PIN sa_d[66]
    DIRECTION INPUT ;
    USE SIGNAL ;
    PORT
      LAYER M4 ;
        RECT  0 50.88 0.084 50.904 ;
    END
  END sa_d[66]
  PIN sa_d[67]
    DIRECTION INPUT ;
    USE SIGNAL ;
    PORT
      LAYER M4 ;
        RECT  0 51.264 0.084 51.288 ;
    END
  END sa_d[67]
  PIN sa_d[68]
    DIRECTION INPUT ;
    USE SIGNAL ;
    PORT
      LAYER M4 ;
        RECT  0 51.6 0.084 51.624 ;
    END
  END sa_d[68]
  PIN sa_d[69]
    DIRECTION INPUT ;
    USE SIGNAL ;
    PORT
      LAYER M4 ;
        RECT  0 51.936 0.084 51.96 ;
    END
  END sa_d[69]
  PIN sa_d[6]
    DIRECTION INPUT ;
    USE SIGNAL ;
    PORT
      LAYER M4 ;
        RECT  0 30.624 0.084 30.648 ;
    END
  END sa_d[6]
  PIN sa_d[70]
    DIRECTION INPUT ;
    USE SIGNAL ;
    PORT
      LAYER M4 ;
        RECT  0 52.272 0.084 52.296 ;
    END
  END sa_d[70]
  PIN sa_d[71]
    DIRECTION INPUT ;
    USE SIGNAL ;
    PORT
      LAYER M4 ;
        RECT  0 52.608 0.084 52.632 ;
    END
  END sa_d[71]
  PIN sa_d[72]
    DIRECTION INPUT ;
    USE SIGNAL ;
    PORT
      LAYER M4 ;
        RECT  0 52.944 0.084 52.968 ;
    END
  END sa_d[72]
  PIN sa_d[73]
    DIRECTION INPUT ;
    USE SIGNAL ;
    PORT
      LAYER M4 ;
        RECT  0 53.28 0.084 53.304 ;
    END
  END sa_d[73]
  PIN sa_d[74]
    DIRECTION INPUT ;
    USE SIGNAL ;
    PORT
      LAYER M4 ;
        RECT  0 53.616 0.084 53.64 ;
    END
  END sa_d[74]
  PIN sa_d[75]
    DIRECTION INPUT ;
    USE SIGNAL ;
    PORT
      LAYER M4 ;
        RECT  0 53.952 0.084 53.976 ;
    END
  END sa_d[75]
  PIN sa_d[76]
    DIRECTION INPUT ;
    USE SIGNAL ;
    PORT
      LAYER M4 ;
        RECT  0 54.288 0.084 54.312 ;
    END
  END sa_d[76]
  PIN sa_d[77]
    DIRECTION INPUT ;
    USE SIGNAL ;
    PORT
      LAYER M4 ;
        RECT  0 54.624 0.084 54.648 ;
    END
  END sa_d[77]
  PIN sa_d[78]
    DIRECTION INPUT ;
    USE SIGNAL ;
    PORT
      LAYER M4 ;
        RECT  0 54.96 0.084 54.984 ;
    END
  END sa_d[78]
  PIN sa_d[79]
    DIRECTION INPUT ;
    USE SIGNAL ;
    PORT
      LAYER M4 ;
        RECT  0 55.296 0.084 55.32 ;
    END
  END sa_d[79]
  PIN sa_d[7]
    DIRECTION INPUT ;
    USE SIGNAL ;
    PORT
      LAYER M4 ;
        RECT  0 30.96 0.084 30.984 ;
    END
  END sa_d[7]
  PIN sa_d[80]
    DIRECTION INPUT ;
    USE SIGNAL ;
    PORT
      LAYER M4 ;
        RECT  0 55.632 0.084 55.656 ;
    END
  END sa_d[80]
  PIN sa_d[81]
    DIRECTION INPUT ;
    USE SIGNAL ;
    PORT
      LAYER M4 ;
        RECT  0 55.968 0.084 55.992 ;
    END
  END sa_d[81]
  PIN sa_d[82]
    DIRECTION INPUT ;
    USE SIGNAL ;
    PORT
      LAYER M4 ;
        RECT  0 56.304 0.084 56.328 ;
    END
  END sa_d[82]
  PIN sa_d[83]
    DIRECTION INPUT ;
    USE SIGNAL ;
    PORT
      LAYER M4 ;
        RECT  0 56.64 0.084 56.664 ;
    END
  END sa_d[83]
  PIN sa_d[84]
    DIRECTION INPUT ;
    USE SIGNAL ;
    PORT
      LAYER M4 ;
        RECT  0 56.976 0.084 57 ;
    END
  END sa_d[84]
  PIN sa_d[85]
    DIRECTION INPUT ;
    USE SIGNAL ;
    PORT
      LAYER M4 ;
        RECT  0 57.312 0.084 57.336 ;
    END
  END sa_d[85]
  PIN sa_d[86]
    DIRECTION INPUT ;
    USE SIGNAL ;
    PORT
      LAYER M4 ;
        RECT  0 57.648 0.084 57.672 ;
    END
  END sa_d[86]
  PIN sa_d[87]
    DIRECTION INPUT ;
    USE SIGNAL ;
    PORT
      LAYER M4 ;
        RECT  0 57.984 0.084 58.008 ;
    END
  END sa_d[87]
  PIN sa_d[88]
    DIRECTION INPUT ;
    USE SIGNAL ;
    PORT
      LAYER M4 ;
        RECT  0 58.32 0.084 58.344 ;
    END
  END sa_d[88]
  PIN sa_d[89]
    DIRECTION INPUT ;
    USE SIGNAL ;
    PORT
      LAYER M4 ;
        RECT  0 58.656 0.084 58.68 ;
    END
  END sa_d[89]
  PIN sa_d[8]
    DIRECTION INPUT ;
    USE SIGNAL ;
    PORT
      LAYER M4 ;
        RECT  0 31.296 0.084 31.32 ;
    END
  END sa_d[8]
  PIN sa_d[90]
    DIRECTION INPUT ;
    USE SIGNAL ;
    PORT
      LAYER M4 ;
        RECT  0 58.992 0.084 59.016 ;
    END
  END sa_d[90]
  PIN sa_d[91]
    DIRECTION INPUT ;
    USE SIGNAL ;
    PORT
      LAYER M4 ;
        RECT  0 59.328 0.084 59.352 ;
    END
  END sa_d[91]
  PIN sa_d[92]
    DIRECTION INPUT ;
    USE SIGNAL ;
    PORT
      LAYER M4 ;
        RECT  0 59.664 0.084 59.688 ;
    END
  END sa_d[92]
  PIN sa_d[93]
    DIRECTION INPUT ;
    USE SIGNAL ;
    PORT
      LAYER M4 ;
        RECT  0 60 0.084 60.024 ;
    END
  END sa_d[93]
  PIN sa_d[94]
    DIRECTION INPUT ;
    USE SIGNAL ;
    PORT
      LAYER M4 ;
        RECT  0 60.384 0.084 60.408 ;
    END
  END sa_d[94]
  PIN sa_d[95]
    DIRECTION INPUT ;
    USE SIGNAL ;
    PORT
      LAYER M4 ;
        RECT  0 60.72 0.084 60.744 ;
    END
  END sa_d[95]
  PIN sa_d[96]
    DIRECTION INPUT ;
    USE SIGNAL ;
    PORT
      LAYER M4 ;
        RECT  0 61.056 0.084 61.08 ;
    END
  END sa_d[96]
  PIN sa_d[97]
    DIRECTION INPUT ;
    USE SIGNAL ;
    PORT
      LAYER M4 ;
        RECT  0 61.392 0.084 61.416 ;
    END
  END sa_d[97]
  PIN sa_d[98]
    DIRECTION INPUT ;
    USE SIGNAL ;
    PORT
      LAYER M4 ;
        RECT  0 61.728 0.084 61.752 ;
    END
  END sa_d[98]
  PIN sa_d[99]
    DIRECTION INPUT ;
    USE SIGNAL ;
    PORT
      LAYER M4 ;
        RECT  0 62.064 0.084 62.088 ;
    END
  END sa_d[99]
  PIN sa_d[9]
    DIRECTION INPUT ;
    USE SIGNAL ;
    PORT
      LAYER M4 ;
        RECT  0 31.632 0.084 31.656 ;
    END
  END sa_d[9]
  PIN sa_r[0]
    DIRECTION INPUT ;
    USE SIGNAL ;
    PORT
      LAYER M4 ;
        RECT  0 26.592 0.084 26.616 ;
    END
  END sa_r[0]
  PIN sa_r[1]
    DIRECTION INPUT ;
    USE SIGNAL ;
    PORT
      LAYER M4 ;
        RECT  0 26.928 0.084 26.952 ;
    END
  END sa_r[1]
  PIN sa_r[2]
    DIRECTION INPUT ;
    USE SIGNAL ;
    PORT
      LAYER M4 ;
        RECT  0 27.264 0.084 27.288 ;
    END
  END sa_r[2]
  PIN sa_r[3]
    DIRECTION INPUT ;
    USE SIGNAL ;
    PORT
      LAYER M4 ;
        RECT  0 27.6 0.084 27.624 ;
    END
  END sa_r[3]
  PIN sa_r[4]
    DIRECTION INPUT ;
    USE SIGNAL ;
    PORT
      LAYER M4 ;
        RECT  0 27.936 0.084 27.96 ;
    END
  END sa_r[4]
  PIN sa_r[5]
    DIRECTION INPUT ;
    USE SIGNAL ;
    PORT
      LAYER M4 ;
        RECT  0 28.272 0.084 28.296 ;
    END
  END sa_r[5]
  PIN sb_d[0]
    DIRECTION INPUT ;
    USE SIGNAL ;
    PORT
      LAYER M4 ;
        RECT  0 106.32 0.084 106.344 ;
    END
  END sb_d[0]
  PIN sb_d[100]
    DIRECTION INPUT ;
    USE SIGNAL ;
    PORT
      LAYER M4 ;
        RECT  0 140.064 0.084 140.088 ;
    END
  END sb_d[100]
  PIN sb_d[101]
    DIRECTION INPUT ;
    USE SIGNAL ;
    PORT
      LAYER M4 ;
        RECT  0 140.4 0.084 140.424 ;
    END
  END sb_d[101]
  PIN sb_d[102]
    DIRECTION INPUT ;
    USE SIGNAL ;
    PORT
      LAYER M4 ;
        RECT  0 140.736 0.084 140.76 ;
    END
  END sb_d[102]
  PIN sb_d[103]
    DIRECTION INPUT ;
    USE SIGNAL ;
    PORT
      LAYER M4 ;
        RECT  0 141.072 0.084 141.096 ;
    END
  END sb_d[103]
  PIN sb_d[104]
    DIRECTION INPUT ;
    USE SIGNAL ;
    PORT
      LAYER M4 ;
        RECT  0 141.408 0.084 141.432 ;
    END
  END sb_d[104]
  PIN sb_d[105]
    DIRECTION INPUT ;
    USE SIGNAL ;
    PORT
      LAYER M4 ;
        RECT  0 141.744 0.084 141.768 ;
    END
  END sb_d[105]
  PIN sb_d[106]
    DIRECTION INPUT ;
    USE SIGNAL ;
    PORT
      LAYER M4 ;
        RECT  0 142.08 0.084 142.104 ;
    END
  END sb_d[106]
  PIN sb_d[107]
    DIRECTION INPUT ;
    USE SIGNAL ;
    PORT
      LAYER M4 ;
        RECT  0 142.464 0.084 142.488 ;
    END
  END sb_d[107]
  PIN sb_d[108]
    DIRECTION INPUT ;
    USE SIGNAL ;
    PORT
      LAYER M4 ;
        RECT  0 142.8 0.084 142.824 ;
    END
  END sb_d[108]
  PIN sb_d[109]
    DIRECTION INPUT ;
    USE SIGNAL ;
    PORT
      LAYER M4 ;
        RECT  0 143.136 0.084 143.16 ;
    END
  END sb_d[109]
  PIN sb_d[10]
    DIRECTION INPUT ;
    USE SIGNAL ;
    PORT
      LAYER M4 ;
        RECT  0 109.68 0.084 109.704 ;
    END
  END sb_d[10]
  PIN sb_d[110]
    DIRECTION INPUT ;
    USE SIGNAL ;
    PORT
      LAYER M4 ;
        RECT  0 143.472 0.084 143.496 ;
    END
  END sb_d[110]
  PIN sb_d[111]
    DIRECTION INPUT ;
    USE SIGNAL ;
    PORT
      LAYER M4 ;
        RECT  0 143.808 0.084 143.832 ;
    END
  END sb_d[111]
  PIN sb_d[112]
    DIRECTION INPUT ;
    USE SIGNAL ;
    PORT
      LAYER M4 ;
        RECT  0 144.144 0.084 144.168 ;
    END
  END sb_d[112]
  PIN sb_d[113]
    DIRECTION INPUT ;
    USE SIGNAL ;
    PORT
      LAYER M4 ;
        RECT  0 144.48 0.084 144.504 ;
    END
  END sb_d[113]
  PIN sb_d[114]
    DIRECTION INPUT ;
    USE SIGNAL ;
    PORT
      LAYER M4 ;
        RECT  0 144.816 0.084 144.84 ;
    END
  END sb_d[114]
  PIN sb_d[115]
    DIRECTION INPUT ;
    USE SIGNAL ;
    PORT
      LAYER M4 ;
        RECT  0 145.152 0.084 145.176 ;
    END
  END sb_d[115]
  PIN sb_d[116]
    DIRECTION INPUT ;
    USE SIGNAL ;
    PORT
      LAYER M4 ;
        RECT  0 145.488 0.084 145.512 ;
    END
  END sb_d[116]
  PIN sb_d[117]
    DIRECTION INPUT ;
    USE SIGNAL ;
    PORT
      LAYER M4 ;
        RECT  0 145.824 0.084 145.848 ;
    END
  END sb_d[117]
  PIN sb_d[118]
    DIRECTION INPUT ;
    USE SIGNAL ;
    PORT
      LAYER M4 ;
        RECT  0 146.16 0.084 146.184 ;
    END
  END sb_d[118]
  PIN sb_d[119]
    DIRECTION INPUT ;
    USE SIGNAL ;
    PORT
      LAYER M4 ;
        RECT  0 146.496 0.084 146.52 ;
    END
  END sb_d[119]
  PIN sb_d[11]
    DIRECTION INPUT ;
    USE SIGNAL ;
    PORT
      LAYER M4 ;
        RECT  0 110.016 0.084 110.04 ;
    END
  END sb_d[11]
  PIN sb_d[120]
    DIRECTION INPUT ;
    USE SIGNAL ;
    PORT
      LAYER M4 ;
        RECT  0 146.832 0.084 146.856 ;
    END
  END sb_d[120]
  PIN sb_d[121]
    DIRECTION INPUT ;
    USE SIGNAL ;
    PORT
      LAYER M4 ;
        RECT  0 147.168 0.084 147.192 ;
    END
  END sb_d[121]
  PIN sb_d[122]
    DIRECTION INPUT ;
    USE SIGNAL ;
    PORT
      LAYER M4 ;
        RECT  0 147.504 0.084 147.528 ;
    END
  END sb_d[122]
  PIN sb_d[123]
    DIRECTION INPUT ;
    USE SIGNAL ;
    PORT
      LAYER M4 ;
        RECT  0 147.84 0.084 147.864 ;
    END
  END sb_d[123]
  PIN sb_d[124]
    DIRECTION INPUT ;
    USE SIGNAL ;
    PORT
      LAYER M4 ;
        RECT  0 148.176 0.084 148.2 ;
    END
  END sb_d[124]
  PIN sb_d[125]
    DIRECTION INPUT ;
    USE SIGNAL ;
    PORT
      LAYER M4 ;
        RECT  0 148.512 0.084 148.536 ;
    END
  END sb_d[125]
  PIN sb_d[126]
    DIRECTION INPUT ;
    USE SIGNAL ;
    PORT
      LAYER M4 ;
        RECT  0 148.848 0.084 148.872 ;
    END
  END sb_d[126]
  PIN sb_d[127]
    DIRECTION INPUT ;
    USE SIGNAL ;
    PORT
      LAYER M4 ;
        RECT  0 149.184 0.084 149.208 ;
    END
  END sb_d[127]
  PIN sb_d[128]
    DIRECTION INPUT ;
    USE SIGNAL ;
    PORT
      LAYER M4 ;
        RECT  0 149.52 0.084 149.544 ;
    END
  END sb_d[128]
  PIN sb_d[129]
    DIRECTION INPUT ;
    USE SIGNAL ;
    PORT
      LAYER M4 ;
        RECT  0 149.856 0.084 149.88 ;
    END
  END sb_d[129]
  PIN sb_d[12]
    DIRECTION INPUT ;
    USE SIGNAL ;
    PORT
      LAYER M4 ;
        RECT  0 110.352 0.084 110.376 ;
    END
  END sb_d[12]
  PIN sb_d[130]
    DIRECTION INPUT ;
    USE SIGNAL ;
    PORT
      LAYER M4 ;
        RECT  0 150.192 0.084 150.216 ;
    END
  END sb_d[130]
  PIN sb_d[131]
    DIRECTION INPUT ;
    USE SIGNAL ;
    PORT
      LAYER M4 ;
        RECT  0 150.528 0.084 150.552 ;
    END
  END sb_d[131]
  PIN sb_d[132]
    DIRECTION INPUT ;
    USE SIGNAL ;
    PORT
      LAYER M4 ;
        RECT  0 150.864 0.084 150.888 ;
    END
  END sb_d[132]
  PIN sb_d[133]
    DIRECTION INPUT ;
    USE SIGNAL ;
    PORT
      LAYER M4 ;
        RECT  0 151.2 0.084 151.224 ;
    END
  END sb_d[133]
  PIN sb_d[134]
    DIRECTION INPUT ;
    USE SIGNAL ;
    PORT
      LAYER M4 ;
        RECT  0 151.584 0.084 151.608 ;
    END
  END sb_d[134]
  PIN sb_d[135]
    DIRECTION INPUT ;
    USE SIGNAL ;
    PORT
      LAYER M4 ;
        RECT  0 151.92 0.084 151.944 ;
    END
  END sb_d[135]
  PIN sb_d[136]
    DIRECTION INPUT ;
    USE SIGNAL ;
    PORT
      LAYER M4 ;
        RECT  0 152.256 0.084 152.28 ;
    END
  END sb_d[136]
  PIN sb_d[137]
    DIRECTION INPUT ;
    USE SIGNAL ;
    PORT
      LAYER M4 ;
        RECT  0 152.592 0.084 152.616 ;
    END
  END sb_d[137]
  PIN sb_d[138]
    DIRECTION INPUT ;
    USE SIGNAL ;
    PORT
      LAYER M4 ;
        RECT  0 152.928 0.084 152.952 ;
    END
  END sb_d[138]
  PIN sb_d[139]
    DIRECTION INPUT ;
    USE SIGNAL ;
    PORT
      LAYER M4 ;
        RECT  0 153.264 0.084 153.288 ;
    END
  END sb_d[139]
  PIN sb_d[13]
    DIRECTION INPUT ;
    USE SIGNAL ;
    PORT
      LAYER M4 ;
        RECT  0 110.688 0.084 110.712 ;
    END
  END sb_d[13]
  PIN sb_d[140]
    DIRECTION INPUT ;
    USE SIGNAL ;
    PORT
      LAYER M4 ;
        RECT  0 153.6 0.084 153.624 ;
    END
  END sb_d[140]
  PIN sb_d[141]
    DIRECTION INPUT ;
    USE SIGNAL ;
    PORT
      LAYER M4 ;
        RECT  0 153.936 0.084 153.96 ;
    END
  END sb_d[141]
  PIN sb_d[142]
    DIRECTION INPUT ;
    USE SIGNAL ;
    PORT
      LAYER M4 ;
        RECT  0 154.272 0.084 154.296 ;
    END
  END sb_d[142]
  PIN sb_d[143]
    DIRECTION INPUT ;
    USE SIGNAL ;
    PORT
      LAYER M4 ;
        RECT  0 154.608 0.084 154.632 ;
    END
  END sb_d[143]
  PIN sb_d[144]
    DIRECTION INPUT ;
    USE SIGNAL ;
    PORT
      LAYER M4 ;
        RECT  0 154.944 0.084 154.968 ;
    END
  END sb_d[144]
  PIN sb_d[145]
    DIRECTION INPUT ;
    USE SIGNAL ;
    PORT
      LAYER M4 ;
        RECT  0 155.28 0.084 155.304 ;
    END
  END sb_d[145]
  PIN sb_d[146]
    DIRECTION INPUT ;
    USE SIGNAL ;
    PORT
      LAYER M4 ;
        RECT  0 155.616 0.084 155.64 ;
    END
  END sb_d[146]
  PIN sb_d[147]
    DIRECTION INPUT ;
    USE SIGNAL ;
    PORT
      LAYER M4 ;
        RECT  0 155.952 0.084 155.976 ;
    END
  END sb_d[147]
  PIN sb_d[148]
    DIRECTION INPUT ;
    USE SIGNAL ;
    PORT
      LAYER M4 ;
        RECT  0 156.288 0.084 156.312 ;
    END
  END sb_d[148]
  PIN sb_d[149]
    DIRECTION INPUT ;
    USE SIGNAL ;
    PORT
      LAYER M4 ;
        RECT  0 156.624 0.084 156.648 ;
    END
  END sb_d[149]
  PIN sb_d[14]
    DIRECTION INPUT ;
    USE SIGNAL ;
    PORT
      LAYER M4 ;
        RECT  0 111.024 0.084 111.048 ;
    END
  END sb_d[14]
  PIN sb_d[150]
    DIRECTION INPUT ;
    USE SIGNAL ;
    PORT
      LAYER M4 ;
        RECT  0 156.96 0.084 156.984 ;
    END
  END sb_d[150]
  PIN sb_d[151]
    DIRECTION INPUT ;
    USE SIGNAL ;
    PORT
      LAYER M4 ;
        RECT  0 157.296 0.084 157.32 ;
    END
  END sb_d[151]
  PIN sb_d[152]
    DIRECTION INPUT ;
    USE SIGNAL ;
    PORT
      LAYER M4 ;
        RECT  0 157.632 0.084 157.656 ;
    END
  END sb_d[152]
  PIN sb_d[153]
    DIRECTION INPUT ;
    USE SIGNAL ;
    PORT
      LAYER M4 ;
        RECT  0 157.968 0.084 157.992 ;
    END
  END sb_d[153]
  PIN sb_d[154]
    DIRECTION INPUT ;
    USE SIGNAL ;
    PORT
      LAYER M4 ;
        RECT  0 158.304 0.084 158.328 ;
    END
  END sb_d[154]
  PIN sb_d[155]
    DIRECTION INPUT ;
    USE SIGNAL ;
    PORT
      LAYER M4 ;
        RECT  0 158.64 0.084 158.664 ;
    END
  END sb_d[155]
  PIN sb_d[156]
    DIRECTION INPUT ;
    USE SIGNAL ;
    PORT
      LAYER M4 ;
        RECT  0 158.976 0.084 159 ;
    END
  END sb_d[156]
  PIN sb_d[157]
    DIRECTION INPUT ;
    USE SIGNAL ;
    PORT
      LAYER M4 ;
        RECT  0 159.312 0.084 159.336 ;
    END
  END sb_d[157]
  PIN sb_d[158]
    DIRECTION INPUT ;
    USE SIGNAL ;
    PORT
      LAYER M4 ;
        RECT  0 159.648 0.084 159.672 ;
    END
  END sb_d[158]
  PIN sb_d[159]
    DIRECTION INPUT ;
    USE SIGNAL ;
    PORT
      LAYER M4 ;
        RECT  0 159.984 0.084 160.008 ;
    END
  END sb_d[159]
  PIN sb_d[15]
    DIRECTION INPUT ;
    USE SIGNAL ;
    PORT
      LAYER M4 ;
        RECT  0 111.36 0.084 111.384 ;
    END
  END sb_d[15]
  PIN sb_d[160]
    DIRECTION INPUT ;
    USE SIGNAL ;
    PORT
      LAYER M4 ;
        RECT  0 160.32 0.084 160.344 ;
    END
  END sb_d[160]
  PIN sb_d[161]
    DIRECTION INPUT ;
    USE SIGNAL ;
    PORT
      LAYER M4 ;
        RECT  0 160.704 0.084 160.728 ;
    END
  END sb_d[161]
  PIN sb_d[162]
    DIRECTION INPUT ;
    USE SIGNAL ;
    PORT
      LAYER M4 ;
        RECT  0 161.04 0.084 161.064 ;
    END
  END sb_d[162]
  PIN sb_d[163]
    DIRECTION INPUT ;
    USE SIGNAL ;
    PORT
      LAYER M4 ;
        RECT  0 161.376 0.084 161.4 ;
    END
  END sb_d[163]
  PIN sb_d[164]
    DIRECTION INPUT ;
    USE SIGNAL ;
    PORT
      LAYER M4 ;
        RECT  0 161.712 0.084 161.736 ;
    END
  END sb_d[164]
  PIN sb_d[165]
    DIRECTION INPUT ;
    USE SIGNAL ;
    PORT
      LAYER M4 ;
        RECT  0 162.048 0.084 162.072 ;
    END
  END sb_d[165]
  PIN sb_d[166]
    DIRECTION INPUT ;
    USE SIGNAL ;
    PORT
      LAYER M4 ;
        RECT  0 162.384 0.084 162.408 ;
    END
  END sb_d[166]
  PIN sb_d[167]
    DIRECTION INPUT ;
    USE SIGNAL ;
    PORT
      LAYER M4 ;
        RECT  0 162.72 0.084 162.744 ;
    END
  END sb_d[167]
  PIN sb_d[168]
    DIRECTION INPUT ;
    USE SIGNAL ;
    PORT
      LAYER M4 ;
        RECT  0 163.056 0.084 163.08 ;
    END
  END sb_d[168]
  PIN sb_d[169]
    DIRECTION INPUT ;
    USE SIGNAL ;
    PORT
      LAYER M4 ;
        RECT  0 163.392 0.084 163.416 ;
    END
  END sb_d[169]
  PIN sb_d[16]
    DIRECTION INPUT ;
    USE SIGNAL ;
    PORT
      LAYER M4 ;
        RECT  0 111.696 0.084 111.72 ;
    END
  END sb_d[16]
  PIN sb_d[170]
    DIRECTION INPUT ;
    USE SIGNAL ;
    PORT
      LAYER M4 ;
        RECT  0 163.728 0.084 163.752 ;
    END
  END sb_d[170]
  PIN sb_d[171]
    DIRECTION INPUT ;
    USE SIGNAL ;
    PORT
      LAYER M4 ;
        RECT  0 164.064 0.084 164.088 ;
    END
  END sb_d[171]
  PIN sb_d[172]
    DIRECTION INPUT ;
    USE SIGNAL ;
    PORT
      LAYER M4 ;
        RECT  0 164.4 0.084 164.424 ;
    END
  END sb_d[172]
  PIN sb_d[173]
    DIRECTION INPUT ;
    USE SIGNAL ;
    PORT
      LAYER M4 ;
        RECT  0 164.736 0.084 164.76 ;
    END
  END sb_d[173]
  PIN sb_d[174]
    DIRECTION INPUT ;
    USE SIGNAL ;
    PORT
      LAYER M4 ;
        RECT  0 165.072 0.084 165.096 ;
    END
  END sb_d[174]
  PIN sb_d[175]
    DIRECTION INPUT ;
    USE SIGNAL ;
    PORT
      LAYER M4 ;
        RECT  0 165.408 0.084 165.432 ;
    END
  END sb_d[175]
  PIN sb_d[176]
    DIRECTION INPUT ;
    USE SIGNAL ;
    PORT
      LAYER M4 ;
        RECT  0 165.744 0.084 165.768 ;
    END
  END sb_d[176]
  PIN sb_d[177]
    DIRECTION INPUT ;
    USE SIGNAL ;
    PORT
      LAYER M4 ;
        RECT  0 166.08 0.084 166.104 ;
    END
  END sb_d[177]
  PIN sb_d[178]
    DIRECTION INPUT ;
    USE SIGNAL ;
    PORT
      LAYER M4 ;
        RECT  0 166.416 0.084 166.44 ;
    END
  END sb_d[178]
  PIN sb_d[179]
    DIRECTION INPUT ;
    USE SIGNAL ;
    PORT
      LAYER M4 ;
        RECT  0 166.752 0.084 166.776 ;
    END
  END sb_d[179]
  PIN sb_d[17]
    DIRECTION INPUT ;
    USE SIGNAL ;
    PORT
      LAYER M4 ;
        RECT  0 112.032 0.084 112.056 ;
    END
  END sb_d[17]
  PIN sb_d[180]
    DIRECTION INPUT ;
    USE SIGNAL ;
    PORT
      LAYER M4 ;
        RECT  0 167.088 0.084 167.112 ;
    END
  END sb_d[180]
  PIN sb_d[181]
    DIRECTION INPUT ;
    USE SIGNAL ;
    PORT
      LAYER M4 ;
        RECT  0 167.424 0.084 167.448 ;
    END
  END sb_d[181]
  PIN sb_d[182]
    DIRECTION INPUT ;
    USE SIGNAL ;
    PORT
      LAYER M4 ;
        RECT  0 167.76 0.084 167.784 ;
    END
  END sb_d[182]
  PIN sb_d[183]
    DIRECTION INPUT ;
    USE SIGNAL ;
    PORT
      LAYER M4 ;
        RECT  0 168.096 0.084 168.12 ;
    END
  END sb_d[183]
  PIN sb_d[184]
    DIRECTION INPUT ;
    USE SIGNAL ;
    PORT
      LAYER M4 ;
        RECT  0 168.432 0.084 168.456 ;
    END
  END sb_d[184]
  PIN sb_d[185]
    DIRECTION INPUT ;
    USE SIGNAL ;
    PORT
      LAYER M4 ;
        RECT  0 168.768 0.084 168.792 ;
    END
  END sb_d[185]
  PIN sb_d[186]
    DIRECTION INPUT ;
    USE SIGNAL ;
    PORT
      LAYER M4 ;
        RECT  0 169.104 0.084 169.128 ;
    END
  END sb_d[186]
  PIN sb_d[187]
    DIRECTION INPUT ;
    USE SIGNAL ;
    PORT
      LAYER M4 ;
        RECT  0 169.44 0.084 169.464 ;
    END
  END sb_d[187]
  PIN sb_d[188]
    DIRECTION INPUT ;
    USE SIGNAL ;
    PORT
      LAYER M4 ;
        RECT  0 169.824 0.084 169.848 ;
    END
  END sb_d[188]
  PIN sb_d[189]
    DIRECTION INPUT ;
    USE SIGNAL ;
    PORT
      LAYER M4 ;
        RECT  0 170.16 0.084 170.184 ;
    END
  END sb_d[189]
  PIN sb_d[18]
    DIRECTION INPUT ;
    USE SIGNAL ;
    PORT
      LAYER M4 ;
        RECT  0 112.368 0.084 112.392 ;
    END
  END sb_d[18]
  PIN sb_d[190]
    DIRECTION INPUT ;
    USE SIGNAL ;
    PORT
      LAYER M4 ;
        RECT  0 170.496 0.084 170.52 ;
    END
  END sb_d[190]
  PIN sb_d[191]
    DIRECTION INPUT ;
    USE SIGNAL ;
    PORT
      LAYER M4 ;
        RECT  0 170.832 0.084 170.856 ;
    END
  END sb_d[191]
  PIN sb_d[192]
    DIRECTION INPUT ;
    USE SIGNAL ;
    PORT
      LAYER M4 ;
        RECT  0 171.168 0.084 171.192 ;
    END
  END sb_d[192]
  PIN sb_d[193]
    DIRECTION INPUT ;
    USE SIGNAL ;
    PORT
      LAYER M4 ;
        RECT  0 171.504 0.084 171.528 ;
    END
  END sb_d[193]
  PIN sb_d[194]
    DIRECTION INPUT ;
    USE SIGNAL ;
    PORT
      LAYER M4 ;
        RECT  0 171.84 0.084 171.864 ;
    END
  END sb_d[194]
  PIN sb_d[195]
    DIRECTION INPUT ;
    USE SIGNAL ;
    PORT
      LAYER M4 ;
        RECT  0 172.176 0.084 172.2 ;
    END
  END sb_d[195]
  PIN sb_d[196]
    DIRECTION INPUT ;
    USE SIGNAL ;
    PORT
      LAYER M4 ;
        RECT  0 172.512 0.084 172.536 ;
    END
  END sb_d[196]
  PIN sb_d[197]
    DIRECTION INPUT ;
    USE SIGNAL ;
    PORT
      LAYER M4 ;
        RECT  0 172.848 0.084 172.872 ;
    END
  END sb_d[197]
  PIN sb_d[198]
    DIRECTION INPUT ;
    USE SIGNAL ;
    PORT
      LAYER M4 ;
        RECT  0 173.184 0.084 173.208 ;
    END
  END sb_d[198]
  PIN sb_d[199]
    DIRECTION INPUT ;
    USE SIGNAL ;
    PORT
      LAYER M4 ;
        RECT  0 173.52 0.084 173.544 ;
    END
  END sb_d[199]
  PIN sb_d[19]
    DIRECTION INPUT ;
    USE SIGNAL ;
    PORT
      LAYER M4 ;
        RECT  0 112.704 0.084 112.728 ;
    END
  END sb_d[19]
  PIN sb_d[1]
    DIRECTION INPUT ;
    USE SIGNAL ;
    PORT
      LAYER M4 ;
        RECT  0 106.656 0.084 106.68 ;
    END
  END sb_d[1]
  PIN sb_d[200]
    DIRECTION INPUT ;
    USE SIGNAL ;
    PORT
      LAYER M4 ;
        RECT  0 173.856 0.084 173.88 ;
    END
  END sb_d[200]
  PIN sb_d[201]
    DIRECTION INPUT ;
    USE SIGNAL ;
    PORT
      LAYER M4 ;
        RECT  0 174.192 0.084 174.216 ;
    END
  END sb_d[201]
  PIN sb_d[202]
    DIRECTION INPUT ;
    USE SIGNAL ;
    PORT
      LAYER M4 ;
        RECT  0 174.528 0.084 174.552 ;
    END
  END sb_d[202]
  PIN sb_d[203]
    DIRECTION INPUT ;
    USE SIGNAL ;
    PORT
      LAYER M4 ;
        RECT  0 174.864 0.084 174.888 ;
    END
  END sb_d[203]
  PIN sb_d[204]
    DIRECTION INPUT ;
    USE SIGNAL ;
    PORT
      LAYER M4 ;
        RECT  0 175.2 0.084 175.224 ;
    END
  END sb_d[204]
  PIN sb_d[205]
    DIRECTION INPUT ;
    USE SIGNAL ;
    PORT
      LAYER M4 ;
        RECT  0 175.536 0.084 175.56 ;
    END
  END sb_d[205]
  PIN sb_d[206]
    DIRECTION INPUT ;
    USE SIGNAL ;
    PORT
      LAYER M4 ;
        RECT  0 175.872 0.084 175.896 ;
    END
  END sb_d[206]
  PIN sb_d[207]
    DIRECTION INPUT ;
    USE SIGNAL ;
    PORT
      LAYER M4 ;
        RECT  0 176.208 0.084 176.232 ;
    END
  END sb_d[207]
  PIN sb_d[208]
    DIRECTION INPUT ;
    USE SIGNAL ;
    PORT
      LAYER M4 ;
        RECT  0 176.544 0.084 176.568 ;
    END
  END sb_d[208]
  PIN sb_d[209]
    DIRECTION INPUT ;
    USE SIGNAL ;
    PORT
      LAYER M4 ;
        RECT  0 176.88 0.084 176.904 ;
    END
  END sb_d[209]
  PIN sb_d[20]
    DIRECTION INPUT ;
    USE SIGNAL ;
    PORT
      LAYER M4 ;
        RECT  0 113.04 0.084 113.064 ;
    END
  END sb_d[20]
  PIN sb_d[210]
    DIRECTION INPUT ;
    USE SIGNAL ;
    PORT
      LAYER M4 ;
        RECT  0 177.216 0.084 177.24 ;
    END
  END sb_d[210]
  PIN sb_d[211]
    DIRECTION INPUT ;
    USE SIGNAL ;
    PORT
      LAYER M4 ;
        RECT  0 177.552 0.084 177.576 ;
    END
  END sb_d[211]
  PIN sb_d[212]
    DIRECTION INPUT ;
    USE SIGNAL ;
    PORT
      LAYER M4 ;
        RECT  0 177.888 0.084 177.912 ;
    END
  END sb_d[212]
  PIN sb_d[213]
    DIRECTION INPUT ;
    USE SIGNAL ;
    PORT
      LAYER M4 ;
        RECT  0 178.224 0.084 178.248 ;
    END
  END sb_d[213]
  PIN sb_d[214]
    DIRECTION INPUT ;
    USE SIGNAL ;
    PORT
      LAYER M4 ;
        RECT  0 178.56 0.084 178.584 ;
    END
  END sb_d[214]
  PIN sb_d[215]
    DIRECTION INPUT ;
    USE SIGNAL ;
    PORT
      LAYER M4 ;
        RECT  0 178.944 0.084 178.968 ;
    END
  END sb_d[215]
  PIN sb_d[216]
    DIRECTION INPUT ;
    USE SIGNAL ;
    PORT
      LAYER M4 ;
        RECT  0 179.28 0.084 179.304 ;
    END
  END sb_d[216]
  PIN sb_d[217]
    DIRECTION INPUT ;
    USE SIGNAL ;
    PORT
      LAYER M4 ;
        RECT  0 179.616 0.084 179.64 ;
    END
  END sb_d[217]
  PIN sb_d[218]
    DIRECTION INPUT ;
    USE SIGNAL ;
    PORT
      LAYER M4 ;
        RECT  0 179.952 0.084 179.976 ;
    END
  END sb_d[218]
  PIN sb_d[219]
    DIRECTION INPUT ;
    USE SIGNAL ;
    PORT
      LAYER M4 ;
        RECT  0 180.288 0.084 180.312 ;
    END
  END sb_d[219]
  PIN sb_d[21]
    DIRECTION INPUT ;
    USE SIGNAL ;
    PORT
      LAYER M4 ;
        RECT  0 113.376 0.084 113.4 ;
    END
  END sb_d[21]
  PIN sb_d[220]
    DIRECTION INPUT ;
    USE SIGNAL ;
    PORT
      LAYER M4 ;
        RECT  0 180.624 0.084 180.648 ;
    END
  END sb_d[220]
  PIN sb_d[221]
    DIRECTION INPUT ;
    USE SIGNAL ;
    PORT
      LAYER M4 ;
        RECT  0 180.96 0.084 180.984 ;
    END
  END sb_d[221]
  PIN sb_d[222]
    DIRECTION INPUT ;
    USE SIGNAL ;
    PORT
      LAYER M4 ;
        RECT  0 181.296 0.084 181.32 ;
    END
  END sb_d[222]
  PIN sb_d[223]
    DIRECTION INPUT ;
    USE SIGNAL ;
    PORT
      LAYER M4 ;
        RECT  0 181.632 0.084 181.656 ;
    END
  END sb_d[223]
  PIN sb_d[22]
    DIRECTION INPUT ;
    USE SIGNAL ;
    PORT
      LAYER M4 ;
        RECT  0 113.712 0.084 113.736 ;
    END
  END sb_d[22]
  PIN sb_d[23]
    DIRECTION INPUT ;
    USE SIGNAL ;
    PORT
      LAYER M4 ;
        RECT  0 114.048 0.084 114.072 ;
    END
  END sb_d[23]
  PIN sb_d[24]
    DIRECTION INPUT ;
    USE SIGNAL ;
    PORT
      LAYER M4 ;
        RECT  0 114.384 0.084 114.408 ;
    END
  END sb_d[24]
  PIN sb_d[25]
    DIRECTION INPUT ;
    USE SIGNAL ;
    PORT
      LAYER M4 ;
        RECT  0 114.72 0.084 114.744 ;
    END
  END sb_d[25]
  PIN sb_d[26]
    DIRECTION INPUT ;
    USE SIGNAL ;
    PORT
      LAYER M4 ;
        RECT  0 115.104 0.084 115.128 ;
    END
  END sb_d[26]
  PIN sb_d[27]
    DIRECTION INPUT ;
    USE SIGNAL ;
    PORT
      LAYER M4 ;
        RECT  0 115.44 0.084 115.464 ;
    END
  END sb_d[27]
  PIN sb_d[28]
    DIRECTION INPUT ;
    USE SIGNAL ;
    PORT
      LAYER M4 ;
        RECT  0 115.776 0.084 115.8 ;
    END
  END sb_d[28]
  PIN sb_d[29]
    DIRECTION INPUT ;
    USE SIGNAL ;
    PORT
      LAYER M4 ;
        RECT  0 116.112 0.084 116.136 ;
    END
  END sb_d[29]
  PIN sb_d[2]
    DIRECTION INPUT ;
    USE SIGNAL ;
    PORT
      LAYER M4 ;
        RECT  0 106.992 0.084 107.016 ;
    END
  END sb_d[2]
  PIN sb_d[30]
    DIRECTION INPUT ;
    USE SIGNAL ;
    PORT
      LAYER M4 ;
        RECT  0 116.448 0.084 116.472 ;
    END
  END sb_d[30]
  PIN sb_d[31]
    DIRECTION INPUT ;
    USE SIGNAL ;
    PORT
      LAYER M4 ;
        RECT  0 116.784 0.084 116.808 ;
    END
  END sb_d[31]
  PIN sb_d[32]
    DIRECTION INPUT ;
    USE SIGNAL ;
    PORT
      LAYER M4 ;
        RECT  0 117.12 0.084 117.144 ;
    END
  END sb_d[32]
  PIN sb_d[33]
    DIRECTION INPUT ;
    USE SIGNAL ;
    PORT
      LAYER M4 ;
        RECT  0 117.456 0.084 117.48 ;
    END
  END sb_d[33]
  PIN sb_d[34]
    DIRECTION INPUT ;
    USE SIGNAL ;
    PORT
      LAYER M4 ;
        RECT  0 117.792 0.084 117.816 ;
    END
  END sb_d[34]
  PIN sb_d[35]
    DIRECTION INPUT ;
    USE SIGNAL ;
    PORT
      LAYER M4 ;
        RECT  0 118.128 0.084 118.152 ;
    END
  END sb_d[35]
  PIN sb_d[36]
    DIRECTION INPUT ;
    USE SIGNAL ;
    PORT
      LAYER M4 ;
        RECT  0 118.464 0.084 118.488 ;
    END
  END sb_d[36]
  PIN sb_d[37]
    DIRECTION INPUT ;
    USE SIGNAL ;
    PORT
      LAYER M4 ;
        RECT  0 118.8 0.084 118.824 ;
    END
  END sb_d[37]
  PIN sb_d[38]
    DIRECTION INPUT ;
    USE SIGNAL ;
    PORT
      LAYER M4 ;
        RECT  0 119.136 0.084 119.16 ;
    END
  END sb_d[38]
  PIN sb_d[39]
    DIRECTION INPUT ;
    USE SIGNAL ;
    PORT
      LAYER M4 ;
        RECT  0 119.472 0.084 119.496 ;
    END
  END sb_d[39]
  PIN sb_d[3]
    DIRECTION INPUT ;
    USE SIGNAL ;
    PORT
      LAYER M4 ;
        RECT  0 107.328 0.084 107.352 ;
    END
  END sb_d[3]
  PIN sb_d[40]
    DIRECTION INPUT ;
    USE SIGNAL ;
    PORT
      LAYER M4 ;
        RECT  0 119.808 0.084 119.832 ;
    END
  END sb_d[40]
  PIN sb_d[41]
    DIRECTION INPUT ;
    USE SIGNAL ;
    PORT
      LAYER M4 ;
        RECT  0 120.144 0.084 120.168 ;
    END
  END sb_d[41]
  PIN sb_d[42]
    DIRECTION INPUT ;
    USE SIGNAL ;
    PORT
      LAYER M4 ;
        RECT  0 120.48 0.084 120.504 ;
    END
  END sb_d[42]
  PIN sb_d[43]
    DIRECTION INPUT ;
    USE SIGNAL ;
    PORT
      LAYER M4 ;
        RECT  0 120.816 0.084 120.84 ;
    END
  END sb_d[43]
  PIN sb_d[44]
    DIRECTION INPUT ;
    USE SIGNAL ;
    PORT
      LAYER M4 ;
        RECT  0 121.152 0.084 121.176 ;
    END
  END sb_d[44]
  PIN sb_d[45]
    DIRECTION INPUT ;
    USE SIGNAL ;
    PORT
      LAYER M4 ;
        RECT  0 121.488 0.084 121.512 ;
    END
  END sb_d[45]
  PIN sb_d[46]
    DIRECTION INPUT ;
    USE SIGNAL ;
    PORT
      LAYER M4 ;
        RECT  0 121.824 0.084 121.848 ;
    END
  END sb_d[46]
  PIN sb_d[47]
    DIRECTION INPUT ;
    USE SIGNAL ;
    PORT
      LAYER M4 ;
        RECT  0 122.16 0.084 122.184 ;
    END
  END sb_d[47]
  PIN sb_d[48]
    DIRECTION INPUT ;
    USE SIGNAL ;
    PORT
      LAYER M4 ;
        RECT  0 122.496 0.084 122.52 ;
    END
  END sb_d[48]
  PIN sb_d[49]
    DIRECTION INPUT ;
    USE SIGNAL ;
    PORT
      LAYER M4 ;
        RECT  0 122.832 0.084 122.856 ;
    END
  END sb_d[49]
  PIN sb_d[4]
    DIRECTION INPUT ;
    USE SIGNAL ;
    PORT
      LAYER M4 ;
        RECT  0 107.664 0.084 107.688 ;
    END
  END sb_d[4]
  PIN sb_d[50]
    DIRECTION INPUT ;
    USE SIGNAL ;
    PORT
      LAYER M4 ;
        RECT  0 123.168 0.084 123.192 ;
    END
  END sb_d[50]
  PIN sb_d[51]
    DIRECTION INPUT ;
    USE SIGNAL ;
    PORT
      LAYER M4 ;
        RECT  0 123.504 0.084 123.528 ;
    END
  END sb_d[51]
  PIN sb_d[52]
    DIRECTION INPUT ;
    USE SIGNAL ;
    PORT
      LAYER M4 ;
        RECT  0 123.84 0.084 123.864 ;
    END
  END sb_d[52]
  PIN sb_d[53]
    DIRECTION INPUT ;
    USE SIGNAL ;
    PORT
      LAYER M4 ;
        RECT  0 124.224 0.084 124.248 ;
    END
  END sb_d[53]
  PIN sb_d[54]
    DIRECTION INPUT ;
    USE SIGNAL ;
    PORT
      LAYER M4 ;
        RECT  0 124.56 0.084 124.584 ;
    END
  END sb_d[54]
  PIN sb_d[55]
    DIRECTION INPUT ;
    USE SIGNAL ;
    PORT
      LAYER M4 ;
        RECT  0 124.896 0.084 124.92 ;
    END
  END sb_d[55]
  PIN sb_d[56]
    DIRECTION INPUT ;
    USE SIGNAL ;
    PORT
      LAYER M4 ;
        RECT  0 125.232 0.084 125.256 ;
    END
  END sb_d[56]
  PIN sb_d[57]
    DIRECTION INPUT ;
    USE SIGNAL ;
    PORT
      LAYER M4 ;
        RECT  0 125.568 0.084 125.592 ;
    END
  END sb_d[57]
  PIN sb_d[58]
    DIRECTION INPUT ;
    USE SIGNAL ;
    PORT
      LAYER M4 ;
        RECT  0 125.904 0.084 125.928 ;
    END
  END sb_d[58]
  PIN sb_d[59]
    DIRECTION INPUT ;
    USE SIGNAL ;
    PORT
      LAYER M4 ;
        RECT  0 126.24 0.084 126.264 ;
    END
  END sb_d[59]
  PIN sb_d[5]
    DIRECTION INPUT ;
    USE SIGNAL ;
    PORT
      LAYER M4 ;
        RECT  0 108 0.084 108.024 ;
    END
  END sb_d[5]
  PIN sb_d[60]
    DIRECTION INPUT ;
    USE SIGNAL ;
    PORT
      LAYER M4 ;
        RECT  0 126.576 0.084 126.6 ;
    END
  END sb_d[60]
  PIN sb_d[61]
    DIRECTION INPUT ;
    USE SIGNAL ;
    PORT
      LAYER M4 ;
        RECT  0 126.912 0.084 126.936 ;
    END
  END sb_d[61]
  PIN sb_d[62]
    DIRECTION INPUT ;
    USE SIGNAL ;
    PORT
      LAYER M4 ;
        RECT  0 127.248 0.084 127.272 ;
    END
  END sb_d[62]
  PIN sb_d[63]
    DIRECTION INPUT ;
    USE SIGNAL ;
    PORT
      LAYER M4 ;
        RECT  0 127.584 0.084 127.608 ;
    END
  END sb_d[63]
  PIN sb_d[64]
    DIRECTION INPUT ;
    USE SIGNAL ;
    PORT
      LAYER M4 ;
        RECT  0 127.92 0.084 127.944 ;
    END
  END sb_d[64]
  PIN sb_d[65]
    DIRECTION INPUT ;
    USE SIGNAL ;
    PORT
      LAYER M4 ;
        RECT  0 128.256 0.084 128.28 ;
    END
  END sb_d[65]
  PIN sb_d[66]
    DIRECTION INPUT ;
    USE SIGNAL ;
    PORT
      LAYER M4 ;
        RECT  0 128.592 0.084 128.616 ;
    END
  END sb_d[66]
  PIN sb_d[67]
    DIRECTION INPUT ;
    USE SIGNAL ;
    PORT
      LAYER M4 ;
        RECT  0 128.928 0.084 128.952 ;
    END
  END sb_d[67]
  PIN sb_d[68]
    DIRECTION INPUT ;
    USE SIGNAL ;
    PORT
      LAYER M4 ;
        RECT  0 129.264 0.084 129.288 ;
    END
  END sb_d[68]
  PIN sb_d[69]
    DIRECTION INPUT ;
    USE SIGNAL ;
    PORT
      LAYER M4 ;
        RECT  0 129.6 0.084 129.624 ;
    END
  END sb_d[69]
  PIN sb_d[6]
    DIRECTION INPUT ;
    USE SIGNAL ;
    PORT
      LAYER M4 ;
        RECT  0 108.336 0.084 108.36 ;
    END
  END sb_d[6]
  PIN sb_d[70]
    DIRECTION INPUT ;
    USE SIGNAL ;
    PORT
      LAYER M4 ;
        RECT  0 129.936 0.084 129.96 ;
    END
  END sb_d[70]
  PIN sb_d[71]
    DIRECTION INPUT ;
    USE SIGNAL ;
    PORT
      LAYER M4 ;
        RECT  0 130.272 0.084 130.296 ;
    END
  END sb_d[71]
  PIN sb_d[72]
    DIRECTION INPUT ;
    USE SIGNAL ;
    PORT
      LAYER M4 ;
        RECT  0 130.608 0.084 130.632 ;
    END
  END sb_d[72]
  PIN sb_d[73]
    DIRECTION INPUT ;
    USE SIGNAL ;
    PORT
      LAYER M4 ;
        RECT  0 130.944 0.084 130.968 ;
    END
  END sb_d[73]
  PIN sb_d[74]
    DIRECTION INPUT ;
    USE SIGNAL ;
    PORT
      LAYER M4 ;
        RECT  0 131.28 0.084 131.304 ;
    END
  END sb_d[74]
  PIN sb_d[75]
    DIRECTION INPUT ;
    USE SIGNAL ;
    PORT
      LAYER M4 ;
        RECT  0 131.616 0.084 131.64 ;
    END
  END sb_d[75]
  PIN sb_d[76]
    DIRECTION INPUT ;
    USE SIGNAL ;
    PORT
      LAYER M4 ;
        RECT  0 131.952 0.084 131.976 ;
    END
  END sb_d[76]
  PIN sb_d[77]
    DIRECTION INPUT ;
    USE SIGNAL ;
    PORT
      LAYER M4 ;
        RECT  0 132.288 0.084 132.312 ;
    END
  END sb_d[77]
  PIN sb_d[78]
    DIRECTION INPUT ;
    USE SIGNAL ;
    PORT
      LAYER M4 ;
        RECT  0 132.624 0.084 132.648 ;
    END
  END sb_d[78]
  PIN sb_d[79]
    DIRECTION INPUT ;
    USE SIGNAL ;
    PORT
      LAYER M4 ;
        RECT  0 132.96 0.084 132.984 ;
    END
  END sb_d[79]
  PIN sb_d[7]
    DIRECTION INPUT ;
    USE SIGNAL ;
    PORT
      LAYER M4 ;
        RECT  0 108.672 0.084 108.696 ;
    END
  END sb_d[7]
  PIN sb_d[80]
    DIRECTION INPUT ;
    USE SIGNAL ;
    PORT
      LAYER M4 ;
        RECT  0 133.344 0.084 133.368 ;
    END
  END sb_d[80]
  PIN sb_d[81]
    DIRECTION INPUT ;
    USE SIGNAL ;
    PORT
      LAYER M4 ;
        RECT  0 133.68 0.084 133.704 ;
    END
  END sb_d[81]
  PIN sb_d[82]
    DIRECTION INPUT ;
    USE SIGNAL ;
    PORT
      LAYER M4 ;
        RECT  0 134.016 0.084 134.04 ;
    END
  END sb_d[82]
  PIN sb_d[83]
    DIRECTION INPUT ;
    USE SIGNAL ;
    PORT
      LAYER M4 ;
        RECT  0 134.352 0.084 134.376 ;
    END
  END sb_d[83]
  PIN sb_d[84]
    DIRECTION INPUT ;
    USE SIGNAL ;
    PORT
      LAYER M4 ;
        RECT  0 134.688 0.084 134.712 ;
    END
  END sb_d[84]
  PIN sb_d[85]
    DIRECTION INPUT ;
    USE SIGNAL ;
    PORT
      LAYER M4 ;
        RECT  0 135.024 0.084 135.048 ;
    END
  END sb_d[85]
  PIN sb_d[86]
    DIRECTION INPUT ;
    USE SIGNAL ;
    PORT
      LAYER M4 ;
        RECT  0 135.36 0.084 135.384 ;
    END
  END sb_d[86]
  PIN sb_d[87]
    DIRECTION INPUT ;
    USE SIGNAL ;
    PORT
      LAYER M4 ;
        RECT  0 135.696 0.084 135.72 ;
    END
  END sb_d[87]
  PIN sb_d[88]
    DIRECTION INPUT ;
    USE SIGNAL ;
    PORT
      LAYER M4 ;
        RECT  0 136.032 0.084 136.056 ;
    END
  END sb_d[88]
  PIN sb_d[89]
    DIRECTION INPUT ;
    USE SIGNAL ;
    PORT
      LAYER M4 ;
        RECT  0 136.368 0.084 136.392 ;
    END
  END sb_d[89]
  PIN sb_d[8]
    DIRECTION INPUT ;
    USE SIGNAL ;
    PORT
      LAYER M4 ;
        RECT  0 109.008 0.084 109.032 ;
    END
  END sb_d[8]
  PIN sb_d[90]
    DIRECTION INPUT ;
    USE SIGNAL ;
    PORT
      LAYER M4 ;
        RECT  0 136.704 0.084 136.728 ;
    END
  END sb_d[90]
  PIN sb_d[91]
    DIRECTION INPUT ;
    USE SIGNAL ;
    PORT
      LAYER M4 ;
        RECT  0 137.04 0.084 137.064 ;
    END
  END sb_d[91]
  PIN sb_d[92]
    DIRECTION INPUT ;
    USE SIGNAL ;
    PORT
      LAYER M4 ;
        RECT  0 137.376 0.084 137.4 ;
    END
  END sb_d[92]
  PIN sb_d[93]
    DIRECTION INPUT ;
    USE SIGNAL ;
    PORT
      LAYER M4 ;
        RECT  0 137.712 0.084 137.736 ;
    END
  END sb_d[93]
  PIN sb_d[94]
    DIRECTION INPUT ;
    USE SIGNAL ;
    PORT
      LAYER M4 ;
        RECT  0 138.048 0.084 138.072 ;
    END
  END sb_d[94]
  PIN sb_d[95]
    DIRECTION INPUT ;
    USE SIGNAL ;
    PORT
      LAYER M4 ;
        RECT  0 138.384 0.084 138.408 ;
    END
  END sb_d[95]
  PIN sb_d[96]
    DIRECTION INPUT ;
    USE SIGNAL ;
    PORT
      LAYER M4 ;
        RECT  0 138.72 0.084 138.744 ;
    END
  END sb_d[96]
  PIN sb_d[97]
    DIRECTION INPUT ;
    USE SIGNAL ;
    PORT
      LAYER M4 ;
        RECT  0 139.056 0.084 139.08 ;
    END
  END sb_d[97]
  PIN sb_d[98]
    DIRECTION INPUT ;
    USE SIGNAL ;
    PORT
      LAYER M4 ;
        RECT  0 139.392 0.084 139.416 ;
    END
  END sb_d[98]
  PIN sb_d[99]
    DIRECTION INPUT ;
    USE SIGNAL ;
    PORT
      LAYER M4 ;
        RECT  0 139.728 0.084 139.752 ;
    END
  END sb_d[99]
  PIN sb_d[9]
    DIRECTION INPUT ;
    USE SIGNAL ;
    PORT
      LAYER M4 ;
        RECT  0 109.344 0.084 109.368 ;
    END
  END sb_d[9]
  PIN sb_r[0]
    DIRECTION INPUT ;
    USE SIGNAL ;
    PORT
      LAYER M4 ;
        RECT  0 104.256 0.084 104.28 ;
    END
  END sb_r[0]
  PIN sb_r[1]
    DIRECTION INPUT ;
    USE SIGNAL ;
    PORT
      LAYER M4 ;
        RECT  0 104.592 0.084 104.616 ;
    END
  END sb_r[1]
  PIN sb_r[2]
    DIRECTION INPUT ;
    USE SIGNAL ;
    PORT
      LAYER M4 ;
        RECT  0 104.928 0.084 104.952 ;
    END
  END sb_r[2]
  PIN sb_r[3]
    DIRECTION INPUT ;
    USE SIGNAL ;
    PORT
      LAYER M4 ;
        RECT  0 105.264 0.084 105.288 ;
    END
  END sb_r[3]
  PIN sb_r[4]
    DIRECTION INPUT ;
    USE SIGNAL ;
    PORT
      LAYER M4 ;
        RECT  0 105.6 0.084 105.624 ;
    END
  END sb_r[4]
  PIN sb_r[5]
    DIRECTION INPUT ;
    USE SIGNAL ;
    PORT
      LAYER M4 ;
        RECT  0 105.984 0.084 106.008 ;
    END
  END sb_r[5]
  PIN sf0[0]
    DIRECTION INPUT ;
    USE SIGNAL ;
    PORT
      LAYER M5 ;
        RECT  86.4 0 86.424 0.084 ;
    END
  END sf0[0]
  PIN sf0[1]
    DIRECTION INPUT ;
    USE SIGNAL ;
    PORT
      LAYER M5 ;
        RECT  216 0 216.024 0.084 ;
    END
  END sf0[1]
  PIN sf0[2]
    DIRECTION INPUT ;
    USE SIGNAL ;
    PORT
      LAYER M5 ;
        RECT  345.6 0 345.624 0.084 ;
    END
  END sf0[2]
  PIN sv_hi[0]
    DIRECTION OUTPUT ;
    USE SIGNAL ;
    PORT
      LAYER M5 ;
        RECT  22.368 215.916 22.392 216 ;
    END
  END sv_hi[0]
  PIN sv_hi[100]
    DIRECTION OUTPUT ;
    USE SIGNAL ;
    PORT
      LAYER M5 ;
        RECT  174.24 215.916 174.264 216 ;
    END
  END sv_hi[100]
  PIN sv_hi[101]
    DIRECTION OUTPUT ;
    USE SIGNAL ;
    PORT
      LAYER M5 ;
        RECT  175.728 215.916 175.752 216 ;
    END
  END sv_hi[101]
  PIN sv_hi[102]
    DIRECTION OUTPUT ;
    USE SIGNAL ;
    PORT
      LAYER M5 ;
        RECT  177.264 215.916 177.288 216 ;
    END
  END sv_hi[102]
  PIN sv_hi[103]
    DIRECTION OUTPUT ;
    USE SIGNAL ;
    PORT
      LAYER M5 ;
        RECT  178.8 215.916 178.824 216 ;
    END
  END sv_hi[103]
  PIN sv_hi[104]
    DIRECTION OUTPUT ;
    USE SIGNAL ;
    PORT
      LAYER M5 ;
        RECT  180.288 215.916 180.312 216 ;
    END
  END sv_hi[104]
  PIN sv_hi[105]
    DIRECTION OUTPUT ;
    USE SIGNAL ;
    PORT
      LAYER M5 ;
        RECT  181.824 215.916 181.848 216 ;
    END
  END sv_hi[105]
  PIN sv_hi[106]
    DIRECTION OUTPUT ;
    USE SIGNAL ;
    PORT
      LAYER M5 ;
        RECT  183.312 215.916 183.336 216 ;
    END
  END sv_hi[106]
  PIN sv_hi[107]
    DIRECTION OUTPUT ;
    USE SIGNAL ;
    PORT
      LAYER M5 ;
        RECT  184.848 215.916 184.872 216 ;
    END
  END sv_hi[107]
  PIN sv_hi[108]
    DIRECTION OUTPUT ;
    USE SIGNAL ;
    PORT
      LAYER M5 ;
        RECT  186.384 215.916 186.408 216 ;
    END
  END sv_hi[108]
  PIN sv_hi[109]
    DIRECTION OUTPUT ;
    USE SIGNAL ;
    PORT
      LAYER M5 ;
        RECT  187.872 215.916 187.896 216 ;
    END
  END sv_hi[109]
  PIN sv_hi[10]
    DIRECTION OUTPUT ;
    USE SIGNAL ;
    PORT
      LAYER M5 ;
        RECT  37.536 215.916 37.56 216 ;
    END
  END sv_hi[10]
  PIN sv_hi[110]
    DIRECTION OUTPUT ;
    USE SIGNAL ;
    PORT
      LAYER M5 ;
        RECT  189.408 215.916 189.432 216 ;
    END
  END sv_hi[110]
  PIN sv_hi[111]
    DIRECTION OUTPUT ;
    USE SIGNAL ;
    PORT
      LAYER M5 ;
        RECT  190.944 215.916 190.968 216 ;
    END
  END sv_hi[111]
  PIN sv_hi[112]
    DIRECTION OUTPUT ;
    USE SIGNAL ;
    PORT
      LAYER M5 ;
        RECT  192.432 215.916 192.456 216 ;
    END
  END sv_hi[112]
  PIN sv_hi[113]
    DIRECTION OUTPUT ;
    USE SIGNAL ;
    PORT
      LAYER M5 ;
        RECT  193.968 215.916 193.992 216 ;
    END
  END sv_hi[113]
  PIN sv_hi[114]
    DIRECTION OUTPUT ;
    USE SIGNAL ;
    PORT
      LAYER M5 ;
        RECT  195.504 215.916 195.528 216 ;
    END
  END sv_hi[114]
  PIN sv_hi[115]
    DIRECTION OUTPUT ;
    USE SIGNAL ;
    PORT
      LAYER M5 ;
        RECT  196.992 215.916 197.016 216 ;
    END
  END sv_hi[115]
  PIN sv_hi[116]
    DIRECTION OUTPUT ;
    USE SIGNAL ;
    PORT
      LAYER M5 ;
        RECT  198.528 215.916 198.552 216 ;
    END
  END sv_hi[116]
  PIN sv_hi[117]
    DIRECTION OUTPUT ;
    USE SIGNAL ;
    PORT
      LAYER M5 ;
        RECT  200.064 215.916 200.088 216 ;
    END
  END sv_hi[117]
  PIN sv_hi[118]
    DIRECTION OUTPUT ;
    USE SIGNAL ;
    PORT
      LAYER M5 ;
        RECT  201.552 215.916 201.576 216 ;
    END
  END sv_hi[118]
  PIN sv_hi[119]
    DIRECTION OUTPUT ;
    USE SIGNAL ;
    PORT
      LAYER M5 ;
        RECT  203.088 215.916 203.112 216 ;
    END
  END sv_hi[119]
  PIN sv_hi[11]
    DIRECTION OUTPUT ;
    USE SIGNAL ;
    PORT
      LAYER M5 ;
        RECT  39.072 215.916 39.096 216 ;
    END
  END sv_hi[11]
  PIN sv_hi[120]
    DIRECTION OUTPUT ;
    USE SIGNAL ;
    PORT
      LAYER M5 ;
        RECT  204.576 215.916 204.6 216 ;
    END
  END sv_hi[120]
  PIN sv_hi[121]
    DIRECTION OUTPUT ;
    USE SIGNAL ;
    PORT
      LAYER M5 ;
        RECT  206.112 215.916 206.136 216 ;
    END
  END sv_hi[121]
  PIN sv_hi[122]
    DIRECTION OUTPUT ;
    USE SIGNAL ;
    PORT
      LAYER M5 ;
        RECT  207.648 215.916 207.672 216 ;
    END
  END sv_hi[122]
  PIN sv_hi[123]
    DIRECTION OUTPUT ;
    USE SIGNAL ;
    PORT
      LAYER M5 ;
        RECT  209.136 215.916 209.16 216 ;
    END
  END sv_hi[123]
  PIN sv_hi[124]
    DIRECTION OUTPUT ;
    USE SIGNAL ;
    PORT
      LAYER M5 ;
        RECT  210.672 215.916 210.696 216 ;
    END
  END sv_hi[124]
  PIN sv_hi[125]
    DIRECTION OUTPUT ;
    USE SIGNAL ;
    PORT
      LAYER M5 ;
        RECT  212.208 215.916 212.232 216 ;
    END
  END sv_hi[125]
  PIN sv_hi[126]
    DIRECTION OUTPUT ;
    USE SIGNAL ;
    PORT
      LAYER M5 ;
        RECT  213.696 215.916 213.72 216 ;
    END
  END sv_hi[126]
  PIN sv_hi[127]
    DIRECTION OUTPUT ;
    USE SIGNAL ;
    PORT
      LAYER M5 ;
        RECT  215.232 215.916 215.256 216 ;
    END
  END sv_hi[127]
  PIN sv_hi[128]
    DIRECTION OUTPUT ;
    USE SIGNAL ;
    PORT
      LAYER M5 ;
        RECT  216.768 215.916 216.792 216 ;
    END
  END sv_hi[128]
  PIN sv_hi[129]
    DIRECTION OUTPUT ;
    USE SIGNAL ;
    PORT
      LAYER M5 ;
        RECT  218.256 215.916 218.28 216 ;
    END
  END sv_hi[129]
  PIN sv_hi[12]
    DIRECTION OUTPUT ;
    USE SIGNAL ;
    PORT
      LAYER M5 ;
        RECT  40.56 215.916 40.584 216 ;
    END
  END sv_hi[12]
  PIN sv_hi[130]
    DIRECTION OUTPUT ;
    USE SIGNAL ;
    PORT
      LAYER M5 ;
        RECT  219.792 215.916 219.816 216 ;
    END
  END sv_hi[130]
  PIN sv_hi[131]
    DIRECTION OUTPUT ;
    USE SIGNAL ;
    PORT
      LAYER M5 ;
        RECT  221.328 215.916 221.352 216 ;
    END
  END sv_hi[131]
  PIN sv_hi[132]
    DIRECTION OUTPUT ;
    USE SIGNAL ;
    PORT
      LAYER M5 ;
        RECT  222.816 215.916 222.84 216 ;
    END
  END sv_hi[132]
  PIN sv_hi[133]
    DIRECTION OUTPUT ;
    USE SIGNAL ;
    PORT
      LAYER M5 ;
        RECT  224.352 215.916 224.376 216 ;
    END
  END sv_hi[133]
  PIN sv_hi[134]
    DIRECTION OUTPUT ;
    USE SIGNAL ;
    PORT
      LAYER M5 ;
        RECT  225.84 215.916 225.864 216 ;
    END
  END sv_hi[134]
  PIN sv_hi[135]
    DIRECTION OUTPUT ;
    USE SIGNAL ;
    PORT
      LAYER M5 ;
        RECT  227.376 215.916 227.4 216 ;
    END
  END sv_hi[135]
  PIN sv_hi[136]
    DIRECTION OUTPUT ;
    USE SIGNAL ;
    PORT
      LAYER M5 ;
        RECT  228.912 215.916 228.936 216 ;
    END
  END sv_hi[136]
  PIN sv_hi[137]
    DIRECTION OUTPUT ;
    USE SIGNAL ;
    PORT
      LAYER M5 ;
        RECT  230.4 215.916 230.424 216 ;
    END
  END sv_hi[137]
  PIN sv_hi[138]
    DIRECTION OUTPUT ;
    USE SIGNAL ;
    PORT
      LAYER M5 ;
        RECT  231.936 215.916 231.96 216 ;
    END
  END sv_hi[138]
  PIN sv_hi[139]
    DIRECTION OUTPUT ;
    USE SIGNAL ;
    PORT
      LAYER M5 ;
        RECT  233.472 215.916 233.496 216 ;
    END
  END sv_hi[139]
  PIN sv_hi[13]
    DIRECTION OUTPUT ;
    USE SIGNAL ;
    PORT
      LAYER M5 ;
        RECT  42.096 215.916 42.12 216 ;
    END
  END sv_hi[13]
  PIN sv_hi[140]
    DIRECTION OUTPUT ;
    USE SIGNAL ;
    PORT
      LAYER M5 ;
        RECT  234.96 215.916 234.984 216 ;
    END
  END sv_hi[140]
  PIN sv_hi[141]
    DIRECTION OUTPUT ;
    USE SIGNAL ;
    PORT
      LAYER M5 ;
        RECT  236.496 215.916 236.52 216 ;
    END
  END sv_hi[141]
  PIN sv_hi[142]
    DIRECTION OUTPUT ;
    USE SIGNAL ;
    PORT
      LAYER M5 ;
        RECT  238.032 215.916 238.056 216 ;
    END
  END sv_hi[142]
  PIN sv_hi[143]
    DIRECTION OUTPUT ;
    USE SIGNAL ;
    PORT
      LAYER M5 ;
        RECT  239.52 215.916 239.544 216 ;
    END
  END sv_hi[143]
  PIN sv_hi[144]
    DIRECTION OUTPUT ;
    USE SIGNAL ;
    PORT
      LAYER M5 ;
        RECT  241.056 215.916 241.08 216 ;
    END
  END sv_hi[144]
  PIN sv_hi[145]
    DIRECTION OUTPUT ;
    USE SIGNAL ;
    PORT
      LAYER M5 ;
        RECT  242.544 215.916 242.568 216 ;
    END
  END sv_hi[145]
  PIN sv_hi[146]
    DIRECTION OUTPUT ;
    USE SIGNAL ;
    PORT
      LAYER M5 ;
        RECT  244.08 215.916 244.104 216 ;
    END
  END sv_hi[146]
  PIN sv_hi[147]
    DIRECTION OUTPUT ;
    USE SIGNAL ;
    PORT
      LAYER M5 ;
        RECT  245.616 215.916 245.64 216 ;
    END
  END sv_hi[147]
  PIN sv_hi[148]
    DIRECTION OUTPUT ;
    USE SIGNAL ;
    PORT
      LAYER M5 ;
        RECT  247.104 215.916 247.128 216 ;
    END
  END sv_hi[148]
  PIN sv_hi[149]
    DIRECTION OUTPUT ;
    USE SIGNAL ;
    PORT
      LAYER M5 ;
        RECT  248.64 215.916 248.664 216 ;
    END
  END sv_hi[149]
  PIN sv_hi[14]
    DIRECTION OUTPUT ;
    USE SIGNAL ;
    PORT
      LAYER M5 ;
        RECT  43.632 215.916 43.656 216 ;
    END
  END sv_hi[14]
  PIN sv_hi[150]
    DIRECTION OUTPUT ;
    USE SIGNAL ;
    PORT
      LAYER M5 ;
        RECT  250.176 215.916 250.2 216 ;
    END
  END sv_hi[150]
  PIN sv_hi[151]
    DIRECTION OUTPUT ;
    USE SIGNAL ;
    PORT
      LAYER M5 ;
        RECT  251.664 215.916 251.688 216 ;
    END
  END sv_hi[151]
  PIN sv_hi[152]
    DIRECTION OUTPUT ;
    USE SIGNAL ;
    PORT
      LAYER M5 ;
        RECT  253.2 215.916 253.224 216 ;
    END
  END sv_hi[152]
  PIN sv_hi[153]
    DIRECTION OUTPUT ;
    USE SIGNAL ;
    PORT
      LAYER M5 ;
        RECT  254.736 215.916 254.76 216 ;
    END
  END sv_hi[153]
  PIN sv_hi[154]
    DIRECTION OUTPUT ;
    USE SIGNAL ;
    PORT
      LAYER M5 ;
        RECT  256.224 215.916 256.248 216 ;
    END
  END sv_hi[154]
  PIN sv_hi[155]
    DIRECTION OUTPUT ;
    USE SIGNAL ;
    PORT
      LAYER M5 ;
        RECT  257.76 215.916 257.784 216 ;
    END
  END sv_hi[155]
  PIN sv_hi[156]
    DIRECTION OUTPUT ;
    USE SIGNAL ;
    PORT
      LAYER M5 ;
        RECT  259.296 215.916 259.32 216 ;
    END
  END sv_hi[156]
  PIN sv_hi[157]
    DIRECTION OUTPUT ;
    USE SIGNAL ;
    PORT
      LAYER M5 ;
        RECT  260.784 215.916 260.808 216 ;
    END
  END sv_hi[157]
  PIN sv_hi[158]
    DIRECTION OUTPUT ;
    USE SIGNAL ;
    PORT
      LAYER M5 ;
        RECT  262.32 215.916 262.344 216 ;
    END
  END sv_hi[158]
  PIN sv_hi[159]
    DIRECTION OUTPUT ;
    USE SIGNAL ;
    PORT
      LAYER M5 ;
        RECT  263.808 215.916 263.832 216 ;
    END
  END sv_hi[159]
  PIN sv_hi[15]
    DIRECTION OUTPUT ;
    USE SIGNAL ;
    PORT
      LAYER M5 ;
        RECT  45.12 215.916 45.144 216 ;
    END
  END sv_hi[15]
  PIN sv_hi[160]
    DIRECTION OUTPUT ;
    USE SIGNAL ;
    PORT
      LAYER M5 ;
        RECT  265.344 215.916 265.368 216 ;
    END
  END sv_hi[160]
  PIN sv_hi[161]
    DIRECTION OUTPUT ;
    USE SIGNAL ;
    PORT
      LAYER M5 ;
        RECT  266.88 215.916 266.904 216 ;
    END
  END sv_hi[161]
  PIN sv_hi[162]
    DIRECTION OUTPUT ;
    USE SIGNAL ;
    PORT
      LAYER M5 ;
        RECT  268.368 215.916 268.392 216 ;
    END
  END sv_hi[162]
  PIN sv_hi[163]
    DIRECTION OUTPUT ;
    USE SIGNAL ;
    PORT
      LAYER M5 ;
        RECT  269.904 215.916 269.928 216 ;
    END
  END sv_hi[163]
  PIN sv_hi[164]
    DIRECTION OUTPUT ;
    USE SIGNAL ;
    PORT
      LAYER M5 ;
        RECT  271.44 215.916 271.464 216 ;
    END
  END sv_hi[164]
  PIN sv_hi[165]
    DIRECTION OUTPUT ;
    USE SIGNAL ;
    PORT
      LAYER M5 ;
        RECT  272.928 215.916 272.952 216 ;
    END
  END sv_hi[165]
  PIN sv_hi[166]
    DIRECTION OUTPUT ;
    USE SIGNAL ;
    PORT
      LAYER M5 ;
        RECT  274.464 215.916 274.488 216 ;
    END
  END sv_hi[166]
  PIN sv_hi[167]
    DIRECTION OUTPUT ;
    USE SIGNAL ;
    PORT
      LAYER M5 ;
        RECT  276 215.916 276.024 216 ;
    END
  END sv_hi[167]
  PIN sv_hi[168]
    DIRECTION OUTPUT ;
    USE SIGNAL ;
    PORT
      LAYER M5 ;
        RECT  277.488 215.916 277.512 216 ;
    END
  END sv_hi[168]
  PIN sv_hi[169]
    DIRECTION OUTPUT ;
    USE SIGNAL ;
    PORT
      LAYER M5 ;
        RECT  279.024 215.916 279.048 216 ;
    END
  END sv_hi[169]
  PIN sv_hi[16]
    DIRECTION OUTPUT ;
    USE SIGNAL ;
    PORT
      LAYER M5 ;
        RECT  46.656 215.916 46.68 216 ;
    END
  END sv_hi[16]
  PIN sv_hi[170]
    DIRECTION OUTPUT ;
    USE SIGNAL ;
    PORT
      LAYER M5 ;
        RECT  280.512 215.916 280.536 216 ;
    END
  END sv_hi[170]
  PIN sv_hi[171]
    DIRECTION OUTPUT ;
    USE SIGNAL ;
    PORT
      LAYER M5 ;
        RECT  282.048 215.916 282.072 216 ;
    END
  END sv_hi[171]
  PIN sv_hi[172]
    DIRECTION OUTPUT ;
    USE SIGNAL ;
    PORT
      LAYER M5 ;
        RECT  283.584 215.916 283.608 216 ;
    END
  END sv_hi[172]
  PIN sv_hi[173]
    DIRECTION OUTPUT ;
    USE SIGNAL ;
    PORT
      LAYER M5 ;
        RECT  285.072 215.916 285.096 216 ;
    END
  END sv_hi[173]
  PIN sv_hi[174]
    DIRECTION OUTPUT ;
    USE SIGNAL ;
    PORT
      LAYER M5 ;
        RECT  286.608 215.916 286.632 216 ;
    END
  END sv_hi[174]
  PIN sv_hi[175]
    DIRECTION OUTPUT ;
    USE SIGNAL ;
    PORT
      LAYER M5 ;
        RECT  288.144 215.916 288.168 216 ;
    END
  END sv_hi[175]
  PIN sv_hi[176]
    DIRECTION OUTPUT ;
    USE SIGNAL ;
    PORT
      LAYER M5 ;
        RECT  289.632 215.916 289.656 216 ;
    END
  END sv_hi[176]
  PIN sv_hi[177]
    DIRECTION OUTPUT ;
    USE SIGNAL ;
    PORT
      LAYER M5 ;
        RECT  291.168 215.916 291.192 216 ;
    END
  END sv_hi[177]
  PIN sv_hi[178]
    DIRECTION OUTPUT ;
    USE SIGNAL ;
    PORT
      LAYER M5 ;
        RECT  292.704 215.916 292.728 216 ;
    END
  END sv_hi[178]
  PIN sv_hi[179]
    DIRECTION OUTPUT ;
    USE SIGNAL ;
    PORT
      LAYER M5 ;
        RECT  294.192 215.916 294.216 216 ;
    END
  END sv_hi[179]
  PIN sv_hi[17]
    DIRECTION OUTPUT ;
    USE SIGNAL ;
    PORT
      LAYER M5 ;
        RECT  48.144 215.916 48.168 216 ;
    END
  END sv_hi[17]
  PIN sv_hi[180]
    DIRECTION OUTPUT ;
    USE SIGNAL ;
    PORT
      LAYER M5 ;
        RECT  295.728 215.916 295.752 216 ;
    END
  END sv_hi[180]
  PIN sv_hi[181]
    DIRECTION OUTPUT ;
    USE SIGNAL ;
    PORT
      LAYER M5 ;
        RECT  297.264 215.916 297.288 216 ;
    END
  END sv_hi[181]
  PIN sv_hi[182]
    DIRECTION OUTPUT ;
    USE SIGNAL ;
    PORT
      LAYER M5 ;
        RECT  298.752 215.916 298.776 216 ;
    END
  END sv_hi[182]
  PIN sv_hi[183]
    DIRECTION OUTPUT ;
    USE SIGNAL ;
    PORT
      LAYER M5 ;
        RECT  300.288 215.916 300.312 216 ;
    END
  END sv_hi[183]
  PIN sv_hi[184]
    DIRECTION OUTPUT ;
    USE SIGNAL ;
    PORT
      LAYER M5 ;
        RECT  301.776 215.916 301.8 216 ;
    END
  END sv_hi[184]
  PIN sv_hi[185]
    DIRECTION OUTPUT ;
    USE SIGNAL ;
    PORT
      LAYER M5 ;
        RECT  303.312 215.916 303.336 216 ;
    END
  END sv_hi[185]
  PIN sv_hi[186]
    DIRECTION OUTPUT ;
    USE SIGNAL ;
    PORT
      LAYER M5 ;
        RECT  304.848 215.916 304.872 216 ;
    END
  END sv_hi[186]
  PIN sv_hi[187]
    DIRECTION OUTPUT ;
    USE SIGNAL ;
    PORT
      LAYER M5 ;
        RECT  306.336 215.916 306.36 216 ;
    END
  END sv_hi[187]
  PIN sv_hi[188]
    DIRECTION OUTPUT ;
    USE SIGNAL ;
    PORT
      LAYER M5 ;
        RECT  307.872 215.916 307.896 216 ;
    END
  END sv_hi[188]
  PIN sv_hi[189]
    DIRECTION OUTPUT ;
    USE SIGNAL ;
    PORT
      LAYER M5 ;
        RECT  309.408 215.916 309.432 216 ;
    END
  END sv_hi[189]
  PIN sv_hi[18]
    DIRECTION OUTPUT ;
    USE SIGNAL ;
    PORT
      LAYER M5 ;
        RECT  49.68 215.916 49.704 216 ;
    END
  END sv_hi[18]
  PIN sv_hi[190]
    DIRECTION OUTPUT ;
    USE SIGNAL ;
    PORT
      LAYER M5 ;
        RECT  310.896 215.916 310.92 216 ;
    END
  END sv_hi[190]
  PIN sv_hi[191]
    DIRECTION OUTPUT ;
    USE SIGNAL ;
    PORT
      LAYER M5 ;
        RECT  312.432 215.916 312.456 216 ;
    END
  END sv_hi[191]
  PIN sv_hi[192]
    DIRECTION OUTPUT ;
    USE SIGNAL ;
    PORT
      LAYER M5 ;
        RECT  313.968 215.916 313.992 216 ;
    END
  END sv_hi[192]
  PIN sv_hi[193]
    DIRECTION OUTPUT ;
    USE SIGNAL ;
    PORT
      LAYER M5 ;
        RECT  315.456 215.916 315.48 216 ;
    END
  END sv_hi[193]
  PIN sv_hi[194]
    DIRECTION OUTPUT ;
    USE SIGNAL ;
    PORT
      LAYER M5 ;
        RECT  316.992 215.916 317.016 216 ;
    END
  END sv_hi[194]
  PIN sv_hi[195]
    DIRECTION OUTPUT ;
    USE SIGNAL ;
    PORT
      LAYER M5 ;
        RECT  318.528 215.916 318.552 216 ;
    END
  END sv_hi[195]
  PIN sv_hi[196]
    DIRECTION OUTPUT ;
    USE SIGNAL ;
    PORT
      LAYER M5 ;
        RECT  320.016 215.916 320.04 216 ;
    END
  END sv_hi[196]
  PIN sv_hi[197]
    DIRECTION OUTPUT ;
    USE SIGNAL ;
    PORT
      LAYER M5 ;
        RECT  321.552 215.916 321.576 216 ;
    END
  END sv_hi[197]
  PIN sv_hi[198]
    DIRECTION OUTPUT ;
    USE SIGNAL ;
    PORT
      LAYER M5 ;
        RECT  323.04 215.916 323.064 216 ;
    END
  END sv_hi[198]
  PIN sv_hi[199]
    DIRECTION OUTPUT ;
    USE SIGNAL ;
    PORT
      LAYER M5 ;
        RECT  324.576 215.916 324.6 216 ;
    END
  END sv_hi[199]
  PIN sv_hi[19]
    DIRECTION OUTPUT ;
    USE SIGNAL ;
    PORT
      LAYER M5 ;
        RECT  51.216 215.916 51.24 216 ;
    END
  END sv_hi[19]
  PIN sv_hi[1]
    DIRECTION OUTPUT ;
    USE SIGNAL ;
    PORT
      LAYER M5 ;
        RECT  23.856 215.916 23.88 216 ;
    END
  END sv_hi[1]
  PIN sv_hi[200]
    DIRECTION OUTPUT ;
    USE SIGNAL ;
    PORT
      LAYER M5 ;
        RECT  326.112 215.916 326.136 216 ;
    END
  END sv_hi[200]
  PIN sv_hi[201]
    DIRECTION OUTPUT ;
    USE SIGNAL ;
    PORT
      LAYER M5 ;
        RECT  327.6 215.916 327.624 216 ;
    END
  END sv_hi[201]
  PIN sv_hi[202]
    DIRECTION OUTPUT ;
    USE SIGNAL ;
    PORT
      LAYER M5 ;
        RECT  329.136 215.916 329.16 216 ;
    END
  END sv_hi[202]
  PIN sv_hi[203]
    DIRECTION OUTPUT ;
    USE SIGNAL ;
    PORT
      LAYER M5 ;
        RECT  330.672 215.916 330.696 216 ;
    END
  END sv_hi[203]
  PIN sv_hi[204]
    DIRECTION OUTPUT ;
    USE SIGNAL ;
    PORT
      LAYER M5 ;
        RECT  332.16 215.916 332.184 216 ;
    END
  END sv_hi[204]
  PIN sv_hi[205]
    DIRECTION OUTPUT ;
    USE SIGNAL ;
    PORT
      LAYER M5 ;
        RECT  333.696 215.916 333.72 216 ;
    END
  END sv_hi[205]
  PIN sv_hi[206]
    DIRECTION OUTPUT ;
    USE SIGNAL ;
    PORT
      LAYER M5 ;
        RECT  335.232 215.916 335.256 216 ;
    END
  END sv_hi[206]
  PIN sv_hi[207]
    DIRECTION OUTPUT ;
    USE SIGNAL ;
    PORT
      LAYER M5 ;
        RECT  336.72 215.916 336.744 216 ;
    END
  END sv_hi[207]
  PIN sv_hi[208]
    DIRECTION OUTPUT ;
    USE SIGNAL ;
    PORT
      LAYER M5 ;
        RECT  338.256 215.916 338.28 216 ;
    END
  END sv_hi[208]
  PIN sv_hi[209]
    DIRECTION OUTPUT ;
    USE SIGNAL ;
    PORT
      LAYER M5 ;
        RECT  339.744 215.916 339.768 216 ;
    END
  END sv_hi[209]
  PIN sv_hi[20]
    DIRECTION OUTPUT ;
    USE SIGNAL ;
    PORT
      LAYER M5 ;
        RECT  52.704 215.916 52.728 216 ;
    END
  END sv_hi[20]
  PIN sv_hi[210]
    DIRECTION OUTPUT ;
    USE SIGNAL ;
    PORT
      LAYER M5 ;
        RECT  341.28 215.916 341.304 216 ;
    END
  END sv_hi[210]
  PIN sv_hi[211]
    DIRECTION OUTPUT ;
    USE SIGNAL ;
    PORT
      LAYER M5 ;
        RECT  342.816 215.916 342.84 216 ;
    END
  END sv_hi[211]
  PIN sv_hi[212]
    DIRECTION OUTPUT ;
    USE SIGNAL ;
    PORT
      LAYER M5 ;
        RECT  344.304 215.916 344.328 216 ;
    END
  END sv_hi[212]
  PIN sv_hi[213]
    DIRECTION OUTPUT ;
    USE SIGNAL ;
    PORT
      LAYER M5 ;
        RECT  345.84 215.916 345.864 216 ;
    END
  END sv_hi[213]
  PIN sv_hi[214]
    DIRECTION OUTPUT ;
    USE SIGNAL ;
    PORT
      LAYER M5 ;
        RECT  347.376 215.916 347.4 216 ;
    END
  END sv_hi[214]
  PIN sv_hi[215]
    DIRECTION OUTPUT ;
    USE SIGNAL ;
    PORT
      LAYER M5 ;
        RECT  348.864 215.916 348.888 216 ;
    END
  END sv_hi[215]
  PIN sv_hi[216]
    DIRECTION OUTPUT ;
    USE SIGNAL ;
    PORT
      LAYER M5 ;
        RECT  350.4 215.916 350.424 216 ;
    END
  END sv_hi[216]
  PIN sv_hi[217]
    DIRECTION OUTPUT ;
    USE SIGNAL ;
    PORT
      LAYER M5 ;
        RECT  351.936 215.916 351.96 216 ;
    END
  END sv_hi[217]
  PIN sv_hi[218]
    DIRECTION OUTPUT ;
    USE SIGNAL ;
    PORT
      LAYER M5 ;
        RECT  353.424 215.916 353.448 216 ;
    END
  END sv_hi[218]
  PIN sv_hi[219]
    DIRECTION OUTPUT ;
    USE SIGNAL ;
    PORT
      LAYER M5 ;
        RECT  354.96 215.916 354.984 216 ;
    END
  END sv_hi[219]
  PIN sv_hi[21]
    DIRECTION OUTPUT ;
    USE SIGNAL ;
    PORT
      LAYER M5 ;
        RECT  54.24 215.916 54.264 216 ;
    END
  END sv_hi[21]
  PIN sv_hi[220]
    DIRECTION OUTPUT ;
    USE SIGNAL ;
    PORT
      LAYER M5 ;
        RECT  356.496 215.916 356.52 216 ;
    END
  END sv_hi[220]
  PIN sv_hi[221]
    DIRECTION OUTPUT ;
    USE SIGNAL ;
    PORT
      LAYER M5 ;
        RECT  357.984 215.916 358.008 216 ;
    END
  END sv_hi[221]
  PIN sv_hi[222]
    DIRECTION OUTPUT ;
    USE SIGNAL ;
    PORT
      LAYER M5 ;
        RECT  359.52 215.916 359.544 216 ;
    END
  END sv_hi[222]
  PIN sv_hi[223]
    DIRECTION OUTPUT ;
    USE SIGNAL ;
    PORT
      LAYER M5 ;
        RECT  361.008 215.916 361.032 216 ;
    END
  END sv_hi[223]
  PIN sv_hi[224]
    DIRECTION OUTPUT ;
    USE SIGNAL ;
    PORT
      LAYER M5 ;
        RECT  362.544 215.916 362.568 216 ;
    END
  END sv_hi[224]
  PIN sv_hi[225]
    DIRECTION OUTPUT ;
    USE SIGNAL ;
    PORT
      LAYER M5 ;
        RECT  364.08 215.916 364.104 216 ;
    END
  END sv_hi[225]
  PIN sv_hi[226]
    DIRECTION OUTPUT ;
    USE SIGNAL ;
    PORT
      LAYER M5 ;
        RECT  365.568 215.916 365.592 216 ;
    END
  END sv_hi[226]
  PIN sv_hi[227]
    DIRECTION OUTPUT ;
    USE SIGNAL ;
    PORT
      LAYER M5 ;
        RECT  367.104 215.916 367.128 216 ;
    END
  END sv_hi[227]
  PIN sv_hi[228]
    DIRECTION OUTPUT ;
    USE SIGNAL ;
    PORT
      LAYER M5 ;
        RECT  368.64 215.916 368.664 216 ;
    END
  END sv_hi[228]
  PIN sv_hi[229]
    DIRECTION OUTPUT ;
    USE SIGNAL ;
    PORT
      LAYER M5 ;
        RECT  370.128 215.916 370.152 216 ;
    END
  END sv_hi[229]
  PIN sv_hi[22]
    DIRECTION OUTPUT ;
    USE SIGNAL ;
    PORT
      LAYER M5 ;
        RECT  55.776 215.916 55.8 216 ;
    END
  END sv_hi[22]
  PIN sv_hi[230]
    DIRECTION OUTPUT ;
    USE SIGNAL ;
    PORT
      LAYER M5 ;
        RECT  371.664 215.916 371.688 216 ;
    END
  END sv_hi[230]
  PIN sv_hi[231]
    DIRECTION OUTPUT ;
    USE SIGNAL ;
    PORT
      LAYER M5 ;
        RECT  373.2 215.916 373.224 216 ;
    END
  END sv_hi[231]
  PIN sv_hi[232]
    DIRECTION OUTPUT ;
    USE SIGNAL ;
    PORT
      LAYER M5 ;
        RECT  374.688 215.916 374.712 216 ;
    END
  END sv_hi[232]
  PIN sv_hi[233]
    DIRECTION OUTPUT ;
    USE SIGNAL ;
    PORT
      LAYER M5 ;
        RECT  376.224 215.916 376.248 216 ;
    END
  END sv_hi[233]
  PIN sv_hi[234]
    DIRECTION OUTPUT ;
    USE SIGNAL ;
    PORT
      LAYER M5 ;
        RECT  377.712 215.916 377.736 216 ;
    END
  END sv_hi[234]
  PIN sv_hi[235]
    DIRECTION OUTPUT ;
    USE SIGNAL ;
    PORT
      LAYER M5 ;
        RECT  379.248 215.916 379.272 216 ;
    END
  END sv_hi[235]
  PIN sv_hi[236]
    DIRECTION OUTPUT ;
    USE SIGNAL ;
    PORT
      LAYER M5 ;
        RECT  380.784 215.916 380.808 216 ;
    END
  END sv_hi[236]
  PIN sv_hi[237]
    DIRECTION OUTPUT ;
    USE SIGNAL ;
    PORT
      LAYER M5 ;
        RECT  382.272 215.916 382.296 216 ;
    END
  END sv_hi[237]
  PIN sv_hi[238]
    DIRECTION OUTPUT ;
    USE SIGNAL ;
    PORT
      LAYER M5 ;
        RECT  383.808 215.916 383.832 216 ;
    END
  END sv_hi[238]
  PIN sv_hi[239]
    DIRECTION OUTPUT ;
    USE SIGNAL ;
    PORT
      LAYER M5 ;
        RECT  385.344 215.916 385.368 216 ;
    END
  END sv_hi[239]
  PIN sv_hi[23]
    DIRECTION OUTPUT ;
    USE SIGNAL ;
    PORT
      LAYER M5 ;
        RECT  57.264 215.916 57.288 216 ;
    END
  END sv_hi[23]
  PIN sv_hi[240]
    DIRECTION OUTPUT ;
    USE SIGNAL ;
    PORT
      LAYER M5 ;
        RECT  386.832 215.916 386.856 216 ;
    END
  END sv_hi[240]
  PIN sv_hi[241]
    DIRECTION OUTPUT ;
    USE SIGNAL ;
    PORT
      LAYER M5 ;
        RECT  388.368 215.916 388.392 216 ;
    END
  END sv_hi[241]
  PIN sv_hi[242]
    DIRECTION OUTPUT ;
    USE SIGNAL ;
    PORT
      LAYER M5 ;
        RECT  389.904 215.916 389.928 216 ;
    END
  END sv_hi[242]
  PIN sv_hi[243]
    DIRECTION OUTPUT ;
    USE SIGNAL ;
    PORT
      LAYER M5 ;
        RECT  391.392 215.916 391.416 216 ;
    END
  END sv_hi[243]
  PIN sv_hi[244]
    DIRECTION OUTPUT ;
    USE SIGNAL ;
    PORT
      LAYER M5 ;
        RECT  392.928 215.916 392.952 216 ;
    END
  END sv_hi[244]
  PIN sv_hi[245]
    DIRECTION OUTPUT ;
    USE SIGNAL ;
    PORT
      LAYER M5 ;
        RECT  394.464 215.916 394.488 216 ;
    END
  END sv_hi[245]
  PIN sv_hi[246]
    DIRECTION OUTPUT ;
    USE SIGNAL ;
    PORT
      LAYER M5 ;
        RECT  395.952 215.916 395.976 216 ;
    END
  END sv_hi[246]
  PIN sv_hi[247]
    DIRECTION OUTPUT ;
    USE SIGNAL ;
    PORT
      LAYER M5 ;
        RECT  397.488 215.916 397.512 216 ;
    END
  END sv_hi[247]
  PIN sv_hi[248]
    DIRECTION OUTPUT ;
    USE SIGNAL ;
    PORT
      LAYER M5 ;
        RECT  398.976 215.916 399 216 ;
    END
  END sv_hi[248]
  PIN sv_hi[249]
    DIRECTION OUTPUT ;
    USE SIGNAL ;
    PORT
      LAYER M5 ;
        RECT  400.512 215.916 400.536 216 ;
    END
  END sv_hi[249]
  PIN sv_hi[24]
    DIRECTION OUTPUT ;
    USE SIGNAL ;
    PORT
      LAYER M5 ;
        RECT  58.8 215.916 58.824 216 ;
    END
  END sv_hi[24]
  PIN sv_hi[250]
    DIRECTION OUTPUT ;
    USE SIGNAL ;
    PORT
      LAYER M5 ;
        RECT  402.048 215.916 402.072 216 ;
    END
  END sv_hi[250]
  PIN sv_hi[251]
    DIRECTION OUTPUT ;
    USE SIGNAL ;
    PORT
      LAYER M5 ;
        RECT  403.536 215.916 403.56 216 ;
    END
  END sv_hi[251]
  PIN sv_hi[252]
    DIRECTION OUTPUT ;
    USE SIGNAL ;
    PORT
      LAYER M5 ;
        RECT  405.072 215.916 405.096 216 ;
    END
  END sv_hi[252]
  PIN sv_hi[253]
    DIRECTION OUTPUT ;
    USE SIGNAL ;
    PORT
      LAYER M5 ;
        RECT  406.608 215.916 406.632 216 ;
    END
  END sv_hi[253]
  PIN sv_hi[254]
    DIRECTION OUTPUT ;
    USE SIGNAL ;
    PORT
      LAYER M5 ;
        RECT  408.096 215.916 408.12 216 ;
    END
  END sv_hi[254]
  PIN sv_hi[255]
    DIRECTION OUTPUT ;
    USE SIGNAL ;
    PORT
      LAYER M5 ;
        RECT  409.632 215.916 409.656 216 ;
    END
  END sv_hi[255]
  PIN sv_hi[25]
    DIRECTION OUTPUT ;
    USE SIGNAL ;
    PORT
      LAYER M5 ;
        RECT  60.336 215.916 60.36 216 ;
    END
  END sv_hi[25]
  PIN sv_hi[26]
    DIRECTION OUTPUT ;
    USE SIGNAL ;
    PORT
      LAYER M5 ;
        RECT  61.824 215.916 61.848 216 ;
    END
  END sv_hi[26]
  PIN sv_hi[27]
    DIRECTION OUTPUT ;
    USE SIGNAL ;
    PORT
      LAYER M5 ;
        RECT  63.36 215.916 63.384 216 ;
    END
  END sv_hi[27]
  PIN sv_hi[28]
    DIRECTION OUTPUT ;
    USE SIGNAL ;
    PORT
      LAYER M5 ;
        RECT  64.896 215.916 64.92 216 ;
    END
  END sv_hi[28]
  PIN sv_hi[29]
    DIRECTION OUTPUT ;
    USE SIGNAL ;
    PORT
      LAYER M5 ;
        RECT  66.384 215.916 66.408 216 ;
    END
  END sv_hi[29]
  PIN sv_hi[2]
    DIRECTION OUTPUT ;
    USE SIGNAL ;
    PORT
      LAYER M5 ;
        RECT  25.392 215.916 25.416 216 ;
    END
  END sv_hi[2]
  PIN sv_hi[30]
    DIRECTION OUTPUT ;
    USE SIGNAL ;
    PORT
      LAYER M5 ;
        RECT  67.92 215.916 67.944 216 ;
    END
  END sv_hi[30]
  PIN sv_hi[31]
    DIRECTION OUTPUT ;
    USE SIGNAL ;
    PORT
      LAYER M5 ;
        RECT  69.408 215.916 69.432 216 ;
    END
  END sv_hi[31]
  PIN sv_hi[32]
    DIRECTION OUTPUT ;
    USE SIGNAL ;
    PORT
      LAYER M5 ;
        RECT  70.944 215.916 70.968 216 ;
    END
  END sv_hi[32]
  PIN sv_hi[33]
    DIRECTION OUTPUT ;
    USE SIGNAL ;
    PORT
      LAYER M5 ;
        RECT  72.48 215.916 72.504 216 ;
    END
  END sv_hi[33]
  PIN sv_hi[34]
    DIRECTION OUTPUT ;
    USE SIGNAL ;
    PORT
      LAYER M5 ;
        RECT  73.968 215.916 73.992 216 ;
    END
  END sv_hi[34]
  PIN sv_hi[35]
    DIRECTION OUTPUT ;
    USE SIGNAL ;
    PORT
      LAYER M5 ;
        RECT  75.504 215.916 75.528 216 ;
    END
  END sv_hi[35]
  PIN sv_hi[36]
    DIRECTION OUTPUT ;
    USE SIGNAL ;
    PORT
      LAYER M5 ;
        RECT  77.04 215.916 77.064 216 ;
    END
  END sv_hi[36]
  PIN sv_hi[37]
    DIRECTION OUTPUT ;
    USE SIGNAL ;
    PORT
      LAYER M5 ;
        RECT  78.528 215.916 78.552 216 ;
    END
  END sv_hi[37]
  PIN sv_hi[38]
    DIRECTION OUTPUT ;
    USE SIGNAL ;
    PORT
      LAYER M5 ;
        RECT  80.064 215.916 80.088 216 ;
    END
  END sv_hi[38]
  PIN sv_hi[39]
    DIRECTION OUTPUT ;
    USE SIGNAL ;
    PORT
      LAYER M5 ;
        RECT  81.6 215.916 81.624 216 ;
    END
  END sv_hi[39]
  PIN sv_hi[3]
    DIRECTION OUTPUT ;
    USE SIGNAL ;
    PORT
      LAYER M5 ;
        RECT  26.928 215.916 26.952 216 ;
    END
  END sv_hi[3]
  PIN sv_hi[40]
    DIRECTION OUTPUT ;
    USE SIGNAL ;
    PORT
      LAYER M5 ;
        RECT  83.088 215.916 83.112 216 ;
    END
  END sv_hi[40]
  PIN sv_hi[41]
    DIRECTION OUTPUT ;
    USE SIGNAL ;
    PORT
      LAYER M5 ;
        RECT  84.624 215.916 84.648 216 ;
    END
  END sv_hi[41]
  PIN sv_hi[42]
    DIRECTION OUTPUT ;
    USE SIGNAL ;
    PORT
      LAYER M5 ;
        RECT  86.112 215.916 86.136 216 ;
    END
  END sv_hi[42]
  PIN sv_hi[43]
    DIRECTION OUTPUT ;
    USE SIGNAL ;
    PORT
      LAYER M5 ;
        RECT  87.648 215.916 87.672 216 ;
    END
  END sv_hi[43]
  PIN sv_hi[44]
    DIRECTION OUTPUT ;
    USE SIGNAL ;
    PORT
      LAYER M5 ;
        RECT  89.184 215.916 89.208 216 ;
    END
  END sv_hi[44]
  PIN sv_hi[45]
    DIRECTION OUTPUT ;
    USE SIGNAL ;
    PORT
      LAYER M5 ;
        RECT  90.672 215.916 90.696 216 ;
    END
  END sv_hi[45]
  PIN sv_hi[46]
    DIRECTION OUTPUT ;
    USE SIGNAL ;
    PORT
      LAYER M5 ;
        RECT  92.208 215.916 92.232 216 ;
    END
  END sv_hi[46]
  PIN sv_hi[47]
    DIRECTION OUTPUT ;
    USE SIGNAL ;
    PORT
      LAYER M5 ;
        RECT  93.744 215.916 93.768 216 ;
    END
  END sv_hi[47]
  PIN sv_hi[48]
    DIRECTION OUTPUT ;
    USE SIGNAL ;
    PORT
      LAYER M5 ;
        RECT  95.232 215.916 95.256 216 ;
    END
  END sv_hi[48]
  PIN sv_hi[49]
    DIRECTION OUTPUT ;
    USE SIGNAL ;
    PORT
      LAYER M5 ;
        RECT  96.768 215.916 96.792 216 ;
    END
  END sv_hi[49]
  PIN sv_hi[4]
    DIRECTION OUTPUT ;
    USE SIGNAL ;
    PORT
      LAYER M5 ;
        RECT  28.416 215.916 28.44 216 ;
    END
  END sv_hi[4]
  PIN sv_hi[50]
    DIRECTION OUTPUT ;
    USE SIGNAL ;
    PORT
      LAYER M5 ;
        RECT  98.304 215.916 98.328 216 ;
    END
  END sv_hi[50]
  PIN sv_hi[51]
    DIRECTION OUTPUT ;
    USE SIGNAL ;
    PORT
      LAYER M5 ;
        RECT  99.792 215.916 99.816 216 ;
    END
  END sv_hi[51]
  PIN sv_hi[52]
    DIRECTION OUTPUT ;
    USE SIGNAL ;
    PORT
      LAYER M5 ;
        RECT  101.328 215.916 101.352 216 ;
    END
  END sv_hi[52]
  PIN sv_hi[53]
    DIRECTION OUTPUT ;
    USE SIGNAL ;
    PORT
      LAYER M5 ;
        RECT  102.864 215.916 102.888 216 ;
    END
  END sv_hi[53]
  PIN sv_hi[54]
    DIRECTION OUTPUT ;
    USE SIGNAL ;
    PORT
      LAYER M5 ;
        RECT  104.352 215.916 104.376 216 ;
    END
  END sv_hi[54]
  PIN sv_hi[55]
    DIRECTION OUTPUT ;
    USE SIGNAL ;
    PORT
      LAYER M5 ;
        RECT  105.888 215.916 105.912 216 ;
    END
  END sv_hi[55]
  PIN sv_hi[56]
    DIRECTION OUTPUT ;
    USE SIGNAL ;
    PORT
      LAYER M5 ;
        RECT  107.376 215.916 107.4 216 ;
    END
  END sv_hi[56]
  PIN sv_hi[57]
    DIRECTION OUTPUT ;
    USE SIGNAL ;
    PORT
      LAYER M5 ;
        RECT  108.912 215.916 108.936 216 ;
    END
  END sv_hi[57]
  PIN sv_hi[58]
    DIRECTION OUTPUT ;
    USE SIGNAL ;
    PORT
      LAYER M5 ;
        RECT  110.448 215.916 110.472 216 ;
    END
  END sv_hi[58]
  PIN sv_hi[59]
    DIRECTION OUTPUT ;
    USE SIGNAL ;
    PORT
      LAYER M5 ;
        RECT  111.936 215.916 111.96 216 ;
    END
  END sv_hi[59]
  PIN sv_hi[5]
    DIRECTION OUTPUT ;
    USE SIGNAL ;
    PORT
      LAYER M5 ;
        RECT  29.952 215.916 29.976 216 ;
    END
  END sv_hi[5]
  PIN sv_hi[60]
    DIRECTION OUTPUT ;
    USE SIGNAL ;
    PORT
      LAYER M5 ;
        RECT  113.472 215.916 113.496 216 ;
    END
  END sv_hi[60]
  PIN sv_hi[61]
    DIRECTION OUTPUT ;
    USE SIGNAL ;
    PORT
      LAYER M5 ;
        RECT  115.008 215.916 115.032 216 ;
    END
  END sv_hi[61]
  PIN sv_hi[62]
    DIRECTION OUTPUT ;
    USE SIGNAL ;
    PORT
      LAYER M5 ;
        RECT  116.496 215.916 116.52 216 ;
    END
  END sv_hi[62]
  PIN sv_hi[63]
    DIRECTION OUTPUT ;
    USE SIGNAL ;
    PORT
      LAYER M5 ;
        RECT  118.032 215.916 118.056 216 ;
    END
  END sv_hi[63]
  PIN sv_hi[64]
    DIRECTION OUTPUT ;
    USE SIGNAL ;
    PORT
      LAYER M5 ;
        RECT  119.568 215.916 119.592 216 ;
    END
  END sv_hi[64]
  PIN sv_hi[65]
    DIRECTION OUTPUT ;
    USE SIGNAL ;
    PORT
      LAYER M5 ;
        RECT  121.056 215.916 121.08 216 ;
    END
  END sv_hi[65]
  PIN sv_hi[66]
    DIRECTION OUTPUT ;
    USE SIGNAL ;
    PORT
      LAYER M5 ;
        RECT  122.592 215.916 122.616 216 ;
    END
  END sv_hi[66]
  PIN sv_hi[67]
    DIRECTION OUTPUT ;
    USE SIGNAL ;
    PORT
      LAYER M5 ;
        RECT  124.128 215.916 124.152 216 ;
    END
  END sv_hi[67]
  PIN sv_hi[68]
    DIRECTION OUTPUT ;
    USE SIGNAL ;
    PORT
      LAYER M5 ;
        RECT  125.616 215.916 125.64 216 ;
    END
  END sv_hi[68]
  PIN sv_hi[69]
    DIRECTION OUTPUT ;
    USE SIGNAL ;
    PORT
      LAYER M5 ;
        RECT  127.152 215.916 127.176 216 ;
    END
  END sv_hi[69]
  PIN sv_hi[6]
    DIRECTION OUTPUT ;
    USE SIGNAL ;
    PORT
      LAYER M5 ;
        RECT  31.44 215.916 31.464 216 ;
    END
  END sv_hi[6]
  PIN sv_hi[70]
    DIRECTION OUTPUT ;
    USE SIGNAL ;
    PORT
      LAYER M5 ;
        RECT  128.64 215.916 128.664 216 ;
    END
  END sv_hi[70]
  PIN sv_hi[71]
    DIRECTION OUTPUT ;
    USE SIGNAL ;
    PORT
      LAYER M5 ;
        RECT  130.176 215.916 130.2 216 ;
    END
  END sv_hi[71]
  PIN sv_hi[72]
    DIRECTION OUTPUT ;
    USE SIGNAL ;
    PORT
      LAYER M5 ;
        RECT  131.712 215.916 131.736 216 ;
    END
  END sv_hi[72]
  PIN sv_hi[73]
    DIRECTION OUTPUT ;
    USE SIGNAL ;
    PORT
      LAYER M5 ;
        RECT  133.2 215.916 133.224 216 ;
    END
  END sv_hi[73]
  PIN sv_hi[74]
    DIRECTION OUTPUT ;
    USE SIGNAL ;
    PORT
      LAYER M5 ;
        RECT  134.736 215.916 134.76 216 ;
    END
  END sv_hi[74]
  PIN sv_hi[75]
    DIRECTION OUTPUT ;
    USE SIGNAL ;
    PORT
      LAYER M5 ;
        RECT  136.272 215.916 136.296 216 ;
    END
  END sv_hi[75]
  PIN sv_hi[76]
    DIRECTION OUTPUT ;
    USE SIGNAL ;
    PORT
      LAYER M5 ;
        RECT  137.76 215.916 137.784 216 ;
    END
  END sv_hi[76]
  PIN sv_hi[77]
    DIRECTION OUTPUT ;
    USE SIGNAL ;
    PORT
      LAYER M5 ;
        RECT  139.296 215.916 139.32 216 ;
    END
  END sv_hi[77]
  PIN sv_hi[78]
    DIRECTION OUTPUT ;
    USE SIGNAL ;
    PORT
      LAYER M5 ;
        RECT  140.832 215.916 140.856 216 ;
    END
  END sv_hi[78]
  PIN sv_hi[79]
    DIRECTION OUTPUT ;
    USE SIGNAL ;
    PORT
      LAYER M5 ;
        RECT  142.32 215.916 142.344 216 ;
    END
  END sv_hi[79]
  PIN sv_hi[7]
    DIRECTION OUTPUT ;
    USE SIGNAL ;
    PORT
      LAYER M5 ;
        RECT  32.976 215.916 33 216 ;
    END
  END sv_hi[7]
  PIN sv_hi[80]
    DIRECTION OUTPUT ;
    USE SIGNAL ;
    PORT
      LAYER M5 ;
        RECT  143.856 215.916 143.88 216 ;
    END
  END sv_hi[80]
  PIN sv_hi[81]
    DIRECTION OUTPUT ;
    USE SIGNAL ;
    PORT
      LAYER M5 ;
        RECT  145.344 215.916 145.368 216 ;
    END
  END sv_hi[81]
  PIN sv_hi[82]
    DIRECTION OUTPUT ;
    USE SIGNAL ;
    PORT
      LAYER M5 ;
        RECT  146.88 215.916 146.904 216 ;
    END
  END sv_hi[82]
  PIN sv_hi[83]
    DIRECTION OUTPUT ;
    USE SIGNAL ;
    PORT
      LAYER M5 ;
        RECT  148.416 215.916 148.44 216 ;
    END
  END sv_hi[83]
  PIN sv_hi[84]
    DIRECTION OUTPUT ;
    USE SIGNAL ;
    PORT
      LAYER M5 ;
        RECT  149.904 215.916 149.928 216 ;
    END
  END sv_hi[84]
  PIN sv_hi[85]
    DIRECTION OUTPUT ;
    USE SIGNAL ;
    PORT
      LAYER M5 ;
        RECT  151.44 215.916 151.464 216 ;
    END
  END sv_hi[85]
  PIN sv_hi[86]
    DIRECTION OUTPUT ;
    USE SIGNAL ;
    PORT
      LAYER M5 ;
        RECT  152.976 215.916 153 216 ;
    END
  END sv_hi[86]
  PIN sv_hi[87]
    DIRECTION OUTPUT ;
    USE SIGNAL ;
    PORT
      LAYER M5 ;
        RECT  154.464 215.916 154.488 216 ;
    END
  END sv_hi[87]
  PIN sv_hi[88]
    DIRECTION OUTPUT ;
    USE SIGNAL ;
    PORT
      LAYER M5 ;
        RECT  156 215.916 156.024 216 ;
    END
  END sv_hi[88]
  PIN sv_hi[89]
    DIRECTION OUTPUT ;
    USE SIGNAL ;
    PORT
      LAYER M5 ;
        RECT  157.536 215.916 157.56 216 ;
    END
  END sv_hi[89]
  PIN sv_hi[8]
    DIRECTION OUTPUT ;
    USE SIGNAL ;
    PORT
      LAYER M5 ;
        RECT  34.512 215.916 34.536 216 ;
    END
  END sv_hi[8]
  PIN sv_hi[90]
    DIRECTION OUTPUT ;
    USE SIGNAL ;
    PORT
      LAYER M5 ;
        RECT  159.024 215.916 159.048 216 ;
    END
  END sv_hi[90]
  PIN sv_hi[91]
    DIRECTION OUTPUT ;
    USE SIGNAL ;
    PORT
      LAYER M5 ;
        RECT  160.56 215.916 160.584 216 ;
    END
  END sv_hi[91]
  PIN sv_hi[92]
    DIRECTION OUTPUT ;
    USE SIGNAL ;
    PORT
      LAYER M5 ;
        RECT  162.096 215.916 162.12 216 ;
    END
  END sv_hi[92]
  PIN sv_hi[93]
    DIRECTION OUTPUT ;
    USE SIGNAL ;
    PORT
      LAYER M5 ;
        RECT  163.584 215.916 163.608 216 ;
    END
  END sv_hi[93]
  PIN sv_hi[94]
    DIRECTION OUTPUT ;
    USE SIGNAL ;
    PORT
      LAYER M5 ;
        RECT  165.12 215.916 165.144 216 ;
    END
  END sv_hi[94]
  PIN sv_hi[95]
    DIRECTION OUTPUT ;
    USE SIGNAL ;
    PORT
      LAYER M5 ;
        RECT  166.608 215.916 166.632 216 ;
    END
  END sv_hi[95]
  PIN sv_hi[96]
    DIRECTION OUTPUT ;
    USE SIGNAL ;
    PORT
      LAYER M5 ;
        RECT  168.144 215.916 168.168 216 ;
    END
  END sv_hi[96]
  PIN sv_hi[97]
    DIRECTION OUTPUT ;
    USE SIGNAL ;
    PORT
      LAYER M5 ;
        RECT  169.68 215.916 169.704 216 ;
    END
  END sv_hi[97]
  PIN sv_hi[98]
    DIRECTION OUTPUT ;
    USE SIGNAL ;
    PORT
      LAYER M5 ;
        RECT  171.168 215.916 171.192 216 ;
    END
  END sv_hi[98]
  PIN sv_hi[99]
    DIRECTION OUTPUT ;
    USE SIGNAL ;
    PORT
      LAYER M5 ;
        RECT  172.704 215.916 172.728 216 ;
    END
  END sv_hi[99]
  PIN sv_hi[9]
    DIRECTION OUTPUT ;
    USE SIGNAL ;
    PORT
      LAYER M5 ;
        RECT  36 215.916 36.024 216 ;
    END
  END sv_hi[9]
  PIN sv_lo[0]
    DIRECTION OUTPUT ;
    USE SIGNAL ;
    PORT
      LAYER M5 ;
        RECT  22.368 0 22.392 0.084 ;
    END
  END sv_lo[0]
  PIN sv_lo[100]
    DIRECTION OUTPUT ;
    USE SIGNAL ;
    PORT
      LAYER M5 ;
        RECT  174.24 0 174.264 0.084 ;
    END
  END sv_lo[100]
  PIN sv_lo[101]
    DIRECTION OUTPUT ;
    USE SIGNAL ;
    PORT
      LAYER M5 ;
        RECT  175.728 0 175.752 0.084 ;
    END
  END sv_lo[101]
  PIN sv_lo[102]
    DIRECTION OUTPUT ;
    USE SIGNAL ;
    PORT
      LAYER M5 ;
        RECT  177.264 0 177.288 0.084 ;
    END
  END sv_lo[102]
  PIN sv_lo[103]
    DIRECTION OUTPUT ;
    USE SIGNAL ;
    PORT
      LAYER M5 ;
        RECT  178.8 0 178.824 0.084 ;
    END
  END sv_lo[103]
  PIN sv_lo[104]
    DIRECTION OUTPUT ;
    USE SIGNAL ;
    PORT
      LAYER M5 ;
        RECT  180.288 0 180.312 0.084 ;
    END
  END sv_lo[104]
  PIN sv_lo[105]
    DIRECTION OUTPUT ;
    USE SIGNAL ;
    PORT
      LAYER M5 ;
        RECT  181.824 0 181.848 0.084 ;
    END
  END sv_lo[105]
  PIN sv_lo[106]
    DIRECTION OUTPUT ;
    USE SIGNAL ;
    PORT
      LAYER M5 ;
        RECT  183.312 0 183.336 0.084 ;
    END
  END sv_lo[106]
  PIN sv_lo[107]
    DIRECTION OUTPUT ;
    USE SIGNAL ;
    PORT
      LAYER M5 ;
        RECT  184.848 0 184.872 0.084 ;
    END
  END sv_lo[107]
  PIN sv_lo[108]
    DIRECTION OUTPUT ;
    USE SIGNAL ;
    PORT
      LAYER M5 ;
        RECT  186.384 0 186.408 0.084 ;
    END
  END sv_lo[108]
  PIN sv_lo[109]
    DIRECTION OUTPUT ;
    USE SIGNAL ;
    PORT
      LAYER M5 ;
        RECT  187.872 0 187.896 0.084 ;
    END
  END sv_lo[109]
  PIN sv_lo[10]
    DIRECTION OUTPUT ;
    USE SIGNAL ;
    PORT
      LAYER M5 ;
        RECT  37.536 0 37.56 0.084 ;
    END
  END sv_lo[10]
  PIN sv_lo[110]
    DIRECTION OUTPUT ;
    USE SIGNAL ;
    PORT
      LAYER M5 ;
        RECT  189.408 0 189.432 0.084 ;
    END
  END sv_lo[110]
  PIN sv_lo[111]
    DIRECTION OUTPUT ;
    USE SIGNAL ;
    PORT
      LAYER M5 ;
        RECT  190.944 0 190.968 0.084 ;
    END
  END sv_lo[111]
  PIN sv_lo[112]
    DIRECTION OUTPUT ;
    USE SIGNAL ;
    PORT
      LAYER M5 ;
        RECT  192.432 0 192.456 0.084 ;
    END
  END sv_lo[112]
  PIN sv_lo[113]
    DIRECTION OUTPUT ;
    USE SIGNAL ;
    PORT
      LAYER M5 ;
        RECT  193.968 0 193.992 0.084 ;
    END
  END sv_lo[113]
  PIN sv_lo[114]
    DIRECTION OUTPUT ;
    USE SIGNAL ;
    PORT
      LAYER M5 ;
        RECT  195.504 0 195.528 0.084 ;
    END
  END sv_lo[114]
  PIN sv_lo[115]
    DIRECTION OUTPUT ;
    USE SIGNAL ;
    PORT
      LAYER M5 ;
        RECT  196.992 0 197.016 0.084 ;
    END
  END sv_lo[115]
  PIN sv_lo[116]
    DIRECTION OUTPUT ;
    USE SIGNAL ;
    PORT
      LAYER M5 ;
        RECT  198.528 0 198.552 0.084 ;
    END
  END sv_lo[116]
  PIN sv_lo[117]
    DIRECTION OUTPUT ;
    USE SIGNAL ;
    PORT
      LAYER M5 ;
        RECT  200.064 0 200.088 0.084 ;
    END
  END sv_lo[117]
  PIN sv_lo[118]
    DIRECTION OUTPUT ;
    USE SIGNAL ;
    PORT
      LAYER M5 ;
        RECT  201.552 0 201.576 0.084 ;
    END
  END sv_lo[118]
  PIN sv_lo[119]
    DIRECTION OUTPUT ;
    USE SIGNAL ;
    PORT
      LAYER M5 ;
        RECT  203.088 0 203.112 0.084 ;
    END
  END sv_lo[119]
  PIN sv_lo[11]
    DIRECTION OUTPUT ;
    USE SIGNAL ;
    PORT
      LAYER M5 ;
        RECT  39.072 0 39.096 0.084 ;
    END
  END sv_lo[11]
  PIN sv_lo[120]
    DIRECTION OUTPUT ;
    USE SIGNAL ;
    PORT
      LAYER M5 ;
        RECT  204.576 0 204.6 0.084 ;
    END
  END sv_lo[120]
  PIN sv_lo[121]
    DIRECTION OUTPUT ;
    USE SIGNAL ;
    PORT
      LAYER M5 ;
        RECT  206.112 0 206.136 0.084 ;
    END
  END sv_lo[121]
  PIN sv_lo[122]
    DIRECTION OUTPUT ;
    USE SIGNAL ;
    PORT
      LAYER M5 ;
        RECT  207.648 0 207.672 0.084 ;
    END
  END sv_lo[122]
  PIN sv_lo[123]
    DIRECTION OUTPUT ;
    USE SIGNAL ;
    PORT
      LAYER M5 ;
        RECT  209.136 0 209.16 0.084 ;
    END
  END sv_lo[123]
  PIN sv_lo[124]
    DIRECTION OUTPUT ;
    USE SIGNAL ;
    PORT
      LAYER M5 ;
        RECT  210.672 0 210.696 0.084 ;
    END
  END sv_lo[124]
  PIN sv_lo[125]
    DIRECTION OUTPUT ;
    USE SIGNAL ;
    PORT
      LAYER M5 ;
        RECT  212.208 0 212.232 0.084 ;
    END
  END sv_lo[125]
  PIN sv_lo[126]
    DIRECTION OUTPUT ;
    USE SIGNAL ;
    PORT
      LAYER M5 ;
        RECT  213.696 0 213.72 0.084 ;
    END
  END sv_lo[126]
  PIN sv_lo[127]
    DIRECTION OUTPUT ;
    USE SIGNAL ;
    PORT
      LAYER M5 ;
        RECT  215.232 0 215.256 0.084 ;
    END
  END sv_lo[127]
  PIN sv_lo[128]
    DIRECTION OUTPUT ;
    USE SIGNAL ;
    PORT
      LAYER M5 ;
        RECT  216.768 0 216.792 0.084 ;
    END
  END sv_lo[128]
  PIN sv_lo[129]
    DIRECTION OUTPUT ;
    USE SIGNAL ;
    PORT
      LAYER M5 ;
        RECT  218.256 0 218.28 0.084 ;
    END
  END sv_lo[129]
  PIN sv_lo[12]
    DIRECTION OUTPUT ;
    USE SIGNAL ;
    PORT
      LAYER M5 ;
        RECT  40.56 0 40.584 0.084 ;
    END
  END sv_lo[12]
  PIN sv_lo[130]
    DIRECTION OUTPUT ;
    USE SIGNAL ;
    PORT
      LAYER M5 ;
        RECT  219.792 0 219.816 0.084 ;
    END
  END sv_lo[130]
  PIN sv_lo[131]
    DIRECTION OUTPUT ;
    USE SIGNAL ;
    PORT
      LAYER M5 ;
        RECT  221.328 0 221.352 0.084 ;
    END
  END sv_lo[131]
  PIN sv_lo[132]
    DIRECTION OUTPUT ;
    USE SIGNAL ;
    PORT
      LAYER M5 ;
        RECT  222.816 0 222.84 0.084 ;
    END
  END sv_lo[132]
  PIN sv_lo[133]
    DIRECTION OUTPUT ;
    USE SIGNAL ;
    PORT
      LAYER M5 ;
        RECT  224.352 0 224.376 0.084 ;
    END
  END sv_lo[133]
  PIN sv_lo[134]
    DIRECTION OUTPUT ;
    USE SIGNAL ;
    PORT
      LAYER M5 ;
        RECT  225.84 0 225.864 0.084 ;
    END
  END sv_lo[134]
  PIN sv_lo[135]
    DIRECTION OUTPUT ;
    USE SIGNAL ;
    PORT
      LAYER M5 ;
        RECT  227.376 0 227.4 0.084 ;
    END
  END sv_lo[135]
  PIN sv_lo[136]
    DIRECTION OUTPUT ;
    USE SIGNAL ;
    PORT
      LAYER M5 ;
        RECT  228.912 0 228.936 0.084 ;
    END
  END sv_lo[136]
  PIN sv_lo[137]
    DIRECTION OUTPUT ;
    USE SIGNAL ;
    PORT
      LAYER M5 ;
        RECT  230.4 0 230.424 0.084 ;
    END
  END sv_lo[137]
  PIN sv_lo[138]
    DIRECTION OUTPUT ;
    USE SIGNAL ;
    PORT
      LAYER M5 ;
        RECT  231.936 0 231.96 0.084 ;
    END
  END sv_lo[138]
  PIN sv_lo[139]
    DIRECTION OUTPUT ;
    USE SIGNAL ;
    PORT
      LAYER M5 ;
        RECT  233.472 0 233.496 0.084 ;
    END
  END sv_lo[139]
  PIN sv_lo[13]
    DIRECTION OUTPUT ;
    USE SIGNAL ;
    PORT
      LAYER M5 ;
        RECT  42.096 0 42.12 0.084 ;
    END
  END sv_lo[13]
  PIN sv_lo[140]
    DIRECTION OUTPUT ;
    USE SIGNAL ;
    PORT
      LAYER M5 ;
        RECT  234.96 0 234.984 0.084 ;
    END
  END sv_lo[140]
  PIN sv_lo[141]
    DIRECTION OUTPUT ;
    USE SIGNAL ;
    PORT
      LAYER M5 ;
        RECT  236.496 0 236.52 0.084 ;
    END
  END sv_lo[141]
  PIN sv_lo[142]
    DIRECTION OUTPUT ;
    USE SIGNAL ;
    PORT
      LAYER M5 ;
        RECT  238.032 0 238.056 0.084 ;
    END
  END sv_lo[142]
  PIN sv_lo[143]
    DIRECTION OUTPUT ;
    USE SIGNAL ;
    PORT
      LAYER M5 ;
        RECT  239.52 0 239.544 0.084 ;
    END
  END sv_lo[143]
  PIN sv_lo[144]
    DIRECTION OUTPUT ;
    USE SIGNAL ;
    PORT
      LAYER M5 ;
        RECT  241.056 0 241.08 0.084 ;
    END
  END sv_lo[144]
  PIN sv_lo[145]
    DIRECTION OUTPUT ;
    USE SIGNAL ;
    PORT
      LAYER M5 ;
        RECT  242.544 0 242.568 0.084 ;
    END
  END sv_lo[145]
  PIN sv_lo[146]
    DIRECTION OUTPUT ;
    USE SIGNAL ;
    PORT
      LAYER M5 ;
        RECT  244.08 0 244.104 0.084 ;
    END
  END sv_lo[146]
  PIN sv_lo[147]
    DIRECTION OUTPUT ;
    USE SIGNAL ;
    PORT
      LAYER M5 ;
        RECT  245.616 0 245.64 0.084 ;
    END
  END sv_lo[147]
  PIN sv_lo[148]
    DIRECTION OUTPUT ;
    USE SIGNAL ;
    PORT
      LAYER M5 ;
        RECT  247.104 0 247.128 0.084 ;
    END
  END sv_lo[148]
  PIN sv_lo[149]
    DIRECTION OUTPUT ;
    USE SIGNAL ;
    PORT
      LAYER M5 ;
        RECT  248.64 0 248.664 0.084 ;
    END
  END sv_lo[149]
  PIN sv_lo[14]
    DIRECTION OUTPUT ;
    USE SIGNAL ;
    PORT
      LAYER M5 ;
        RECT  43.632 0 43.656 0.084 ;
    END
  END sv_lo[14]
  PIN sv_lo[150]
    DIRECTION OUTPUT ;
    USE SIGNAL ;
    PORT
      LAYER M5 ;
        RECT  250.176 0 250.2 0.084 ;
    END
  END sv_lo[150]
  PIN sv_lo[151]
    DIRECTION OUTPUT ;
    USE SIGNAL ;
    PORT
      LAYER M5 ;
        RECT  251.664 0 251.688 0.084 ;
    END
  END sv_lo[151]
  PIN sv_lo[152]
    DIRECTION OUTPUT ;
    USE SIGNAL ;
    PORT
      LAYER M5 ;
        RECT  253.2 0 253.224 0.084 ;
    END
  END sv_lo[152]
  PIN sv_lo[153]
    DIRECTION OUTPUT ;
    USE SIGNAL ;
    PORT
      LAYER M5 ;
        RECT  254.736 0 254.76 0.084 ;
    END
  END sv_lo[153]
  PIN sv_lo[154]
    DIRECTION OUTPUT ;
    USE SIGNAL ;
    PORT
      LAYER M5 ;
        RECT  256.224 0 256.248 0.084 ;
    END
  END sv_lo[154]
  PIN sv_lo[155]
    DIRECTION OUTPUT ;
    USE SIGNAL ;
    PORT
      LAYER M5 ;
        RECT  257.76 0 257.784 0.084 ;
    END
  END sv_lo[155]
  PIN sv_lo[156]
    DIRECTION OUTPUT ;
    USE SIGNAL ;
    PORT
      LAYER M5 ;
        RECT  259.296 0 259.32 0.084 ;
    END
  END sv_lo[156]
  PIN sv_lo[157]
    DIRECTION OUTPUT ;
    USE SIGNAL ;
    PORT
      LAYER M5 ;
        RECT  260.784 0 260.808 0.084 ;
    END
  END sv_lo[157]
  PIN sv_lo[158]
    DIRECTION OUTPUT ;
    USE SIGNAL ;
    PORT
      LAYER M5 ;
        RECT  262.32 0 262.344 0.084 ;
    END
  END sv_lo[158]
  PIN sv_lo[159]
    DIRECTION OUTPUT ;
    USE SIGNAL ;
    PORT
      LAYER M5 ;
        RECT  263.808 0 263.832 0.084 ;
    END
  END sv_lo[159]
  PIN sv_lo[15]
    DIRECTION OUTPUT ;
    USE SIGNAL ;
    PORT
      LAYER M5 ;
        RECT  45.12 0 45.144 0.084 ;
    END
  END sv_lo[15]
  PIN sv_lo[160]
    DIRECTION OUTPUT ;
    USE SIGNAL ;
    PORT
      LAYER M5 ;
        RECT  265.344 0 265.368 0.084 ;
    END
  END sv_lo[160]
  PIN sv_lo[161]
    DIRECTION OUTPUT ;
    USE SIGNAL ;
    PORT
      LAYER M5 ;
        RECT  266.88 0 266.904 0.084 ;
    END
  END sv_lo[161]
  PIN sv_lo[162]
    DIRECTION OUTPUT ;
    USE SIGNAL ;
    PORT
      LAYER M5 ;
        RECT  268.368 0 268.392 0.084 ;
    END
  END sv_lo[162]
  PIN sv_lo[163]
    DIRECTION OUTPUT ;
    USE SIGNAL ;
    PORT
      LAYER M5 ;
        RECT  269.904 0 269.928 0.084 ;
    END
  END sv_lo[163]
  PIN sv_lo[164]
    DIRECTION OUTPUT ;
    USE SIGNAL ;
    PORT
      LAYER M5 ;
        RECT  271.44 0 271.464 0.084 ;
    END
  END sv_lo[164]
  PIN sv_lo[165]
    DIRECTION OUTPUT ;
    USE SIGNAL ;
    PORT
      LAYER M5 ;
        RECT  272.928 0 272.952 0.084 ;
    END
  END sv_lo[165]
  PIN sv_lo[166]
    DIRECTION OUTPUT ;
    USE SIGNAL ;
    PORT
      LAYER M5 ;
        RECT  274.464 0 274.488 0.084 ;
    END
  END sv_lo[166]
  PIN sv_lo[167]
    DIRECTION OUTPUT ;
    USE SIGNAL ;
    PORT
      LAYER M5 ;
        RECT  276 0 276.024 0.084 ;
    END
  END sv_lo[167]
  PIN sv_lo[168]
    DIRECTION OUTPUT ;
    USE SIGNAL ;
    PORT
      LAYER M5 ;
        RECT  277.488 0 277.512 0.084 ;
    END
  END sv_lo[168]
  PIN sv_lo[169]
    DIRECTION OUTPUT ;
    USE SIGNAL ;
    PORT
      LAYER M5 ;
        RECT  279.024 0 279.048 0.084 ;
    END
  END sv_lo[169]
  PIN sv_lo[16]
    DIRECTION OUTPUT ;
    USE SIGNAL ;
    PORT
      LAYER M5 ;
        RECT  46.656 0 46.68 0.084 ;
    END
  END sv_lo[16]
  PIN sv_lo[170]
    DIRECTION OUTPUT ;
    USE SIGNAL ;
    PORT
      LAYER M5 ;
        RECT  280.512 0 280.536 0.084 ;
    END
  END sv_lo[170]
  PIN sv_lo[171]
    DIRECTION OUTPUT ;
    USE SIGNAL ;
    PORT
      LAYER M5 ;
        RECT  282.048 0 282.072 0.084 ;
    END
  END sv_lo[171]
  PIN sv_lo[172]
    DIRECTION OUTPUT ;
    USE SIGNAL ;
    PORT
      LAYER M5 ;
        RECT  283.584 0 283.608 0.084 ;
    END
  END sv_lo[172]
  PIN sv_lo[173]
    DIRECTION OUTPUT ;
    USE SIGNAL ;
    PORT
      LAYER M5 ;
        RECT  285.072 0 285.096 0.084 ;
    END
  END sv_lo[173]
  PIN sv_lo[174]
    DIRECTION OUTPUT ;
    USE SIGNAL ;
    PORT
      LAYER M5 ;
        RECT  286.608 0 286.632 0.084 ;
    END
  END sv_lo[174]
  PIN sv_lo[175]
    DIRECTION OUTPUT ;
    USE SIGNAL ;
    PORT
      LAYER M5 ;
        RECT  288.144 0 288.168 0.084 ;
    END
  END sv_lo[175]
  PIN sv_lo[176]
    DIRECTION OUTPUT ;
    USE SIGNAL ;
    PORT
      LAYER M5 ;
        RECT  289.632 0 289.656 0.084 ;
    END
  END sv_lo[176]
  PIN sv_lo[177]
    DIRECTION OUTPUT ;
    USE SIGNAL ;
    PORT
      LAYER M5 ;
        RECT  291.168 0 291.192 0.084 ;
    END
  END sv_lo[177]
  PIN sv_lo[178]
    DIRECTION OUTPUT ;
    USE SIGNAL ;
    PORT
      LAYER M5 ;
        RECT  292.704 0 292.728 0.084 ;
    END
  END sv_lo[178]
  PIN sv_lo[179]
    DIRECTION OUTPUT ;
    USE SIGNAL ;
    PORT
      LAYER M5 ;
        RECT  294.192 0 294.216 0.084 ;
    END
  END sv_lo[179]
  PIN sv_lo[17]
    DIRECTION OUTPUT ;
    USE SIGNAL ;
    PORT
      LAYER M5 ;
        RECT  48.144 0 48.168 0.084 ;
    END
  END sv_lo[17]
  PIN sv_lo[180]
    DIRECTION OUTPUT ;
    USE SIGNAL ;
    PORT
      LAYER M5 ;
        RECT  295.728 0 295.752 0.084 ;
    END
  END sv_lo[180]
  PIN sv_lo[181]
    DIRECTION OUTPUT ;
    USE SIGNAL ;
    PORT
      LAYER M5 ;
        RECT  297.264 0 297.288 0.084 ;
    END
  END sv_lo[181]
  PIN sv_lo[182]
    DIRECTION OUTPUT ;
    USE SIGNAL ;
    PORT
      LAYER M5 ;
        RECT  298.752 0 298.776 0.084 ;
    END
  END sv_lo[182]
  PIN sv_lo[183]
    DIRECTION OUTPUT ;
    USE SIGNAL ;
    PORT
      LAYER M5 ;
        RECT  300.288 0 300.312 0.084 ;
    END
  END sv_lo[183]
  PIN sv_lo[184]
    DIRECTION OUTPUT ;
    USE SIGNAL ;
    PORT
      LAYER M5 ;
        RECT  301.776 0 301.8 0.084 ;
    END
  END sv_lo[184]
  PIN sv_lo[185]
    DIRECTION OUTPUT ;
    USE SIGNAL ;
    PORT
      LAYER M5 ;
        RECT  303.312 0 303.336 0.084 ;
    END
  END sv_lo[185]
  PIN sv_lo[186]
    DIRECTION OUTPUT ;
    USE SIGNAL ;
    PORT
      LAYER M5 ;
        RECT  304.848 0 304.872 0.084 ;
    END
  END sv_lo[186]
  PIN sv_lo[187]
    DIRECTION OUTPUT ;
    USE SIGNAL ;
    PORT
      LAYER M5 ;
        RECT  306.336 0 306.36 0.084 ;
    END
  END sv_lo[187]
  PIN sv_lo[188]
    DIRECTION OUTPUT ;
    USE SIGNAL ;
    PORT
      LAYER M5 ;
        RECT  307.872 0 307.896 0.084 ;
    END
  END sv_lo[188]
  PIN sv_lo[189]
    DIRECTION OUTPUT ;
    USE SIGNAL ;
    PORT
      LAYER M5 ;
        RECT  309.408 0 309.432 0.084 ;
    END
  END sv_lo[189]
  PIN sv_lo[18]
    DIRECTION OUTPUT ;
    USE SIGNAL ;
    PORT
      LAYER M5 ;
        RECT  49.68 0 49.704 0.084 ;
    END
  END sv_lo[18]
  PIN sv_lo[190]
    DIRECTION OUTPUT ;
    USE SIGNAL ;
    PORT
      LAYER M5 ;
        RECT  310.896 0 310.92 0.084 ;
    END
  END sv_lo[190]
  PIN sv_lo[191]
    DIRECTION OUTPUT ;
    USE SIGNAL ;
    PORT
      LAYER M5 ;
        RECT  312.432 0 312.456 0.084 ;
    END
  END sv_lo[191]
  PIN sv_lo[192]
    DIRECTION OUTPUT ;
    USE SIGNAL ;
    PORT
      LAYER M5 ;
        RECT  313.968 0 313.992 0.084 ;
    END
  END sv_lo[192]
  PIN sv_lo[193]
    DIRECTION OUTPUT ;
    USE SIGNAL ;
    PORT
      LAYER M5 ;
        RECT  315.456 0 315.48 0.084 ;
    END
  END sv_lo[193]
  PIN sv_lo[194]
    DIRECTION OUTPUT ;
    USE SIGNAL ;
    PORT
      LAYER M5 ;
        RECT  316.992 0 317.016 0.084 ;
    END
  END sv_lo[194]
  PIN sv_lo[195]
    DIRECTION OUTPUT ;
    USE SIGNAL ;
    PORT
      LAYER M5 ;
        RECT  318.528 0 318.552 0.084 ;
    END
  END sv_lo[195]
  PIN sv_lo[196]
    DIRECTION OUTPUT ;
    USE SIGNAL ;
    PORT
      LAYER M5 ;
        RECT  320.016 0 320.04 0.084 ;
    END
  END sv_lo[196]
  PIN sv_lo[197]
    DIRECTION OUTPUT ;
    USE SIGNAL ;
    PORT
      LAYER M5 ;
        RECT  321.552 0 321.576 0.084 ;
    END
  END sv_lo[197]
  PIN sv_lo[198]
    DIRECTION OUTPUT ;
    USE SIGNAL ;
    PORT
      LAYER M5 ;
        RECT  323.04 0 323.064 0.084 ;
    END
  END sv_lo[198]
  PIN sv_lo[199]
    DIRECTION OUTPUT ;
    USE SIGNAL ;
    PORT
      LAYER M5 ;
        RECT  324.576 0 324.6 0.084 ;
    END
  END sv_lo[199]
  PIN sv_lo[19]
    DIRECTION OUTPUT ;
    USE SIGNAL ;
    PORT
      LAYER M5 ;
        RECT  51.216 0 51.24 0.084 ;
    END
  END sv_lo[19]
  PIN sv_lo[1]
    DIRECTION OUTPUT ;
    USE SIGNAL ;
    PORT
      LAYER M5 ;
        RECT  23.856 0 23.88 0.084 ;
    END
  END sv_lo[1]
  PIN sv_lo[200]
    DIRECTION OUTPUT ;
    USE SIGNAL ;
    PORT
      LAYER M5 ;
        RECT  326.112 0 326.136 0.084 ;
    END
  END sv_lo[200]
  PIN sv_lo[201]
    DIRECTION OUTPUT ;
    USE SIGNAL ;
    PORT
      LAYER M5 ;
        RECT  327.6 0 327.624 0.084 ;
    END
  END sv_lo[201]
  PIN sv_lo[202]
    DIRECTION OUTPUT ;
    USE SIGNAL ;
    PORT
      LAYER M5 ;
        RECT  329.136 0 329.16 0.084 ;
    END
  END sv_lo[202]
  PIN sv_lo[203]
    DIRECTION OUTPUT ;
    USE SIGNAL ;
    PORT
      LAYER M5 ;
        RECT  330.672 0 330.696 0.084 ;
    END
  END sv_lo[203]
  PIN sv_lo[204]
    DIRECTION OUTPUT ;
    USE SIGNAL ;
    PORT
      LAYER M5 ;
        RECT  332.16 0 332.184 0.084 ;
    END
  END sv_lo[204]
  PIN sv_lo[205]
    DIRECTION OUTPUT ;
    USE SIGNAL ;
    PORT
      LAYER M5 ;
        RECT  333.696 0 333.72 0.084 ;
    END
  END sv_lo[205]
  PIN sv_lo[206]
    DIRECTION OUTPUT ;
    USE SIGNAL ;
    PORT
      LAYER M5 ;
        RECT  335.232 0 335.256 0.084 ;
    END
  END sv_lo[206]
  PIN sv_lo[207]
    DIRECTION OUTPUT ;
    USE SIGNAL ;
    PORT
      LAYER M5 ;
        RECT  336.72 0 336.744 0.084 ;
    END
  END sv_lo[207]
  PIN sv_lo[208]
    DIRECTION OUTPUT ;
    USE SIGNAL ;
    PORT
      LAYER M5 ;
        RECT  338.256 0 338.28 0.084 ;
    END
  END sv_lo[208]
  PIN sv_lo[209]
    DIRECTION OUTPUT ;
    USE SIGNAL ;
    PORT
      LAYER M5 ;
        RECT  339.744 0 339.768 0.084 ;
    END
  END sv_lo[209]
  PIN sv_lo[20]
    DIRECTION OUTPUT ;
    USE SIGNAL ;
    PORT
      LAYER M5 ;
        RECT  52.704 0 52.728 0.084 ;
    END
  END sv_lo[20]
  PIN sv_lo[210]
    DIRECTION OUTPUT ;
    USE SIGNAL ;
    PORT
      LAYER M5 ;
        RECT  341.28 0 341.304 0.084 ;
    END
  END sv_lo[210]
  PIN sv_lo[211]
    DIRECTION OUTPUT ;
    USE SIGNAL ;
    PORT
      LAYER M5 ;
        RECT  342.816 0 342.84 0.084 ;
    END
  END sv_lo[211]
  PIN sv_lo[212]
    DIRECTION OUTPUT ;
    USE SIGNAL ;
    PORT
      LAYER M5 ;
        RECT  344.304 0 344.328 0.084 ;
    END
  END sv_lo[212]
  PIN sv_lo[213]
    DIRECTION OUTPUT ;
    USE SIGNAL ;
    PORT
      LAYER M5 ;
        RECT  345.84 0 345.864 0.084 ;
    END
  END sv_lo[213]
  PIN sv_lo[214]
    DIRECTION OUTPUT ;
    USE SIGNAL ;
    PORT
      LAYER M5 ;
        RECT  347.376 0 347.4 0.084 ;
    END
  END sv_lo[214]
  PIN sv_lo[215]
    DIRECTION OUTPUT ;
    USE SIGNAL ;
    PORT
      LAYER M5 ;
        RECT  348.864 0 348.888 0.084 ;
    END
  END sv_lo[215]
  PIN sv_lo[216]
    DIRECTION OUTPUT ;
    USE SIGNAL ;
    PORT
      LAYER M5 ;
        RECT  350.4 0 350.424 0.084 ;
    END
  END sv_lo[216]
  PIN sv_lo[217]
    DIRECTION OUTPUT ;
    USE SIGNAL ;
    PORT
      LAYER M5 ;
        RECT  351.936 0 351.96 0.084 ;
    END
  END sv_lo[217]
  PIN sv_lo[218]
    DIRECTION OUTPUT ;
    USE SIGNAL ;
    PORT
      LAYER M5 ;
        RECT  353.424 0 353.448 0.084 ;
    END
  END sv_lo[218]
  PIN sv_lo[219]
    DIRECTION OUTPUT ;
    USE SIGNAL ;
    PORT
      LAYER M5 ;
        RECT  354.96 0 354.984 0.084 ;
    END
  END sv_lo[219]
  PIN sv_lo[21]
    DIRECTION OUTPUT ;
    USE SIGNAL ;
    PORT
      LAYER M5 ;
        RECT  54.24 0 54.264 0.084 ;
    END
  END sv_lo[21]
  PIN sv_lo[220]
    DIRECTION OUTPUT ;
    USE SIGNAL ;
    PORT
      LAYER M5 ;
        RECT  356.496 0 356.52 0.084 ;
    END
  END sv_lo[220]
  PIN sv_lo[221]
    DIRECTION OUTPUT ;
    USE SIGNAL ;
    PORT
      LAYER M5 ;
        RECT  357.984 0 358.008 0.084 ;
    END
  END sv_lo[221]
  PIN sv_lo[222]
    DIRECTION OUTPUT ;
    USE SIGNAL ;
    PORT
      LAYER M5 ;
        RECT  359.52 0 359.544 0.084 ;
    END
  END sv_lo[222]
  PIN sv_lo[223]
    DIRECTION OUTPUT ;
    USE SIGNAL ;
    PORT
      LAYER M5 ;
        RECT  361.008 0 361.032 0.084 ;
    END
  END sv_lo[223]
  PIN sv_lo[224]
    DIRECTION OUTPUT ;
    USE SIGNAL ;
    PORT
      LAYER M5 ;
        RECT  362.544 0 362.568 0.084 ;
    END
  END sv_lo[224]
  PIN sv_lo[225]
    DIRECTION OUTPUT ;
    USE SIGNAL ;
    PORT
      LAYER M5 ;
        RECT  364.08 0 364.104 0.084 ;
    END
  END sv_lo[225]
  PIN sv_lo[226]
    DIRECTION OUTPUT ;
    USE SIGNAL ;
    PORT
      LAYER M5 ;
        RECT  365.568 0 365.592 0.084 ;
    END
  END sv_lo[226]
  PIN sv_lo[227]
    DIRECTION OUTPUT ;
    USE SIGNAL ;
    PORT
      LAYER M5 ;
        RECT  367.104 0 367.128 0.084 ;
    END
  END sv_lo[227]
  PIN sv_lo[228]
    DIRECTION OUTPUT ;
    USE SIGNAL ;
    PORT
      LAYER M5 ;
        RECT  368.64 0 368.664 0.084 ;
    END
  END sv_lo[228]
  PIN sv_lo[229]
    DIRECTION OUTPUT ;
    USE SIGNAL ;
    PORT
      LAYER M5 ;
        RECT  370.128 0 370.152 0.084 ;
    END
  END sv_lo[229]
  PIN sv_lo[22]
    DIRECTION OUTPUT ;
    USE SIGNAL ;
    PORT
      LAYER M5 ;
        RECT  55.776 0 55.8 0.084 ;
    END
  END sv_lo[22]
  PIN sv_lo[230]
    DIRECTION OUTPUT ;
    USE SIGNAL ;
    PORT
      LAYER M5 ;
        RECT  371.664 0 371.688 0.084 ;
    END
  END sv_lo[230]
  PIN sv_lo[231]
    DIRECTION OUTPUT ;
    USE SIGNAL ;
    PORT
      LAYER M5 ;
        RECT  373.2 0 373.224 0.084 ;
    END
  END sv_lo[231]
  PIN sv_lo[232]
    DIRECTION OUTPUT ;
    USE SIGNAL ;
    PORT
      LAYER M5 ;
        RECT  374.688 0 374.712 0.084 ;
    END
  END sv_lo[232]
  PIN sv_lo[233]
    DIRECTION OUTPUT ;
    USE SIGNAL ;
    PORT
      LAYER M5 ;
        RECT  376.224 0 376.248 0.084 ;
    END
  END sv_lo[233]
  PIN sv_lo[234]
    DIRECTION OUTPUT ;
    USE SIGNAL ;
    PORT
      LAYER M5 ;
        RECT  377.712 0 377.736 0.084 ;
    END
  END sv_lo[234]
  PIN sv_lo[235]
    DIRECTION OUTPUT ;
    USE SIGNAL ;
    PORT
      LAYER M5 ;
        RECT  379.248 0 379.272 0.084 ;
    END
  END sv_lo[235]
  PIN sv_lo[236]
    DIRECTION OUTPUT ;
    USE SIGNAL ;
    PORT
      LAYER M5 ;
        RECT  380.784 0 380.808 0.084 ;
    END
  END sv_lo[236]
  PIN sv_lo[237]
    DIRECTION OUTPUT ;
    USE SIGNAL ;
    PORT
      LAYER M5 ;
        RECT  382.272 0 382.296 0.084 ;
    END
  END sv_lo[237]
  PIN sv_lo[238]
    DIRECTION OUTPUT ;
    USE SIGNAL ;
    PORT
      LAYER M5 ;
        RECT  383.808 0 383.832 0.084 ;
    END
  END sv_lo[238]
  PIN sv_lo[239]
    DIRECTION OUTPUT ;
    USE SIGNAL ;
    PORT
      LAYER M5 ;
        RECT  385.344 0 385.368 0.084 ;
    END
  END sv_lo[239]
  PIN sv_lo[23]
    DIRECTION OUTPUT ;
    USE SIGNAL ;
    PORT
      LAYER M5 ;
        RECT  57.264 0 57.288 0.084 ;
    END
  END sv_lo[23]
  PIN sv_lo[240]
    DIRECTION OUTPUT ;
    USE SIGNAL ;
    PORT
      LAYER M5 ;
        RECT  386.832 0 386.856 0.084 ;
    END
  END sv_lo[240]
  PIN sv_lo[241]
    DIRECTION OUTPUT ;
    USE SIGNAL ;
    PORT
      LAYER M5 ;
        RECT  388.368 0 388.392 0.084 ;
    END
  END sv_lo[241]
  PIN sv_lo[242]
    DIRECTION OUTPUT ;
    USE SIGNAL ;
    PORT
      LAYER M5 ;
        RECT  389.904 0 389.928 0.084 ;
    END
  END sv_lo[242]
  PIN sv_lo[243]
    DIRECTION OUTPUT ;
    USE SIGNAL ;
    PORT
      LAYER M5 ;
        RECT  391.392 0 391.416 0.084 ;
    END
  END sv_lo[243]
  PIN sv_lo[244]
    DIRECTION OUTPUT ;
    USE SIGNAL ;
    PORT
      LAYER M5 ;
        RECT  392.928 0 392.952 0.084 ;
    END
  END sv_lo[244]
  PIN sv_lo[245]
    DIRECTION OUTPUT ;
    USE SIGNAL ;
    PORT
      LAYER M5 ;
        RECT  394.464 0 394.488 0.084 ;
    END
  END sv_lo[245]
  PIN sv_lo[246]
    DIRECTION OUTPUT ;
    USE SIGNAL ;
    PORT
      LAYER M5 ;
        RECT  395.952 0 395.976 0.084 ;
    END
  END sv_lo[246]
  PIN sv_lo[247]
    DIRECTION OUTPUT ;
    USE SIGNAL ;
    PORT
      LAYER M5 ;
        RECT  397.488 0 397.512 0.084 ;
    END
  END sv_lo[247]
  PIN sv_lo[248]
    DIRECTION OUTPUT ;
    USE SIGNAL ;
    PORT
      LAYER M5 ;
        RECT  398.976 0 399 0.084 ;
    END
  END sv_lo[248]
  PIN sv_lo[249]
    DIRECTION OUTPUT ;
    USE SIGNAL ;
    PORT
      LAYER M5 ;
        RECT  400.512 0 400.536 0.084 ;
    END
  END sv_lo[249]
  PIN sv_lo[24]
    DIRECTION OUTPUT ;
    USE SIGNAL ;
    PORT
      LAYER M5 ;
        RECT  58.8 0 58.824 0.084 ;
    END
  END sv_lo[24]
  PIN sv_lo[250]
    DIRECTION OUTPUT ;
    USE SIGNAL ;
    PORT
      LAYER M5 ;
        RECT  402.048 0 402.072 0.084 ;
    END
  END sv_lo[250]
  PIN sv_lo[251]
    DIRECTION OUTPUT ;
    USE SIGNAL ;
    PORT
      LAYER M5 ;
        RECT  403.536 0 403.56 0.084 ;
    END
  END sv_lo[251]
  PIN sv_lo[252]
    DIRECTION OUTPUT ;
    USE SIGNAL ;
    PORT
      LAYER M5 ;
        RECT  405.072 0 405.096 0.084 ;
    END
  END sv_lo[252]
  PIN sv_lo[253]
    DIRECTION OUTPUT ;
    USE SIGNAL ;
    PORT
      LAYER M5 ;
        RECT  406.608 0 406.632 0.084 ;
    END
  END sv_lo[253]
  PIN sv_lo[254]
    DIRECTION OUTPUT ;
    USE SIGNAL ;
    PORT
      LAYER M5 ;
        RECT  408.096 0 408.12 0.084 ;
    END
  END sv_lo[254]
  PIN sv_lo[255]
    DIRECTION OUTPUT ;
    USE SIGNAL ;
    PORT
      LAYER M5 ;
        RECT  409.632 0 409.656 0.084 ;
    END
  END sv_lo[255]
  PIN sv_lo[25]
    DIRECTION OUTPUT ;
    USE SIGNAL ;
    PORT
      LAYER M5 ;
        RECT  60.336 0 60.36 0.084 ;
    END
  END sv_lo[25]
  PIN sv_lo[26]
    DIRECTION OUTPUT ;
    USE SIGNAL ;
    PORT
      LAYER M5 ;
        RECT  61.824 0 61.848 0.084 ;
    END
  END sv_lo[26]
  PIN sv_lo[27]
    DIRECTION OUTPUT ;
    USE SIGNAL ;
    PORT
      LAYER M5 ;
        RECT  63.36 0 63.384 0.084 ;
    END
  END sv_lo[27]
  PIN sv_lo[28]
    DIRECTION OUTPUT ;
    USE SIGNAL ;
    PORT
      LAYER M5 ;
        RECT  64.896 0 64.92 0.084 ;
    END
  END sv_lo[28]
  PIN sv_lo[29]
    DIRECTION OUTPUT ;
    USE SIGNAL ;
    PORT
      LAYER M5 ;
        RECT  66.384 0 66.408 0.084 ;
    END
  END sv_lo[29]
  PIN sv_lo[2]
    DIRECTION OUTPUT ;
    USE SIGNAL ;
    PORT
      LAYER M5 ;
        RECT  25.392 0 25.416 0.084 ;
    END
  END sv_lo[2]
  PIN sv_lo[30]
    DIRECTION OUTPUT ;
    USE SIGNAL ;
    PORT
      LAYER M5 ;
        RECT  67.92 0 67.944 0.084 ;
    END
  END sv_lo[30]
  PIN sv_lo[31]
    DIRECTION OUTPUT ;
    USE SIGNAL ;
    PORT
      LAYER M5 ;
        RECT  69.408 0 69.432 0.084 ;
    END
  END sv_lo[31]
  PIN sv_lo[32]
    DIRECTION OUTPUT ;
    USE SIGNAL ;
    PORT
      LAYER M5 ;
        RECT  70.944 0 70.968 0.084 ;
    END
  END sv_lo[32]
  PIN sv_lo[33]
    DIRECTION OUTPUT ;
    USE SIGNAL ;
    PORT
      LAYER M5 ;
        RECT  72.48 0 72.504 0.084 ;
    END
  END sv_lo[33]
  PIN sv_lo[34]
    DIRECTION OUTPUT ;
    USE SIGNAL ;
    PORT
      LAYER M5 ;
        RECT  73.968 0 73.992 0.084 ;
    END
  END sv_lo[34]
  PIN sv_lo[35]
    DIRECTION OUTPUT ;
    USE SIGNAL ;
    PORT
      LAYER M5 ;
        RECT  75.504 0 75.528 0.084 ;
    END
  END sv_lo[35]
  PIN sv_lo[36]
    DIRECTION OUTPUT ;
    USE SIGNAL ;
    PORT
      LAYER M5 ;
        RECT  77.04 0 77.064 0.084 ;
    END
  END sv_lo[36]
  PIN sv_lo[37]
    DIRECTION OUTPUT ;
    USE SIGNAL ;
    PORT
      LAYER M5 ;
        RECT  78.528 0 78.552 0.084 ;
    END
  END sv_lo[37]
  PIN sv_lo[38]
    DIRECTION OUTPUT ;
    USE SIGNAL ;
    PORT
      LAYER M5 ;
        RECT  80.064 0 80.088 0.084 ;
    END
  END sv_lo[38]
  PIN sv_lo[39]
    DIRECTION OUTPUT ;
    USE SIGNAL ;
    PORT
      LAYER M5 ;
        RECT  81.6 0 81.624 0.084 ;
    END
  END sv_lo[39]
  PIN sv_lo[3]
    DIRECTION OUTPUT ;
    USE SIGNAL ;
    PORT
      LAYER M5 ;
        RECT  26.928 0 26.952 0.084 ;
    END
  END sv_lo[3]
  PIN sv_lo[40]
    DIRECTION OUTPUT ;
    USE SIGNAL ;
    PORT
      LAYER M5 ;
        RECT  83.088 0 83.112 0.084 ;
    END
  END sv_lo[40]
  PIN sv_lo[41]
    DIRECTION OUTPUT ;
    USE SIGNAL ;
    PORT
      LAYER M5 ;
        RECT  84.624 0 84.648 0.084 ;
    END
  END sv_lo[41]
  PIN sv_lo[42]
    DIRECTION OUTPUT ;
    USE SIGNAL ;
    PORT
      LAYER M5 ;
        RECT  86.112 0 86.136 0.084 ;
    END
  END sv_lo[42]
  PIN sv_lo[43]
    DIRECTION OUTPUT ;
    USE SIGNAL ;
    PORT
      LAYER M5 ;
        RECT  87.648 0 87.672 0.084 ;
    END
  END sv_lo[43]
  PIN sv_lo[44]
    DIRECTION OUTPUT ;
    USE SIGNAL ;
    PORT
      LAYER M5 ;
        RECT  89.184 0 89.208 0.084 ;
    END
  END sv_lo[44]
  PIN sv_lo[45]
    DIRECTION OUTPUT ;
    USE SIGNAL ;
    PORT
      LAYER M5 ;
        RECT  90.672 0 90.696 0.084 ;
    END
  END sv_lo[45]
  PIN sv_lo[46]
    DIRECTION OUTPUT ;
    USE SIGNAL ;
    PORT
      LAYER M5 ;
        RECT  92.208 0 92.232 0.084 ;
    END
  END sv_lo[46]
  PIN sv_lo[47]
    DIRECTION OUTPUT ;
    USE SIGNAL ;
    PORT
      LAYER M5 ;
        RECT  93.744 0 93.768 0.084 ;
    END
  END sv_lo[47]
  PIN sv_lo[48]
    DIRECTION OUTPUT ;
    USE SIGNAL ;
    PORT
      LAYER M5 ;
        RECT  95.232 0 95.256 0.084 ;
    END
  END sv_lo[48]
  PIN sv_lo[49]
    DIRECTION OUTPUT ;
    USE SIGNAL ;
    PORT
      LAYER M5 ;
        RECT  96.768 0 96.792 0.084 ;
    END
  END sv_lo[49]
  PIN sv_lo[4]
    DIRECTION OUTPUT ;
    USE SIGNAL ;
    PORT
      LAYER M5 ;
        RECT  28.416 0 28.44 0.084 ;
    END
  END sv_lo[4]
  PIN sv_lo[50]
    DIRECTION OUTPUT ;
    USE SIGNAL ;
    PORT
      LAYER M5 ;
        RECT  98.304 0 98.328 0.084 ;
    END
  END sv_lo[50]
  PIN sv_lo[51]
    DIRECTION OUTPUT ;
    USE SIGNAL ;
    PORT
      LAYER M5 ;
        RECT  99.792 0 99.816 0.084 ;
    END
  END sv_lo[51]
  PIN sv_lo[52]
    DIRECTION OUTPUT ;
    USE SIGNAL ;
    PORT
      LAYER M5 ;
        RECT  101.328 0 101.352 0.084 ;
    END
  END sv_lo[52]
  PIN sv_lo[53]
    DIRECTION OUTPUT ;
    USE SIGNAL ;
    PORT
      LAYER M5 ;
        RECT  102.864 0 102.888 0.084 ;
    END
  END sv_lo[53]
  PIN sv_lo[54]
    DIRECTION OUTPUT ;
    USE SIGNAL ;
    PORT
      LAYER M5 ;
        RECT  104.352 0 104.376 0.084 ;
    END
  END sv_lo[54]
  PIN sv_lo[55]
    DIRECTION OUTPUT ;
    USE SIGNAL ;
    PORT
      LAYER M5 ;
        RECT  105.888 0 105.912 0.084 ;
    END
  END sv_lo[55]
  PIN sv_lo[56]
    DIRECTION OUTPUT ;
    USE SIGNAL ;
    PORT
      LAYER M5 ;
        RECT  107.376 0 107.4 0.084 ;
    END
  END sv_lo[56]
  PIN sv_lo[57]
    DIRECTION OUTPUT ;
    USE SIGNAL ;
    PORT
      LAYER M5 ;
        RECT  108.912 0 108.936 0.084 ;
    END
  END sv_lo[57]
  PIN sv_lo[58]
    DIRECTION OUTPUT ;
    USE SIGNAL ;
    PORT
      LAYER M5 ;
        RECT  110.448 0 110.472 0.084 ;
    END
  END sv_lo[58]
  PIN sv_lo[59]
    DIRECTION OUTPUT ;
    USE SIGNAL ;
    PORT
      LAYER M5 ;
        RECT  111.936 0 111.96 0.084 ;
    END
  END sv_lo[59]
  PIN sv_lo[5]
    DIRECTION OUTPUT ;
    USE SIGNAL ;
    PORT
      LAYER M5 ;
        RECT  29.952 0 29.976 0.084 ;
    END
  END sv_lo[5]
  PIN sv_lo[60]
    DIRECTION OUTPUT ;
    USE SIGNAL ;
    PORT
      LAYER M5 ;
        RECT  113.472 0 113.496 0.084 ;
    END
  END sv_lo[60]
  PIN sv_lo[61]
    DIRECTION OUTPUT ;
    USE SIGNAL ;
    PORT
      LAYER M5 ;
        RECT  115.008 0 115.032 0.084 ;
    END
  END sv_lo[61]
  PIN sv_lo[62]
    DIRECTION OUTPUT ;
    USE SIGNAL ;
    PORT
      LAYER M5 ;
        RECT  116.496 0 116.52 0.084 ;
    END
  END sv_lo[62]
  PIN sv_lo[63]
    DIRECTION OUTPUT ;
    USE SIGNAL ;
    PORT
      LAYER M5 ;
        RECT  118.032 0 118.056 0.084 ;
    END
  END sv_lo[63]
  PIN sv_lo[64]
    DIRECTION OUTPUT ;
    USE SIGNAL ;
    PORT
      LAYER M5 ;
        RECT  119.568 0 119.592 0.084 ;
    END
  END sv_lo[64]
  PIN sv_lo[65]
    DIRECTION OUTPUT ;
    USE SIGNAL ;
    PORT
      LAYER M5 ;
        RECT  121.056 0 121.08 0.084 ;
    END
  END sv_lo[65]
  PIN sv_lo[66]
    DIRECTION OUTPUT ;
    USE SIGNAL ;
    PORT
      LAYER M5 ;
        RECT  122.592 0 122.616 0.084 ;
    END
  END sv_lo[66]
  PIN sv_lo[67]
    DIRECTION OUTPUT ;
    USE SIGNAL ;
    PORT
      LAYER M5 ;
        RECT  124.128 0 124.152 0.084 ;
    END
  END sv_lo[67]
  PIN sv_lo[68]
    DIRECTION OUTPUT ;
    USE SIGNAL ;
    PORT
      LAYER M5 ;
        RECT  125.616 0 125.64 0.084 ;
    END
  END sv_lo[68]
  PIN sv_lo[69]
    DIRECTION OUTPUT ;
    USE SIGNAL ;
    PORT
      LAYER M5 ;
        RECT  127.152 0 127.176 0.084 ;
    END
  END sv_lo[69]
  PIN sv_lo[6]
    DIRECTION OUTPUT ;
    USE SIGNAL ;
    PORT
      LAYER M5 ;
        RECT  31.44 0 31.464 0.084 ;
    END
  END sv_lo[6]
  PIN sv_lo[70]
    DIRECTION OUTPUT ;
    USE SIGNAL ;
    PORT
      LAYER M5 ;
        RECT  128.64 0 128.664 0.084 ;
    END
  END sv_lo[70]
  PIN sv_lo[71]
    DIRECTION OUTPUT ;
    USE SIGNAL ;
    PORT
      LAYER M5 ;
        RECT  130.176 0 130.2 0.084 ;
    END
  END sv_lo[71]
  PIN sv_lo[72]
    DIRECTION OUTPUT ;
    USE SIGNAL ;
    PORT
      LAYER M5 ;
        RECT  131.712 0 131.736 0.084 ;
    END
  END sv_lo[72]
  PIN sv_lo[73]
    DIRECTION OUTPUT ;
    USE SIGNAL ;
    PORT
      LAYER M5 ;
        RECT  133.2 0 133.224 0.084 ;
    END
  END sv_lo[73]
  PIN sv_lo[74]
    DIRECTION OUTPUT ;
    USE SIGNAL ;
    PORT
      LAYER M5 ;
        RECT  134.736 0 134.76 0.084 ;
    END
  END sv_lo[74]
  PIN sv_lo[75]
    DIRECTION OUTPUT ;
    USE SIGNAL ;
    PORT
      LAYER M5 ;
        RECT  136.272 0 136.296 0.084 ;
    END
  END sv_lo[75]
  PIN sv_lo[76]
    DIRECTION OUTPUT ;
    USE SIGNAL ;
    PORT
      LAYER M5 ;
        RECT  137.76 0 137.784 0.084 ;
    END
  END sv_lo[76]
  PIN sv_lo[77]
    DIRECTION OUTPUT ;
    USE SIGNAL ;
    PORT
      LAYER M5 ;
        RECT  139.296 0 139.32 0.084 ;
    END
  END sv_lo[77]
  PIN sv_lo[78]
    DIRECTION OUTPUT ;
    USE SIGNAL ;
    PORT
      LAYER M5 ;
        RECT  140.832 0 140.856 0.084 ;
    END
  END sv_lo[78]
  PIN sv_lo[79]
    DIRECTION OUTPUT ;
    USE SIGNAL ;
    PORT
      LAYER M5 ;
        RECT  142.32 0 142.344 0.084 ;
    END
  END sv_lo[79]
  PIN sv_lo[7]
    DIRECTION OUTPUT ;
    USE SIGNAL ;
    PORT
      LAYER M5 ;
        RECT  32.976 0 33 0.084 ;
    END
  END sv_lo[7]
  PIN sv_lo[80]
    DIRECTION OUTPUT ;
    USE SIGNAL ;
    PORT
      LAYER M5 ;
        RECT  143.856 0 143.88 0.084 ;
    END
  END sv_lo[80]
  PIN sv_lo[81]
    DIRECTION OUTPUT ;
    USE SIGNAL ;
    PORT
      LAYER M5 ;
        RECT  145.344 0 145.368 0.084 ;
    END
  END sv_lo[81]
  PIN sv_lo[82]
    DIRECTION OUTPUT ;
    USE SIGNAL ;
    PORT
      LAYER M5 ;
        RECT  146.88 0 146.904 0.084 ;
    END
  END sv_lo[82]
  PIN sv_lo[83]
    DIRECTION OUTPUT ;
    USE SIGNAL ;
    PORT
      LAYER M5 ;
        RECT  148.416 0 148.44 0.084 ;
    END
  END sv_lo[83]
  PIN sv_lo[84]
    DIRECTION OUTPUT ;
    USE SIGNAL ;
    PORT
      LAYER M5 ;
        RECT  149.904 0 149.928 0.084 ;
    END
  END sv_lo[84]
  PIN sv_lo[85]
    DIRECTION OUTPUT ;
    USE SIGNAL ;
    PORT
      LAYER M5 ;
        RECT  151.44 0 151.464 0.084 ;
    END
  END sv_lo[85]
  PIN sv_lo[86]
    DIRECTION OUTPUT ;
    USE SIGNAL ;
    PORT
      LAYER M5 ;
        RECT  152.976 0 153 0.084 ;
    END
  END sv_lo[86]
  PIN sv_lo[87]
    DIRECTION OUTPUT ;
    USE SIGNAL ;
    PORT
      LAYER M5 ;
        RECT  154.464 0 154.488 0.084 ;
    END
  END sv_lo[87]
  PIN sv_lo[88]
    DIRECTION OUTPUT ;
    USE SIGNAL ;
    PORT
      LAYER M5 ;
        RECT  156 0 156.024 0.084 ;
    END
  END sv_lo[88]
  PIN sv_lo[89]
    DIRECTION OUTPUT ;
    USE SIGNAL ;
    PORT
      LAYER M5 ;
        RECT  157.536 0 157.56 0.084 ;
    END
  END sv_lo[89]
  PIN sv_lo[8]
    DIRECTION OUTPUT ;
    USE SIGNAL ;
    PORT
      LAYER M5 ;
        RECT  34.512 0 34.536 0.084 ;
    END
  END sv_lo[8]
  PIN sv_lo[90]
    DIRECTION OUTPUT ;
    USE SIGNAL ;
    PORT
      LAYER M5 ;
        RECT  159.024 0 159.048 0.084 ;
    END
  END sv_lo[90]
  PIN sv_lo[91]
    DIRECTION OUTPUT ;
    USE SIGNAL ;
    PORT
      LAYER M5 ;
        RECT  160.56 0 160.584 0.084 ;
    END
  END sv_lo[91]
  PIN sv_lo[92]
    DIRECTION OUTPUT ;
    USE SIGNAL ;
    PORT
      LAYER M5 ;
        RECT  162.096 0 162.12 0.084 ;
    END
  END sv_lo[92]
  PIN sv_lo[93]
    DIRECTION OUTPUT ;
    USE SIGNAL ;
    PORT
      LAYER M5 ;
        RECT  163.584 0 163.608 0.084 ;
    END
  END sv_lo[93]
  PIN sv_lo[94]
    DIRECTION OUTPUT ;
    USE SIGNAL ;
    PORT
      LAYER M5 ;
        RECT  165.12 0 165.144 0.084 ;
    END
  END sv_lo[94]
  PIN sv_lo[95]
    DIRECTION OUTPUT ;
    USE SIGNAL ;
    PORT
      LAYER M5 ;
        RECT  166.608 0 166.632 0.084 ;
    END
  END sv_lo[95]
  PIN sv_lo[96]
    DIRECTION OUTPUT ;
    USE SIGNAL ;
    PORT
      LAYER M5 ;
        RECT  168.144 0 168.168 0.084 ;
    END
  END sv_lo[96]
  PIN sv_lo[97]
    DIRECTION OUTPUT ;
    USE SIGNAL ;
    PORT
      LAYER M5 ;
        RECT  169.68 0 169.704 0.084 ;
    END
  END sv_lo[97]
  PIN sv_lo[98]
    DIRECTION OUTPUT ;
    USE SIGNAL ;
    PORT
      LAYER M5 ;
        RECT  171.168 0 171.192 0.084 ;
    END
  END sv_lo[98]
  PIN sv_lo[99]
    DIRECTION OUTPUT ;
    USE SIGNAL ;
    PORT
      LAYER M5 ;
        RECT  172.704 0 172.728 0.084 ;
    END
  END sv_lo[99]
  PIN sv_lo[9]
    DIRECTION OUTPUT ;
    USE SIGNAL ;
    PORT
      LAYER M5 ;
        RECT  36 0 36.024 0.084 ;
    END
  END sv_lo[9]
  PIN vf_hi[0]
    DIRECTION INPUT ;
    USE SIGNAL ;
    PORT
      LAYER M5 ;
        RECT  29.712 215.916 29.736 216 ;
    END
  END vf_hi[0]
  PIN vf_hi[10]
    DIRECTION INPUT ;
    USE SIGNAL ;
    PORT
      LAYER M5 ;
        RECT  191.664 215.916 191.688 216 ;
    END
  END vf_hi[10]
  PIN vf_hi[11]
    DIRECTION INPUT ;
    USE SIGNAL ;
    PORT
      LAYER M5 ;
        RECT  207.888 215.916 207.912 216 ;
    END
  END vf_hi[11]
  PIN vf_hi[12]
    DIRECTION INPUT ;
    USE SIGNAL ;
    PORT
      LAYER M5 ;
        RECT  224.112 215.916 224.136 216 ;
    END
  END vf_hi[12]
  PIN vf_hi[13]
    DIRECTION INPUT ;
    USE SIGNAL ;
    PORT
      LAYER M5 ;
        RECT  240.24 215.916 240.264 216 ;
    END
  END vf_hi[13]
  PIN vf_hi[14]
    DIRECTION INPUT ;
    USE SIGNAL ;
    PORT
      LAYER M5 ;
        RECT  256.512 215.916 256.536 216 ;
    END
  END vf_hi[14]
  PIN vf_hi[15]
    DIRECTION INPUT ;
    USE SIGNAL ;
    PORT
      LAYER M5 ;
        RECT  272.688 215.916 272.712 216 ;
    END
  END vf_hi[15]
  PIN vf_hi[16]
    DIRECTION INPUT ;
    USE SIGNAL ;
    PORT
      LAYER M5 ;
        RECT  288.864 215.916 288.888 216 ;
    END
  END vf_hi[16]
  PIN vf_hi[17]
    DIRECTION INPUT ;
    USE SIGNAL ;
    PORT
      LAYER M5 ;
        RECT  305.088 215.916 305.112 216 ;
    END
  END vf_hi[17]
  PIN vf_hi[18]
    DIRECTION INPUT ;
    USE SIGNAL ;
    PORT
      LAYER M5 ;
        RECT  321.312 215.916 321.336 216 ;
    END
  END vf_hi[18]
  PIN vf_hi[19]
    DIRECTION INPUT ;
    USE SIGNAL ;
    PORT
      LAYER M5 ;
        RECT  337.44 215.916 337.464 216 ;
    END
  END vf_hi[19]
  PIN vf_hi[1]
    DIRECTION INPUT ;
    USE SIGNAL ;
    PORT
      LAYER M5 ;
        RECT  45.84 215.916 45.864 216 ;
    END
  END vf_hi[1]
  PIN vf_hi[20]
    DIRECTION INPUT ;
    USE SIGNAL ;
    PORT
      LAYER M5 ;
        RECT  353.712 215.916 353.736 216 ;
    END
  END vf_hi[20]
  PIN vf_hi[21]
    DIRECTION INPUT ;
    USE SIGNAL ;
    PORT
      LAYER M5 ;
        RECT  369.888 215.916 369.912 216 ;
    END
  END vf_hi[21]
  PIN vf_hi[22]
    DIRECTION INPUT ;
    USE SIGNAL ;
    PORT
      LAYER M5 ;
        RECT  386.064 215.916 386.088 216 ;
    END
  END vf_hi[22]
  PIN vf_hi[23]
    DIRECTION INPUT ;
    USE SIGNAL ;
    PORT
      LAYER M5 ;
        RECT  402.288 215.916 402.312 216 ;
    END
  END vf_hi[23]
  PIN vf_hi[2]
    DIRECTION INPUT ;
    USE SIGNAL ;
    PORT
      LAYER M5 ;
        RECT  62.112 215.916 62.136 216 ;
    END
  END vf_hi[2]
  PIN vf_hi[3]
    DIRECTION INPUT ;
    USE SIGNAL ;
    PORT
      LAYER M5 ;
        RECT  78.288 215.916 78.312 216 ;
    END
  END vf_hi[3]
  PIN vf_hi[4]
    DIRECTION INPUT ;
    USE SIGNAL ;
    PORT
      LAYER M5 ;
        RECT  94.464 215.916 94.488 216 ;
    END
  END vf_hi[4]
  PIN vf_hi[5]
    DIRECTION INPUT ;
    USE SIGNAL ;
    PORT
      LAYER M5 ;
        RECT  110.688 215.916 110.712 216 ;
    END
  END vf_hi[5]
  PIN vf_hi[6]
    DIRECTION INPUT ;
    USE SIGNAL ;
    PORT
      LAYER M5 ;
        RECT  126.912 215.916 126.936 216 ;
    END
  END vf_hi[6]
  PIN vf_hi[7]
    DIRECTION INPUT ;
    USE SIGNAL ;
    PORT
      LAYER M5 ;
        RECT  143.04 215.916 143.064 216 ;
    END
  END vf_hi[7]
  PIN vf_hi[8]
    DIRECTION INPUT ;
    USE SIGNAL ;
    PORT
      LAYER M5 ;
        RECT  159.312 215.916 159.336 216 ;
    END
  END vf_hi[8]
  PIN vf_hi[9]
    DIRECTION INPUT ;
    USE SIGNAL ;
    PORT
      LAYER M5 ;
        RECT  175.488 215.916 175.512 216 ;
    END
  END vf_hi[9]
  PIN vf_lo[0]
    DIRECTION INPUT ;
    USE SIGNAL ;
    PORT
      LAYER M5 ;
        RECT  29.712 0 29.736 0.084 ;
    END
  END vf_lo[0]
  PIN vf_lo[10]
    DIRECTION INPUT ;
    USE SIGNAL ;
    PORT
      LAYER M5 ;
        RECT  191.664 0 191.688 0.084 ;
    END
  END vf_lo[10]
  PIN vf_lo[11]
    DIRECTION INPUT ;
    USE SIGNAL ;
    PORT
      LAYER M5 ;
        RECT  207.888 0 207.912 0.084 ;
    END
  END vf_lo[11]
  PIN vf_lo[12]
    DIRECTION INPUT ;
    USE SIGNAL ;
    PORT
      LAYER M5 ;
        RECT  224.112 0 224.136 0.084 ;
    END
  END vf_lo[12]
  PIN vf_lo[13]
    DIRECTION INPUT ;
    USE SIGNAL ;
    PORT
      LAYER M5 ;
        RECT  240.24 0 240.264 0.084 ;
    END
  END vf_lo[13]
  PIN vf_lo[14]
    DIRECTION INPUT ;
    USE SIGNAL ;
    PORT
      LAYER M5 ;
        RECT  256.512 0 256.536 0.084 ;
    END
  END vf_lo[14]
  PIN vf_lo[15]
    DIRECTION INPUT ;
    USE SIGNAL ;
    PORT
      LAYER M5 ;
        RECT  272.688 0 272.712 0.084 ;
    END
  END vf_lo[15]
  PIN vf_lo[16]
    DIRECTION INPUT ;
    USE SIGNAL ;
    PORT
      LAYER M5 ;
        RECT  288.864 0 288.888 0.084 ;
    END
  END vf_lo[16]
  PIN vf_lo[17]
    DIRECTION INPUT ;
    USE SIGNAL ;
    PORT
      LAYER M5 ;
        RECT  305.088 0 305.112 0.084 ;
    END
  END vf_lo[17]
  PIN vf_lo[18]
    DIRECTION INPUT ;
    USE SIGNAL ;
    PORT
      LAYER M5 ;
        RECT  321.312 0 321.336 0.084 ;
    END
  END vf_lo[18]
  PIN vf_lo[19]
    DIRECTION INPUT ;
    USE SIGNAL ;
    PORT
      LAYER M5 ;
        RECT  337.44 0 337.464 0.084 ;
    END
  END vf_lo[19]
  PIN vf_lo[1]
    DIRECTION INPUT ;
    USE SIGNAL ;
    PORT
      LAYER M5 ;
        RECT  45.84 0 45.864 0.084 ;
    END
  END vf_lo[1]
  PIN vf_lo[20]
    DIRECTION INPUT ;
    USE SIGNAL ;
    PORT
      LAYER M5 ;
        RECT  353.712 0 353.736 0.084 ;
    END
  END vf_lo[20]
  PIN vf_lo[21]
    DIRECTION INPUT ;
    USE SIGNAL ;
    PORT
      LAYER M5 ;
        RECT  369.888 0 369.912 0.084 ;
    END
  END vf_lo[21]
  PIN vf_lo[22]
    DIRECTION INPUT ;
    USE SIGNAL ;
    PORT
      LAYER M5 ;
        RECT  386.064 0 386.088 0.084 ;
    END
  END vf_lo[22]
  PIN vf_lo[23]
    DIRECTION INPUT ;
    USE SIGNAL ;
    PORT
      LAYER M5 ;
        RECT  402.288 0 402.312 0.084 ;
    END
  END vf_lo[23]
  PIN vf_lo[2]
    DIRECTION INPUT ;
    USE SIGNAL ;
    PORT
      LAYER M5 ;
        RECT  62.112 0 62.136 0.084 ;
    END
  END vf_lo[2]
  PIN vf_lo[3]
    DIRECTION INPUT ;
    USE SIGNAL ;
    PORT
      LAYER M5 ;
        RECT  78.288 0 78.312 0.084 ;
    END
  END vf_lo[3]
  PIN vf_lo[4]
    DIRECTION INPUT ;
    USE SIGNAL ;
    PORT
      LAYER M5 ;
        RECT  94.464 0 94.488 0.084 ;
    END
  END vf_lo[4]
  PIN vf_lo[5]
    DIRECTION INPUT ;
    USE SIGNAL ;
    PORT
      LAYER M5 ;
        RECT  110.688 0 110.712 0.084 ;
    END
  END vf_lo[5]
  PIN vf_lo[6]
    DIRECTION INPUT ;
    USE SIGNAL ;
    PORT
      LAYER M5 ;
        RECT  126.912 0 126.936 0.084 ;
    END
  END vf_lo[6]
  PIN vf_lo[7]
    DIRECTION INPUT ;
    USE SIGNAL ;
    PORT
      LAYER M5 ;
        RECT  143.04 0 143.064 0.084 ;
    END
  END vf_lo[7]
  PIN vf_lo[8]
    DIRECTION INPUT ;
    USE SIGNAL ;
    PORT
      LAYER M5 ;
        RECT  159.312 0 159.336 0.084 ;
    END
  END vf_lo[8]
  PIN vf_lo[9]
    DIRECTION INPUT ;
    USE SIGNAL ;
    PORT
      LAYER M5 ;
        RECT  175.488 0 175.512 0.084 ;
    END
  END vf_lo[9]
  PIN we[0]
    DIRECTION INPUT ;
    USE SIGNAL ;
    PORT
      LAYER M4 ;
        RECT  0 181.968 0.084 181.992 ;
    END
  END we[0]
  PIN we[10]
    DIRECTION INPUT ;
    USE SIGNAL ;
    PORT
      LAYER M4 ;
        RECT  0 185.328 0.084 185.352 ;
    END
  END we[10]
  PIN we[11]
    DIRECTION INPUT ;
    USE SIGNAL ;
    PORT
      LAYER M4 ;
        RECT  0 185.664 0.084 185.688 ;
    END
  END we[11]
  PIN we[12]
    DIRECTION INPUT ;
    USE SIGNAL ;
    PORT
      LAYER M4 ;
        RECT  0 186 0.084 186.024 ;
    END
  END we[12]
  PIN we[13]
    DIRECTION INPUT ;
    USE SIGNAL ;
    PORT
      LAYER M4 ;
        RECT  0 186.336 0.084 186.36 ;
    END
  END we[13]
  PIN we[1]
    DIRECTION INPUT ;
    USE SIGNAL ;
    PORT
      LAYER M4 ;
        RECT  0 182.304 0.084 182.328 ;
    END
  END we[1]
  PIN we[2]
    DIRECTION INPUT ;
    USE SIGNAL ;
    PORT
      LAYER M4 ;
        RECT  0 182.64 0.084 182.664 ;
    END
  END we[2]
  PIN we[3]
    DIRECTION INPUT ;
    USE SIGNAL ;
    PORT
      LAYER M4 ;
        RECT  0 182.976 0.084 183 ;
    END
  END we[3]
  PIN we[4]
    DIRECTION INPUT ;
    USE SIGNAL ;
    PORT
      LAYER M4 ;
        RECT  0 183.312 0.084 183.336 ;
    END
  END we[4]
  PIN we[5]
    DIRECTION INPUT ;
    USE SIGNAL ;
    PORT
      LAYER M4 ;
        RECT  0 183.648 0.084 183.672 ;
    END
  END we[5]
  PIN we[6]
    DIRECTION INPUT ;
    USE SIGNAL ;
    PORT
      LAYER M4 ;
        RECT  0 183.984 0.084 184.008 ;
    END
  END we[6]
  PIN we[7]
    DIRECTION INPUT ;
    USE SIGNAL ;
    PORT
      LAYER M4 ;
        RECT  0 184.32 0.084 184.344 ;
    END
  END we[7]
  PIN we[8]
    DIRECTION INPUT ;
    USE SIGNAL ;
    PORT
      LAYER M4 ;
        RECT  0 184.656 0.084 184.68 ;
    END
  END we[8]
  PIN we[9]
    DIRECTION INPUT ;
    USE SIGNAL ;
    PORT
      LAYER M4 ;
        RECT  0 184.992 0.084 185.016 ;
    END
  END we[9]
  PIN VDD
    DIRECTION INOUT ;
    USE POWER ;
    PORT
      LAYER M5 ;
        RECT  425.556 4.311 425.676 211.689 ;
        RECT  421.236 4.311 421.356 211.689 ;
        RECT  416.916 4.311 417.036 211.689 ;
        RECT  412.596 4.311 412.716 211.689 ;
        RECT  408.276 4.311 408.396 211.689 ;
        RECT  403.956 4.311 404.076 211.689 ;
        RECT  399.636 4.311 399.756 211.689 ;
        RECT  395.316 4.311 395.436 211.689 ;
        RECT  390.996 4.311 391.116 211.689 ;
        RECT  386.676 4.311 386.796 211.689 ;
        RECT  382.356 4.311 382.476 211.689 ;
        RECT  378.036 4.311 378.156 211.689 ;
        RECT  373.716 4.311 373.836 211.689 ;
        RECT  369.396 4.311 369.516 211.689 ;
        RECT  365.076 4.311 365.196 211.689 ;
        RECT  360.756 4.311 360.876 211.689 ;
        RECT  356.436 4.311 356.556 211.689 ;
        RECT  352.116 4.311 352.236 211.689 ;
        RECT  347.796 4.311 347.916 211.689 ;
        RECT  343.476 4.311 343.596 211.689 ;
        RECT  339.156 4.311 339.276 211.689 ;
        RECT  334.836 4.311 334.956 211.689 ;
        RECT  330.516 4.311 330.636 211.689 ;
        RECT  326.196 4.311 326.316 211.689 ;
        RECT  321.876 4.311 321.996 211.689 ;
        RECT  317.556 4.311 317.676 211.689 ;
        RECT  313.236 4.311 313.356 211.689 ;
        RECT  308.916 4.311 309.036 211.689 ;
        RECT  304.596 4.311 304.716 211.689 ;
        RECT  300.276 4.311 300.396 211.689 ;
        RECT  295.956 4.311 296.076 211.689 ;
        RECT  291.636 4.311 291.756 211.689 ;
        RECT  287.316 4.311 287.436 211.689 ;
        RECT  282.996 4.311 283.116 211.689 ;
        RECT  278.676 4.311 278.796 211.689 ;
        RECT  274.356 4.311 274.476 211.689 ;
        RECT  270.036 4.311 270.156 211.689 ;
        RECT  265.716 4.311 265.836 211.689 ;
        RECT  261.396 4.311 261.516 211.689 ;
        RECT  257.076 4.311 257.196 211.689 ;
        RECT  252.756 4.311 252.876 211.689 ;
        RECT  248.436 4.311 248.556 211.689 ;
        RECT  244.116 4.311 244.236 211.689 ;
        RECT  239.796 4.311 239.916 211.689 ;
        RECT  235.476 4.311 235.596 211.689 ;
        RECT  231.156 4.311 231.276 211.689 ;
        RECT  226.836 4.311 226.956 211.689 ;
        RECT  222.516 4.311 222.636 211.689 ;
        RECT  218.196 4.311 218.316 211.689 ;
        RECT  213.876 4.311 213.996 211.689 ;
        RECT  209.556 4.311 209.676 211.689 ;
        RECT  205.236 4.311 205.356 211.689 ;
        RECT  200.916 4.311 201.036 211.689 ;
        RECT  196.596 4.311 196.716 211.689 ;
        RECT  192.276 4.311 192.396 211.689 ;
        RECT  187.956 4.311 188.076 211.689 ;
        RECT  183.636 4.311 183.756 211.689 ;
        RECT  179.316 4.311 179.436 211.689 ;
        RECT  174.996 4.311 175.116 211.689 ;
        RECT  170.676 4.311 170.796 211.689 ;
        RECT  166.356 4.311 166.476 211.689 ;
        RECT  162.036 4.311 162.156 211.689 ;
        RECT  157.716 4.311 157.836 211.689 ;
        RECT  153.396 4.311 153.516 211.689 ;
        RECT  149.076 4.311 149.196 211.689 ;
        RECT  144.756 4.311 144.876 211.689 ;
        RECT  140.436 4.311 140.556 211.689 ;
        RECT  136.116 4.311 136.236 211.689 ;
        RECT  131.796 4.311 131.916 211.689 ;
        RECT  127.476 4.311 127.596 211.689 ;
        RECT  123.156 4.311 123.276 211.689 ;
        RECT  118.836 4.311 118.956 211.689 ;
        RECT  114.516 4.311 114.636 211.689 ;
        RECT  110.196 4.311 110.316 211.689 ;
        RECT  105.876 4.311 105.996 211.689 ;
        RECT  101.556 4.311 101.676 211.689 ;
        RECT  97.236 4.311 97.356 211.689 ;
        RECT  92.916 4.311 93.036 211.689 ;
        RECT  88.596 4.311 88.716 211.689 ;
        RECT  84.276 4.311 84.396 211.689 ;
        RECT  79.956 4.311 80.076 211.689 ;
        RECT  75.636 4.311 75.756 211.689 ;
        RECT  71.316 4.311 71.436 211.689 ;
        RECT  66.996 4.311 67.116 211.689 ;
        RECT  62.676 4.311 62.796 211.689 ;
        RECT  58.356 4.311 58.476 211.689 ;
        RECT  54.036 4.311 54.156 211.689 ;
        RECT  49.716 4.311 49.836 211.689 ;
        RECT  45.396 4.311 45.516 211.689 ;
        RECT  41.076 4.311 41.196 211.689 ;
        RECT  36.756 4.311 36.876 211.689 ;
        RECT  32.436 4.311 32.556 211.689 ;
        RECT  28.116 4.311 28.236 211.689 ;
        RECT  23.796 4.311 23.916 211.689 ;
        RECT  19.476 4.311 19.596 211.689 ;
        RECT  15.156 4.311 15.276 211.689 ;
        RECT  10.836 4.311 10.956 211.689 ;
        RECT  6.516 4.311 6.636 211.689 ;
    END
  END VDD
  PIN VSS
    DIRECTION INOUT ;
    USE GROUND ;
    PORT
      LAYER M5 ;
        RECT  425.364 4.297 425.484 211.703 ;
        RECT  421.044 4.297 421.164 211.703 ;
        RECT  416.724 4.297 416.844 211.703 ;
        RECT  412.404 4.297 412.524 211.703 ;
        RECT  408.084 4.297 408.204 211.703 ;
        RECT  403.764 4.297 403.884 211.703 ;
        RECT  399.444 4.297 399.564 211.703 ;
        RECT  395.124 4.297 395.244 211.703 ;
        RECT  390.804 4.297 390.924 211.703 ;
        RECT  386.484 4.297 386.604 211.703 ;
        RECT  382.164 4.297 382.284 211.703 ;
        RECT  377.844 4.297 377.964 211.703 ;
        RECT  373.524 4.297 373.644 211.703 ;
        RECT  369.204 4.297 369.324 211.703 ;
        RECT  364.884 4.297 365.004 211.703 ;
        RECT  360.564 4.297 360.684 211.703 ;
        RECT  356.244 4.297 356.364 211.703 ;
        RECT  351.924 4.297 352.044 211.703 ;
        RECT  347.604 4.297 347.724 211.703 ;
        RECT  343.284 4.297 343.404 211.703 ;
        RECT  338.964 4.297 339.084 211.703 ;
        RECT  334.644 4.297 334.764 211.703 ;
        RECT  330.324 4.297 330.444 211.703 ;
        RECT  326.004 4.297 326.124 211.703 ;
        RECT  321.684 4.297 321.804 211.703 ;
        RECT  317.364 4.297 317.484 211.703 ;
        RECT  313.044 4.297 313.164 211.703 ;
        RECT  308.724 4.297 308.844 211.703 ;
        RECT  304.404 4.297 304.524 211.703 ;
        RECT  300.084 4.297 300.204 211.703 ;
        RECT  295.764 4.297 295.884 211.703 ;
        RECT  291.444 4.297 291.564 211.703 ;
        RECT  287.124 4.297 287.244 211.703 ;
        RECT  282.804 4.297 282.924 211.703 ;
        RECT  278.484 4.297 278.604 211.703 ;
        RECT  274.164 4.297 274.284 211.703 ;
        RECT  269.844 4.297 269.964 211.703 ;
        RECT  265.524 4.297 265.644 211.703 ;
        RECT  261.204 4.297 261.324 211.703 ;
        RECT  256.884 4.297 257.004 211.703 ;
        RECT  252.564 4.297 252.684 211.703 ;
        RECT  248.244 4.297 248.364 211.703 ;
        RECT  243.924 4.297 244.044 211.703 ;
        RECT  239.604 4.297 239.724 211.703 ;
        RECT  235.284 4.297 235.404 211.703 ;
        RECT  230.964 4.297 231.084 211.703 ;
        RECT  226.644 4.297 226.764 211.703 ;
        RECT  222.324 4.297 222.444 211.703 ;
        RECT  218.004 4.297 218.124 211.703 ;
        RECT  213.684 4.297 213.804 211.703 ;
        RECT  209.364 4.297 209.484 211.703 ;
        RECT  205.044 4.297 205.164 211.703 ;
        RECT  200.724 4.297 200.844 211.703 ;
        RECT  196.404 4.297 196.524 211.703 ;
        RECT  192.084 4.297 192.204 211.703 ;
        RECT  187.764 4.297 187.884 211.703 ;
        RECT  183.444 4.297 183.564 211.703 ;
        RECT  179.124 4.297 179.244 211.703 ;
        RECT  174.804 4.297 174.924 211.703 ;
        RECT  170.484 4.297 170.604 211.703 ;
        RECT  166.164 4.297 166.284 211.703 ;
        RECT  161.844 4.297 161.964 211.703 ;
        RECT  157.524 4.297 157.644 211.703 ;
        RECT  153.204 4.297 153.324 211.703 ;
        RECT  148.884 4.297 149.004 211.703 ;
        RECT  144.564 4.297 144.684 211.703 ;
        RECT  140.244 4.297 140.364 211.703 ;
        RECT  135.924 4.297 136.044 211.703 ;
        RECT  131.604 4.297 131.724 211.703 ;
        RECT  127.284 4.297 127.404 211.703 ;
        RECT  122.964 4.297 123.084 211.703 ;
        RECT  118.644 4.297 118.764 211.703 ;
        RECT  114.324 4.297 114.444 211.703 ;
        RECT  110.004 4.297 110.124 211.703 ;
        RECT  105.684 4.297 105.804 211.703 ;
        RECT  101.364 4.297 101.484 211.703 ;
        RECT  97.044 4.297 97.164 211.703 ;
        RECT  92.724 4.297 92.844 211.703 ;
        RECT  88.404 4.297 88.524 211.703 ;
        RECT  84.084 4.297 84.204 211.703 ;
        RECT  79.764 4.297 79.884 211.703 ;
        RECT  75.444 4.297 75.564 211.703 ;
        RECT  71.124 4.297 71.244 211.703 ;
        RECT  66.804 4.297 66.924 211.703 ;
        RECT  62.484 4.297 62.604 211.703 ;
        RECT  58.164 4.297 58.284 211.703 ;
        RECT  53.844 4.297 53.964 211.703 ;
        RECT  49.524 4.297 49.644 211.703 ;
        RECT  45.204 4.297 45.324 211.703 ;
        RECT  40.884 4.297 41.004 211.703 ;
        RECT  36.564 4.297 36.684 211.703 ;
        RECT  32.244 4.297 32.364 211.703 ;
        RECT  27.924 4.297 28.044 211.703 ;
        RECT  23.604 4.297 23.724 211.703 ;
        RECT  19.284 4.297 19.404 211.703 ;
        RECT  14.964 4.297 15.084 211.703 ;
        RECT  10.644 4.297 10.764 211.703 ;
        RECT  6.324 4.297 6.444 211.703 ;
    END
  END VSS
  OBS
    LAYER RVTN ;
     RECT  0 0 432 216 ;
    LAYER RVTP ;
     RECT  0 0 432 216 ;
    LAYER M1 ;
     RECT  0 0 432 216 ;
    LAYER M2 ;
     RECT  0 0 432 216 ;
    LAYER M3 ;
     RECT  0 0 432 216 ;
    LAYER M4 ;
     RECT  0 0 432 216 ;
    LAYER M5 ;
     RECT  0 0 432 216 ;
    LAYER M6 ;
     RECT  0 0 432 216 ;
  END
END dsdv_gunit_l1f_bf
END LIBRARY
